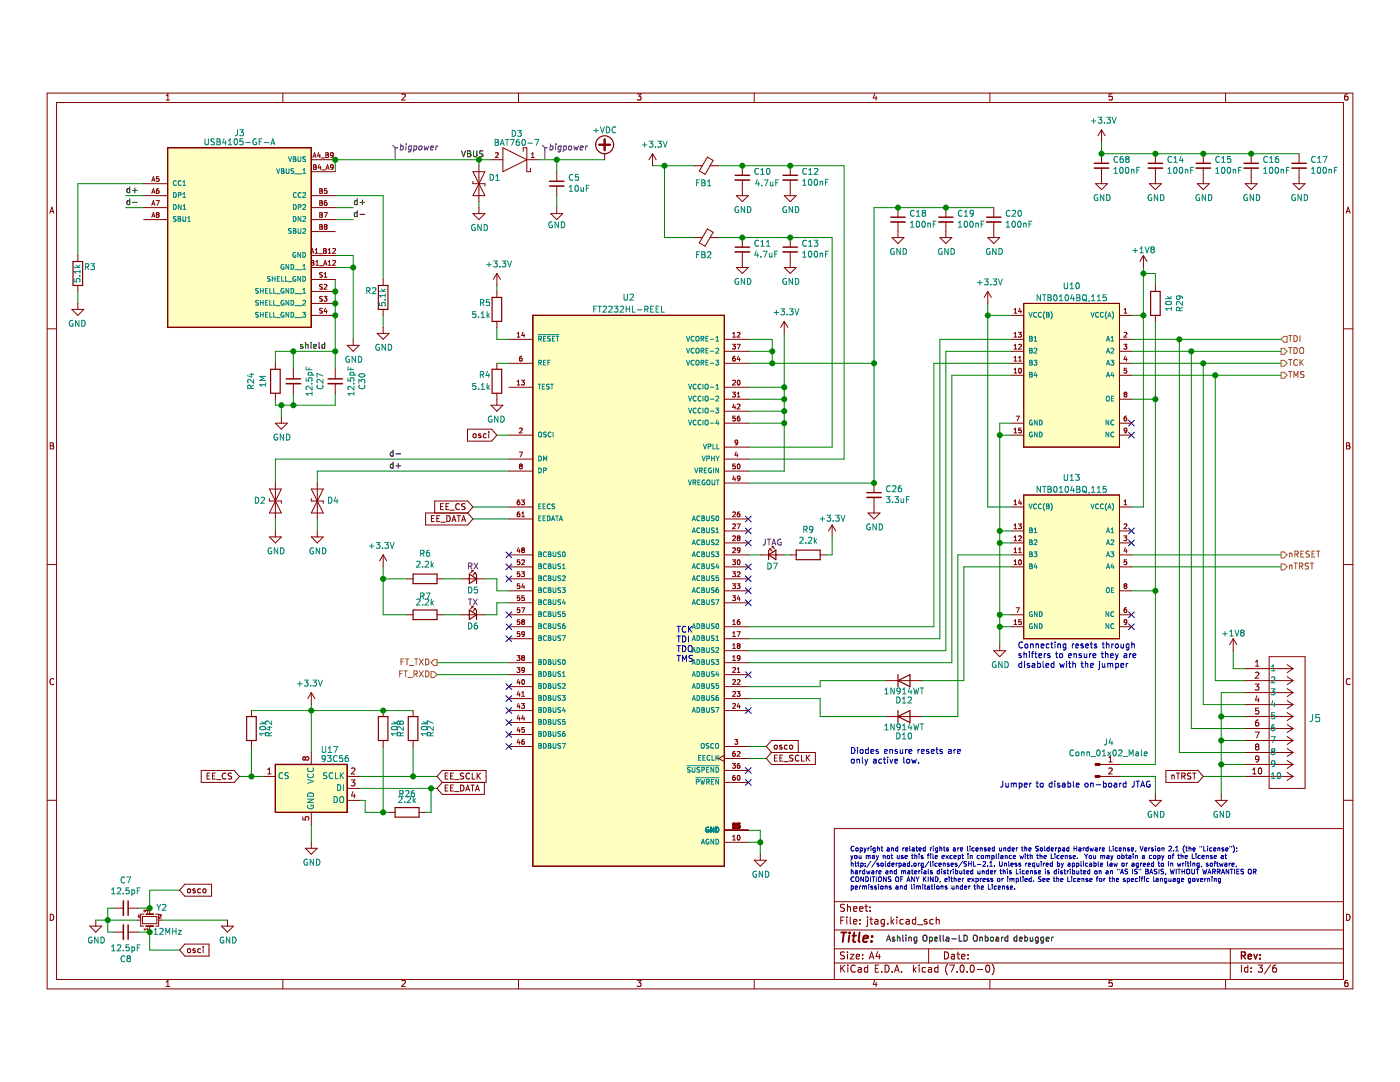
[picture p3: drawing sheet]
<svg xmlns="http://www.w3.org/2000/svg" width="279mm" height="216mm" viewBox="0 0 279 216" stroke-linecap="round" stroke-linejoin="round" font-family="sans-serif">
<path d="M0 9.2h279.4v206.7h-279.4z" fill-rule="evenodd" fill="#fff" stroke="#fff" stroke-width=".35"/>
<g fill="none" stroke="#840000" stroke-width=".2">
<path d="M9.4 18.6h260.6v178.7h-260.6zM33.2 20h.7M33.2 19.1l.3-.4v1.3M56.4 18.6v1.9M80.2 18.9l.5-.2 .2 .4-.8 .9h.8M103.5 18.6v1.9M127.2 18.7h.7l-.4 .5 .4 .1v.6l-.2 .1-.5-.1M150.5 18.6v1.9M174.6 18.7l-.3 .9h.7M174.9 19.2v.8M197.6 18.6v1.9M221.9 18.7h-.5l-.1 .6h.6v.6l-.1 .1-.5-.1"/>
<path d="M244.6 18.6v1.9M268.9 18.7l-.3 .1-.2 .2-.1 .7 .3 .3 .4-.1-.1-.6-.3-.1-.3 .2M11.3 20.5h256.8v174.9h-256.8zM28.7 36.7h4.8M28.7 39h4.8M30.3 36.2l.3-1 .3 1M30.3 38.6l.3-1 .3 1M30.4 35.9h.4M30.4 38.3h.4M31.7 37.6l-.5 .3v.5l.2 .2 .3-.1v-.5h-.3l-.2 .2M31.7 35.2h-.5v.5h.5v.4h-.5M62.1 34.3h4.8"/>
<path d="M62.1 31.9h4.8M62.1 39h4.8M62.4 31.4l.4-.9 .3 .9M62.5 31.2h.5M62.6 32.9h.3l.2 .1-.2 .3 .2 .3-.2 .2h-.3zM62.6 33.3h.3M63.6 30.4l-.2 .7h.5M63.7 32.8l-.2 .7h.6M63.8 30.8v.6M63.8 37.6h.3l.2 .2-.2 .3 .3 .3-.2 .2h-.4zM63.8 38.1h.3M63.9 33.2v.6"/>
<path d="M64.1 31.5h.7M64.2 33.9h.7M65 33.8l.4-.9 .3 .9M65 30.5h.4l.1 .2-.1 .2 .2 .3-.2 .2h-.4zM65 30.9h.4M65.1 33.5h.5M65.2 37.6h-.4l-.1 .5 .5-.1v.5h-.5M66.5 33.3l-.2 .1h-.3v-.5h.3l.2 .1v.6l-.5 .2M66.5 30.9l-.2 .2-.3-.1v-.4l.3-.1 .2 .2v.5l-.5 .2M94.4 36.2v.5h2.4v.4M94.4 34.3h2.4l-2.4 4.7h2.4zM95.6 33.1v7.1"/>
<path d="M98 31.9h2.4M98.9 30.6l.4-.1 .1 .2-.6 .7h.6M100.4 29.5l4.7 2.4-4.7 2.4zM104.4 30.2v-.7h.7v4.8h.8v-.8M105.1 31.9h2.4M106.1 31.4h.5M106.1 30.7l.2-.2v.9M111.1 34.3v1.9M111.1 37.1v1.9M120.7 30.7v1.2M130.2 30.7l-.7 1.2M130.2 30.7v2.4"/>
<path d="M130.2 30.7l.7 1.2M138.6 33.1h1.5M141.2 31.3l1.1 .7-1.6 2.8-1.1-.7zM141.7 33.1h1.7M147 39h2.3l-1.2 1.2zM148.1 33.1v1.9M148.1 35.9v3.1M156.5 39h2.4l-1.2 1.2zM157.7 33.1v1.9M157.7 35.9v3.1M218.6 36.7h2.4l-1.2 1.1zM219.8 25.9l-.7 1.2"/>
<path d="M219.8 25.9v2.4M219.8 30.7v1.9M219.8 33.5v3.2M219.8 25.9l.7 1.2M229.4 36.7h2.4l-1.2 1.1zM230.6 30.7v1.9M230.6 33.5v3.2M238.9 36.7h2.4l-1.2 1.1zM240.1 30.7v1.9M240.1 33.5v3.2M248.5 36.7h2.4l-1.2 1.1zM249.7 30.7v1.9"/>
<path d="M249.7 33.5v3.2M258.1 36.7h2.4l-1.2 1.1zM259.3 30.7v1.9M259.3 33.5v3.2M9.9 42.5l.5-1.2 .4 1.2M10.1 42.2h.5M15.5 51v1.2M15.5 57v1.2M28.7 41.4h4.8M28.7 43.8h4.8M30.3 41l.3-1 .3 1M30.3 43.4l.3-1 .3 1"/>
<path d="M30.4 40.7h.4M30.4 43.1h.4M31.2 40h.6l-.4 1M31.4 42.8l-.2-.2 .2-.2 .3 .2-.1 .2M31.4 42.8l-.2 .2 .2 .4 .3-.2-.1-.4M31.4 42.8h.2M62 50.5l.3-.9 .3 .9M62.1 50.3h.4M62.1 51h4.8M62.1 52h.3l.2 .2-.2 .2 .3 .3-.2 .2h-.4zM62.1 41.4h4.8M62.1 43.8h4.8"/>
<path d="M62.1 53.4h4.8M62.1 52.4h.3M62.1 46.2h4.8M62.1 55.8h4.8M62.1 58.2h4.8M62.9 50.5h.5M62.9 49.9l.3-.3v.9M63 52.9h.6M63 52.2l.3-.2v.9M63.6 50.6h.8M63.8 53h.7M63.8 40h.3l.2 .2-.2 .3 .3 .3-.2 .2h-.4z"/>
<path d="M63.8 42.4h.3l.2 .2-.2 .3 .3 .3-.2 .2h-.4zM63.8 44.8h.3l.2 .2-.2 .3 .3 .3-.2 .2h-.4zM63.8 40.5h.3M63.8 42.9h.3M63.8 45.3h.3M64.3 54.4l-.5 .1a.4 .4 0 0 0 .5 .5l-.1 .3h-.4M64.3 56.8h-.5a.4 .4 0 0 0 .5 .5l-.1 .4h-.4M64.3 59.2h-.5a.4 .4 0 0 0 .5 .5l-.1 .4h-.4M64.6 52.9l.3-.9 .3 .9M64.6 49.6h.3l.2 .2-.2 .2 .2 .4-.2 .1h-.3zM64.6 50h.3M64.7 59.1h.5l-.3 .4 .3 .1v.4h-.5"/>
<path d="M64.7 42.4h.6l-.4 1M64.7 52.7h.4M64.7 56.8h.4l.1 .2-.5 .7h.5M64.7 55.3h.5M64.7 54.6l.3-.2v.9M64.9 45.2l-.2-.2 .2-.2 .4 .2-.2 .2M64.9 45.2l-.2 .2 .2 .4 .4-.2-.2-.4M64.9 45.2h.2M65.2 40l-.4 .3-.1 .5 .2 .2 .3-.1v-.5h-.3l-.2 .2M65.5 50.5h.5M65.5 49.9l.3-.3v.9M65.5 52.2l.3-.2v.9"/>
<path d="M65.5 52.9h.5M66.4 49.7l.4-.1 .2 .3-.6 .6h.6M66.4 52.1l.4-.1 .2 .2-.6 .7h.6M76.5 55.8v1.2M94.4 42.6h2.4l-1.2 1.2zM95.6 41.4v1.2M99.2 54.6v2.4M99.2 58.2v1.2M99.2 54.6l-.8 1.2M99.2 54.6l.7 1.2M109.9 42.6h2.4l-1.2 1.2zM111.1 41.4v1.2"/>
<path d="M138.6 47.4h1.5M141.2 45.7l1.1 .7-1.6 2.7-1.1-.6zM141.7 47.4h1.7M147 53.4h2.3l-1.2 1.2zM148.1 47.4v1.9M148.1 50.3v3.1M156.5 53.4h2.4l-1.2 1.2zM157.7 47.4v1.9M157.7 50.3v3.1M178 47.4h2.4l-1.2 1.2zM179.2 41.4v1.9M179.2 44.3v3.1"/>
<path d="M187.6 47.4h2.4l-1.2 1.2zM188.8 41.4v1.9M188.8 44.3v3.1M197.1 47.4h2.4l-1.2 1.2zM197.1 58.2l-.7 1.2M197.1 58.2v2.3M197.1 58.2l.7 1.2M198.3 41.4v1.9M198.3 44.3v3.1M228.2 51l-.7 1.2M228.2 51v2.4M228.2 51l.7 1.2"/>
<path d="M230.6 57v1.2M268.6 42.5l.5-1.2 .4 1.2M268.8 42.2h.5M9.4 65.6h1.9M14.3 61.7h2.4l-1.2 1.2zM15.5 60.5v1.2M55 72.5v1.2M55 78.5v1.2M58.5 73.7v1.9M58.5 76.6v1.9M62.1 60.5h4.8M62.1 62.9h4.8"/>
<path d="M64.3 61.6h-.5a.4 .4 0 0 0 .5 .5l-.1 .3h-.4M64.9 61.5l-.2 .7h.6M65.2 61.9v.6M66.9 73.7v1.9M66.9 76.6v1.9M69.3 68.9h2.4l-1.2 1.2zM70.5 67.7v1.2M75.3 66.5h2.4l-1.2 1.2zM76.5 61.7v1.2M76.5 65.3v1.2M99.2 64.1v1.2M99.2 72.5v1.2"/>
<path d="M99.2 78.5v2.4M101.6 67.7h4.7M101.6 77.3h4.7M101.6 72.5h4.7M103.2 66.6l.3-.3v1M103.2 76.1l.3-.2v.9M103.2 67.3h.6M103.2 76.8h.6M104.1 75.9h.6l-.3 .3 .2 .1v.4h-.5M104.1 71.1l-.4 .2v.6l.2 .1h.3l-.1-.5h-.2l-.2 .1M104.4 66.3l-.3 .6h.6M104.6 66.6v.7"/>
<path d="M144.6 67.7h4.7M144.6 77.3h4.7M144.6 79.7h4.7M144.6 70.1h4.7M144.6 72.5h4.7M146.2 68.7h.6l-.3 .4 .2 .1v.4h-.5M146.2 78.3h.6l-.3 .3 .2 .1v.4h-.5M146.2 66.6l.3-.3v1M146.2 67.3h.6M146.2 76l.4-.1 .2 .2-.6 .7h.6M146.7 71.1l-.4 .2-.1 .6 .2 .1h.3v-.5h-.3l-.2 .1M147.1 68.7h.6l-.4 1"/>
<path d="M147.1 66.4l.4-.1 .2 .3-.6 .7h.6M147.1 78.5l.3-.2v.9M147.1 79.2h.6M147.2 76l.2-.1a.46 .46 0 0 1 .3 .5 .46 .46 0 0 1-.4 .4l-.2-.3zM147.4 71l-.3 .7h.6M147.6 71.4v.6M156.5 64.1l-.7 1.2M156.5 64.1v2.4M156.5 64.1l.7 1.2M201.9 62.9h2.4M201.9 67.7h2.4M201.9 70.1h2.4"/>
<path d="M201.9 72.5h2.4M201.9 74.9h2.4M202.4 62.5h.5M202.4 67.3h.5M202.4 69.7h.5M202.4 72h.5M202.4 61.8l.3-.3v1M202.4 66.6l.3-.3v1M202.4 69l.3-.3v1M202.4 71.4l.3-.3v.9M202.4 73.8l.3-.3v.9M202.4 74.4h.5"/>
<path d="M203.2 66.3h.6l-.3 .4 .3 .1v.4h-.6M203.3 68.8l.4-.1 .1 .3-.6 .7h.6M203.3 72h.5M203.3 71.4l.3-.3v.9M203.4 73.6l.1-.1a.46 .46 0 0 1 .4 .5 .46 .46 0 0 1-.5 .4l-.1-.3zM203.5 61.5l-.2 .7h.6M203.7 61.9v.6M204.3 60.5h19.1v28.7h-19.1zM223.4 62.9h2.4M223.4 67.7h2.4M223.4 79.7h2.4M223.4 70.1h2.4"/>
<path d="M223.4 72.5h2.4M223.4 74.9h2.4M224.3 68.7h.6l-.3 .4 .2 .1v.4h-.5M224.3 62.5h.6M224.3 66.4l.4-.1 .2 .3-.6 .7h.6M224.3 61.8l.3-.3v1M224.5 78.7l-.2-.2 .2-.2 .4 .1-.2 .3M224.5 78.7l-.2 .1 .2 .4 .4-.2-.2-.3M224.5 78.7h.2M224.6 71l-.3 .7h.6M224.8 71.4v.6M224.8 73.5h-.4l-.1 .4h.5v.4h-.5"/>
<path d="M230.6 62.9v1.2M268.1 65.6h1.9M10 88.4h.4l.3 .2-.3 .3 .3 .2v.3l-.2 .2h-.5zM10 88.9h.4M53.8 99.5v.5h2.4v.4M53.8 97.6h2.4l-2.4 4.8h2.4zM55 96.4v7.2M55 84.4h2.3l-1.1 1.2zM56.2 83.2v1.2M62.1 99.5v.5h2.4v.4M62.1 97.6h2.4l-2.4 4.8h2.4zM63.3 96.4v7.2"/>
<path d="M93.3 85.6h4.8l1.1 1.2-1.1 1.2h-4.8zM94.5 86.7l.1-.1 .4 .1-.1 .6-.4-.1zM95.9 86.6h-.2l-.2 .1v.2l.4 .1v.3h-.4M97 86.6h-.3l-.2 .2 .1 .5h.4M97.5 86.2v.1M97.5 86.6v.8M98 80.9h2.4l-1.2 1.2zM101.6 86.8h4.7M101.6 91.6h4.7M101.6 94h4.7M103.6 90.2h.7l-.4 1M103.7 85.5l.3-.1 .2 .3-.6 .7h.6"/>
<path d="M103.7 99.8l-.4 .2-.1 .5 .2 .2 .3-.1v-.4l-.3-.1-.2 .2M103.7 92.8h.1M103.7 92.8l.2-.2 .3 .2M103.7 92.8l.2 .2M103.9 93l-.2 .2 .2 .4 .3-.2-.2-.4M103.9 93h.1M104.1 99.8h.6l-.3 .3 .2 .1v.4h-.5M104.2 92.8h.1M104.2 92.8l-.2 .2M144.6 89.2h4.7M144.6 84.4h4.7M144.6 91.6h4.7"/>
<path d="M144.6 82.1h4.7M144.6 96.4h4.7M144.6 94h4.7M146.5 80.6l-.3 .7h.6M146.5 94.9l-.3 .7h.6M146.7 81v.6M146.7 95.3v.6M146.7 83h-.4l-.1 .5 .5-.1v.5h-.5M146.7 92.6h-.4l-.1 .4h.5v.5h-.5M146.9 90.2l-.2 .6h.6M147.1 80.7l.4-.1 .2 .3-.6 .7h.6M147.1 90.5v.7"/>
<path d="M147.2 92.7l.2-.1a.46 .46 0 0 1 .3 .5 .46 .46 0 0 1-.4 .4l-.2-.3zM147.2 88.2l-.2 .2h-.2l-.1-.5 .3-.1 .2 .2v.5l-.4 .3M147.6 83l-.4 .3-.1 .5 .2 .2 .3-.1v-.5h-.3l-.2 .2M147.7 95.4l-.2 .2-.3-.1v-.4l.3-.1 .2 .2-.1 .5-.4 .2M174.4 96.4v1.9M174.4 99.3v3.1M201.9 84.4h2.4M201.9 86.8h2.4M202.4 86.4h.5M202.4 85.7l.3-.3v1M202.8 83h.6l-.4 1M203.3 86.3h.1"/>
<path d="M203.5 99.7l-.2 .7h.6M203.8 85.4h-.5v.5l.4-.1 .1 .2-.1 .3h-.4M204.3 98.8h19.1v28.7h-19.1zM223.4 84.4h2.4M223.4 86.8h2.4M224.8 83l-.4 .3v.6h.4v-.4M224.8 83.4h-.3l-.2 .2M224.8 83.4v.1M224.9 85.8l-.2 .2h-.3v-.5l.3-.1 .2 .2-.1 .6-.4 .2M268.7 88.4h.4l.3 .2-.3 .3 .3 .2v.3l-.2 .2h-.5zM268.7 88.9h.4M9.4 112.7h1.9"/>
<path d="M53.8 107.1h2.4l-1.2 1.2zM55 105.9v1.2M62.1 107.1h2.4l-1.2 1.2zM63.3 105.9v1.2M76.5 110.7v2.4M76.5 110.7l.7 1.2M76.5 110.7l-.8 1.2M81.2 115.5h1.2M84.9 102.4h8.4l1.1 1.2-1.1 1.2h-8.4zM86.1 103.5h.4M86.7 102.9h-.6v1.2h.6M86.8 102.4v-2.4h6.5l1.1 1.2-1.1 1.2"/>
<path d="M87.2 103.5h.4M87.2 115.5h1.2M87.8 102.9h-.6v1.2h.6M87.9 101.1h.4M88 104.2h.9M88.5 100.5h-.6v1.2h.6M89 101.1h.4M89.2 102.9a.6 .6 0 0 1 .7 .6 .6 .6 0 0 1-.7 .6zM89.6 100.5h-.6v1.2h.6M89.8 101.8h.9M90.2 104.1l.4-1.2 .4 1.2M90.3 103.7h.6"/>
<path d="M91.2 102.9h.7M91.6 102.9v1.2M91.7 100.6a.53 .53 0 0 0-.8 .5 .53 .53 0 0 0 .8 .5M92 115.5h4.8M92.1 104.1l.4-1.2 .4 1.2M92.2 103.7h.6M92.8 100.6h-.6v.4l.5 .2 .1 .3-.2 .2-.5-.1M94.1 113.8h.3M94.4 113.8v.3M94.4 113.8l-.5 .5M94.6 114.3h.3M94.9 114.3v.2"/>
<path d="M94.9 114.3l-.5 .5M101.6 115.5h4.7M101.6 103.6h4.7M101.6 110.7h4.7M101.6 113.1h4.7M101.6 117.9h4.7M101.6 101.2h4.7M103.4 109.3l-.2 .7h.6M103.7 102.2l-.4 .2-.1 .5 .2 .2 .3-.1v-.4l-.3-.1-.2 .2M103.7 109.6v.7M103.7 111.7h-.4l-.1 .5 .5-.1v.5h-.5M103.7 116.5h-.4l-.1 .4h.5v.5h-.5"/>
<path d="M103.7 118.9h-.4l-.1 .4h.5v.4h-.5M103.7 114.1h-.4l-.1 .5 .5-.1v.5h-.5M104.1 114.1h.6l-.3 .4 .2 .1v.4h-.5M104.1 111.8l.4-.1 .2 .3-.6 .7h.6M104.1 103.1h.6M104.1 102.4l.3-.2v.9M104.3 109.7l-.2-.2 .2-.2 .4 .2-.2 .2M104.3 109.7l-.2 .2 .2 .4 .4-.2-.2-.4M104.3 109.7h.2M104.4 116.4l-.3 .7h.6M104.6 116.8v.6M104.6 118.9h-.4l-.1 .4h.5v.4h-.5"/>
<path d="M144.6 115.5h4.7M144.6 103.6h4.7M144.6 105.9h4.7M144.6 108.3h4.7M144.6 110.7h4.7M144.6 113.1h4.7M144.6 117.9h4.7M146.2 111.7h.6l-.3 .4 .2 .1v.4h-.5M146.2 114.1h.6l-.3 .4 .2 .1v.4h-.5M146.2 116.5h.6l-.3 .4h.2v.5h-.5M146.2 118.9h.6l-.3 .3 .2 .1v.4h-.5M146.2 109.4l.4-.1 .2 .3-.6 .7h.6"/>
<path d="M146.2 102.2h.4l.2 .2-.6 .7h.6M146.2 104.6l.4-.1 .2 .3-.6 .7h.6M146.2 107l.4-.1 .2 .3-.6 .7h.6M147.1 116.5h.6l-.3 .4h.2v.5h-.5M147.1 104.5h.6l-.4 1M147.1 114.2l.4-.1 .2 .3-.6 .7h.6M147.2 111.8l.2-.1a.46 .46 0 0 1 .3 .5 .46 .46 0 0 1-.4 .4l-.2-.3zM147.3 107.3l-.2-.1 .2-.3 .4 .2-.2 .2M147.3 107.3l-.2 .2 .2 .4 .4-.2-.2-.4M147.3 107.3h.2M147.4 118.8l-.3 .7h.6M147.6 102.2l-.4 .2-.1 .5 .2 .2 .3-.1v-.4l-.3-.1-.2 .2"/>
<path d="M147.6 119.2v.6M147.7 109.7l-.2 .2h-.3v-.5l.3-.1 .2 .2-.1 .5-.4 .3M151.7 110.7h4.8M153.6 109.5l.5 .5M153.6 109.5h.3M153.6 109.5v.3M154.1 109.1l.5 .4M154.1 109.1h.3M154.1 109.1v.2M157.7 110.7h1.2M163.7 110.7h1.2M166.1 104.8l-.7 1.1"/>
<path d="M166.1 104.8v2.3M166.1 104.8l.7 1.1M173.2 102.4h2.4l-1.2 1.2zM201.9 105.9h2.4M201.9 108.3h2.4M201.9 110.7h2.4M201.9 113.1h2.4M201.9 101.2h2.4M202.4 112.7h.5M202.4 105.5h.5M202.4 107.9h.5M202.4 110.3h.5"/>
<path d="M202.4 100.7h.5M202.4 100l.3-.2v.9M202.4 104.8l.3-.3v1M202.4 107.2l.3-.3v1M202.4 109.6l.3-.3v1M202.4 112l.3-.3v1M203.2 104.5h.6l-.3 .4 .3 .1v.4h-.6M203.3 107l.4-.1 .1 .3-.6 .7h.6M203.3 110.3h.5M203.3 109.6l.3-.3v1M203.4 111.8l.1-.1a.46 .46 0 0 1 .4 .5 .46 .46 0 0 1-.5 .4l-.1-.3zM203.7 100.1v.6"/>
<path d="M223.4 105.9h2.4M223.4 108.3h2.4M223.4 110.7h2.4M223.4 113.1h2.4M223.4 117.9h2.4M223.4 101.2h2.4M224.3 106.9h.6l-.3 .4 .2 .1v.4M224.3 107.8h.5M224.3 104.6l.4-.1 .2 .3-.6 .7h.6M224.3 100.7h.6M224.3 100l.3-.2v.9M224.5 116.9l-.2-.2 .2-.2 .4 .2-.2 .2"/>
<path d="M224.5 116.9l-.2 .2 .2 .3 .4-.1-.2-.4M224.5 116.9h.2M224.6 109.3l-.3 .7h.6M224.8 109.6v.7M224.8 111.7h-.4l-.1 .5 .5-.1v.5h-.5M224.8 107.8h.1M268.1 112.7h1.9M10.7 135.5a.54 .54 0 0 0-.7 .5 .54 .54 0 0 0 .7 .5M62.1 138.2v2.4M62.1 138.2l.7 1.2M62.1 138.2l-.7 1.2M81.2 122.7h1.2"/>
<path d="M87.2 122.7h1.2M92 122.7h4.8M94.1 121h.3M94.4 121v.2M94.4 121l-.5 .5M94.6 121.5h.3M94.9 121.5l-.5 .5M94.9 121.5v.2M101.6 127.5h4.7M101.6 122.7h4.7M101.6 125.1h4.7M101.6 132.2h4.7"/>
<path d="M101.6 134.6h4.7M101.6 137h4.7M101.6 139.4h4.7M101.6 120.3h4.7M103.2 130.8h.6l-.4 .4 .3 .1v.4h-.5M103.2 133.2h.6l-.4 .4 .3 .1v.4h-.5M103.4 135.6l-.2 .6h.6M103.4 137.9l-.2 .7h.6M103.7 135.9v.7M103.7 138.3v.7M103.7 126h-.4l-.1 .5h.5v.4h-.5M103.7 123.7h-.4l-.1 .4h.5v.4h-.5"/>
<path d="M103.7 121.3h-.4l-.1 .4h.5v.4h-.5M104.1 121.3h.6l-.4 .9M104.1 139h.6M104.1 138.3l.3-.3v1M104.2 135.7l.2-.1a.46 .46 0 0 1 .3 .5 .46 .46 0 0 1-.4 .4l-.2-.3zM104.3 124.1l-.2 .1 .2 .4 .4-.2-.2-.3M104.3 131.2l-.2-.1 .2-.3 .4 .2-.2 .2M104.3 124.1l-.2-.2 .2-.2 .4 .1-.2 .3M104.3 131.2l-.2 .2 .2 .4 .4-.2-.2-.4M104.3 131.2h.2M104.3 124.1h.2M104.7 126.5l-.2 .1h-.3v-.5l.3-.1 .2 .2-.1 .6-.4 .2"/>
<path d="M104.7 133.6l-.2 .2h-.3v-.5l.3-.1 .2 .2-.1 .5-.4 .3M144.6 127.5h4.7M144.6 125.1h4.7M144.6 129.8h4.7M144.6 132.2h4.7M144.6 134.6h4.7M144.6 137h4.7M144.6 139.4h4.7M144.6 120.3h4.7M146.2 138.1l.4-.1 .2 .3-.6 .7h.6M146.2 123.9l.3-.2v.9M146.2 126.3l.3-.3v1"/>
<path d="M146.2 128.7l.3-.3v1M146.2 131.1l.3-.3v1M146.2 124.6h.6M146.2 127h.6M146.2 129.4h.6M146.2 131.8h.6M146.2 133.3l.4-.1 .2 .3-.6 .7h.6M146.2 135.7l.4-.1 .2 .3-.6 .7h.6M147.1 138h.6l-.3 .4h.2v.5h-.5M147.1 126h.6l-.4 1M147.1 135.7l.4-.1 .2 .3-.6 .7h.6M147.1 133.5l.3-.3v1"/>
<path d="M147.1 134.2h.6M147.3 128.8l-.2 .2 .2 .4 .4-.2-.2-.4M147.3 128.8l-.2-.1 .2-.3 .4 .2-.2 .2M147.3 128.8h.2M147.6 123.7l-.4 .2-.1 .5 .2 .2 .3-.1v-.4l-.3-.1-.2 .2M147.7 131.2l-.2 .2h-.3v-.5l.3-.1 .2 .2-.1 .6-.4 .2M176.8 135.8h7.2M198.3 129.8h2.4l-1.2 1.2zM199.5 128.6v1.2M201.9 122.7h2.4M201.9 125.1h2.4M202.4 124.6h.5"/>
<path d="M202.4 123.9l.3-.2v.9M202.8 121.3h.6l-.4 .9M203.8 123.7h-.5v.4h.4l.1 .4h-.5M223.4 122.7h2.4M223.4 125.1h2.4M224.8 124.2h-.4v-.5h.3l.2 .1-.1 .6-.4 .2M224.8 121.3l-.4 .2-.1 .5 .2 .2 .3-.1v-.4l-.3-.1-.2 .2M224.8 124.2h.1M224.9 124.1l-.1 .1M246.1 127.5l-.7 1.1M246.1 127.5v2.3M246.1 127.5l.7 1.1"/>
<path d="M248.5 135.8h9.6M248.5 138.2h9.6M248.5 133.4h9.6M250.5 136.5h.7l-.4 .5 .4 .1v.5l-.2 .1-.5-.1M250.6 134.2l.4-.1 .2 .4-.7 .8h.7M250.6 132.9h.6M250.6 132.1l.3-.4v1.2M250.8 138.8l-.2 .9h.7M251.1 139.3v.8M253.3 131h7.2v26.3h-7.2zM256.9 139.8l1.2 .8M256.9 137.4l1.2 .8"/>
<path d="M256.9 135l1.2 .8M256.9 132.6l1.2 .8M258.1 138.2l-1.2 .8M258.1 135.8l-1.2 .8M258.1 133.4l-1.2 .8M269.4 135.5a.54 .54 0 0 0-.7 .5 .54 .54 0 0 0 .7 .5M9.4 159.7h1.9M40.2 153.7h6.5l1.1 1.2-1.1 1.2h-6.5zM41.3 154.8h.4M41.9 154.3h-.6v1.2h.6M42.4 154.8h.4M43 154.3h-.6v1.2h.6"/>
<path d="M43.2 155.6h.9M45.1 154.4a.53 .53 0 0 0-.8 .5 .53 .53 0 0 0 .8 .4M46.2 154.3l-.6 .1v.3l.5 .2 .1 .3-.2 .3-.5-.1M50.2 141.8v1.2M50.2 147.8v1.2M52.6 154.9h2.4M53.4 153.6l.4-.4v1.2M53.4 154.4h.7M60.9 151.2l-.2-.2-.3 .2v.3l.3 .2 .2-.2M60.9 151.2l.3-.2h.2l.2 .2v.3l-.2 .2-.3-.1-.2-.1M60.9 151.2v.3M62.1 150.1v2.4"/>
<path d="M69.3 159.7h2.4M69.3 154.9h2.4M69.3 157.3h2.4M70.1 155.6h.7l-.4 .5 .4 .1v.5l-.2 .1-.5-.1M70.1 153.3l.5-.1 .2 .4-.7 .8h.7M70.4 158l-.3 .8h.8M70.7 158.4v.8M76.5 141.8v1.2M76.5 147.8v1.2M82.4 141.8v1.2M82.4 147.8v1.2M88.3 153.7h8.7v2.4h-8.7l-1.1-1.2z"/>
<path d="M88.3 156.1l-1.1 1.2 1.1 1.2h8.4v-2.4M88.8 154.8h.4M88.8 157.2h.4M89.4 154.3h-.6v1.2h.6M89.4 156.6h-.6v1.2h.6M89.9 154.8h.4M89.9 157.2h.4M90.5 154.3h-.6v1.2h.6M90.5 156.6h-.6v1.2h.6M90.7 155.6h.9M90.7 158h.9M91.9 156.6a.6 .6 0 0 1 .7 .6 .6 .6 0 0 1-.7 .6z"/>
<path d="M92.5 154.3l-.6 .1v.3l.5 .2 .1 .3-.2 .3-.4-.1M92.9 157.8l.4-1.2 .4 1.2M93.1 157.5h.5M93.7 154.4a.53 .53 0 0 0-.7 .5 .53 .53 0 0 0 .7 .4M94 156.6h.6M94.3 154.3v1.2h.5M94.3 156.6v1.2M94.9 157.8l.4-1.2 .4 1.2M95 157.5h.6M95.2 154.3v1.2M95.4 154.8l.5 .7M95.9 154.3l-.7 .6"/>
<path d="M101.6 141.8h4.7M101.6 149h4.7M101.6 144.2h4.7M101.6 146.6h4.7M103.4 140.3l-.2 .7h.6M103.4 142.7l-.2 .7h.6M103.4 145.1l-.2 .7h.6M103.4 147.5l-.2 .7h.6M103.7 140.7v.6M103.7 143.1v.6M103.7 145.5v.6M103.7 147.9v.6"/>
<path d="M104.1 140.4h.6l-.3 .3 .2 .1v.4h-.5M104.4 142.7l-.3 .7h.6M104.6 147.6l-.4 .2-.1 .5 .2 .2 .3-.1v-.4l-.3-.1-.2 .2M104.6 143.1v.6M104.6 145.2h-.4l-.1 .4h.5v.4h-.5M144.6 156.1h4.7M144.6 153.7h4.7M144.6 141.8h4.7M144.6 149h4.7M144.6 151.3h4.7M144.6 150.7l-1.2 .6 1.2 .6M146.2 152.3h.6l-.3 .4 .2 .1v.4h-.5"/>
<path d="M146.2 140.5l.4-.1 .2 .3-.6 .6h.6M146.6 147.6h.6l-.3 .3 .3 .1v.4h-.6M146.7 154.7l-.4 .2-.1 .6 .2 .2 .3-.1v-.5h-.3l-.2 .2M146.7 149.9l-.4 .3-.1 .5 .2 .2 .3-.1v-.4l-.3-.1-.2 .2M147.1 150l.4-.1 .2 .3-.6 .7h.6M147.2 154.8l.2-.1a.46 .46 0 0 1 .3 .5 .46 .46 0 0 1-.4 .4l-.2-.3zM147.4 140.3l-.3 .7h.6M147.6 152.3l-.4 .3-.1 .5 .2 .2 .3-.1v-.5h-.3l-.2 .2M147.6 140.7v.6M154 150.1h8.7v2.4h-8.7l-1.1-1.2zM154 150.2l-1.1-1.2 1.1-1.2h5.3v2.4M154.6 151.2h.4"/>
<path d="M154.6 148.8l.1-.1 .4 .1-.1 .6h-.4zM155.1 150.7h-.5v1.2h.5M155.6 151.2h.4M156 148.7h-.2l-.2 .2v.1l.4 .1v.3h-.4M156.2 150.7h-.6v1.2h.6M156.4 152h.9M157.1 148.7h-.3l-.3 .2 .2 .5h.4M157.6 148.8l.2-.1 .3 .1v.6h-.5zM158.3 150.7l-.7 .1v.3l.5 .3 .2 .2-.3 .3-.4-.1M159.4 150.8a.53 .53 0 0 0-.7 .5 .53 .53 0 0 0 .7 .5M160 150.7v1.2h.5M160.9 150.7v1.2"/>
<path d="M161.1 151.2l.5 .7M161.6 150.7l-.7 .7M176.8 143h7.2M218.6 154.8h.9v.2h-.9zM218.6 152.4h.9v.3h-.9zM219.5 152.5h3.9M219.5 154.9h3.9M221.3 153.3l.4-.1 .3 .4-.8 .8h.8M221.3 152h.7M221.3 151.2l.3-.4v1.2M229.4 159.7h2.4l-1.2 1.2zM230.6 158.5v1.2"/>
<path d="M232.7 153.7h6.4l1 1.2-1 1.2h-6.4zM233.8 154.7v.8M233.8 154.8l.5-.1 .1 .8M234.8 154.3h.6M235.1 154.3v1.2M235.8 154.9l.6-.1 .1-.4-.7-.1v1.2M236.1 154.9l.4 .6M237.7 154.3l-.7 .1v.3l.5 .2 .2 .3-.3 .3-.4-.1M238 154.3h.7M238.3 154.3v1.2M242.5 159.7h2.4l-1.2 1.2zM243.7 158.5v1.2"/>
<path d="M248.5 152.5h9.6M248.5 150.1h9.6M248.5 147.8h9.6M248.5 154.9h9.6M248.5 143h9.6M248.5 145.4h9.6M248.5 140.6h9.6M250 154.4h.7M250 153.6l.3-.4v1.2M250.5 146.1h.8l-.5 1.2M250.8 149l-.2-.3 .2-.2h.2l.2 .2-.2 .3M250.8 149h.2"/>
<path d="M250.8 149l-.2 .2v.3l.2 .2h.2l.2-.3v-.3l-.2-.1M251.1 143.7h-.3l-.2 .3v.6l.2 .3 .4-.1-.1-.6-.3-.1-.2 .3M251.2 141.3h-.6v.6l.5-.1 .1 .6-.2 .1-.4-.1M251.2 153.3l.2-.1a.64 .64 0 0 1 .4 .6 .64 .64 0 0 1-.4 .6l-.3-.4zM251.2 151.4l-.2 .2-.3-.1-.1-.5 .4-.2 .2 .3v.7l-.2 .2h-.3M256.9 154.1l1.2 .8M256.9 151.7l1.2 .8M256.9 149.4l1.2 .7M256.9 147l1.2 .8M256.9 144.6l1.2 .8M256.9 142.2l1.2 .8M258.1 154.9l-1.2 .8"/>
<path d="M258.1 152.5l-1.2 .8M258.1 150.1l-1.2 .8M258.1 147.8l-1.2 .8M258.1 145.4l-1.2 .8M258.1 143l-1.2 .8M258.1 140.6l-1.2 .8M268.1 159.7h1.9M36.9 176.4h5.3v2.4h-5.3l-1.1-1.2zM37.5 177.5l.1-.1 .4 .1-.1 .6-.4-.1zM39 177.4h-.3l-.2 .1 .1 .2 .4 .1v.3h-.5M40 177.4h-.3l-.2 .2 .1 .5h.4M40.5 177.5l.2-.1 .4 .1-.1 .6-.5-.1z"/>
<path d="M60.4 163v.6h.6l-.1-.5 .6-.1 .1 .2-.1 .4M60.9 169.3h2.4l-1.2 1.2zM62.1 162.1v2.4M62.1 168.1v1.2M77.7 162.1h1.2M83.6 162.1h1.2M144.6 165.7h4.7M144.6 168.1h4.7M146.2 165.1l.2 .1M146.2 164.3h1.5l-.4 .9M146.2 167.6h.6M146.2 164.6l.3-.3v.9"/>
<path d="M146.2 166.9l.3-.2v.9M146.2 165.1l.1 .1M146.3 164.3l-.1 .4 .4-.1 .2 .2-.2 .4M146.4 164.3l-.2 .1M146.5 164.2l-.3 .7h.6M146.6 164.3l.2 .2-.1 .2M146.7 164.6l.3-.3v.9M146.7 164.6v.6M146.7 165.1l.1 .1M146.7 164.7h.5v.4l-.2 .1M146.7 164.7l-.5 .5h1.5M146.7 164.3v.4"/>
<path d="M146.8 164.3l-.3 .3M147.1 165.1l.2 .1M147.1 164.6l.3-.3v.9M147.2 164.3l-.1 .4 .4-.1 .2 .2-.2 .4M147.2 166.8l.2-.1a.46 .46 0 0 1 .3 .5 .46 .46 0 0 1-.4 .4l-.2-.3zM150.5 171.7h2.4l-1.2 1.1zM151.7 170.5v1.2M166.5 179.9h101.6M268.1 165.3h-101.6v30.1M10 182.4a.62 .62 0 0 1 .7 .6 .62 .62 0 0 1-.7 .7zM17.9 184.8h2.4l-1.2 1.2zM19.1 183.6v1.2"/>
<path d="M22.7 186h1.9M22.7 181.2h1.9M25.6 186h1.9M25.6 181.2h1.9M27.5 183.6h.6M27.7 182.5l-.1 .5h.4M27.9 182.7v.5M28.4 182.9h2.9v1.4h-2.9zM28.7 182.4h-.6v2.4h.6M29.1 181.7l-.1 .1-.2-.2v.4M29.1 181.6l.3 .1v.3M29.1 181.6v.1"/>
<path d="M29.5 185.2v.4M29.5 185.4h-.7l.2 .2M29.9 181.2v1.2M29.9 184.8v1.2M31.1 182.4h.6v2.4h-.6M31.7 183.6h.6M31.8 182.6l.2-.1 .2 .2-.5 .5h.5M33.2 196l.3-.4v1.2M33.2 196.8h.7M36.9 188.4h4.8v2.4h-4.8l-1.1-1.2zM37.5 189.4l.1-.1 .4 .1-.1 .6h-.4zM39 189.4l-.3-.1-.2 .2 .1 .1 .4 .2v.2h-.5"/>
<path d="M40 189.4l-.3-.1-.2 .2 .1 .5h.4M40.5 188.9v.1M40.5 189.3v.8M44.2 184.8h2.4l-1.2 1.2zM45.4 183.6v1.2M56.4 195.4v1.9M80.2 195.7l.5-.1 .2 .4-.8 .8h.8M103.5 195.4v1.9M127.2 195.6h.7l-.4 .5 .4 .1v.5l-.2 .1-.5-.1M150.5 195.4v1.9M166.5 192.2h101.6M166.5 189.3h101.6"/>
<path d="M166.5 185.6h101.6M167.8 183.7h.5M167.8 192.6v1.4M168 193.2l.6 .8M168.5 183h-.7v1.4M168.5 190l-.5-.1-.2 .2v.4l.6 .2 .1 .4-.2 .3-.6-.1M168.5 180.5l-.5-.1-.2 .2v.4l.6 .2 .1 .4-.2 .3-.6-.1M168.6 192.6l-.8 .8M169 183v.1M169 183.5v.9M169.1 180.4v1.5M169.1 189.9v.2"/>
<path d="M169.1 190.4v1M169.1 181l.2-.1 .4 .1v.9M169.2 192.6v.1M169.2 193v1M169.7 190.4h.7l-.7 1h.7M169.7 183v1.2l.2 .2M170.3 183.9l.7-.1-.1-.3h-.4l-.2 .2 .1 .6h.5M170.3 181.4l.7-.2-.1-.2-.4-.1-.2 .2 .1 .7h.5M170.7 192.7a.67 .67 0 0 0-1 .5 .67 .67 0 0 0 .7 .8l.3-.1M170.9 190.9l.7-.2-.1-.2-.4-.1-.2 .2v.7h.6M171.3 193.1h.5l.1 .9M171.6 181.4l.6-.2v-.2l-.4-.1-.2 .2v.7h.6"/>
<path d="M171.6 184.3v.1M171.6 183.5v.2M171.9 193.4h-.5l-.2 .3 .2 .3 .5-.1M172.2 190.5v.1M172.2 191.2v.2M172.6 180.9h.6M172.8 180.4v1.2l.4 .3M173.1 183v.1M173.1 183.5v1.2l-.2 .2M173.2 193.1l-.4-.1-.3 .3 .1 .6h.6M173.2 192.6v1.4M173.5 191.4l.4-1.5 .5 1.5"/>
<path d="M173.6 183.5h.5M173.6 190.9h.7M173.6 181.7v.2M173.6 181v.1M173.8 183v1.2l.3 .2M174.6 195.6l-.3 .8h.7M174.6 183.5h.6v.9M174.7 193.2h.5M174.9 196v.8M175.2 189.9l-.4 1h.9M175.2 183.8l-.4 .1-.2 .2 .2 .3 .4-.1M175.4 192.6h-.7v1.4h.7"/>
<path d="M175.5 190.4v1M176 193.9v.1M176.5 183.5h-.4l-.3 .2 .2 .6h.5M176.5 183.5v1.1l-.3 .3-.3-.1M176.6 192.6a.71 .71 0 0 1 .8 .7 .71 .71 0 0 1-.8 .7zM177.2 184.3v.1M177.8 183v1.4M178 183.9l.4 .5M178 193.9v.1M178.4 183.5l-.6 .5M178.5 194l.5-1.4 .5 1.4M178.6 193.6h.7"/>
<path d="M179 183v.1M179 183.5v.9M179.9 193.9v.1M180.3 183.5h-.4l-.3 .2 .1 .6h.6M180.9 183.5h.5l.1 .9M181.5 183.8l-.5 .1-.2 .2 .2 .3 .5-.1M182.3 192.6v1.4M182.4 193.4l.4 .6M182.7 183.5h-.4l-.2 .2 .1 .6h.5M182.7 183v1.4M182.8 193l-.5 .6M183.1 184.5h1.1"/>
<path d="M183.4 192.6v.1M183.4 193v1M184.7 193.1l-.4-.1-.3 .3 .2 .6h.5M185 183.5h-.4l-.2 .2 .1 .2 .5 .1v.3h-.6M185.3 193.1h.6v.9M185.3 189.3v2.9M185.9 193.4h-.5l-.2 .3 .2 .3 .5-.1M186.2 183.5h-.4l-.2 .2 .1 .6h.5M186.8 183.6l.2-.1h.4l.1 .9M186.8 183v1.4M187.2 193.1l-.4-.1-.3 .3 .2 .6h.5M187.2 192.6v1.4"/>
<path d="M188.5 189.9a.71 .71 0 0 1 .8 .7 .71 .71 0 0 1-.8 .8zM189.1 192.4a1.62 1.62 0 0 0 0 2.1M189.5 192.6h1l-.6 1.4M189.9 190.5h.5l.1 .9M190.5 190.7l-.5 .1-.2 .2 .2 .4 .5-.1M191 190.4h.5M191 193.9v.1M191.2 189.9v1.3l.3 .2M191.7 192.7l.2-.1a.75 .75 0 0 1 .5 .7 .75 .75 0 0 1-.5 .7l-.3-.6zM191.9 190.9l.7-.2-.1-.2-.4-.1-.2 .2 .1 .7h.5M193 193.9v.1M193.2 191.2v.2"/>
<path d="M193.2 190.5v.1M193.8 192.7l.2-.1a.75 .75 0 0 1 .4 .7 .75 .75 0 0 1-.4 .7l-.4-.6zM195 193.4h1.1M196.8 192.7l.2-.1a.75 .75 0 0 1 .5 .7 .75 .75 0 0 1-.5 .7l-.3-.6zM197.6 195.4v1.9M198 192.4a1.62 1.62 0 0 1 0 2.1M221.9 195.6h-.5l-.1 .6 .6-.1v.6l-.1 .1-.5-.1M244.6 195.4v1.9M245.5 189.3v6.1M247.8 192.6v1.4M249 193.1l-.4-.1-.2 .3 .1 .6h.5M249 192.6v1.4"/>
<path d="M249.7 193.9v.1M249.7 193.1v.1M251.1 192.6h.9l-.5 .5 .4 .1v.7l-.2 .1-.6-.1M253.6 192.5l-1.2 1.8M254.6 192.6h-.4a.95 .95 0 0 0 0 1.4l.5-.1 .1-.5-.3-.3-.4 .1-.1 .2M268.7 182.4a.62 .62 0 0 1 .7 .6 .62 .62 0 0 1-.7 .7zM268.9 195.6l-.3 .1-.2 .2-.1 .7 .3 .2 .4-.1-.1-.6h-.3l-.3 .2"/>
</g>
<path d="M247.8 190.7l.6-.1 .2-.2-.1-.3-.7-.2v1.5M248.1 190.7l.5 .7M249.1 190.9l.7-.2-.1-.2-.4-.1-.2 .2 .1 .7h.5M250.2 190.4l.4 1 .3-1M251.4 191.2v.2M251.4 190.5v.1" fill="none" stroke="#840000" stroke-width=".28"/>
<path d="M167.9 186.1h1.1M168.4 186.1l-.2 1.9M169.5 186.7l-.2 1.3M169.6 186.1v.1M170.1 186.7h.7M170.5 186.1l-.2 1.6v.2l.4 .1M171.6 186.1l-.2 1.6 .2 .3M172.3 187.3l.9-.2v-.3h-.8l-.2 .9 .3 .3 .5-.1M173.9 187.8v.2M174.1 186.8l-.1 .2" fill="none" stroke="#840000" stroke-width=".38"/>
<g fill="#ffffc2" stroke="#ffffc2" stroke-width=".35">
<path d="M33.5 29.5h28.6v35.8h-28.6z" fill-rule="evenodd"/>
<path d="M55 152.5h14.3v9.6h-14.3z" fill-rule="evenodd"/>
<path d="M106.3 62.9h38.3v109.9h-38.3z" fill-rule="evenodd"/>
<path d="M204.3 98.8h19.1v28.7h-19.1z" fill-rule="evenodd"/>
<path d="M204.3 60.5h19.1v28.7h-19.1z" fill-rule="evenodd"/>
</g>
<g fill="none" stroke="#840000" stroke-width=".24">
<path d="M33.5 29.5h28.6v35.8h-28.6zM14.6 52.2h1.9v4.8h-1.9zM75.5 57h1.9v4.7h-1.9zM98.2 59.4h1.9v4.7h-1.9zM229.6 58.2h1.9v4.7h-1.9zM54 73.7h1.9v4.8h-1.9zM98.2 73.7h1.9v4.8h-1.9zM106.3 62.9h38.3v109.9h-38.3zM82.4 114.5h4.8v2h-4.8zM93.7 114.5l1.4 1-1.4 1zM95.1 114.5v2M153.4 109.8v1.9"/>
<path d="M153.4 110.7l1.4-.9v1.9zM158.9 109.8h4.8v1.9h-4.8zM82.4 121.7h4.8v1.9h-4.8zM93.7 121.7l1.4 1-1.4 .9zM95.1 121.7v1.9M179.2 134.6v2.4M179.2 135.8l2.4-1.2v2.4zM49.2 143h1.9v4.8h-1.9zM55 152.5h14.3v9.6h-14.3zM75.5 143h1.9v4.8h-1.9zM81.5 143h1.9v4.8h-1.9zM179.2 141.8v2.4"/>
<path d="M179.2 143l2.4-1.2v2.4zM78.9 161.1h4.7v2h-4.7z"/>
<circle cx="120.7" cy="28.9" r="1.79"/>
</g>
<g fill="none" stroke="#000084" stroke-width=".2">
<path d="M225.2 86.3l1.2 1.1M225.2 83.9l1.2 1.1M226.4 86.3l-1.2 1.1M226.4 83.9l-1.2 1.1M101 114.9l1.1 1.2M101 110.2l1.1 1.1M101 112.5l1.1 1.2M102.1 114.9l-1.1 1.2M102.1 110.2l-1.1 1.1M102.1 112.5l-1.1 1.2M148.8 112.5l1.1 1.2M148.8 114.9l1.1 1.2"/>
<path d="M148.8 105.4l1.1 1.1M148.8 103l1.1 1.1M148.8 107.8l1.1 1.1M148.8 117.3l1.1 1.2M148.8 119.7l1.1 1.2M149.9 112.5l-1.1 1.2M149.9 114.9l-1.1 1.2M149.9 105.4l-1.1 1.1M149.9 103l-1.1 1.1M149.9 107.8l-1.1 1.1M149.9 117.3l-1.1 1.2M149.9 119.7l-1.1 1.2"/>
<path d="M225.2 105.4l1.2 1.1M225.2 107.8l1.2 1.1M226.4 105.4l-1.2 1.1M226.4 107.8l-1.2 1.1M101 122.1l1.1 1.1M101 124.5l1.1 1.1M101 126.9l1.1 1.1M101 136.4l1.1 1.2M101 138.8l1.1 1.2M102.1 122.1l-1.1 1.1M102.1 124.5l-1.1 1.1M102.1 126.9l-1.1 1.1"/>
<path d="M102.1 136.4l-1.1 1.2M102.1 138.8l-1.1 1.2M148.8 134l1.1 1.2M149.9 134l-1.1 1.2M225.2 122.1l1.2 1.1M225.2 124.5l1.2 1.1M226.4 122.1l-1.2 1.1M226.4 124.5l-1.2 1.1M101 143.6l1.1 1.1M101 146l1.1 1.1M101 148.4l1.1 1.1M101 141.2l1.1 1.2"/>
<path d="M102.1 143.6l-1.1 1.1M102.1 146l-1.1 1.1M102.1 148.4l-1.1 1.1M102.1 141.2l-1.1 1.2M148.8 141.2l1.1 1.2M148.8 153.2l1.1 1.1M148.8 155.6l1.1 1.1M149.9 141.2l-1.1 1.2M149.9 153.2l-1.1 1.1M149.9 155.6l-1.1 1.1"/>
</g>
<g fill="none" stroke="#008400" stroke-width=".2">
<path d="M25.1 39h3.6M28.7 36.7h-13.2v14.3M66.9 39h9.6v16.8M95.6 31.9v1.2M98 31.9h-31.1v2.4M107.5 31.9h13.2M111.1 31.9v2.4M111.1 39v2.4M130.2 33.1h8.4M132.6 33.1v14.3h6M143.4 33.1h25.1v58.5h-19.2M219.8 28.3v2.4h39.5"/>
<path d="M15.5 58.2v2.3M25.1 41.4h3.6M66.9 43.8h3.6M66.9 41.4h3.6M66.9 55.8v17.9M66.9 51h3.6v16.7M66.9 53.4h3.6M95.6 40.2v1.2M99.2 57v1.2M143.4 47.4h22.7v41.8h-16.8M198.3 41.4h-23.9v55h-25.1M228.2 53.4v47.8h-2.4"/>
<path d="M228.2 54.6h2.4v2.4M58.5 70.1v3.6M58.5 78.5v2.4M66.9 78.5v2.4h-11.9v-1.2M66.9 70.1h-11.9v2.4M76.5 62.9v2.4M99.2 65.3v2.4h2.4M99.2 72.5h2.4M149.3 72.5h25.1M149.3 67.7h4.8v4.8M149.3 70.1h4.8M149.3 77.3h7.2"/>
<path d="M149.3 79.7h7.2M156.5 66.5v27.5h-7.2M197.1 60.5v40.7h4.8M197.1 62.9h4.8M201.9 72.5h-15.5v52.6h-37.1M201.9 67.7h-14.3v59.8h-38.3M201.9 74.9h-11.9v57.3h-40.7M201.9 70.1h-13.1v59.7h-39.5M225.8 72.5h29.9M225.8 67.7h29.9M225.8 70.1h29.9M225.8 74.9h29.9"/>
<path d="M225.8 62.9h2.4M225.8 79.7h4.8M230.6 64.1v88.4h-7.2M235.4 67.7v82.4h13.1M237.8 70.1v75.3h10.7M240.1 72.5v68.1h8.4M242.5 74.9v60.9h6M56.2 80.9v2.3M99.2 86.8h2.4M101.6 91.6h-46.6v4.8M101.6 94h-38.3v2.4M149.3 84.4h7.2"/>
<path d="M149.3 82.1h7.2M199.5 86.8h2.4M201.9 84.4h-2.4v44.2M55 103.6v2.3M63.3 103.6v2.3M76.5 113.1v9.6h4.7M76.5 115.5h4.7M88.4 115.5h3.6M94.4 101.2h7.2M94.4 103.6h7.2M96.8 115.5h2.4v2.4h2.4M149.3 110.7h2.4"/>
<path d="M156.5 110.7h1.2M166.1 107.1v3.6h-1.2M199.5 105.9h2.4M199.5 108.3h2.4M201.9 110.7h-10.7v32.3h-7.2M201.9 113.1h-9.5v22.7h-8.4M225.8 117.9h4.8M225.8 110.7h29.9M225.8 113.1h29.9M87.2 134.6h14.4M87.2 132.2h14.4M88.4 122.7h3.6"/>
<path d="M101.6 120.3h-2.4v2.4h-2.4M149.3 139.4h14.4v3.6h13.1M176.8 135.8h-13.1v1.2h-14.4M199.5 122.7h2.4M199.5 125.1h2.4M246.1 129.8v3.6h2.4M248.5 138.2h-4.8v20.3M47.8 154.9h4.8M50.2 141.8h32.2M50.2 149v5.9M62.1 140.6v9.5M71.7 159.7h1.2v2.4h4.8"/>
<path d="M71.7 157.3h15.5M71.7 154.9h15.5M76.5 149v13.1M82.4 149v5.9M86 157.3v4.8h-1.2M149.3 151.3h3.6M149.3 149h3.6M223.4 154.9h7.2v3.6M240.1 154.9h8.4M243.7 143h4.8M243.7 152.5h4.8M243.7 147.8h4.8"/>
<path d="M35.8 177.6h-5.9v3.6h-2.4M62.1 164.5v3.6M149.3 165.7h2.4v4.8M149.3 168.1h2.4M19.1 183.6h8.4M22.7 181.2h-1.2v4.8h1.2M27.5 186h2.4v3.6h5.9M32.3 183.6h13.1"/>
</g>
<g fill="none" stroke="#0000c2" stroke-width=".2">
<path d="M135.1 125h.7M135.1 126.9h.7M135.1 128.8h.7M135.1 130.8h.7M135.5 125v1.2M135.5 126.9v1.2M135.5 128.8v1.2M135.5 130.8v1.2M136.2 126.9a.6 .6 0 0 1 .7 .6 .6 .6 0 0 1-.7 .6zM136.2 128.8a.6 .6 0 0 1 .7 .6 .6 .6 0 0 1-.7 .6zM136.2 132v-1.2l.4 .8 .4-.8v1.2M136.9 125.1a.53 .53 0 0 0-.8 .5 .53 .53 0 0 0 .8 .4"/>
<path d="M137.4 125v1.2M137.4 126.9v1.2M137.4 129l.2-.2a.4 .4 0 0 1 .5 .4v.4a.4 .4 0 0 1-.4 .5 .4 .4 0 0 1-.4-.5zM137.6 125.5l.5 .7M138.1 125l-.7 .7M138.2 130.8l-.6 .1v.3l.5 .3 .1 .2-.2 .3-.5-.1M203.8 130.5l-.3-.1-.2 .2 .1 .2 .4 .1v.3h-.5M203.9 132.4h-.3l-.3 .2 .1 .5h.5M203.9 132v1.2M204.1 128.2a.53 .53 0 0 0-.8 .5 .53 .53 0 0 0 .8 .5M204.4 130.5h.4l.1 .7M204.4 130v1.2"/>
<path d="M204.5 132v.1M204.5 132.4v.8M204.6 128.6l.2-.1 .3 .1-.1 .6h-.4zM205.4 130v.1M205.4 130.4v.8M205.4 132.4h-.2l-.2 .1v.2l.4 .1v.3h-.4M205.7 128.6h.4l.1 .7M205.7 128.5v.8M205.8 130.4h.5M206 132.4h.5v.8M206.3 130l-.3 .2v1M206.5 130.4h.5"/>
<path d="M206.5 132.7l-.5 .2 .1 .3 .4-.1M206.7 130v1.1l.3 .1M206.7 128.6h.5l.1 .7M206.7 128.5v.8M207.1 132.4h.3l.3 .2-.2 .5h-.4M207.1 132v1.2M207.3 130.8l.6-.1-.1-.2-.3-.1-.2 .2 .1 .6h.4M207.8 128.9l.5-.1v-.2l-.4-.1-.1 .2v.5h.5M208.2 132v1l.1 .2M208.4 130.4v.8M208.7 132.8l.6-.1v-.3h-.4l-.2 .1 .1 .6h.5M208.7 130.4l-.3 .3"/>
<path d="M209.4 128.6l-.4-.1-.2 .2 .1 .5h.5M209.5 130.5l-.2-.1-.2 .2v.2l.4 .1v.3h-.4M209.7 128.5h.5M209.9 128.1v1l.3 .2M210.3 132.4h-.3l-.2 .2 .1 .5h.4M210.3 132v1.2M210.6 128.1v.1M210.6 128.5v.8M210.7 130.4h.4M210.8 130v1.1l.3 .1M211.1 128.6h.5v.7M211.1 128.5v.8"/>
<path d="M211.5 132.4l.2 .8 .3-.6 .2 .6 .2-.8M211.6 130.5l.2-.1 .3 .3v.3l-.3 .2-.4-.2zM212.7 128.5v1l-.2 .2-.3-.1M212.7 128.6l-.3-.1-.2 .2 .1 .5h.4M212.9 132v.1M212.9 132.4v.8M213.2 130.8l.6-.1v-.2l-.4-.1-.2 .2 .1 .6h.5M213.3 132.4h.4M213.4 132v1l.3 .2M214 128.5v.8M214.1 132.5l.5-.1v.8M214.1 132v1.2"/>
<path d="M214.3 130.5h.5v.7M214.3 130.4v.8M214.3 128.5l-.3 .2M214.7 128.9l.6-.1-.1-.2-.3-.1-.2 .2v.5h.5M215.7 132.4h.5M215.8 130.5l-.3-.1-.2 .2 .1 .2 .4 .1v.3h-.5M215.9 132v1l.3 .2M216.2 128.6l-.3-.1-.2 .2 .1 .1 .4 .2v.2h-.5M216.4 130.4v.8l.5-.1M216.6 132.5l.5-.1v.8M216.6 132v1.2M216.7 128.9l.5-.1v-.2l-.3-.1-.2 .2v.5h.5"/>
<path d="M216.9 130.4v.8M217.5 130.4v.8M217.6 128.5h.4M217.6 132.8l.6-.1-.1-.3h-.3l-.2 .1 .1 .6h.4M217.8 128.1v1l.2 .2M217.8 130.4l-.3 .3M218.1 130.8l.6-.1-.1-.2-.3-.1-.2 .2 .1 .6h.4M218.8 128.6l-.2-.1-.2 .2v.1l.4 .2v.2h-.4M219.4 132v.1M219.4 132.4v1l-.2 .2M219.8 130.4h.4M219.9 130v1.1l.3 .1"/>
<path d="M220 128.5h.4M220 132.4v.7l.5-.1M220.1 128.1v1l.3 .2M220.5 132.4v.8M220.6 130.5h.5v.7M220.6 130v1.2M220.8 128.6h.5v.7M220.8 128.1v1.2M221.1 132.5l.3-.1 .2 .1M221.1 132.4v.8M221.6 132.5l.2-.1h.2l.1 .8M221.6 132.5v.7"/>
<path d="M221.6 130.8l.6-.1v-.2l-.4-.1-.2 .2 .1 .6h.5M221.9 128.5v.8M222.2 128.5l-.3 .2M222.6 130.4l.3 .8M222.6 128.6l.2-.1 .3 .1v.6h-.5zM222.7 132.4h.3l.2 .2-.1 .5h-.4M222.7 132.4v1.2M222.9 131.2l-.3 .4M223.2 130.4l-.3 .8M223.7 132.8l.6-.1-.1-.3h-.3l-.2 .1v.6h.5M223.7 128.5l.1 .7h.4M224.2 128.5v.8"/>
<path d="M224.3 130.5h.5l.1 .7M224.8 132.4v.8M224.9 130.7l-.6 .2 .2 .3h.4M225.1 132.4l-.3 .2M225.3 128.6l-.3-.1-.3 .2 .2 .5h.4M225.3 128.5v1l-.2 .2-.3-.1M225.4 130.4v.8M225.8 130.4l-.4 .3M225.9 128.6h.4l.1 .7M225.9 128.1v1.2M226.1 130.8l.6-.1-.1-.2-.3-.1-.2 .2 .1 .6h.4M169.9 149.1a.6 .6 0 0 1 .7 .6 .6 .6 0 0 1-.7 .6z"/>
<path d="M169.9 151.6l.2-.1 .4 .1-.1 .6h-.5zM171 151.6l.5-.1v.8M171 151.5v.8M171.1 149.1v.2M171.1 149.5v.8M171.8 149.6l.2-.1 .3 .3v.3l-.3 .2-.4-.2zM172.1 151.1v1l.2 .2M172.6 151.5l.3 .8M172.9 152.3l-.3 .4M173.2 151.5l-.3 .8M173.3 149.6l-.3-.1-.3 .3 .1 .5h.5M173.3 149.1v1.2"/>
<path d="M173.8 149.9l.6-.1-.1-.2-.3-.1-.2 .2 .1 .6h.4M174.4 151.5h.4l.1 .8M174.9 151.8l-.6 .2 .2 .3 .4-.1M175.3 149.6l-.3-.1-.2 .2 .1 .2 .4 .1v.3h-.5M175.9 151.5h-.3l-.2 .2 .1 .5h.4M176.3 151.5h.4M176.5 151.1v1l.2 .2M176.5 149.9l.6-.1-.1-.2-.3-.1-.2 .2 .1 .6h.4M177.1 151.1v.1M177.1 151.5v.8M177.6 151.5l.3 .8 .3-.8M177.6 149.7l.5-.1v.7"/>
<path d="M177.6 149.5v.8M178.6 151.9l.5-.1v-.3h-.4l-.1 .2v.5h.5M179.1 149.6l-.3-.1-.2 .2 .1 .2 .4 .1v.3h-.5M179.6 149.5l.1 .8 .5-.1M180.2 149.5v.8M180.4 151.1v1l.1 .2M180.7 149.5v.8M181 151.6l.2-.1 .3 .1-.1 .6h-.4zM181.1 149.5l-.4 .3M181.4 149.9l.6-.1-.1-.2-.3-.1-.2 .2 .1 .6h.4M182 151.5l.2 .8 .2-.6 .2 .6 .3-.8M183.2 149.5v.8"/>
<path d="M183.3 152.2v.1M183.5 149.5l-.3 .3M183.9 149.9l.6-.1-.1-.2-.3-.1-.2 .2v.6h.5M185.4 149.6l-.3-.1-.2 .2 .1 .2 .4 .1v.3h-.5M185.9 149.9l.5-.1v-.2l-.3-.1-.2 .2v.6h.5M186.8 149.5h.4M187 149.1v1.1l.2 .1M188 149.6l-.2-.1-.2 .2v.2l.4 .1v.3h-.4M189.3 149.6h.5v.7M189.8 149.8l-.5 .3 .1 .2h.4M190.4 149.5v.8M190.7 149.5l-.3 .3"/>
<path d="M191.1 149.9l.6-.1-.1-.2-.3-.1-.2 .2v.6h.5M200.1 155.9v1l-.4 .2M200.7 156.3l.1 .7 .4-.1M201.2 156.3v.8M201.8 156.4l.3-.1 .2 .1M201.8 156.3v.8M202.3 156.4l.2-.1h.3v.8M202.3 156.4v.7M203.4 156.3h.3l.3 .2-.2 .5h-.4M203.4 156.3v1.2M204.4 156.7l.6-.2-.1-.2h-.3l-.2 .1 .1 .6h.4M205.5 156.3v.8"/>
<path d="M205.8 156.3l-.3 .2M206.8 156.3h.4M207 155.9v1l.2 .2M207.6 156.4l.2-.1 .3 .1v.6l-.5-.1zM209.9 156.3h-.3l-.2 .2 .1 .5h.4M209.9 155.9v1.2M210.5 155.9v.1M210.5 156.3v.8M211.5 156.3h-.3l-.2 .1 .1 .2 .4 .1v.3h-.5M212 156.3h.5l.1 .8M212.6 156.5l-.6 .3 .2 .3 .4-.1M213.1 156.3h.4l.2 .2-.1 .5h-.5"/>
<path d="M213.1 155.9v1.2M214.2 155.9v1l.2 .2M214.8 156.7l.5-.2v-.2h-.3l-.2 .1v.6h.5M216.6 156.4l.1-.1 .4 .1-.1 .6-.4-.1zM217.7 156.4l.4-.1 .1 .8M217.7 156.3v.8M218.7 156.6h1M220.2 156.3h.4l.2 .2-.1 .5h-.5M220.2 155.9v1.2M221.3 156.4l.2-.1 .3 .1v.6l-.5-.1zM222.4 156.3h.4l.1 .8M222.9 156.5l-.6 .3 .2 .3 .4-.1"/>
<path d="M223.5 156.3v.8M223.8 156.3l-.3 .2M224.7 155.9v1.2M224.7 156.3h-.3l-.3 .2 .2 .5h.4M226.3 155.9v1l-.4 .2M226.7 155.9h.7M227.1 155.9v1.2M227.6 157.1l.4-1.2 .4 1.2M227.8 156.7h.5M229.5 155.9a.54 .54 0 0 0-.7 .6 .54 .54 0 0 0 .7 .4v-.4h-.2M169.8 170.7l.2 .6M169.9 171.9v1"/>
<path d="M169.9 173.4v1M169.9 177.4l.4-.1-.1-.5h-.3v.9M169.9 172.3h.3l.1 .6M169.9 173.8h.3l.1 .6M170 171.3l-.2 .3M170.2 170.7l-.2 .6M170.4 169a.42 .42 0 0 0-.6 .3 .42 .42 0 0 0 .6 .4M170.4 175a.42 .42 0 0 0-.6 .4 .42 .42 0 0 0 .6 .4M170.6 170.8h.4v.5l-.4-.1zM170.6 172.2h.4M170.7 177.1l.4-.1v-.2h-.3l-.1 .1v.5h.4M170.7 173.8h.4v.6"/>
<path d="M170.7 171.9v.8l.3 .2M170.8 169.3h.4v.5l-.4-.1zM170.8 175.1l.2-.1 .4 .1v.5l-.1 .3-.5-.1zM171.1 174l-.4 .2 .1 .2 .3-.1M171.1 172.2h.4M171.3 171.9v.8l.2 .2M171.4 170.7l.1 .6 .3-.1M171.5 176.8v.6M171.6 173.7v.7M171.7 169.2h.2l.2 .2-.1 .4h-.3M171.7 169.2v.9M171.8 172.3l.3-.1 .2 .2-.1 .4h-.4"/>
<path d="M171.8 172.2v1M171.8 176.8l-.3 .2M171.8 170.7v.6M171.8 173.7l-.2 .2M172.1 176.9l.3-.1 .1 .1M172.1 176.8v.6M172.3 175v.9l-.5-.9v.9M172.4 169.2l.3 .6M172.5 176.9l.4-.1v.6M172.5 176.9v.5M172.6 173.8l-.3-.1-.2 .2 .1 .4h.4M172.6 173.4v1"/>
<path d="M172.7 172.9h.1M172.7 172.3v.1M172.7 169.8l-.3 .3M172.7 172.8v.1M172.8 175a.48 .48 0 0 1 .5 .4 .48 .48 0 0 1-.5 .5zM172.9 170.8l.2-.1 .2 .1M172.9 170.7v.6M172.9 169.2l-.2 .6M172.9 173.7l.2 .7 .2-.5 .2 .5 .1-.7M173.2 169.2v.6M173.3 170.8v.5M173.3 170.8l.3-.1 .1 .6"/>
<path d="M173.4 176.5v.1M173.4 176.8v.6M173.5 169.2l-.3 .2M173.7 175v.9M173.8 171.9l-.8 1.2M173.8 168.9v.1M173.8 169.2v.6M174 173.8h.4v.6M174 175h.6M174.1 170.7h.4v.6M174.1 176.8h-.2l-.1 .2 .4 .2M174.2 177.3l-.2 .1h-.2"/>
<path d="M174.2 177.2v.1M174.3 175v.9M174.4 174l-.4 .2 .1 .2 .3-.1M174.5 170.9l-.4 .2 .1 .2h.3M174.7 169.2h-.3l-.2 .2 .1 .4h.4M174.7 169.2v.7l-.2 .2h-.2M174.8 171.9l-.8 1.2M174.9 173.7v.7M174.9 170.7l.2 .6M174.9 175v.9M174.9 176.8h-.2l-.2 .2 .4 .2M174.9 177.3l-.1 .1h-.3"/>
<path d="M174.9 177.2v.1M175 172.4l.4 .3-.1 .2-.3-.1M175 172.4h.1M175.1 171.3l-.2 .3M175.1 169.3l.4-.1v.6M175.1 168.9v.9M175.1 173.7l-.2 .2M175.3 170.7l-.2 .6M175.3 176.5v.1M175.3 176.8v.6M175.3 175.1l.2-.1 .4 .1v.5l-.1 .3-.5-.1zM175.4 174.1l.4-.1v-.2l-.3-.1-.1 .2v.4h.4"/>
<path d="M175.4 172.3l-.4 .1M175.8 176.9h.4l-.1 .5-.3-.1zM175.8 172.3h.4v.5h-.4zM175.8 169.2h.4M176 168.9v.8l.2 .1M176.2 170.8l.4-.1 .1 .6M176.2 170.7v.6M176.6 176.9l.4-.1v.6M176.6 176.8v.6M176.7 171.9v.8l.1 .2M176.8 173.8h.4v.6M176.9 175v.9l-.6-.9v.9"/>
<path d="M177.1 169.2h.3l.1 .6M177.1 170.8h.4v.5l-.4-.1zM177.2 174l-.4 .2 .1 .2 .3-.1M177.5 169.4l-.5 .2 .2 .2h.3M177.6 171.9v.9h-.4v-.5h.4M177.7 173.8h.3l.1 .6M177.7 173.7v.7M177.8 176.8h-.2l-.2 .2 .5 .2M177.8 175h-.5a.39 .39 0 0 0 .5 .5l-.1 .4h-.4M177.8 170.7h.4M177.9 177.3l-.2 .1h-.3M177.9 177.2v.1"/>
<path d="M177.9 169.3l.4-.1v.6M177.9 169.2v.6M178 170.4v.8l.2 .1M178 172.5l.4-.1v-.1l-.3-.1-.1 .2v.4h.4M178.8 175.1l.2-.1 .3 .1 .1 .5-.2 .3-.4-.1zM178.8 176.8h.4v.6M178.8 172.2v.7M178.9 173.8l-.3-.1-.1 .2 .1 .4h.3M178.9 173.4v1M179.1 170.7v.6l.4-.1M179.1 172.2l-.3 .2M179.2 169.2h-.3l-.2 .2 .1 .4h.4"/>
<path d="M179.2 168.9v.9M179.2 177l-.4 .2 .1 .2h.3M179.4 172.3l.3-.1 .2 .2-.1 .4h-.4M179.4 172.2v1M179.5 170.7v.6M179.7 176.8v.6M179.7 176.9l.3-.1 .1 .6M179.8 175.4h.3M179.9 173.8l.3-.1 .1 .2M179.9 173.7v.7M180.2 169.2v.6M180.2 175h-.4v.9"/>
<path d="M180.2 170.7l-.3 .1 .3 .3v.2h-.3M180.3 172.3l.2-.1 .2 .2v.4l-.3 .1-.1-.4 .4-.1M180.3 173.9l.4-.1v.6M180.3 173.9v.5M180.5 169.2l-.3 .2M180.6 171l.5-.1-.1-.2h-.2l-.2 .1 .1 .5h.3M180.7 169.5l.5-.1-.1-.2h-.2l-.2 .1 .1 .5h.3M180.9 176.5v.9M180.9 176.8h-.2l-.2 .2 .1 .4h.3M181 175.9l.3-.9 .3 .9M181.1 175.6h.4M181.2 173.8h.3l.1 .6"/>
<path d="M181.5 171.9v.9h-.3l-.1-.5h.4M181.6 168.9v.8l.1 .1M181.6 174l-.5 .2 .2 .2 .3-.1M181.9 173.7h.4M181.9 170.7h.4M181.9 176.5v.8l.2 .1M182 172.8v.1M182 173.4v.8l.3 .2M182 170.4v.8l.3 .1M182.1 169.2h.3l.1 .6M182.4 172.3h.4v.5h-.4zM182.4 176.5v.1"/>
<path d="M182.4 176.8v.6M182.5 175v.9l-.6-.9v.9M182.5 169.4l-.5 .2 .2 .2h.3M182.5 174.1l.5-.1-.1-.2-.2-.1-.2 .2 .1 .4h.3M182.6 170.8l.3-.1 .1 .6M182.6 170.4v.9M182.8 175l.3 .5M182.8 169.2h.3M182.9 176.9l.2-.1 .2 .1M182.9 176.8v.6M182.9 168.9v.8l.2 .1M183.1 175.5v.4"/>
<path d="M183.3 172.2v.7M183.3 176.9v.5M183.3 176.9l.3-.1 .1 .6M183.4 173.7v.7M183.4 175l-.3 .5M183.4 169.5l.5-.1-.1-.2h-.3l-.1 .1 .1 .5h.3M183.4 170.4v.1M183.4 170.7v.6M183.5 172.2l-.2 .2M183.6 173.7l-.2 .2M184 173.4v.1M184 173.7v.7"/>
<path d="M184.1 176.5v.1M184.1 176.8v.6M184.2 170.7l-.4 .1 .4 .3v.2h-.4M184.3 172.2v.8l-.2 .2-.2-.1M184.3 172.3l-.3-.1-.2 .2 .1 .4h.4M184.3 175v.9M184.4 173.8h.4v.6M184.4 175.4l.4 .5M184.4 176.8h.4M184.6 176.5v.8l.2 .1M184.7 169.2h-.3l-.2 .2 .1 .4h.4M184.7 168.9v.9"/>
<path d="M184.8 174l-.4 .2 .1 .2 .3-.1M184.8 175l-.5 .5M185.1 170.7h.3M185.1 176.8h.4v.6M185.2 175v.9M185.3 173.4v.8l.1 .2M185.4 171.9l-.8 1.2M185.4 170.4l-.2 .1v.8M185.5 177l-.4 .2 .1 .2h.3M185.7 169.2v.6M185.7 171.9v.8l.1 .2M185.7 170.4v.1"/>
<path d="M185.7 170.7v.6M185.8 176.8h.4M186 169.2l-.3 .2M186 176.5v.8l.2 .1M186.1 173.8l-.4 .1 .4 .2v.2h-.4M186.2 171.9v.1M186.2 170.4v.8l.1 .1M186.2 172.2v.7M186.2 175v.9l-.5-.9v.9M186.3 168.9v.1M186.3 169.2v.6M186.5 176.5v.1"/>
<path d="M186.5 176.8v.6M186.6 171l.5-.1-.1-.2h-.2l-.2 .1 .1 .5h.3M186.7 175a.48 .48 0 0 1 .5 .4 .48 .48 0 0 1-.5 .5zM187 176.9h.4l-.1 .5-.3-.1zM187 172.3l-.2-.1-.2 .2 .1 .4h.3M187.1 169.2h-.3l-.1 .2 .1 .4h.3M187.1 169.2v.7l-.2 .2h-.2M187.4 172.5l.4-.1v-.1l-.3-.1-.1 .2v.4h.4M187.5 173.8l-.3-.1-.2 .2 .1 .4h.4M187.5 173.4v1M187.6 169.3l.3-.1 .1 .6M187.6 168.9v.9"/>
<path d="M187.7 175.9l-.1 .1M187.8 176.9l.4-.1v.6M187.8 176.8v.6M187.9 173.4v.1M187.9 173.7v.7M188 171l.5-.1-.1-.2h-.3l-.1 .1v.5h.4M188.2 172.3h.4v.6M188.2 172.2v.7M188.3 169.2h.3M188.4 168.9v.8l.2 .1M188.6 175.6l.4-.1v-.2h-.3l-.1 .1v.5h.4M188.7 173.8l-.4 .1 .4 .2v.2h-.4"/>
<path d="M188.8 170.7l.5 .6M189 176.8h-.3l-.1 .2 .4 .2M189 173.7h.4M189 177.3l-.1 .1h-.3M189 177.2v.1M189.1 172.4l.4 .3-.2 .2-.2-.1M189.1 172.4h.1M189.1 173.4v.8l.3 .2M189.3 170.7l-.5 .6M189.3 169.2l-.4 .1 .4 .2v.3h-.4M189.4 172.3l-.3 .1M189.4 175h.1"/>
<path d="M189.4 175.3v.6M189.7 173.7v.7M189.7 175.3h.4M189.8 172.5l.5-.1-.1-.1-.3-.1-.1 .2 .1 .4h.3M189.9 175v.8l.2 .1M189.9 173.7l-.2 .2M190 176.8v.6l.4-.1M190 170.7h-.3l-.1 .2 .1 .4h.3M190.3 173.4v.1M190.3 173.7v.7M190.3 169.2h.3l.1 .6M190.4 171l.4-.1v-.2h-.3l-.1 .1v.5h.4"/>
<path d="M190.4 176.8v.6M190.4 175v.9M190.4 175.4l.4-.1v.6M190.6 172.4l.4 .3-.1 .2-.3-.1M190.6 172.4h.1M190.7 169.4l-.5 .2 .2 .2h.3M190.7 173.8l.3-.1 .1 .2v.4h-.4M190.7 173.4v1M190.8 176.8v.6M190.8 176.9l.4-.1v.6M191 172.3l-.4 .1M191.1 169.2v.6"/>
<path d="M191.2 175.6l.5-.1-.1-.2h-.2l-.2 .1 .1 .5h.3M191.2 170.7h.3l.2 .2-.1 .4h-.4M191.2 170.7v.9M191.4 169.2l-.3 .2M191.6 173.7v.6h.4M191.7 169.5l.4-.1v-.2h-.3l-.1 .1v.5h.4M191.9 170.7h.4M192 173.7v.7M192.1 175.3v.6M192.1 170.4v.8l.2 .1M192.1 176.8h-.3l-.2 .2 .1 .4h.4M192.1 176.5v.9"/>
<path d="M192.1 171.9l-.8 1.2M192.3 173.7h.3M192.3 175.3l-.2 .2M192.4 173.4v.8l.2 .2M192.5 177.1l.4-.1v-.2h-.3l-.1 .1v.5h.4M192.9 174.1l.4-.1v-.2l-.3-.1-.1 .2v.4h.4M192.9 172h-.5a.39 .39 0 0 0 .5 .5l-.1 .3h-.4M193.1 168.9v.8l.1 .1M193.2 175.6l.4-.1v-.2h-.3l-.1 .1v.5h.4M193.2 170.4v.1M193.2 170.7v.6M193.3 171.9v1"/>
<path d="M193.3 172.4h.5M193.3 176.8v.6M193.6 168.9v.1M193.6 169.2v.6M193.6 176.8l-.3 .2M193.6 170.8l.4-.1v.6M193.6 170.7v.6M193.8 171.9v1M193.9 175.3l.5 .6M194.1 173.8l-.2-.1-.2 .2 .1 .4h.3M194.1 173.4v1M194.3 171.9v1h.4"/>
<path d="M194.4 176.8h.3M194.4 175.3l-.5 .6M194.4 169.2h-.2l-.2 .2 .1 .4h.3M194.5 176.5v.8l.2 .1M194.8 175.3v.9M194.8 175.3h.3l.1 .2-.1 .4h-.3M194.8 169.5l.4-.1v-.2h-.3l-.1 .1v.5h.4M195 176.9l.4-.1v.6M195 176.5v.9M195.1 172.5h.7M195.2 173.7v.6h.4M195.4 170.7h-.2l-.2 .2 .1 .4h.3"/>
<path d="M195.6 173.7v.7M195.6 175.3v.6M195.6 169.3l.4-.1v.6M195.6 169.2v.6M195.8 177.1l.5-.1-.1-.2h-.2l-.2 .1 .1 .5h.3M195.9 170.8h.4l-.1 .5-.3-.1zM195.9 175.3l-.3 .2M196 173.7v.7M196 173.8h.4v.6M196.2 175.6l.4-.1v-.2h-.3l-.1 .1v.5h.4M196.2 172l.3-.1 .2 .3-.6 .7h.6M196.7 170.8l.3-.1 .1 .1"/>
<path d="M196.7 170.7v.6M196.8 169.2l-.4 .1 .4 .2v.3h-.4M197.1 170.8l.4-.1v.6M197.1 170.8v.5M197.1 172.8v.1M197.2 169.5l.5-.1-.1-.2h-.3l-.1 .1v.5h.4M197.2 176.5v.9h.5M197.3 173.8l-.3-.1-.2 .2 .1 .4h.4M197.3 173.4v1M197.3 175.3l-.3 .1 .3 .2v.3h-.3M197.5 172.9h.6M197.5 172.2l.3-.3v1"/>
<path d="M197.7 174.1l.4-.1v-.2l-.3-.1-.1 .2v.4h.4M198 170.7h.2l.2 .2-.1 .4h-.3M198 170.7v.9M198 176.5v.1M198 176.8v.6M198.1 175.3l-.4 .1 .4 .2v.3h-.4M198.5 169.2h-.3l-.2 .2 .1 .4h.4M198.5 168.9v.9M198.5 172.8v.1M198.5 173.7v.7M198.8 173.7l-.3 .2M198.8 170.4v.8l.1 .1"/>
<path d="M198.9 176.8h-.3l-.2 .2 .1 .4h.4M199.1 175.4h.4v.5l-.4-.1zM199.2 177.1l.5-.1-.1-.2h-.2l-.2 .1 .1 .5h.3M199.3 170.4v.1M199.3 170.7v.6M199.5 169.2v.6l.4-.1M199.5 171.9v.8l.1 .2 .4-.2v-.8M199.5 173.7h.4M199.7 173.4v.8l.2 .2M199.7 170.7h.4l.1 .6M199.9 169.2v.6M200 175.3v.6"/>
<path d="M200.1 176.9l.3-.1 .1 .6M200.1 176.8v.6M200.2 170.9l-.5 .2 .1 .2h.4M200.2 173.8h.4v.6M200.2 173.4v1M200.2 175.3l-.2 .2M200.3 169.3l.4-.1v.6M200.3 169.2v.6M200.5 172.3h.3l.1 .6M200.5 172.2v.7M200.6 170.8l.4-.1v.6M200.6 170.7v.6"/>
<path d="M201.1 173.4v.1M201.1 173.7v.7M201.1 175h.1M201.1 175.3v.6M201.2 176.8h-.2l-.1 .2 .4 .2M201.3 177.3l-.2 .1h-.2M201.3 177.2v.1M201.3 171.9v.8l.1 .2M201.6 175.3v.6M201.6 175.4l.2-.1 .2 .1M201.6 169.2h-.3l-.2 .2 .1 .4h.4M201.6 168.9v.9"/>
<path d="M201.6 177.1l.5-.1-.1-.2h-.2l-.2 .1 .1 .5h.3M201.8 172.5l.4-.1v-.1l-.3-.1-.1 .2v.4h.4M201.8 173.8l-.3 .1 .3 .2v.2h-.3M201.9 170.7h-.3l-.2 .2 .1 .4h.4M202 175.4v.5M202 175.4l.3-.1 .1 .6M202 169.5l.4-.1v-.2h-.3l-.1 .1v.5h.4M202.2 171l.5-.1-.1-.2h-.3l-.1 .1 .1 .5h.3M202.5 177.3v.1M202.6 172.4l.4 .3-.2 .2-.2-.1M202.6 172.4h.1M202.8 175.3v.9"/>
<path d="M202.8 175.3h.3l.2 .2-.1 .4h-.4M202.8 169.2v.6M202.8 173.4v1h.5M202.9 172.3l-.3 .1M203.1 169.2l-.3 .2M203.3 172.4h.1M203.3 172.4l.4 .3-.1 .2-.3-.1M203.5 170.7l.2 .6 .2-.4 .2 .4 .2-.6M203.6 173.4v.1M203.6 173.7v.7M203.7 175v.8l.1 .1M203.7 172.3l-.4 .1"/>
<path d="M203.8 169.2h.4M204 168.9v.8l.2 .1M204.2 175h.1M204.2 175.3v.6M204.4 173.8l-.2-.1-.2 .2 .1 .4h.3M204.5 168.9v.9M204.5 169.3l.4-.1v.6M204.6 175.6l.4-.1v-.2h-.3l-.1 .1v.5h.4M204.6 170.4v.1M204.6 170.7v.6M204.7 172.2v.7M204.8 174.1l.4-.1v-.2l-.3-.1-.1 .2v.4h.4"/>
<path d="M204.9 170.7h.4M205 172.2l-.3 .2M205.1 170.4v.8l.2 .1M205.2 172.5l.5-.1-.1-.1-.2-.1-.2 .2 .1 .4h.3M205.3 169.5l.5-.1-.1-.2h-.2l-.2 .1 .1 .5h.3M205.6 170.8l.4-.1v.6M205.6 170.4v.9M205.7 173.7v.7M205.7 173.8h.3l.1 .6M205.8 175.3h-.3l-.1 .2 .1 .4h.3M205.8 175v.9M206.3 175.8v.1"/>
<path d="M206.5 172.2v1M206.5 172.3l-.3-.1-.2 .2 .1 .4h.4M206.8 173.8l-.3 .1 .3 .2v.2h-.3M206.9 170.7h.3M206.9 172.2l.1 .6h.3M207 170.4v.8l.2 .1M207.2 174.1l.5-.1-.1-.2-.2-.1-.2 .2 .1 .4h.3M207.2 168.9l-.5 .1a.39 .39 0 0 0 .5 .4l-.1 .4h-.4M207.3 172.2v.7M207.6 170.4v.9M207.6 170.8l.3-.1 .1 .6M207.6 169.3h.4v.5h-.3z"/>
<path d="M207.6 169.7l.1 .1M207.8 175h-.5a.39 .39 0 0 0 .4 .5v.4h-.5M207.8 171.9v.1M207.8 172.2v.7M208.1 175.6l.5-.1-.1-.2h-.2l-.2 .1 .1 .5h.3M208.2 172.2v.7M208.4 171l.4-.1v-.2h-.3l-.1 .1v.5h.4M208.5 168.9v.8l.1 .1M208.5 172.2l-.3 .2M208.6 173.4v.1M208.6 173.7v.7M208.8 172.5l.4-.1v-.1l-.3-.1-.1 .2v.4h.4"/>
<path d="M208.9 175.6l.5-.1-.1-.2h-.2l-.2 .1 .1 .5h.3M209 169.7v.1M209 169.8h.4M209.4 169.2l-.4 .1v.4M209.4 168.9v.9M209.4 173.8l-.4 .1 .4 .2v.2h-.4M209.8 170.4v.9h.4M209.8 169.5l.4-.1v-.2h-.3l-.1 .1v.5h.4M210 171.9v.9h-.3l-.1-.5h.4M210.2 175.3h.4M210.3 175v.8l.3 .1M210.5 170.4v.1"/>
<path d="M210.5 170.7v.6M210.6 169.2v.6M210.8 173.4v1M210.8 173.8l-.3-.1-.1 .2 .1 .4h.3M210.9 175.4l.3-.1 .1 .6M210.9 175v.9M210.9 169.2l-.3 .2M211 171.9v.9h.4v-.5h-.4M211.2 169.8h.4M211.2 169.2l.4 .1v.4M211.2 169.2v.9M211.3 173.4v.1"/>
<path d="M211.3 173.7v.7M211.4 170.7h-.3l-.2 .2 .1 .4h.4M211.6 169.7v.1M211.7 175.6l.4-.1v-.2h-.3l-.1 .1v.5h.4M211.7 171l.5-.1-.1-.2h-.2l-.2 .1 .1 .5h.3M211.8 172.2l.2 .7M212 172.9l-.2 .3M212 173.8l-.3 .1 .3 .2v.2h-.3M212.1 169.2h.3l.1 .6M212.2 172.2l-.2 .7M212.3 173.7h.4M212.5 173.4v.8l.2 .2"/>
<path d="M212.5 169.4l-.5 .2 .2 .2h.3M212.6 170.8l.4-.1v.6M212.6 170.7v.6M212.9 169.7l.1 .1M213 169.8h.3M213 173.7v.7M213.1 175v.9h.5M213.2 172.3l.2-.1 .2 .2v.4l-.3 .1-.1-.4 .4-.1M213.3 173.7l-.3 .2M213.3 169.2l-.4 .1v.4M213.3 168.9v.9M213.6 173.4v.1"/>
<path d="M213.6 173.7v.7M213.8 170.7l-.4 .1 .4 .3v.2h-.4M213.9 175h.1M213.9 175.3v.6M214 172.3l.3-.1 .2 .2-.1 .4h-.4M214 172.2v1M214 173.8l.3-.1 .2 .2-.1 .4h-.4M214 173.4v1M214.2 171l.4-.1v-.2h-.3l-.1 .1v.5h.4M214.3 168.9v.9M214.3 169.3h.6M214.7 175.3h-.2l-.2 .2 .1 .4h.3"/>
<path d="M214.9 172.3l.2-.1 .2 .2-.1 .4h-.3M214.9 172.2v1M214.9 168.9v.9M214.9 173.7v.6h.4M215 171.2v.1M215.1 175.6l.4-.1v-.2h-.3l-.1 .1v.5h.4M215.3 173.7v.7M215.3 169.2h.4v.6M215.6 173.7h.4M215.7 171.9v.8l.2 .2M215.7 169.4l-.4 .2 .1 .2h.3M215.7 173.4v.8l.3 .2"/>
<path d="M215.9 175.3v.6M215.9 175.4l.4-.1v.6M216.2 169.2v.6M216.2 172h.1M216.2 172.2v.7M216.2 174.1l.5-.1-.1-.2-.2-.1-.2 .2 .1 .4h.3M216.3 172h-.1M216.4 169.2l-.2 .2M216.5 170.4l.3 .5M216.8 170.9v.4M217.1 172.3l-.3-.1-.2 .2 .1 .4h.4M217.1 170.4l-.3 .5"/>
<path d="M217.1 175.3l-.4 .1 .4 .2v.3h-.4M217.2 169.2h-.3l-.2 .2 .1 .4h.4M217.2 168.9v.9M217.4 170.8h.4v.5l-.4-.1zM217.5 172.3l.2-.1 .2 .2v.5h-.3l-.1-.4 .4-.1M217.5 173.8l-.3-.1-.2 .2 .1 .4h.4M217.5 173.4v1M217.5 175.6l.4-.1v-.2h-.3l-.1 .1v.5h.4M217.5 169.2l.2 .6 .2-.4 .2 .4 .1-.6M218.2 170.7l.1 .6 .4-.1M218.3 171.9v.9h.4v-.5h-.4M218.5 173.8h.4v.5h-.4z"/>
<path d="M218.6 169.2h.3l.1 .6M218.7 170.7v.6M218.8 175.3h.3M219 169.4l-.5 .2 .2 .2h.3M219.1 175l-.2 .1v.8M219.2 171.9v.8l.1 .2M219.4 173.8h.3l.1 .6M219.4 173.7v.7M219.4 169.2v.6M219.4 175.4h.5l-.1 .5-.4-.1zM219.6 172.5l.5-.1-.1-.1-.2-.1-.2 .2 .1 .4h.3M219.7 170.8l.2-.1 .2 .1"/>
<path d="M219.7 170.7v.6M219.7 169.2l-.3 .2M220 169.5l.4-.1v-.2h-.3l-.1 .1v.5h.4M220.1 170.8l.3-.1 .1 .6M220.1 170.8v.5M220.3 175.3v.6M220.6 175.3l-.3 .2M220.8 173.8h.3l.1 .6M220.9 170.7h.4v.6M221 171.9v.8l.2 .2M221.2 174l-.5 .2 .2 .2 .3-.1M221.3 175.3h.4"/>
<path d="M221.3 170.9l-.4 .2 .1 .2h.3M221.4 168.9v.9h.4M221.4 175v.8l.3 .1M221.5 172.3l.3-.1 .1 .2v.4l-.3 .1-.1-.4 .4-.1M221.6 173.7v.7M221.6 173.8h.4v.6M221.7 170.7l.2 .6M221.9 171.3l-.2 .3M222 175.4l.3-.1 .1 .6M222 175v.9M222.1 170.7l-.2 .6M222.2 168.9v.1"/>
<path d="M222.2 169.2v.6M222.3 172.2l.2 .7 .1-.5 .2 .5 .2-.7M222.8 175.6l.4-.1v-.2h-.3l-.1 .1v.5h.4M223 173.4v.2M223 169.2h-.3l-.1 .2v.4h.4M223.1 170.8h.4l-.1 .5-.3-.1zM223.3 173.4v.2M223.4 169.5l.4-.1v-.2h-.3l-.1 .1v.5h.4M223.6 174.4l.3-1 .3 1M223.7 174.1h.5M223.9 170.7h.3l.2 .2-.1 .4h-.4M223.9 170.4v.9"/>
<path d="M223.9 172.3h.4v.5h-.4zM224.2 169.3l.4-.1v.6M224.2 169.2v.6M224.5 175.3l-.3 .1 .3 .2v.3h-.3M224.6 170.7h.4M224.8 170.4v.8l.2 .1M224.8 172.2v.7M225 175.3h.2l.2 .2-.1 .4h-.3M225 175.3v.9M225 173.5h-.4a.39 .39 0 0 0 .4 .5v.3h-.5M225 172.2l-.2 .2M225.3 170.7h.3l.1 .6"/>
<path d="M225.4 169.2l-.4 .1 .4 .2v.3h-.4M225.7 170.9l-.5 .2 .2 .2h.3M225.8 175.6l.4-.1v-.2h-.3l-.1 .1v.5h.4M225.8 169.5l.4-.1v-.2h-.3l-.1 .1v.5h.4M225.9 172.3l.3-.1 .1 .2v.4l-.3 .1-.1-.4 .4-.1M226 173.4v1M226.1 170.4v.1M226.1 170.7v.6M226.6 170.8l.3-.1 .1 .6M226.6 170.7v.6M226.7 169.8l-.1 .1M227 173.5h-.5a.39 .39 0 0 0 .4 .5v.3h-.5"/>
<path d="M227 175.3h-.2l-.2 .2 .1 .4h.3M227.2 172.3l-.3-.1-.2 .2 .1 .4h.4M227.2 172.2v.8l-.2 .2-.2-.1M227.3 173.4v.2M227.4 175h.1M227.4 175.3v.6M227.5 168.9l.3 .9 .3-.9M227.6 172.2v.7M227.7 173.4v.2M227.7 175.3h.4M227.9 172.2l-.3 .2M228 170.7h.4v.6"/>
<path d="M228.1 175l-.2 .1v.8M228.2 172.5l.4-.1v-.1l-.3-.1-.1 .2v.4h.4M228.4 169.5l.5-.1-.1-.2h-.3l-.1 .1 .1 .5h.3M228.4 170.9l-.4 .2 .1 .2h.3M228.4 175h.1M228.4 175.3v.6M228.6 173.4h.4l.1 .2-.1 .3 .2 .3-.2 .2h-.4zM228.6 173.9h.4M229 172.5l.4-.1v-.1l-.3-.1-.1 .2v.4h.4M229.3 169.2v.6M229.3 175.3h-.3l-.2 .2 .1 .4h.4M229.4 174.4l.4-1 .3 1"/>
<path d="M229.5 169.2l-.2 .2M229.5 174.1h.5M229.8 170.7h-.2l-.2 .2 .1 .4h.3M230.2 169.2l-.4 .1 .4 .2v.3h-.4M230.2 171.9v.9h-.3l-.1-.5h.4M230.2 170.8h.4v.5l-.4-.1zM230.2 175v.8l.2 .1M230.6 168.9v.1M230.6 169.2v.6M230.7 175.3h.4v.6M230.9 173.5h-.5a.39 .39 0 0 0 .4 .5v.3h-.5M231.1 169.3h.4l-.1 .5-.3-.1z"/>
<path d="M231.1 170.7h.2l.2 .2-.1 .4h-.3M231.1 170.7v.9M231.1 172.2h.4M231.1 175.5l-.4 .2 .1 .2h.3M231.2 171.9v.8l.3 .2M231.3 173.4v1M231.6 175.4l.3-.1 .1 .6M231.6 175.3v.6M231.8 172.3h.4l-.1 .5h-.3zM231.8 170.7l.3 .6M231.9 169.3l.4-.1v.6M231.9 169.2v.6"/>
<path d="M232.1 171.3l-.3 .3M232.2 173.5h-.5a.39 .39 0 0 0 .5 .5l-.1 .3h-.4M232.3 170.7l-.2 .6M232.7 174.3l-.1 .2M232.8 175.3v.7l-.1 .2h-.3M232.8 175.3h-.2l-.2 .2 .1 .4h.3M233.2 171.9v.1M233.2 172.2v.7M233.2 170.8h.4v.5l-.4-.1zM233.3 169l.3-.1 .2 .2-.6 .7h.6M233.3 175.3v.6l.4-.1M233.6 173.4l.2 1 .2-.7 .1 .7 .3-1"/>
<path d="M233.6 172.2v.7M233.6 172.3h.4v.6M233.7 175.3v.6M233.9 170.7h.4M234.1 175.3h.4v.6M234.2 169.7v.1M234.3 170.4l-.2 .1v.8M234.5 175.5l-.4 .2 .1 .2h.3M234.6 169.8h.6M234.6 169.1l.3-.2v.9M234.7 173.4v1M235 172.2l.1 .7 .2-.5 .2 .5 .2-.7"/>
<path d="M235 170.7h.4M235 173.4h.6M235.2 170.4v.8l.2 .1M235.3 173.4v1M235.4 175.3v.7l-.2 .2h-.2M235.4 175.3h-.3l-.2 .2 .1 .4h.4M235.7 170.8l.4-.1v.6M235.7 170.4v.9M235.8 175.6l.4-.1v-.2h-.3l-.1 .1v.5h.4M235.9 173.9h.5M235.9 173.4v1M236 172.2v.7"/>
<path d="M236.3 172.2l-.3 .2M236.4 168.7a1.08 1.08 0 0 0 0 1.5M236.4 173.4v1M236.5 171l.5-.1-.1-.2h-.3l-.1 .1 .1 .5h.3M236.6 169.2h.4M236.6 171.9v.1M236.6 172.2v.7M236.8 168.9v.8l.2 .1M236.9 173.6l.1-.2 .4 .2v.5l-.1 .2-.4-.1zM236.9 172.2h.4M237.1 171.9v.8l.2 .2M237.3 169.3l.3-.1 .1 .6"/>
<path d="M237.3 168.9v.9M237.6 172h.1M237.6 175.3h-.3l-.1 .2 .1 .4h.3M237.6 175.3v.7l-.2 .2h-.2M237.6 172.2v.7M237.9 173.4v.8l.1 .2 .4-.2v-.8M237.9 170.4v.9h.5M238.1 175.4h.4l-.1 .5-.3-.1zM238.1 172.3h.3l.1 .6M238.1 172.2v.7M238.1 169.5l.4-.1v-.2h-.3l-.1 .1v.5h.4M238.7 170.4v.1"/>
<path d="M238.7 170.7v.6M238.7 173.4h.5M238.8 175.3l.2 .6 .3-.6M239 173.4v1M239.3 172.3l-.3-.1-.1 .2 .1 .4h.3M239.3 172.2v.8l-.2 .2-.2-.1M239.5 168.9v.1M239.5 170.7h-.2l-.2 .2 .1 .4h.3M239.6 175.6l.4-.1v-.2h-.3l-.1 .1v.5h.4M239.8 172.8v.1M239.8 172.9l-.1 .1M239.8 168.9v.1"/>
<path d="M239.9 171l.4-.1v-.2h-.3l-.1 .1v.5h.4M240 173.4l.3 1 .1-.7 .2 .7 .2-1M240.2 168.9v.9h.5M240.4 175.3v.6M240.7 175.3l-.3 .2M240.7 172.4l.4 .3-.1 .2-.3-.1M240.7 172.4h.1M240.7 170.8l.4-.1v.6M240.7 170.7v.6M241 168.9v.1M241 169.2v.6M241 175.4l.4-.1v.6"/>
<path d="M241 175.3v.6M241.1 174.4l.3-1 .3 1M241.1 172.3l-.4 .1M241.1 174.1h.5M241.5 172.3h.4v.5h-.4zM241.8 169.2h-.2l-.2 .2 .1 .4h.3M241.9 175h.1M241.9 175.3v.6M241.9 170.7l-.3 .1 .3 .3v.2h-.3M242 173.9h.4l.1-.4-.5-.1v1M242.2 169.5l.4-.1v-.2h-.3l-.1 .1v.5h.4M242.2 173.9l.3 .5"/>
<path d="M242.3 172.2h.3M242.3 175.3v.6M242.3 175.4l.4-.1v.6M242.3 171l.5-.1-.1-.2h-.3l-.1 .1 .1 .5h.3M242.6 171.9l-.2 .1v.9M242.8 172.2h.3M242.9 171.9v.8l.2 .2M242.9 173.9h.5v-.4l-.5-.1v1M243 169.3l.4-.1 .1 .6M243 169.2v.6M243.2 173.9l.3 .5M243.4 172.2l.2 .7 .1-.5 .2 .5 .2-.7"/>
<path d="M243.6 175.3h-.3l-.2 .2 .1 .4h.4M243.6 175.3v.7l-.2 .2h-.2M243.7 170.7h.4v.6M243.7 174.4l.4-1 .3 1M243.8 174.1h.5M244.1 170.9l-.4 .2 .1 .2h.3M244.2 169.2l-.3 .1 .3 .2v.3h-.3M244.4 172.3l.3-.1 .1 .2v.4l-.3 .1-.1-.4 .4-.1M244.4 170.7h.4M244.6 170.4v.8l.2 .1M244.6 169.5l.5-.1-.1-.2h-.2l-.2 .1 .1 .5h.3M245.2 173.4v1l-.5-1v1"/>
<path d="M245.3 172.2v.7M245.4 168.9v.1M245.5 173.4h.6M245.6 172.2l-.3 .2M245.8 168.9v.1M245.8 173.4v1M245.8 172.5l.5-.1-.1-.1-.2-.1-.2 .2 .1 .4h.3M246.1 168.7a1.08 1.08 0 0 1 0 1.5M246.4 173.4v1M246.7 172.8v.1M246.7 172.9l-.1 .1M246.8 169.2v.1"/>
<path d="M246.8 173.9h.4M246.9 169.8l-.1 .1M247.3 173.4h-.5v1h.5M248.2 173.5h-.5a.39 .39 0 0 0 .4 .5v.3h-.5M249.2 173.6l.1-.2 .4 .2v.5l-.1 .2-.4-.1zM250.1 173.9h.5v-.4l-.5-.1v1M250.4 173.9l.3 .5"/>
</g>
<g fill="none" stroke="#000" stroke-width=".2">
<path d="M25.9 37.3v1.2M25.9 39.6v1.2M25.9 37.7h-.4l-.2 .2 .1 .5h.5M26.5 38h.9M26.9 37.5v1M71.3 39.6v1.2M72.3 39.9v.9M92.1 30.1l.4 1.2 .4-1.2M93.3 30.1h.4l.2 .2-.2 .4 .2 .1 .1 .3-.2 .2h-.5zM93.3 30.7h.4M94.5 30.1v1l.2 .2 .4-.1 .1-.1v-1M96.4 30.1l-.6 .1v.3l.5 .3 .1 .3-.3 .2-.4-.1"/>
<path d="M25.9 40.1l-.4-.1-.2 .3 .1 .5h.5M26.5 40.4h.9M71.3 42v1.2M71.3 40.1l-.4-.1-.2 .3 .1 .5h.5M71.3 42.5l-.4-.1-.2 .3 .1 .5h.5M71.9 40.4h.9M71.9 42.8h.9M60.4 68.8l-.3-.1-.1 .2v.2l.4 .1v.3h-.4M61 68.8h.4l.1 .7M61 68.3v1.2M62.1 68.3v.1M62.1 68.7v.8"/>
<path d="M62.6 69.1l.6-.1-.1-.2-.3-.1-.2 .2v.6h.5M63.7 68.3v1l.1 .2M64.8 68.8l-.3-.1-.3 .2 .1 .6h.5M64.8 68.3v1.2M78.5 89.8v1.2M78.5 92.2v1.2M78.5 90.3l-.4-.1-.2 .3 .1 .5h.5M78.5 92.7l-.4-.1-.2 .2 .1 .6h.5M79 90.6h.9M79 93h.9M79.5 92.5v.9M176.9 187.8l.4-1.2 .4 1.2"/>
<path d="M177 187.5h.6M178.5 187.1l-.3-.1-.1 .2v.1l.4 .2v.2h-.4M179.1 187.1h.5v.7M179.1 186.6v1.2M180.2 186.6v1l.1 .2M180.8 186.6v.1M180.8 187v.8M181.4 187.1h.4l.1 .7M181.4 187v.8M183 187.1l-.4-.1-.2 .2 .1 .5h.5M183 187v1l-.3 .2-.2-.1M184.3 186.8l.2-.2a.4 .4 0 0 1 .5 .4v.4a.4 .4 0 0 1-.4 .4 .4 .4 0 0 1-.4-.4z"/>
<path d="M185.5 187.1l.3-.1 .3 .2-.1 .5h-.5M185.5 187v1.2M186.5 187.4l.6-.1-.1-.2-.3-.1-.2 .2 .1 .5h.4M187.6 186.6v1l.2 .2M188.2 186.6v1l.2 .2M188.9 187.1h.4l.1 .7M189.4 187.3l-.6 .2 .2 .3 .4-.1M189.9 187.3h1M191.4 186.6v1.2h.6M192.4 186.6a.6 .6 0 0 1 .7 .6 .6 .6 0 0 1-.7 .6zM194.3 186.8l.2-.2a.4 .4 0 0 1 .5 .4v.4a.4 .4 0 0 1-.4 .4 .4 .4 0 0 1-.4-.4zM195.6 187.1h.4l.1 .7"/>
<path d="M195.6 187v.8M196.6 187.1l.4-.1 .2 .2-.1 .5h-.5M196.6 186.6v1.2M197.7 187.1l.2-.1 .3 .1v.6h-.5zM198.8 187.1h.4l.1 .7M199.3 187.3l-.6 .2 .2 .3 .4-.1M199.9 187v.8M200.2 187l-.3 .2M201.1 187.1l-.3-.1-.2 .2 .1 .5h.4M201.1 186.6v1.2M202.9 187.1l-.3-.1-.2 .2 .1 .5h.4M202.9 186.6v1.2"/>
<path d="M203.4 187.4l.6-.1-.1-.2-.3-.1-.2 .2 .1 .5h.4M204.5 187.1l.4-.1 .2 .2-.1 .5h-.5M204.5 186.6v1.2M205.6 187l.1 .7h.4M206.1 187v.8M207.2 187.1l-.4-.1-.2 .2 .1 .5h.5M207.2 187v1l-.2 .2-.3-.1M208.3 187.1l-.4-.1-.2 .2 .1 .5h.5M208.3 187v1l-.3 .2-.2-.1M208.8 187.4l.6-.1-.1-.2-.3-.1-.2 .2v.5h.5M209.9 187v.8M210.2 187l-.3 .2"/>
</g>
<g fill="none" stroke="#848400" stroke-width=".2">
<path d="M255.7 69.5h.6l.6 .6-.6 .6h-.6zM255.7 71.9h.6l.6 .6-.6 .6h-.6zM255.7 74.3h.6l.6 .6-.6 .6h-.6zM256.3 67.1h.6v1.2h-.6l-.6-.6zM257.2 74.1h.6M257.2 69.3h.6M257.2 67h.6M257.2 71.7h.6M257.5 67v1.2M257.5 69.3v1.2M257.5 71.7v1.2M257.5 74.1v1.2"/>
<path d="M258.2 67a.6 .6 0 0 1 .7 .6 .6 .6 0 0 1-.7 .6zM258.2 69.3a.6 .6 0 0 1 .7 .6 .6 .6 0 0 1-.7 .6zM258.2 75.3v-1.2l.4 .9 .4-.9v1.2M258.9 71.9a.53 .53 0 0 0-.7 .4 .53 .53 0 0 0 .7 .5M259.4 69.5l.3-.2a.4 .4 0 0 1 .5 .4v.4a.4 .4 0 0 1-.4 .5 .4 .4 0 0 1-.4-.5zM259.4 67v1.2M259.4 71.7v1.2M259.6 72.2l.5 .7M260.1 71.7l-.7 .7M260.2 74.2h-.6v.4l.5 .2 .1 .3-.2 .2h-.4M255.7 110.1h.6l.6 .6-.6 .6h-.6zM255.7 112.5h.6l.6 .6-.6 .6h-.6z"/>
<path d="M257.3 110.4v.8M257.3 112.8v.8M257.3 110.5l.5-.1v.8M257.3 112.9l.5-.1v.8M258.2 112.4h.7M258.4 110.6l.6-.1v-.4l-.6-.1v1.2M258.6 112.4v1.2M258.7 110.6l.4 .6M259.3 113l.6-.1v-.4l-.6-.1v1.2M259.6 110.5h.4M259.6 113l.4 .6M260.2 110h-.6v1.2h.6"/>
<path d="M261.1 112.4l-.6 .1v.3l.5 .2 .1 .3-.2 .3-.4-.1M261.3 110l-.6 .1v.3l.5 .3 .1 .2-.2 .3-.5-.1M261.5 112.4h.7M261.8 110.5h.4M261.8 112.4v1.2M262.4 110h-.6v1.2h.6M262.7 110h.7M263.1 110v1.2M79.8 134.4h.4M80 132h.4M80.3 133.9h-.5v1.2M80.6 131.5h-.6v1.2"/>
<path d="M80.6 133.9h.7M80.9 131.5h.7M81 133.9v1.2M81.2 131.5v1.2M81.4 135.2h.9M81.7 132.8h.9M82.6 134.5l.6-.1v-.4l-.6-.1v1.2M82.7 131.5h.7M82.9 134.5l.4 .6M83.1 131.5v1.2M83.7 131.5l.8 1.2M83.7 133.9l.8 1.2"/>
<path d="M84.5 131.5l-.8 1.2M84.5 133.9l-.8 1.2M84.9 131.5a.6 .6 0 0 1 .7 .6 .6 .6 0 0 1-.7 .6zM84.9 133.9a.6 .6 0 0 1 .7 .6 .6 .6 0 0 1-.7 .6zM86 134h.6l.6 .6-.6 .6h-.6zM86.6 131.6h.6v1.2h-.6l-.6-.6z"/>
</g>
<g fill="none" stroke="#484848" stroke-width=".2">
<path d="M78.4 29l.5 .5M78.9 29.5v2.4M78.9 29.5h.4M80 29.2h.4l.1 .5-.3 .2h-.3M80 28.7l-.1 1.2M81.1 29.1l-.1 .8M81.1 28.7v.1M82.1 29.2l-.3-.1-.3 .3 .1 .5h.4M82.1 29.1l-.1 1-.2 .2h-.3M82.7 29.2h.4l.1 .5-.3 .2h-.3M82.7 29.1l-.2 1.2M83.7 29.2l.2-.1 .3 .1-.1 .7-.5-.1z"/>
<path d="M84.7 29.1l.1 .8 .3-.5 .1 .5 .4-.8M85.9 29.5l.6-.1v-.2h-.5l-.1 .6 .1 .1h.4M87.1 29.1l-.1 .8M87.4 29.1l-.4 .3M108.2 29l.5 .5M108.7 29.5h.5M108.7 29.5v2.4M109.8 29.2h.5v.5l-.2 .2h-.4M109.9 28.7l-.2 1.2M110.9 29.1l-.1 .8M111 28.7v.1M112 29.2l-.3-.1-.3 .3 .1 .5h.4"/>
<path d="M112 29.1l-.1 1-.3 .2h-.3M112.5 29.2h.5v.5l-.2 .2h-.4M112.5 29.1l-.1 1.2M113.6 29.2l.1-.1 .4 .1-.2 .7-.4-.1zM114.5 29.1l.2 .8 .3-.5 .1 .5 .3-.8M115.8 29.5l.6-.1-.1-.2h-.4l-.1 .6 .1 .1h.4M116.9 29.1l-.1 .8M117.3 29.1l-.4 .3"/>
</g>
<g fill="none" stroke="#008484" stroke-width=".2">
<path d="M34.6 38.4a.48 .48 0 0 1 .6 .5 .48 .48 0 0 1-.6 .5zM35.2 36.1a.42 .42 0 0 0-.6 .4 .42 .42 0 0 0 .6 .4M36 38.9h-.4M36.1 38.8l-.1-.3-.4-.1v1M36.1 38.8l-.1 .1M36.1 36.1a.42 .42 0 0 0-.6 .4 .42 .42 0 0 0 .6 .4M36.5 37h.5M36.5 36.3l.3-.3v1M36.5 38.7l.3-.3v1M36.5 39.4h.5M40.9 27.7v1l.2 .2h.3l.2-.2v-1M42.8 27.8h-.6v.4l.5 .2 .1 .3-.2 .2-.5-.1"/>
<path d="M43.3 28.3h.4M43.3 27.7h.4l.2 .2-.2 .4 .2 .1 .1 .3-.2 .2h-.5zM44.7 27.6l-.3 .9h.8M45 28.1v.8M45.6 28.9h.7M45.6 28l.3-.3v1.2M46.8 27.8l.2-.1a.64 .64 0 0 1 .4 .6 .64 .64 0 0 1-.4 .6l-.3-.5zM47.4 25.9l-.1 1-.4 .2M47.8 25.9h.8l-.4 .4 .3 .2v.5l-.1 .1-.6-.1M48.5 27.7h-.6l-.1 .6 .6-.1 .1 .6-.2 .1-.5-.1M49 28.4h1M51.1 27.8a.54 .54 0 0 0-.6 .5 .54 .54 0 0 0 .7 .5v-.4h-.2"/>
<path d="M51.7 28.3h.4M52.3 27.7h-.6v1.2M52.7 28.4h1M54 28.9l.4-1.2 .4 1.2M54.2 28.6h.5M55.2 33.7l.3 .9 .3-.9M56.2 33.7h.3l.2 .1-.2 .3 .2 .3-.2 .2h-.3zM56.2 34.1h.3M57.1 33.7v.7l.2 .2 .4-.2v-.7M57.6 31.3l.3 .9 .3-.9M58.5 31.3h.4l.1 .1-.1 .3 .2 .3-.2 .2h-.4zM58.5 31.7h.4"/>
<path d="M58.6 33.7h-.5a.4 .4 0 0 0 .5 .5l-.1 .4h-.4M58.8 34.7h1.5M59.1 38.5a.42 .42 0 0 0-.6 .4 .42 .42 0 0 0 .6 .4M59.5 31.3v.7l.2 .2 .3-.2v-.7M60.1 38.5a.42 .42 0 0 0-.6 .4 .42 .42 0 0 0 .6 .4M60.4 38.5l.4-.1 .2 .3-.6 .7h.6M60.4 33.9l.3-.2v.9M60.4 34.6h.6M61 31.3l-.5 .1a.4 .4 0 0 0 .4 .5v.3h-.5M97.8 34.8a.6 .6 0 0 1 .7 .6 .6 .6 0 0 1-.7 .6zM98.8 27.8h.4l.2 .2-.2 .4 .2 .1 .1 .3-.2 .2h-.5zM98.8 28.4h.4"/>
<path d="M99 36h.6M99 35.1l.3-.3v1.2M99.8 29l.4-1.2 .4 1.2M99.9 28.7h.6M100.9 27.8h.6M101.2 27.8v1.2M101.8 27.8h.8l-.5 1.2M102.2 26a.6 .6 0 0 1 .7 .6 .6 .6 0 0 1-.7 .6zM103.3 26h.7l-.4 .5 .4 .1v.5l-.2 .1-.5-.1M103.6 27.8l-.4 .1-.1 .2-.1 .7 .2 .2 .4-.1v-.6h-.4l-.2 .2M104.3 27.9l.1-.1a.64 .64 0 0 1 .5 .6 .64 .64 0 0 1-.5 .6l-.2-.4zM105.4 28.6h.9"/>
<path d="M106.7 27.8h.8l-.5 1.2M113.6 38.2h.7M113.6 37.3l.3-.3v1.2M114.3 34.9a.53 .53 0 0 0-.7 .5 .53 .53 0 0 0 .7 .5M114.9 37.1l.1-.1a.64 .64 0 0 1 .4 .6 .64 .64 0 0 1-.4 .6l-.3-.5zM115.4 34.8h-.5l-.1 .6 .6-.1v.6l-.1 .1-.5-.1M115.9 37.4l.1 .7h.4M116.4 37.4v.8M117 37.5h.4M117.6 37h-.6v1.2M118.5 26.1h.9M119 25.6v.9"/>
<path d="M119.8 25.3l.4 1.2 .4-1.2M121 25.3a.6 .6 0 0 1 .7 .6 .6 .6 0 0 1-.7 .6zM122.9 25.4a.53 .53 0 0 0-.8 .5 .53 .53 0 0 0 .8 .5M128.2 28.9h.9M128.7 28.5v.9M129.6 28.2h.7l-.4 .4 .3 .1v.6l-.1 .1-.5-.1M130.8 29.3v.1M131.3 28.2h.7l-.4 .4 .4 .1v.6l-.2 .1-.5-.1M132.3 28.2l.4 1.2 .4-1.2M139 36.5h.4M139.6 35.9h-.6v1.2M140.1 35.9h.4l.2 .2-.2 .4 .2 .1v.3l-.2 .2h-.4z"/>
<path d="M140.1 36.5h.4M141.2 36.2l.3-.3v1.2M141.2 37.1h.7M151.1 35.8l-.3 .9h.8M151.4 33.7a.53 .53 0 0 0-.8 .5 .53 .53 0 0 0 .8 .5M151.4 36.3v.8M151.8 34.8h.7M151.8 33.9l.4-.3v1.2M152 37v.1M152.5 35.9h.8l-.5 1.2M153.1 33.7l.2-.1a.64 .64 0 0 1 .4 .6 .64 .64 0 0 1-.4 .6l-.3-.5zM153.7 36.3l.1 .7h.4"/>
<path d="M154.2 36.3v.8M154.8 36.5h.4M155.4 35.9h-.6v1.2M160.2 37h.7M160.2 36.1l.3-.3v1.2M160.9 33.7a.53 .53 0 0 0-.7 .5 .53 .53 0 0 0 .7 .5M161.4 34.8h.7M161.4 33.9l.3-.3v1.2M161.5 35.9l.1-.1a.64 .64 0 0 1 .4 .6 .64 .64 0 0 1-.4 .6l-.3-.5zM162.5 33.7l.5-.1 .2 .3-.7 .9h.7M162.6 35.9l.2-.1a.64 .64 0 0 1 .4 .6 .64 .64 0 0 1-.4 .6l-.3-.5zM163.7 36.2v.8"/>
<path d="M163.7 36.3l.4-.1 .1 .8M164.8 36.3h.3M165.3 35.8h-.5v1.2M217.8 24.1h.9M218.3 23.7v.9M219 38.9a.54 .54 0 0 0-.6 .5 .54 .54 0 0 0 .7 .5v-.4h-.2M219.2 23.4h.7l-.4 .5 .3 .1v.5l-.1 .1-.5-.1M220.3 38.8v1.2l-.7-1.2v1.2M220.4 24.5v.1M220.9 38.8a.6 .6 0 0 1 .7 .6 .6 .6 0 0 1-.7 .6zM220.9 23.4h.7l-.4 .5 .4 .1v.5l-.2 .1-.5-.1M222 23.4l.4 1.2 .4-1.2"/>
<path d="M222.3 34.6h.7M222.3 33.7l.4-.3v1.2M223.1 31.3a.53 .53 0 0 0-.8 .5 .53 .53 0 0 0 .8 .5M223.6 33.5l.1-.1a.64 .64 0 0 1 .5 .6 .64 .64 0 0 1-.5 .6l-.2-.5zM224.1 31.2l-.4 .1-.1 .2-.1 .7 .2 .2 .4-.1v-.6h-.4l-.2 .2M224.7 33.5l.2-.1a.64 .64 0 0 1 .4 .6 .64 .64 0 0 1-.4 .6l-.3-.5zM224.9 31.7h.2M224.9 31.7l-.2-.2 .2-.3h.2l.2 .2-.2 .3M224.9 31.7l-.2 .3v.3l.2 .1h.2l.2-.2v-.4l-.2-.1M225.8 33.9l.5-.1v.8M225.8 33.8v.8M226.9 34h.4"/>
<path d="M227.4 33.4h-.5v1.2M229.8 38.9a.54 .54 0 0 0-.7 .5 .54 .54 0 0 0 .8 .5v-.4h-.3M231 38.8v1.2l-.6-1.2v1.2M231.6 38.8a.6 .6 0 0 1 .7 .6 .6 .6 0 0 1-.7 .6zM233.1 33.7l.3-.3v1.2M233.1 34.6h.7M233.8 31.3a.53 .53 0 0 0-.7 .5 .53 .53 0 0 0 .7 .5M234.3 32.4h.7M234.3 31.6l.3-.4v1.2M234.3 33.5l.2-.1a.64 .64 0 0 1 .4 .6 .64 .64 0 0 1-.4 .6l-.3-.5zM235.5 33.5l.1-.1a.64 .64 0 0 1 .5 .6 .64 .64 0 0 1-.5 .6l-.2-.5zM235.7 31.2l-.3 .8h.8"/>
<path d="M236 31.6v.8M236.5 33.9l.5-.1 .1 .8M236.5 33.8v.8M237.6 34h.4M238.2 33.4h-.6v1.2M239.4 38.9a.54 .54 0 0 0-.7 .5 .54 .54 0 0 0 .7 .5v-.4h-.2M240.6 38.8v1.2l-.7-1.2v1.2M241.2 38.8a.6 .6 0 0 1 .7 .6 .6 .6 0 0 1-.7 .6zM242.6 33.7l.4-.3v1.2M242.6 34.6h.7M243.4 31.3a.53 .53 0 0 0-.8 .5 .53 .53 0 0 0 .8 .5M243.8 31.6l.4-.4v1.2"/>
<path d="M243.8 32.4h.7M243.9 33.5l.2-.1a.64 .64 0 0 1 .4 .6 .64 .64 0 0 1-.4 .6l-.3-.5zM245 33.5l.2-.1a.64 .64 0 0 1 .4 .6 .64 .64 0 0 1-.4 .6l-.3-.5zM245.6 31.2h-.6v.6l.5-.1 .1 .6-.2 .1-.4-.1M246.1 33.9l.5-.1v.8M246.1 33.8v.8M247.2 34h.4M247.8 33.4h-.6v1.2M248.9 38.9a.54 .54 0 0 0-.7 .5 .54 .54 0 0 0 .8 .5v-.4h-.3M250.2 38.8v1.2l-.7-1.2v1.2M250.7 38.8a.6 .6 0 0 1 .7 .6 .6 .6 0 0 1-.7 .6zM252.2 34.6h.7"/>
<path d="M252.2 33.7l.3-.3v1.2M252.9 31.3a.53 .53 0 0 0-.7 .5 .53 .53 0 0 0 .7 .5M253.4 32.4h.7M253.4 31.6l.3-.4v1.2M253.4 33.5l.2-.1a.64 .64 0 0 1 .4 .6 .64 .64 0 0 1-.4 .6l-.3-.5zM254.6 33.5l.2-.1a.64 .64 0 0 1 .4 .6 .64 .64 0 0 1-.4 .6l-.3-.5zM255.1 31.2l-.3 .1-.2 .2-.1 .7 .3 .2 .4-.1-.1-.6h-.3l-.3 .2M255.7 33.9l.4-.1 .1 .8M255.7 33.8v.8M256.7 34h.4M257.3 33.4h-.6v1.2M258.5 38.9a.54 .54 0 0 0-.7 .5 .54 .54 0 0 0 .7 .5v-.4h-.2"/>
<path d="M259.7 38.8v1.2l-.7-1.2v1.2M260.3 38.8a.6 .6 0 0 1 .7 .6 .6 .6 0 0 1-.7 .6zM261.8 34.6h.6M261.8 33.7l.3-.3v1.2M262.5 31.3a.53 .53 0 0 0-.8 .5 .53 .53 0 0 0 .8 .5M262.9 32.4h.7M262.9 31.6l.4-.4v1.2M263 33.5l.2-.1a.64 .64 0 0 1 .4 .6 .64 .64 0 0 1-.4 .6l-.3-.5zM264 31.2h.8l-.5 1.2M264.1 33.5l.2-.1a.64 .64 0 0 1 .4 .6 .64 .64 0 0 1-.4 .6l-.3-.5zM265.2 33.9l.5-.1v.8M265.2 33.8v.8"/>
<path d="M266.3 34h.4M266.9 33.4h-.6v1.2M14.8 55.6v.6h.5v-.5l.6-.1 .1 .2-.1 .4M14.8 53.3h1.2M15.2 52.9l.4 .4M15.9 55.1h.1M16 53.9v.6M16 54.2h-1.2l.3 .3M16 52.9l-.5 .3M17 53.2h.6l.1-.5-.7-.1v1.2M17.3 53.2l.4 .6M18.1 52.6h.8l-.4 .5 .3 .1v.5l-.2 .1-.5-.1"/>
<path d="M34.6 40.8a.48 .48 0 0 1 .6 .5 .48 .48 0 0 1-.6 .5zM35.1 43.3h-.5a.4 .4 0 0 0 .5 .5l-.1 .3h-.4M35.5 43.2h.4l.1 .2-.1 .3 .2 .3-.2 .2h-.4zM35.5 43.7h.4M36.1 40.8v1l-.5-1v1M36.5 43.2v.8l.2 .2 .3-.2v-.8M36.5 41.8h.6M36.5 41.1l.3-.3v1M37.5 43.5l.2-.3v1M37.5 44.2h.5M51.6 57.6h-.5a.4 .4 0 0 0 .4 .5v.4h-.5M51.6 60h-.5a.4 .4 0 0 0 .4 .5v.4h-.5"/>
<path d="M52 58h.5M52 57.6v.9M52 59.9v1M52.5 57.6v.9M52.5 59.9v1M53 58h.3M53.4 57.6h-.4v.9h.4M53.4 59.9h-.4v1h.4M53.8 57.6v.9h.5M53.8 59.9v1h.5M53.9 55.2l-.5 .1a.4 .4 0 0 0 .5 .5l-.1 .3h-.4M54.3 55.2v.9"/>
<path d="M54.3 55.6h.6M54.6 57.6v.9h.5M54.6 59.9v1h.5M54.9 55.2v.9M55.2 58.6h.7M55.3 55.6h.4M55.8 55.2h-.5v.9h.5M56.2 55.2v.9h.5M56.6 52.8a.43 .43 0 0 0-.5 .5 .43 .43 0 0 0 .6 .3v-.3h-.2M56.6 57.6a.43 .43 0 0 0-.5 .4 .43 .43 0 0 0 .6 .4v-.3h-.2M56.6 60a.43 .43 0 0 0-.5 .4 .43 .43 0 0 0 .6 .4v-.3h-.2M57 55.2v.9h.4"/>
<path d="M57.5 56.2h.8M57.6 52.8v.9l-.5-.9v.9M57.6 57.6v.9l-.5-.9v.9M57.6 59.9v1l-.5-1v1M58.1 52.8a.48 .48 0 0 1 .5 .4 .48 .48 0 0 1-.5 .5zM58.1 59.9a.48 .48 0 0 1 .5 .5 .48 .48 0 0 1-.5 .5zM58.1 57.6a.48 .48 0 0 1 .5 .4 .48 .48 0 0 1-.5 .5zM58.1 45.6l-.5 .1a.4 .4 0 0 0 .5 .5l-.1 .3h-.4M58.5 45.6h.4l.1 .2-.1 .3 .2 .3-.2 .2h-.4zM58.5 43.2a.48 .48 0 0 1 .6 .5 .48 .48 0 0 1-.6 .5zM58.5 46.1h.4M58.6 40.8a.48 .48 0 0 1 .5 .5 .48 .48 0 0 1-.5 .5z"/>
<path d="M58.8 58.6h1.5M58.8 53.8h1.5M59 50.4a.43 .43 0 0 0-.6 .5 .43 .43 0 0 0 .6 .3v-.3h-.1M59 55.2a.43 .43 0 0 0-.6 .4 .43 .43 0 0 0 .6 .4v-.3h-.1M59.5 45.6v.8l.2 .2 .3-.2v-.8M59.5 41.3h.5v-.4l-.5-.1v1M60 50.4v.9l-.6-.9v.9M60 55.2v.9l-.6-.9v.9M60 43.2v1l-.5-1v1M60.4 55.2a.48 .48 0 0 1 .6 .4 .48 .48 0 0 1-.6 .5zM60.4 50.4a.48 .48 0 0 1 .6 .5 .48 .48 0 0 1-.6 .4zM60.4 40.9l.4-.1 .2 .3-.6 .7h.6"/>
<path d="M60.4 43.3l.4-.1 .2 .3-.6 .7h.6M60.4 45.7l.4-.1 .2 .3-.6 .7h.6M60.4 53.7h.6M60.4 53l.3-.2v.9M60.4 57.8l.3-.2v.9M60.4 58.5h.6M73.2 58h.6v-.5l-.6-.1v1.2M73.5 58l.4 .6M74.3 57.5l.5-.1 .2 .3-.7 .9h.7M75.7 58.1h1.2M76.1 57.7l.5 .4M76.8 59.8h.1"/>
<path d="M76.9 58.6v.7M76.9 59h-1.2l.4 .3M76.9 57.7l-.5 .3M94.8 44.9a.54 .54 0 0 0-.7 .5 .54 .54 0 0 0 .7 .5v-.4h-.2M96 44.8v1.2l-.6-1.2v1.2M96.6 44.8a.6 .6 0 0 1 .7 .6 .6 .6 0 0 1-.7 .6zM97.1 52.8h.9M97.6 52.4v.9M97.7 59.8h-.6l-.1 .6 .6-.1 .1 .6-.2 .1-.5-.1M98.5 52.1h.7l-.4 .4 .4 .1v.6l-.2 .1-.5-.1M99.8 53.2v.1M100.2 52.1h.7l-.4 .4 .4 .1v.6l-.2 .1-.5-.1"/>
<path d="M101.3 52.1l.4 1.2 .4-1.2M110.2 44.3a.54 .54 0 0 0-.7 .6 .54 .54 0 0 0 .8 .4v-.4h-.3M111.5 44.3v1.2l-.7-1.2v1.2M112 44.3a.6 .6 0 0 1 .7 .6 .6 .6 0 0 1-.7 .6zM124.5 58.7v1l.3 .2 .3-.1 .1-.1v-1M125.7 58.8l.5-.1 .2 .3-.7 .9h.7M139 50.8h.4M139.6 50.2h-.6v1.2M140.1 50.2h.4l.2 .3-.2 .3 .2 .1v.3l-.2 .2h-.4zM140.1 50.8h.4M141.2 50.3l.5-.1 .2 .4-.8 .8h.8M147.4 55.6a.54 .54 0 0 0-.7 .6 .54 .54 0 0 0 .7 .4v-.4h-.2"/>
<path d="M147.4 41.3a.54 .54 0 0 0-.7 .5 .54 .54 0 0 0 .7 .5v-.4h-.2M148.6 41.2v1.2l-.7-1.2v1.2M148.6 55.6v1.2l-.7-1.2v1.2M149.2 55.6a.6 .6 0 0 1 .7 .6 .6 .6 0 0 1-.7 .6zM149.2 41.2a.6 .6 0 0 1 .7 .6 .6 .6 0 0 1-.7 .6zM150.9 50.1l-.3 .8h.8M151.2 50.5v.8M151.4 48.1a.53 .53 0 0 0-.8 .4 .53 .53 0 0 0 .8 .5M151.8 51.2v.1M151.8 49.1h.7M151.8 48.3l.4-.4v1.2M152.3 50.1h.8l-.5 1.2"/>
<path d="M153 49.1h.7M153 48.3l.3-.4v1.2M153.5 50.5l.1 .7h.5M154.1 50.5v.8M154.6 50.7h.4M155.2 50.1h-.6v1.2M156.9 55.6a.54 .54 0 0 0-.7 .6 .54 .54 0 0 0 .8 .4v-.4h-.3M156.9 41.3a.54 .54 0 0 0-.7 .5 .54 .54 0 0 0 .8 .5v-.4h-.3M158.2 41.2v1.2l-.7-1.2v1.2M158.2 55.6v1.2l-.7-1.2v1.2M158.7 55.6a.6 .6 0 0 1 .7 .6 .6 .6 0 0 1-.7 .6zM158.7 41.2a.6 .6 0 0 1 .7 .6 .6 .6 0 0 1-.7 .6z"/>
<path d="M160.2 51.3h.7M160.2 50.5l.3-.4v1.2M160.9 48.1a.53 .53 0 0 0-.7 .4 .53 .53 0 0 0 .7 .5M161.4 48.3l.3-.4v1.2M161.4 49.1h.7M161.5 50.2l.1-.1a.64 .64 0 0 1 .4 .6 .64 .64 0 0 1-.4 .6l-.3-.4zM162.5 47.9h.7l-.4 .5 .4 .1v.5l-.2 .1-.5-.1M162.6 50.2l.2-.1a.64 .64 0 0 1 .4 .6 .64 .64 0 0 1-.4 .6l-.3-.4zM163.7 50.6h.4l.1 .7M163.7 50.5v.8M164.8 50.7h.3M165.3 50.1h-.5v1.2"/>
<path d="M178.4 49.6a.54 .54 0 0 0-.7 .6 .54 .54 0 0 0 .8 .5v-.4h-.2M179.7 49.6v1.2l-.7-1.2v1.2M180.2 49.6a.6 .6 0 0 1 .7 .6 .6 .6 0 0 1-.7 .6zM181.7 45.3h.7M181.7 44.5l.3-.4v1.2M182.4 42.1a.53 .53 0 0 0-.7 .5 .53 .53 0 0 0 .7 .4M182.9 43.2h.7M182.9 42.3l.3-.3v1.2M183 44.3l.1-.2a.64 .64 0 0 1 .4 .6 .64 .64 0 0 1-.4 .6l-.3-.4zM184.1 44.3l.2-.2a.64 .64 0 0 1 .4 .6 .64 .64 0 0 1-.4 .6l-.3-.4zM184.3 42.5l-.3 .2 .1 .3 .2 .2h.2l.2-.3v-.3l-.2-.1M184.3 42.5l-.3-.3 .3-.2h.2l.2 .2-.2 .3"/>
<path d="M184.3 42.5h.2M185.2 44.7l.4-.1 .1 .7M185.2 44.5v.8M186.3 44.7h.4M186.8 44.1h-.5v1.2M188 49.6a.54 .54 0 0 0-.7 .6 .54 .54 0 0 0 .7 .5v-.4h-.2M189.2 49.6v1.2l-.7-1.2v1.2M189.8 49.6a.6 .6 0 0 1 .7 .6 .6 .6 0 0 1-.7 .6zM191.3 45.3h.6M191.3 44.5l.3-.4v1.2M192 42.1a.53 .53 0 0 0-.7 .5 .53 .53 0 0 0 .7 .4M192.5 43.2h.6"/>
<path d="M192.5 42.3l.3-.3v1.2M192.5 44.3l.2-.2a.64 .64 0 0 1 .4 .6 .64 .64 0 0 1-.4 .6l-.3-.4zM193.7 44.3l.1-.2a.64 .64 0 0 1 .4 .6 .64 .64 0 0 1-.4 .6l-.3-.4zM194.3 42.5l-.2 .2-.4-.1v-.5l.4-.1 .2 .2-.1 .7-.1 .2-.4 .1M194.7 44.7l.5-.1v.7M194.7 44.5v.8M195.1 56.4h.9M195.6 55.9v1M195.8 44.7h.4M196.4 44.1h-.6v1.2M196.5 55.7h.7l-.4 .4 .3 .1v.5l-.1 .2-.5-.2M197.5 49.6a.54 .54 0 0 0-.7 .6 .54 .54 0 0 0 .8 .5v-.4h-.2"/>
<path d="M197.7 56.7v.2M198.2 55.7h.7l-.4 .4 .4 .1v.5l-.2 .2-.5-.2M198.8 49.6v1.2l-.7-1.2v1.2M199.3 55.7l.4 1.2 .4-1.2M199.4 49.6a.6 .6 0 0 1 .6 .6 .6 .6 0 0 1-.6 .6zM200.8 44.5l.4-.4v1.2M200.8 45.3h.7M201.6 42.1a.53 .53 0 0 0-.8 .5 .53 .53 0 0 0 .8 .4M202 42.1l.5-.1 .2 .3-.7 .9h.7M202.1 44.3l.1-.2a.64 .64 0 0 1 .5 .6 .64 .64 0 0 1-.5 .6l-.2-.4zM203.2 44.3l.2-.2a.64 .64 0 0 1 .4 .6 .64 .64 0 0 1-.4 .6l-.3-.4zM203.3 42.1l.1-.1a.64 .64 0 0 1 .5 .6 .64 .64 0 0 1-.5 .6l-.2-.5z"/>
<path d="M204.3 44.7l.4-.1 .1 .7M204.3 44.5v.8M205.4 44.7h.4M205.9 44.1h-.5v1.2M207.7 58.8v1.2l-.7-1.2v1.2M208.1 58.8h.6M208.4 58.8v1.2M209.1 58.8h.4l.3 .2-.3 .4 .3 .1v.3l-.2 .2h-.5zM209.1 59.4h.4M210.4 58.9l.2-.1a.64 .64 0 0 1 .4 .6 .64 .64 0 0 1-.4 .6l-.3-.4zM211.4 59.2l.4-.4v1.2M212.4 56.4v1l.2 .2h.2l.3-.2v-1"/>
<path d="M212.7 58.9l.1-.1a.64 .64 0 0 1 .4 .6 .64 .64 0 0 1-.4 .6l-.2-.4zM213.6 56.8l.3-.4v1.2M213.6 57.6h.7M214 58.8l-.3 .8h.7M214.3 59.2v.8M214.8 56.5l.2-.1a.64 .64 0 0 1 .4 .6 .64 .64 0 0 1-.4 .6l-.3-.4zM214.9 58.8h.4l.2 .2-.2 .4 .2 .1 .1 .3-.3 .2h-.4zM214.9 59.4h.4M216.1 59l.2-.2a.4 .4 0 0 1 .5 .4v.4a.4 .4 0 0 1-.4 .4 .4 .4 0 0 1-.4-.4zM216.2 59.7l.7 .4M217.4 60l-.1 .2M217.8 59.2l.4-.4v1.2"/>
<path d="M219 59.2l.3-.4v1.2M220.7 58.8h-.5l-.1 .6 .6-.1v.6l-.1 .1-.5-.1M226.1 50h.9M226.5 49.5v1M227.5 50.5h.7M227.5 49.6l.4-.3v1.2M228.5 49.3l.4 1.2 .4-1.2M229.9 49.8l-.2 .2v.3l.2 .2h.2l.3-.3v-.2l-.3-.2M229.9 49.8l-.2-.3 .2-.2h.2l.3 .2-.3 .3M229.9 49.8h.2M232.6 59.6h1.2M233 59.2l.5 .4"/>
<path d="M233.8 59.2l-.5 .3M235.3 59l.2 .3v.3l-.6 .1-.1-.4 .2-.3 .7 .1 .2 .2 .1 .3M14.5 64a.54 .54 0 0 0-.7 .5 .54 .54 0 0 0 .8 .5v-.4h-.3M15.8 63.9v1.2l-.7-1.2v1.2M16.3 63.9a.6 .6 0 0 1 .7 .6 .6 .6 0 0 1-.7 .6zM49.8 74.7h.8M50.1 77.5l-.1-.5-.5-.1-.1 .6h1.2M50.2 74.5v.8l-.8-.3M50.6 75.7v.7l-.8-.7-.4 .2 .1 .5M50.6 76.8l-.5 .4M51.1 62.7h.1M51.1 62.7l.4 .2 .1 .2-.2 .2-.4-.1"/>
<path d="M51.6 62.4h-.5v.3M52 60.4h.5M52 62.3v1M52 62.8h.5M52.5 62.3v1M53 60.4h.3M53 62.8h.3M53 76.4v.7M53 76.8h-1.2l.4 .3M53 75.1h-1.2l.9 .4-.9 .4h1.2M53.4 62.3h-.4v1h.4M53.8 62.3v1h.5"/>
<path d="M54.6 62.3v1h.5M55.2 61h.7M55.2 63.4h.7M56.6 62.4a.43 .43 0 0 0-.5 .4 .43 .43 0 0 0 .6 .4v-.3h-.2M57.6 62.3v1l-.5-1v1M58.1 62.3a.48 .48 0 0 1 .5 .5 .48 .48 0 0 1-.5 .5zM58.8 61h1.5M58.8 63.4h1.5M60.4 62.3h.6l-.3 .4 .2 .1v.4h-.5M60.4 60l.4-.1 .2 .3-.6 .7h.6M61.1 75.4v.6h.6l-.1-.5 .6-.1 .1 .2-.1 .4M61.1 73.2v.6h1.2"/>
<path d="M61.5 74.9h1.2M61.5 74.9v-.4l.2-.2 .5 .1v.5M61.7 73.4v.4M62.2 76.6h.1M62.3 77.1v.7l-.9-.7-.3 .2 .1 .5M62.3 78.2v.7M62.3 78.6h-1.2l.3 .3M63.4 76.8a.53 .53 0 0 0 .5 .8 .53 .53 0 0 0 .4-.8M64.5 75.7v.7l-.9-.7-.3 .2 .1 .5M64.5 75l-1.2-.5v.8M69.4 75.4v.6h.6v-.5l.5-.1 .1 .2-.1 .4M69.4 73.2v.6h1.2"/>
<path d="M69.7 71.1a.54 .54 0 0 0-.7 .6 .54 .54 0 0 0 .8 .5v-.4h-.3M69.8 74.9h1.2M69.9 74.9l-.1-.4 .3-.2 .5 .1v.5M70 73.4v.4M70.5 76.6h.1M70.6 77.1v.7l-.8-.7-.4 .2 .2 .5M70.6 78.6h-1.2l.4 .3M70.6 78.2v.7M71 71.1v1.2l-.7-1.2v1.2M71.5 71.1a.6 .6 0 0 1 .7 .6 .6 .6 0 0 1-.7 .6zM71.6 76.4v-.7l.5 .4 .1-.3h.5l.1 .1-.1 .5M71.7 74.7a.57 .57 0 0 1 .7-.2 .57 .57 0 0 1 .4 .6 .71 .71 0 0 1-1.2-.2z"/>
<path d="M71.7 76.8a.53 .53 0 0 0 .5 .8 .53 .53 0 0 0 .5-.8M75.7 68.8a.54 .54 0 0 0-.7 .5 .54 .54 0 0 0 .7 .5v-.4h-.2M75.7 60.4v.6h.6l-.1-.5 .6-.1 .1 .2-.1 .4M76.9 68.7v1.2l-.7-1.2v1.2M77.5 68.7a.6 .6 0 0 1 .7 .6 .6 .6 0 0 1-.7 .6zM94.9 62.2h-.5l-.1 .5h.6v.6l-.1 .1-.5-.1M94.9 76.5h-.5l-.1 .6 .6-.1v.6l-.1 .1-.5-.1M95.5 63.3v.1M95.5 77.6v.1M95.9 74.8l.5-.1 .1-.5-.6-.1v1.2M95.9 60.4h.6v-.5l-.6-.1v1.2M96 63.4h.7"/>
<path d="M96 62.5l.4-.3v1.2M96 76.9l.4-.4v1.2M96 77.7h.7M96.1 74.8l.4 .5M96.2 60.4l.4 .6M97.2 62.2v1.2M97.2 76.5v1.2M97.3 74.1l-.3 .8h.7M97.3 62.9l.4 .5M97.3 77.3l.4 .4M97.6 74.5v.8M97.7 62.6l-.5 .4"/>
<path d="M97.7 76.9l-.5 .5M107.4 76.7h.5M107.4 66.8h4.1M107.5 67.6h.5v-.4l-.5-.1v1M107.5 72.4l.5-.1v-.3l-.5-.1v.9M107.7 76.7v.9M107.7 67.6l.4 .5M107.7 72.4l.4 .4M108.2 77.1h.4M108.5 67.6h.3M108.5 72.3h.3M108.7 76.7h-.5v.9h.5"/>
<path d="M108.9 67.1h-.4v1h.4M108.9 71.9h-.4v.9h.4M109.3 72.3h.4M109.6 76.7l-.5 .1a.4 .4 0 0 0 .5 .5l-.1 .3h-.4M109.8 71.9h-.5v.9M109.8 67.2h-.5a.4 .4 0 0 0 .5 .5l-.1 .3h-.4M109.9 76.7h.5M110.2 76.7v.9M110.2 67.6h.4M110.7 67.1h-.5v1h.5M111 67.1h.5M111.2 67.1v1"/>
<path d="M118.5 61.7h.4M119 61.1h-.5v1.2M119.3 61.1h.7M119.7 61.1v1.2M120.4 61.2l.4-.1 .2 .3-.7 .9h.7M121.5 61.2l.5-.1 .2 .3-.8 .9h.8M122.6 61.1h.7l-.4 .4 .4 .2v.5l-.2 .1-.5-.1M123.8 61.2l.4-.1 .3 .3-.8 .9h.8M125 61.7h.6M125 61.1v1.2M125.6 61.1v1.2M126.2 61.1v1.2h.6"/>
<path d="M127.2 61.8h.9M128.7 61.7h.5l.1-.5-.6-.1v1.2M128.9 61.7l.4 .6M129.9 61.7h.4M130.4 61.1h-.5v1.2h.5M130.9 61.7h.4M131.5 61.1h-.6v1.2h.6M132 61.1v1.2h.6M137 67.1l.3 1 .3-1M137 69.5l.3 1 .3-1M137 71.9l.3 .9 .3-.9M137.4 76.7l.3 .9 .4-.9"/>
<path d="M137.4 79.1l.3 .9 .4-.9M138.5 67.2a.42 .42 0 0 0-.6 .4 .42 .42 0 0 0 .6 .4M138.5 69.6a.42 .42 0 0 0-.6 .4 .42 .42 0 0 0 .6 .4M138.5 72a.42 .42 0 0 0-.6 .4 .42 .42 0 0 0 .6 .4M138.9 79.1a.42 .42 0 0 0-.6 .4 .42 .42 0 0 0 .6 .4M138.9 76.8a.42 .42 0 0 0-.6 .3 .42 .42 0 0 0 .6 .4M138.9 72l.2-.1 .4 .1v.5l-.1 .3-.5-.1zM138.9 67.2l.2-.1 .4 .1v.5l-.1 .3-.5-.1zM138.9 69.6l.2-.1 .4 .1v.5l-.1 .3-.5-.1zM139.9 76.8a.42 .42 0 0 0-.6 .3 .42 .42 0 0 0 .6 .4M139.9 79.1a.42 .42 0 0 0-.6 .4 .42 .42 0 0 0 .6 .4M139.9 72.4l.5-.1v-.3l-.5-.1v.9"/>
<path d="M139.9 67.6h.5v-.4l-.5-.1v1M139.9 70h.5v-.4l-.5-.1v1M140.1 67.6l.4 .5M140.1 70l.4 .5M140.1 72.4l.4 .4M140.3 76.7v.9M140.3 79.1v.9M140.7 76.8l.2-.1 .4 .1v.5l-.1 .3-.5-.1zM140.7 79.2l.2-.1 .4 .1v.5l-.1 .3-.5-.1zM140.9 67.6h.3M140.9 70h.3M140.9 72.3h.3"/>
<path d="M141.3 67.1h-.4v1h.4M141.3 69.5h-.4v1h.4M141.3 71.9h-.4v.9h.4M141.7 67.7h.8M141.7 77.3h.8M141.7 79.6h.8M141.7 70.1h.8M141.7 72.5h.8M142.8 71.9h.6l-.3 .4h.3v.5h-.6M142.9 76.9l.3-.2v.9M142.9 69.6l.3-.1 .2 .3-.6 .7h.6M142.9 79.1h.3l.2 .2-.6 .7h.6"/>
<path d="M142.9 68.1h.5M142.9 67.4l.3-.3v1M142.9 77.6h.5M154.5 62.4h.9M154.9 61.9v.9M155.8 61.6h.8l-.4 .5 .3 .1v.5l-.1 .1-.6-.1M157.1 62.7v.1M157.6 61.6h.7l-.4 .5 .3 .1v.5l-.1 .1-.5-.1M158.6 61.6l.4 1.2 .4-1.2M205.3 62.3l.4 1 .3-1M205.5 74.3h.3l.2 .2-.2 .2 .2 .4-.2 .1h-.3zM205.5 74.7h.3"/>
<path d="M205.5 67.1h.3l.2 .2-.2 .3 .2 .3-.2 .2h-.3zM205.5 67.6h.3M205.5 69.5h.3l.2 .2-.2 .3 .2 .3-.2 .2h-.3zM205.5 71.9h.3l.2 .2-.2 .2 .2 .4-.2 .1h-.3zM205.5 70h.3M205.5 72.3h.3M206.3 71.9h.6l-.3 .4h.3v.5h-.6M206.4 69.6l.4-.1 .1 .3-.6 .7h.6M206.4 68.1h.5M206.4 67.4l.3-.3v1M206.6 74.2l-.2 .7h.6M206.8 62.4a.42 .42 0 0 0-.5 .4 .42 .42 0 0 0 .5 .4"/>
<path d="M206.8 74.6v.6M207.8 62.4a.42 .42 0 0 0-.6 .4 .42 .42 0 0 0 .6 .4M208.5 62.2a1.1 1.1 0 0 0 0 1.4M208.9 62.3h.3l.2 .2-.2 .3 .2 .3-.2 .2h-.3zM208.9 62.8h.3M209.7 62.2a1.1 1.1 0 0 1 0 1.4M211.4 60h.7M217.7 62.3l.3 1 .4-1M217.8 60h.7M219 60h.7M219.2 62.4a.42 .42 0 0 0-.6 .4 .42 .42 0 0 0 .6 .4M220.2 62.4a.42 .42 0 0 0-.6 .4 .42 .42 0 0 0 .6 .4"/>
<path d="M220.8 68.1l.3-1 .4 1M220.8 70.5l.3-1 .4 1M220.8 72.8l.3-.9 .4 .9M220.8 75.2l.3-.9 .4 .9M220.8 79.2l.2-.1 .4 .1v.5l-.1 .3-.5-.1zM220.9 62.2a1.1 1.1 0 0 0 0 1.4M220.9 75h.5M220.9 67.8h.5M220.9 70.2h.5M220.9 72.6h.5M221.1 63.3l.3-1 .3 1M221.2 63h.4"/>
<path d="M221.7 71.9h.6l-.3 .4h.2v.5h-.5M221.7 68.1h.6M221.7 69.6l.4-.1 .2 .3-.6 .7h.6M221.7 67.4l.3-.3v1M221.8 79.5h.3M222 74.2l-.3 .7h.6M222 62.2a1.1 1.1 0 0 1 0 1.4M222.2 74.6v.6M222.3 79.1h-.5v.9h.5M232.7 60.2a.57 .57 0 0 1 .7-.1 .57 .57 0 0 1 .3 .5 .71 .71 0 0 1-1.1-.2zM233.8 61.6h-1.2l.3 .3M233.8 61.3v.6"/>
<path d="M235.4 62l-.1-.6h-.4l-.1 .6h1.2M236 61.3l-.6 .4M236 60.2v.7l-.9-.7-.3 .2 .1 .5M51 99.2a.6 .6 0 0 1 .6 .6 .6 .6 0 0 1-.6 .6zM52.1 99.3l.4-.1 .3 .4-.8 .8h.8M55.4 86.7a.54 .54 0 0 0-.7 .5 .54 .54 0 0 0 .7 .5v-.4h-.2M56.6 86.6v1.2l-.7-1.2v1.2M57.2 86.6a.6 .6 0 0 1 .7 .6 .6 .6 0 0 1-.7 .6zM65.6 99.2a.6 .6 0 0 1 .7 .6 .6 .6 0 0 1-.7 .6zM67 99.2l-.3 .8h.7M67.3 99.6v.8M98.1 83.1a.54 .54 0 0 0-.7 .5 .54 .54 0 0 0 .8 .5v-.4h-.2"/>
<path d="M99.4 83v1.2l-.7-1.2v1.2M100 83a.6 .6 0 0 1 .6 .6 .6 .6 0 0 1-.6 .6zM107.5 91a.48 .48 0 0 1 .6 .5 .48 .48 0 0 1-.6 .5zM107.5 86.4l.2-.2 .4 .2v.5l-.1 .2-.5-.1zM107.5 93.4a.48 .48 0 0 1 .6 .5 .48 .48 0 0 1-.6 .4zM108.5 93.9l.4-.1 .1-.3-.5-.1v.9M108.5 92v-1l.3 .7 .3-.7v1M109 86.3h-.5a.4 .4 0 0 0 .5 .5l-.1 .3h-.4M110 86.3a.42 .42 0 0 0-.6 .4 .42 .42 0 0 0 .6 .4M110.4 86.2v1M137.4 95.8l.3 .9 .3-.9M137.4 81.4l.3 1 .4-1"/>
<path d="M137.4 83.8l.3 1 .4-1M138.3 96.3l.5-.1v-.3l-.5-.1v.9M138.6 96.3l.3 .4M138.6 93.4l.4 .9 .3-.9M138.9 83.9a.42 .42 0 0 0-.6 .4 .42 .42 0 0 0 .6 .4M138.9 81.5a.42 .42 0 0 0-.6 .4 .42 .42 0 0 0 .6 .4M139.3 96.2h.3M139.6 93.9l.5-.1v-.3l-.5-.1v.9M139.7 95.8h-.4v.9h.4M139.8 93.9l.3 .4M139.9 83.9a.42 .42 0 0 0-.6 .4 .42 .42 0 0 0 .6 .4M139.9 81.5a.42 .42 0 0 0-.6 .4 .42 .42 0 0 0 .6 .4"/>
<path d="M140.1 91l.3 1 .3-1M140.3 81.4v1M140.3 83.8v1M140.4 88.6l.3 1 .3-1M140.6 93.8h.3M140.7 95.8a.43 .43 0 0 0-.6 .5 .43 .43 0 0 0 .6 .3v-.3h-.2M140.7 81.6l.2-.2 .4 .2v.5l-.1 .3-.5-.1zM140.7 84l.2-.2 .4 .2v.5l-.1 .2h-.5zM141 93.4h-.4v.9h.4M141.1 91.5h.4l.1-.4-.5-.1v1M141.1 95.9l.2-.1 .4 .1v.5l-.1 .3-.5-.1zM141.3 89.1h.5v-.4l-.5-.1v1"/>
<path d="M141.7 82h.8M141.7 84.4h.8M141.9 93.4a.43 .43 0 0 0-.5 .5 .43 .43 0 0 0 .6 .4v-.4h-.2M142 91v1M142 91.5h.6M142.1 95.8v.8l.2 .1 .4-.1v-.8M142.3 88.6v1h.4M142.4 93.4v.9M142.6 91v1M142.8 81.4h.6l-.3 .4 .3 .1v.4h-.6M142.9 91l.3 .5M143 95.8h.5"/>
<path d="M143.1 88.6v1h.4M143.1 83.8l-.2 .7h.6M143.2 91.5v.5M143.2 95.8v.9M143.3 84.2v.6M143.4 93.4v.9l-.6-.9v.9M143.5 91l-.3 .5M176.9 99.1h.7l-.4 .5 .4 .1v.5l-.2 .1-.5-.1M177.7 97a.53 .53 0 0 0-.8 .5 .53 .53 0 0 0 .8 .5M178.1 97l.5-.1 .2 .4-.7 .8h.7M178.6 99.1h.7l-.4 .5 .4 .1v.5l-.2 .1-.5-.1M179.8 96.9l-.3 .1-.2 .2v.7l.2 .2 .4-.1-.1-.6h-.3l-.2 .2"/>
<path d="M179.8 99.5l.1 .7h.4M180.3 99.5v.8M180.9 99.7h.4M181.5 99.1h-.6v1.2M205.8 86.8h.2v.3M206 86.3a.45 .45 0 0 0-.6 .4 .45 .45 0 0 0 .6 .4M206 83.9a.43 .43 0 0 0-.6 .4 .43 .43 0 0 0 .6 .4v-.3h-.2M206 87.1h.1M207 83.8v1l-.6-1v1M207 86.2v1l-.6-1v1M207.4 86.2a.48 .48 0 0 1 .6 .5 .48 .48 0 0 1-.6 .5zM207.4 83.8a.48 .48 0 0 1 .6 .5 .48 .48 0 0 1-.6 .5z"/>
<path d="M207.7 97v1.2l-.7-1.2v1.2M208.1 97h.6M208.4 97v1.2M209.1 97h.4l.3 .3-.3 .3 .3 .1v.3l-.2 .2h-.5zM209.1 97.6h.4M210.4 97.2l.2-.2a.64 .64 0 0 1 .4 .6 .64 .64 0 0 1-.4 .6l-.3-.4zM211.4 97.4l.4-.4v1.2M211.4 98.2h.7M212.4 94.7v.9l.2 .3h.2l.3-.3v-.9M212.7 97.2l.1-.2a.64 .64 0 0 1 .4 .6 .64 .64 0 0 1-.4 .6l-.2-.4zM213.6 95.9h.7M213.6 95l.3-.3v1.2"/>
<path d="M214 97l-.3 .8h.7M214.3 97.4v.8M214.7 94.7h.7l-.4 .4 .3 .1v.5l-.1 .2-.5-.2M214.9 97h.4l.2 .3-.2 .3 .2 .1 .1 .3-.3 .2h-.4zM214.9 97.6h.4M216.1 97.2l.2-.2a.4 .4 0 0 1 .5 .4v.4a.4 .4 0 0 1-.4 .5 .4 .4 0 0 1-.4-.5zM216.2 98l.7 .4M217.4 98.2l-.1 .2M217.8 98.2h.7M217.8 97.4l.4-.4v1.2M219 97.4l.3-.4v1.2M219 98.2h.7"/>
<path d="M220.7 97h-.5l-.1 .6h.6v.5l-.1 .1-.5-.1M221.3 83.8v1l-.6-1v1M221.3 86.2v1l-.6-1v1M222.3 86.3a.42 .42 0 0 0-.6 .4 .42 .42 0 0 0 .6 .4M222.3 83.9a.42 .42 0 0 0-.6 .4 .42 .42 0 0 0 .6 .4M54.2 109.4a.54 .54 0 0 0-.7 .5 .54 .54 0 0 0 .7 .5v-.4h-.2M55.4 109.3v1.2l-.7-1.2v1.2M56 109.3a.6 .6 0 0 1 .7 .6 .6 .6 0 0 1-.7 .6zM62.5 109.4a.54 .54 0 0 0-.7 .5 .54 .54 0 0 0 .8 .5v-.4h-.2M63.8 109.3v1.2l-.7-1.2v1.2M64.4 109.3a.6 .6 0 0 1 .6 .6 .6 .6 0 0 1-.6 .6zM73.7 109h.9"/>
<path d="M74.2 108.5v.9M75.1 108.2h.7l-.4 .5 .4 .1v.5l-.2 .1-.5-.1M76.3 109.3v.1M76.8 108.2h.7l-.4 .5 .4 .1v.5l-.2 .1-.5-.1M77.9 108.2l.4 1.2 .4-1.2M83.1 112.1l.5-.1 .2 .3-.7 .9h.7M83.1 119.6l.5-.1 .2 .4-.7 .8h.7M83.9 110.4h.6l.1-.5-.7-.1v1.2M83.9 119l.6-.1 .1-.5-.7-.1v1.2M84.2 110.4l.4 .6M84.2 119l.4 .5M84.3 113.1v.1"/>
<path d="M84.9 112.1l.4-.1 .2 .3-.7 .9h.7M85 118.3h.8l-.5 1.2M85.3 119.5l.2 .3v.2l-.7 .7h.7M85.3 119.5l-.4 .1M85.7 109.8l-.4 .1-.2 .2v.7l.2 .2 .4-.1v-.6h-.4l-.2 .2M86.1 112v1.2M86.1 119.5v1.2M86.2 112.7l.3 .5M86.5 112.4l-.4 .4M86.5 119.9l-.4 .5M93.5 117.1a.6 .6 0 0 1 .7 .6 .6 .6 0 0 1-.7 .6zM95.3 117.1h-.6l-.1 .6 .6-.1 .1 .6-.2 .1-.5-.1"/>
<path d="M107.5 110.1h.3l.2 .2-.2 .3 .3 .3-.2 .2h-.4zM107.5 112.5h.3l.2 .2-.2 .3 .3 .3-.2 .2h-.4zM107.5 117.3h.3l.2 .2-.2 .2 .3 .4-.2 .1h-.4zM107.5 114.9h.3l.2 .2-.2 .3 .3 .3-.2 .2h-.4zM107.5 119.7h.3l.2 .2-.2 .2 .3 .4-.2 .1h-.4zM107.5 103.4h.3M107.5 110.6h.3M107.5 113h.3M107.5 115.4h.3M107.5 117.7h.3M107.5 101h.3M108 100.6h-.5v.9h.5"/>
<path d="M108 103h-.5v.9h.5M108.4 103.4h.3M108.4 101h.3M108.8 103h-.4v.9h.4M108.8 100.6h-.4v.9h.4M109 117.4a.42 .42 0 0 0-.6 .4 .42 .42 0 0 0 .6 .4M109 110.2a.42 .42 0 0 0-.6 .4 .42 .42 0 0 0 .6 .4M109 112.6a.42 .42 0 0 0-.6 .4 .42 .42 0 0 0 .6 .4M109 115a.42 .42 0 0 0-.6 .4 .42 .42 0 0 0 .6 .4M109 119.8a.42 .42 0 0 0-.6 .4 .42 .42 0 0 0 .6 .3M109.2 103a.48 .48 0 0 1 .6 .4 .48 .48 0 0 1-.6 .5zM109.4 110.1h.3l.2 .2-.2 .3 .3 .3-.2 .2h-.4z"/>
<path d="M109.4 117.3h.3l.2 .2-.2 .2 .3 .4-.2 .1h-.4zM109.4 114.9h.3l.2 .2-.2 .3 .3 .3-.2 .2h-.4zM109.4 119.7h.3l.2 .2-.2 .2 .3 .4-.2 .1h-.4zM109.4 112.5h.3l.2 .2-.2 .3 .3 .3-.2 .2h-.4zM109.4 110.6h.3M109.4 113h.3M109.4 115.4h.3M109.4 117.7h.3M109.8 100.7a.42 .42 0 0 0-.6 .3 .42 .42 0 0 0 .6 .4M110.1 103.9l.3-.9 .3 .9M110.2 103.6h.4M110.4 112.5v.8l.2 .2 .3-.2v-.8"/>
<path d="M110.4 110.1v.8l.2 .2 .3-.2v-.8M110.4 114.9v.8l.2 .2 .3-.2v-.8M110.4 117.3v.8l.2 .1 .3-.1v-.8M110.4 119.7v.8l.2 .1 .3-.1v-.8M110.7 100.6l-.5 .1a.4 .4 0 0 0 .5 .5l-.1 .3h-.4M110.9 103h.5M111.2 103v.9M111.6 103.9l.3-.9 .3 .9M111.7 103.6h.5M111.9 112.6h-.5a.4 .4 0 0 0 .4 .5v.3h-.5M111.9 119.7l-.5 .1a.4 .4 0 0 0 .4 .5v.3h-.5M111.9 110.2h-.5a.4 .4 0 0 0 .4 .5v.3h-.5"/>
<path d="M111.9 114.9l-.5 .1a.4 .4 0 0 0 .4 .5v.3h-.5M111.9 117.3l-.5 .1a.4 .4 0 0 0 .4 .5v.3h-.5M112.2 117.3h.6l-.3 .4h.3v.5h-.6M112.2 115l.4-.1 .2 .3-.6 .7h.6M112.2 113.5h.6M112.2 112.8l.3-.3v1M112.3 110.2l.2-.1a.46 .46 0 0 1 .3 .5 .46 .46 0 0 1-.4 .4l-.2-.3zM112.5 119.6l-.3 .7h.6M112.7 120v.6M138.1 103.9l.4-.9 .3 .9M138.1 106.3l.4-1 .3 1M138.1 108.7l.4-1 .3 1"/>
<path d="M138.1 111.1l.4-1 .3 1M138.1 113.5l.4-1 .3 1M138.1 115.9l.4-1 .3 1M138.1 118.2l.4-.9 .3 .9M138.2 103.6h.5M138.2 106h.5M138.2 108.4h.5M138.2 110.8h.5M138.2 113.2h.5M138.2 115.6h.5M138.2 118h.5M139.6 119.8a.42 .42 0 0 0-.5 .4 .42 .42 0 0 0 .5 .3"/>
<path d="M139.6 117.4a.42 .42 0 0 0-.5 .4 .42 .42 0 0 0 .5 .4M139.6 103a.42 .42 0 0 0-.5 .4 .42 .42 0 0 0 .5 .4M139.6 107.8a.42 .42 0 0 0-.5 .4 .42 .42 0 0 0 .5 .4M139.6 105.4a.42 .42 0 0 0-.5 .4 .42 .42 0 0 0 .5 .4M139.6 110.2a.42 .42 0 0 0-.5 .4 .42 .42 0 0 0 .5 .4M139.6 112.6a.42 .42 0 0 0-.5 .4 .42 .42 0 0 0 .5 .4M139.6 115a.42 .42 0 0 0-.5 .4 .42 .42 0 0 0 .5 .4M140.1 107.7h.3l.2 .2-.2 .3 .2 .3-.2 .2h-.3zM140.1 117.3h.3l.2 .2-.2 .2 .2 .4-.2 .1h-.3zM140.1 114.9h.3l.2 .2-.2 .3 .2 .3-.2 .2h-.3zM140.1 112.5h.3l.2 .2-.2 .3 .2 .3-.2 .2h-.3zM140.1 119.7h.3l.2 .2-.2 .2 .2 .4-.2 .1h-.3z"/>
<path d="M140.1 103h.3l.2 .1-.2 .3 .2 .3-.2 .2h-.3zM140.1 105.3h.3l.2 .2-.2 .3 .2 .3-.2 .2h-.3zM140.1 110.1h.3l.2 .2-.2 .3 .2 .3-.2 .2h-.3zM140.1 103.4h.3M140.1 105.8h.3M140.1 108.2h.3M140.1 110.6h.3M140.1 113h.3M140.1 115.4h.3M140.1 117.7h.3M141 112.5v.8l.2 .2 .4-.2v-.8M141 119.7v.8l.2 .1 .4-.1v-.8"/>
<path d="M141 107.7v.8l.2 .2 .4-.2v-.8M141 103v.7l.2 .2 .4-.2v-.7M141 105.3v.8l.2 .2 .4-.2v-.8M141 110.1v.8l.2 .2 .4-.2v-.8M141 114.9v.8l.2 .2 .4-.2v-.8M141 117.3v.8l.2 .1 .4-.1v-.8M142.5 117.3l-.5 .1a.4 .4 0 0 0 .5 .5l-.1 .3h-.4M142.5 103h-.5a.4 .4 0 0 0 .5 .5l-.1 .4h-.4M142.5 110.2h-.5a.4 .4 0 0 0 .5 .5l-.1 .3h-.4M142.5 107.8h-.5a.4 .4 0 0 0 .5 .5l-.1 .3h-.4M142.5 105.4h-.5a.4 .4 0 0 0 .5 .5l-.1 .4h-.4M142.5 112.6h-.5a.4 .4 0 0 0 .5 .5l-.1 .3h-.4"/>
<path d="M142.5 114.9l-.5 .1a.4 .4 0 0 0 .5 .5l-.1 .3h-.4M142.5 119.7l-.5 .1a.4 .4 0 0 0 .5 .5l-.1 .3h-.4M142.8 110.1h.6l-.3 .4 .3 .1v.4h-.6M142.8 119.7h.7l-.4 .9M142.9 107.8l.3-.1 .2 .3-.6 .7h.6M142.9 105.6l.3-.3v1M142.9 106.3h.5M143 103h.1a.46 .46 0 0 1 .3 .4 .46 .46 0 0 1-.4 .5l-.1-.4zM143.1 112.5l-.2 .6h.6M143.3 117.3l-.4 .2v.6l.2 .1h.3l-.1-.5h-.2l-.2 .1M143.3 112.8v.7M143.4 114.9h-.5v.5l.4-.1 .1 .5h-.5"/>
<path d="M153.2 112.4a.6 .6 0 0 1 .7 .6 .6 .6 0 0 1-.7 .6zM154.3 112.4h.8l-.5 1.2M159.6 107.3l.5-.1 .2 .3-.7 .9h.7M160.4 105.6h.6v-.5l-.6-.1v1.2M160.7 105.6l.4 .6M160.8 108.3v.1M161.3 107.3l.5-.1 .2 .3-.7 .9h.7M162.2 105.5l-.2 .3-.3-.1-.1-.6 .4-.1 .2 .2v.7l-.2 .3h-.3M162.5 107.2v1.2M162.6 107.9l.4 .5M163 107.6l-.5 .4M163.7 103.5h.9"/>
<path d="M164.1 103.1v.9M165 102.8h.8l-.4 .5 .3 .1v.5l-.1 .1-.6-.1M166.3 103.9v.1M166.8 102.8h.7l-.4 .5 .3 .1v.5l-.1 .1-.5-.1M167.8 102.8l.4 1.2 .4-1.2M173.6 104.6a.54 .54 0 0 0-.6 .6 .54 .54 0 0 0 .7 .4v-.4h-.2M174.9 104.5v1.2l-.7-1.2v1.2M175.5 104.5a.6 .6 0 0 1 .7 .6 .6 .6 0 0 1-.7 .6zM178.1 100.2v.1M205.3 100.6l.4 .9 .3-.9M205.5 105.3h.3l.2 .2-.2 .3 .2 .3-.2 .2h-.3zM205.5 107.7h.3l.2 .2-.2 .3 .2 .3-.2 .2h-.3z"/>
<path d="M205.5 105.8h.3M205.5 108.2h.3M205.5 110.1h.3l.2 .2-.2 .3 .2 .3-.2 .2h-.3zM205.5 110.6h.3M205.5 112.5h.3l.2 .2-.2 .3 .2 .3-.2 .2h-.3zM205.5 113h.3M206.3 110.1h.6l-.3 .4 .3 .1v.4h-.6M206.4 107.8l.4-.1 .1 .3-.6 .7h.6M206.4 105.6l.3-.3v1M206.4 106.3h.5M206.6 112.5l-.2 .6h.6M206.8 100.7a.42 .42 0 0 0-.5 .3 .42 .42 0 0 0 .5 .4"/>
<path d="M206.8 112.8v.7M207.8 100.7a.42 .42 0 0 0-.6 .3 .42 .42 0 0 0 .6 .4M208.5 100.4a1.1 1.1 0 0 0 0 1.5M208.9 100.6h.3l.2 .1-.2 .3 .2 .3-.2 .2h-.3zM208.9 101h.3M209.7 100.4a1.1 1.1 0 0 1 0 1.5M217.7 100.6l.3 .9 .4-.9M219.2 100.7a.42 .42 0 0 0-.6 .3 .42 .42 0 0 0 .6 .4M220.2 100.7a.42 .42 0 0 0-.6 .3 .42 .42 0 0 0 .6 .4M220.8 106.3l.3-1 .4 1M220.8 108.7l.3-1 .4 1M220.8 111.1l.3-1 .4 1"/>
<path d="M220.8 113.5l.3-1 .4 1M220.8 117.4l.2-.1 .4 .1v.5l-.1 .3-.5-.1zM220.9 100.4a1.1 1.1 0 0 0 0 1.5M220.9 106h.5M220.9 108.4h.5M220.9 110.8h.5M220.9 113.2h.5M221.1 101.5l.3-.9 .3 .9M221.2 101.2h.4M221.7 110.1h.6l-.3 .4 .2 .1v.4h-.5M221.7 107.8l.4-.1 .2 .3-.6 .7h.6M221.7 106.3h.6"/>
<path d="M221.7 105.6l.3-.3v1M221.8 117.7h.3M222 112.5l-.3 .6h.6M222 100.4a1.1 1.1 0 0 1 0 1.5M222.2 112.8v.7M222.3 117.3h-.5v.9h.5M59.4 136.4h.9M59.8 136v.9M60.7 135.7h.8l-.4 .5 .3 .1v.5l-.1 .1-.6-.1M62 136.8v.1M62.5 135.7h.7l-.4 .5 .3 .1v.5l-.1 .1-.5-.1M63.5 135.7l.4 1.2 .4-1.2"/>
<path d="M84.3 120.6v.1M86.2 120.3l.3 .4M93.5 124.3a.6 .6 0 0 1 .7 .6 .6 .6 0 0 1-.7 .6zM95.2 124.3l-.3 .1-.2 .2-.1 .7 .3 .2 .4-.1-.1-.6h-.3l-.3 .2M107.5 134h.3l.2 .2-.2 .3 .3 .3-.2 .2h-.4zM107.5 131.6h.3l.2 .2-.2 .3 .3 .3-.2 .2h-.4zM107.5 122.1h.3l.2 .1-.2 .3 .3 .3-.2 .2h-.4zM107.5 124.5h.3l.2 .1-.2 .3 .3 .3-.2 .2h-.4zM107.5 126.8h.3l.2 .2-.2 .3 .3 .3-.2 .2h-.4zM107.5 136.4h.3l.2 .2-.2 .3 .3 .3-.2 .2h-.4zM107.5 138.8h.3l.2 .2-.2 .2 .3 .4-.2 .1h-.4zM107.5 124.9h.3"/>
<path d="M107.5 127.3h.3M107.5 132.1h.3M107.5 134.5h.3M107.5 136.9h.3M107.5 139.2h.3M107.5 120.1h.3M107.5 122.5h.3M108.5 138.8a.48 .48 0 0 1 .5 .5 .48 .48 0 0 1-.5 .4zM108.5 131.6a.48 .48 0 0 1 .5 .5 .48 .48 0 0 1-.5 .5zM108.5 134a.48 .48 0 0 1 .5 .5 .48 .48 0 0 1-.5 .5zM108.5 136.4a.48 .48 0 0 1 .5 .5 .48 .48 0 0 1-.5 .5zM109 122.2a.42 .42 0 0 0-.6 .3 .42 .42 0 0 0 .6 .4"/>
<path d="M109 124.5a.42 .42 0 0 0-.6 .4 .42 .42 0 0 0 .6 .4M109 126.9a.42 .42 0 0 0-.6 .4 .42 .42 0 0 0 .6 .4M109.4 124.5h.3l.2 .1-.2 .3 .3 .3-.2 .2h-.4zM109.4 124.9h.3M109.4 126.8h.3l.2 .2-.2 .3 .3 .3-.2 .2h-.4zM109.4 127.3h.3M109.4 131.6h.3l.2 .2-.2 .3 .3 .3-.2 .2h-.4zM109.4 132.1h.3M109.4 134h.3l.2 .2-.2 .3 .3 .3-.2 .2h-.4zM109.4 134.5h.3M109.4 136.4h.3l.2 .2-.2 .3 .3 .3-.2 .2h-.4zM109.4 136.9h.3"/>
<path d="M109.4 138.8h.3l.2 .2-.2 .2 .3 .4-.2 .1h-.4zM109.4 139.2h.3M109.4 120.1h.3M109.4 122.1h.3l.2 .1-.2 .3 .3 .3-.2 .2h-.4zM109.4 122.5h.3M110.4 134v.8l.2 .2 .3-.2v-.8M110.4 124.5v.7l.2 .2 .3-.2v-.7M110.4 126.8v.8l.2 .2 .3-.2v-.8M110.4 131.6v.8l.2 .2 .3-.2v-.8M110.4 122.1v.7l.2 .2 .3-.2v-.7M110.4 136.4v.8l.2 .2 .3-.2v-.8M110.4 138.8v.8l.2 .1 .3-.1v-.8"/>
<path d="M111.9 136.4l-.5 .1a.4 .4 0 0 0 .4 .5v.3h-.5M111.9 126.9h-.5a.4 .4 0 0 0 .4 .5v.4h-.5M111.9 124.5h-.5a.4 .4 0 0 0 .4 .5v.4h-.5M111.9 138.8l-.5 .1a.4 .4 0 0 0 .4 .5v.3h-.5M111.9 131.7h-.5a.4 .4 0 0 0 .4 .5v.3h-.5M111.9 134.1h-.5a.4 .4 0 0 0 .4 .5v.3h-.5M111.9 122.1l-.5 .1a.4 .4 0 0 0 .4 .5v.3h-.5M112.2 138.8h.6l-.3 .4h.3v.5h-.6M112.2 126.8h.6l-.4 1M112.2 135h.6M112.2 136.5l.4-.1 .2 .3-.6 .7h.6M112.2 134.3l.3-.3v1"/>
<path d="M112.3 131.7l.2-.1a.46 .46 0 0 1 .3 .5 .46 .46 0 0 1-.4 .4l-.2-.3zM112.7 124.5l-.4 .2-.1 .5 .2 .2 .4-.1-.1-.4-.3-.1-.2 .2M112.8 122.1h-.5l-.1 .4h.5l.1 .4h-.6M138.1 125.4l.4-.9 .3 .9M138.1 127.8l.4-1 .3 1M138.1 130.2l.4-1 .3 1M138.1 132.6l.4-1 .3 1M138.1 135l.4-1 .3 1M138.1 137.4l.4-1 .3 1M138.1 139.7l.4-.9 .3 .9M138.1 120.6l.4-.9 .3 .9M138.2 125.1h.5"/>
<path d="M138.2 127.5h.5M138.2 129.9h.5M138.2 132.3h.5M138.2 134.7h.5M138.2 137.1h.5M138.2 139.5h.5M138.2 120.4h.5M139.1 124.5a.48 .48 0 0 1 .6 .4 .48 .48 0 0 1-.6 .5zM139.1 126.8a.48 .48 0 0 1 .6 .5 .48 .48 0 0 1-.6 .5zM139.1 129.2a.48 .48 0 0 1 .6 .5 .48 .48 0 0 1-.6 .5zM139.1 131.6a.48 .48 0 0 1 .6 .5 .48 .48 0 0 1-.6 .5zM139.1 134a.48 .48 0 0 1 .6 .5 .48 .48 0 0 1-.6 .5z"/>
<path d="M139.1 136.4a.48 .48 0 0 1 .6 .5 .48 .48 0 0 1-.6 .5zM139.1 138.8a.48 .48 0 0 1 .6 .5 .48 .48 0 0 1-.6 .4zM140.1 131.6h.3l.2 .2-.2 .3 .2 .3-.2 .2h-.3zM140.1 126.8h.3l.2 .2-.2 .3 .2 .3-.2 .2h-.3zM140.1 129.2h.3l.2 .2-.2 .3 .2 .3-.2 .2h-.3zM140.1 138.8h.3l.2 .2-.2 .2 .2 .4-.2 .1h-.3zM140.1 124.5h.3l.2 .1-.2 .3 .2 .3-.2 .2h-.3zM140.1 134h.3l.2 .2-.2 .3 .2 .3-.2 .2h-.3zM140.1 136.4h.3l.2 .2-.2 .3 .2 .3-.2 .2h-.3zM140.1 124.9h.3M140.1 127.3h.3M140.1 129.7h.3"/>
<path d="M140.1 132.1h.3M140.1 134.5h.3M140.1 136.9h.3M140.1 139.2h.3M140.1 120.1h.3M141 138.8v.8l.2 .1 .4-.1v-.8M141 124.5v.7l.2 .2 .4-.2v-.7M141 126.8v.8l.2 .2 .4-.2v-.8M141 129.2v.8l.2 .2 .4-.2v-.8M141 131.6v.8l.2 .2 .4-.2v-.8M141 134v.8l.2 .2 .4-.2v-.8M141 136.4v.8l.2 .2 .4-.2v-.8"/>
<path d="M142.5 138.8l-.5 .1a.4 .4 0 0 0 .5 .5l-.1 .3h-.4M142.5 124.5h-.5a.4 .4 0 0 0 .5 .5l-.1 .4h-.4M142.5 134.1h-.5a.4 .4 0 0 0 .5 .5l-.1 .3h-.4M142.5 129.3h-.5a.4 .4 0 0 0 .5 .5l-.1 .3h-.4M142.5 126.9h-.5a.4 .4 0 0 0 .5 .5l-.1 .4h-.4M142.5 131.7h-.5a.4 .4 0 0 0 .5 .5l-.1 .3h-.4M142.5 136.4l-.5 .1a.4 .4 0 0 0 .5 .5l-.1 .3h-.4M142.8 131.6h.6l-.3 .4 .3 .1v.4h-.6M142.9 129.3l.3-.1 .2 .3-.6 .7h.6M142.9 127.1l.3-.3v1M142.9 127.8h.5M143 124.5h.1a.46 .46 0 0 1 .3 .4 .46 .46 0 0 1-.4 .5l-.1-.4z"/>
<path d="M143.1 134l-.2 .7h.6M143.3 138.8l-.4 .2v.6l.2 .1h.3l-.1-.5h-.2l-.2 .1M143.3 134.3v.7M143.4 136.4h-.5v.5l.4-.1 .1 .5h-.5M176.6 137.6l.3-.3v1.2M176.6 138.5h.7M178.5 137.3v1.2l-.7-1.2v1.2M179 139.1a.6 .6 0 0 1 .6 .6 .6 .6 0 0 1-.6 .6zM179.7 137.8l-.3 .2h-.3l-.1-.6 .4-.1 .3 .2-.1 .7-.2 .2-.3 .1M180.1 139.4l.3-.3v1.2M180.1 138.5h.7M180.1 137.6l.4-.3v1.2"/>
<path d="M181.2 139.2l.5-.1 .2 .3-.7 .9h.7M181.5 137.2l-.2 .9h.7M181.8 137.7v.8M182.3 137.3l.3 1.2 .3-.9 .2 .9 .3-1.2M183.6 137.3h.7M184 137.3v1.2M198.7 132.1a.54 .54 0 0 0-.7 .5 .54 .54 0 0 0 .8 .5v-.4h-.2M200 132v1.2l-.7-1.2v1.2M200.6 132a.6 .6 0 0 1 .6 .6 .6 .6 0 0 1-.6 .6zM206 124.5a.43 .43 0 0 0-.6 .4 .43 .43 0 0 0 .6 .4v-.3h-.2M206 122.1a.43 .43 0 0 0-.6 .5 .43 .43 0 0 0 .6 .3v-.3h-.2M207 122.1v.9l-.6-.9v.9"/>
<path d="M207 124.5v.9l-.6-.9v.9M207.4 124.5a.48 .48 0 0 1 .6 .4 .48 .48 0 0 1-.6 .5zM207.4 122.1a.48 .48 0 0 1 .6 .4 .48 .48 0 0 1-.6 .5zM221.3 122.1v.9l-.6-.9v.9M221.3 124.5v.9l-.6-.9v.9M222.3 124.5a.42 .42 0 0 0-.6 .4 .42 .42 0 0 0 .6 .4M222.3 122.2a.42 .42 0 0 0-.6 .3 .42 .42 0 0 0 .6 .4M244 126.5h.9M244.5 126v.9M245.4 126.9h.7M245.4 126.1l.4-.4v1.2M246.5 125.7l.4 1.2 .4-1.2"/>
<path d="M247.8 126.2l-.2 .3 .1 .3 .1 .1h.3l.2-.2-.1-.4-.1-.1M247.8 126.2l-.2-.2 .2-.3h.3l.2 .2-.2 .3M247.8 126.2h.3M253.7 137.4h.7l-.4 .5 .4 .1v.5l-.2 .1-.5-.1M253.8 133.9h.6M253.8 133l.3-.3v1.2M253.8 135.2l.4-.1 .2 .3-.7 .9h.7M254 139.8l-.2 .8h.7M51.8 144.4h1.2M51.9 145.1a.57 .57 0 0 1 .7-.2 .57 .57 0 0 1 .4 .6 .71 .71 0 0 1-1.2-.3zM52.2 144l.5 .4M53 146.1v.7h1.2"/>
<path d="M53 146.4l.2-.3 .3 .1 .1 .6M53 146.4h-1.2l.4 .4M53 144l-.4 .3M53.4 145.1h.8M53.8 144.9v.8l-.8-.3M54.2 143.9v.7l-.8-.7-.4 .2 .1 .4M54.2 146.1l-.6 .4M56.4 154.3a.53 .53 0 0 0-.7 .5 .53 .53 0 0 0 .7 .5M57.5 154.2l-.6 .1v.3l.5 .3 .1 .2-.2 .3-.4-.1M61.4 159.5h1.2l-1.2 .6h1.2M61.4 155.5l1.2 .4-1.2 .4M61.5 153.2a.53 .53 0 0 0 .5 .8 .53 .53 0 0 0 .5-.8"/>
<path d="M61.5 154.4a.53 .53 0 0 0 .5 .8 .53 .53 0 0 0 .5-.8M61.5 158.3a.62 .62 0 0 1 .8-.1 .62 .62 0 0 1 .3 .7h-1.2zM64.3 149v.9l.2 .2h.3l.2-.2v-.9M64.9 151.3l-.2 .2-.3-.1-.1-.5 .4-.1 .2 .2v.7l-.2 .2-.3 .1M65.2 154.2l-.6 .1v.3l.5 .3 .1 .2-.2 .3-.4-.1M65.3 150.8h.8l-.4 .4 .3 .1v.5l-.1 .2-.6-.2M65.5 150.1h.7M65.5 149.3l.4-.3v1.1M66.4 154.3a.53 .53 0 0 0-.7 .5 .53 .53 0 0 0 .7 .5M66.6 149h.8l-.5 1.1M66.7 159a.6 .6 0 0 1 .6 .5 .6 .6 0 0 1-.6 .6zM66.9 154.2v1.2h.6"/>
<path d="M67.3 150.9a.53 .53 0 0 0-.8 .5 .53 .53 0 0 0 .8 .4M67.3 156.6a.6 .6 0 0 1 .7 .6 .6 .6 0 0 1-.7 .6zM67.9 159.1l.2-.1a.4 .4 0 0 1 .5 .4v.3a.4 .4 0 0 1-.4 .5 .4 .4 0 0 1-.4-.5zM67.9 154.2v1.2M68.1 154.7l.5 .7M68.4 150.8h-.6l-.1 .5h.6l.1 .5-.2 .2-.5-.2M68.5 156.6v1.2M68.6 154.2l-.7 .7M69.4 150.8h-.3l-.2 .2v.7l.2 .3 .4-.2-.1-.5-.3-.1-.2 .2M78.1 144.4h1.2M78.5 144l.5 .4M79.3 146.4l.2-.3 .3 .1 .1 .6"/>
<path d="M79.3 145.2a.68 .68 0 0 0-1.2 .1 .75 .75 0 0 0 1.2 0M79.3 146.1v.7h1.2M79.3 146.4h-1.2l.3 .4M79.3 145.2l.1 .5M79.3 144l-.5 .3M79.6 159.1l.4-.1 .2 .3-.7 .8h.7M79.8 158.4l.6-.1v-.4l-.6-.1v1.2M79.8 144.1l-.2-.2-.3 .2 .1 .3 .1 .1 .3-.2M79.8 144.1l.2-.2h.3l.2 .2-.1 .3-.1 .1h-.4l-.1-.2M79.8 144.1v.2M80.1 158.4l.4 .6M80.5 145v.7l-.7-.6-.3-.1-.2 .2"/>
<path d="M80.5 146.1l-.6 .4M80.9 157.9l.5-.1 .2 .3-.7 .9h.8l.3 .2-.1 .3-.7 .6h.8M81.4 159l-.1 .1M82.5 159v1.1M82.6 159.7l.3 .4M82.6 157.8h-.3l-.2 .2v.7l.2 .3 .4-.2-.1-.5-.3-.1-.2 .2M82.9 159.4l-.4 .4M84.1 144.4h1.2M84.5 144l.4 .4M85.3 146.4l.2-.3 .3 .1 .1 .6M85.3 145.2a.68 .68 0 0 0-1.2 .1 .75 .75 0 0 0 1.2 0M85.3 146.1v.7h1.2"/>
<path d="M85.3 145.2l.1 .5M85.3 146.4h-1.2l.3 .4M85.3 144l-.5 .3M86.5 146.1l-.6 .4M86.5 144.3l-1.2-.5v.8M86.5 145v.7l-.7-.6-.3-.1-.2 .2M107.5 146h.3l.2 .1-.2 .3 .3 .3-.2 .2h-.4zM107.5 146.4h.3M107.5 143.6h.3l.2 .2-.2 .2 .3 .3-.2 .2h-.4zM107.5 141.2h.3l.2 .2-.2 .2 .3 .4-.2 .1h-.4zM107.5 148.4h.3l.2 .1-.2 .3 .3 .3-.2 .2h-.4zM107.5 141.6h.3"/>
<path d="M107.5 144h.3M107.5 148.8h.3M108.5 146a.48 .48 0 0 1 .5 .4 .48 .48 0 0 1-.5 .5zM108.5 143.6a.48 .48 0 0 1 .5 .4 .48 .48 0 0 1-.5 .5zM108.5 141.2a.48 .48 0 0 1 .5 .5 .48 .48 0 0 1-.5 .4zM108.5 148.4a.48 .48 0 0 1 .5 .4 .48 .48 0 0 1-.5 .5zM109.4 148.4h.3l.2 .1-.2 .3 .3 .3-.2 .2h-.4zM109.4 143.6h.3l.2 .2-.2 .2 .3 .3-.2 .2h-.4zM109.4 146h.3l.2 .1-.2 .3 .3 .3-.2 .2h-.4zM109.4 146.4h.3M109.4 141.2h.3l.2 .2-.2 .2 .3 .4-.2 .1h-.4zM109.4 141.6h.3"/>
<path d="M109.4 144h.3M109.4 148.8h.3M110.4 148.4v.7l.2 .2 .3-.2v-.7M110.4 143.6v.7l.2 .2 .3-.2v-.7M110.4 146v.7l.2 .2 .3-.2v-.7M110.4 141.2v.8l.2 .1 .3-.1v-.8M111.9 143.6l-.5 .1a.4 .4 0 0 0 .4 .5v.3h-.5M111.9 141.2l-.5 .1a.4 .4 0 0 0 .4 .5v.3h-.5M111.9 146l-.5 .1a.4 .4 0 0 0 .4 .5v.3h-.5M111.9 148.4h-.5a.4 .4 0 0 0 .4 .5v.4h-.5M112.2 148.4h.6l-.4 .9M112.5 141.1l-.3 .7h.6"/>
<path d="M112.7 146l-.4 .2-.1 .5 .2 .2 .4-.1-.1-.4-.3-.1-.2 .2M112.7 141.5v.6M112.8 143.6h-.5l-.1 .4h.5l.1 .4h-.6M137.1 152.8h6.4M137.7 153.2h-.5a.4 .4 0 0 0 .5 .5l-.1 .3h-.4M138.1 142.1l.4-.9 .3 .9M138.1 153.1v.8l.2 .2 .4-.2v-.8M138.2 141.9h.5M138.8 155.2h4.7M139 156h.4l.1-.4-.5-.1v1M139.1 141.2a.48 .48 0 0 1 .6 .5 .48 .48 0 0 1-.6 .4zM139.4 151.2h.3"/>
<path d="M139.6 153.2h-.5a.4 .4 0 0 0 .5 .5v.3h-.5M139.8 155.5l.3 1 .1-.7 .2 .7 .3-1M139.9 150.7h-.5v1h.5M140 148.5l.1-.1 .4 .1 .1 .5-.2 .3-.4-.1zM140.1 141.2h.3l.2 .2-.2 .2 .2 .4-.2 .1h-.3zM140.1 153.6h.4l.1-.4-.5-.1v1M140.1 141.6h.3M140.3 151.2h.3M140.7 150.7h-.4v1h.4M141 141.2v.8l.2 .1 .4-.1v-.8M141 156h.5v-.4l-.5-.1v1M141 153.6h.3"/>
<path d="M141.2 156l.4 .5M141.5 148.4h-.5a.4 .4 0 0 0 .4 .5v.4h-.5M141.5 153.1h-.5v1h.5M141.7 150.8a.42 .42 0 0 0-.6 .4 .42 .42 0 0 0 .6 .4M142 156h.3M142.1 150.7v1h.5M142.4 148.4a.42 .42 0 0 0-.6 .4 .42 .42 0 0 0 .6 .4M142.4 153.1v1l-.5-1v1M142.4 155.5h-.4v1h.4M142.5 141.2l-.5 .1a.4 .4 0 0 0 .5 .5l-.1 .3h-.4M142.8 148.5l.2-.1 .4 .1v.5l-.1 .3-.5-.1zM142.8 141.2h.7l-.4 .9"/>
<path d="M142.9 150.7v1M142.9 153.1a.48 .48 0 0 1 .5 .5 .48 .48 0 0 1-.5 .5zM143 151.1l.4 .6M143.4 155.5v1l-.6-1v1M143.4 150.7l-.5 .6M176.6 145.6h.7M176.6 144.8l.3-.4v1.2M178.5 144.4v1.2l-.7-1.2v1.2M179 146.3a.6 .6 0 0 1 .6 .5 .6 .6 0 0 1-.6 .6zM179.7 145l-.3 .2-.3-.1-.1-.5 .4-.2 .3 .3-.1 .7-.2 .2h-.3M180.1 140.3h.7M180.1 146.6l.3-.3v1.1"/>
<path d="M180.1 147.4h.7M180.1 145.6h.7M180.1 144.8l.4-.4v1.2M181.3 146.4l.2-.1a.64 .64 0 0 1 .4 .5 .64 .64 0 0 1-.4 .6l-.3-.4zM181.5 144.4l-.2 .8h.7M181.8 144.8v.8M182.3 144.4l.3 1.2 .3-.8 .2 .8 .3-1.2M183.6 144.4h.7M184 144.4v1.2M214.2 149.7a.53 .53 0 0 0-.7 .5 .53 .53 0 0 0 .7 .5M214.8 150.1l.1-.1 .4 .1-.1 .7-.4-.1zM215.8 150.1h.5l.1 .7"/>
<path d="M215.8 150v.8M216.9 150.1h.5v.7M216.9 150v.8M217.7 150.9h.9M219 149.7l.1-.1a.64 .64 0 0 1 .5 .6 .64 .64 0 0 1-.5 .6l-.2-.4zM220 150.8h.7M220 150l.3-.4v1.2M220.8 147.5v1l-.4 .2M221.1 150l.6 .8M221.6 147.4l-.3 .9h.8M221.7 150l-.6 .8M221.9 147.9v.8"/>
<path d="M222.2 149.7l.2-.1a.64 .64 0 0 1 .4 .6 .64 .64 0 0 1-.4 .6l-.3-.4zM223.2 149.7l.5-.1 .2 .4-.7 .8h.7M224.1 150.9h1M225.3 150.8v-1.2l.4 .9 .4-.9v1.2M226.7 150.1h.5v.7M227.2 150.3l-.5 .2 .1 .3h.4M227.8 149.6v1.1l.2 .1M228.4 150.4l.5-.1v-.2l-.4-.1-.1 .2v.6h.5M253.7 147h.8l-.5 1.2M253.8 155.4h.6M253.8 154.5l.3-.3v1.2M254 149.9l-.2-.2 .2-.3h.2l.2 .2-.2 .3"/>
<path d="M254 149.9l-.2 .2v.4l.2 .1h.2l.2-.2v-.3l-.2-.2M254 149.9h.2M254.3 144.6l-.3 .1-.2 .2v.7l.2 .2 .4-.1-.1-.6h-.3l-.2 .2M254.3 140.2v.8M254.4 142.2h-.6v.6l.5-.1 .1 .6-.2 .1-.4-.1M254.4 152.3l-.2 .2h-.3l-.1-.6 .4-.1 .2 .2v.7l-.2 .2-.3 .1M255 154.3l.2-.1a.64 .64 0 0 1 .4 .6 .64 .64 0 0 1-.4 .6l-.3-.5zM261.9 142.6v1a.46 .46 0 0 1-.5 .4M263.3 142.6h-.7v.6l.2-.1 .4 .1 .2 .2-.1 .5-.2 .1-.5-.1M22.3 177.5l.3-.3v1.2M22.3 178.4h.7M23.4 177.3l.5-.1 .2 .3-.7 .9h.7"/>
<path d="M24.6 178.2v.2M24.9 175.1a.53 .53 0 0 0-.8 .5 .53 .53 0 0 0 .8 .5M25.3 175h.8l-.5 1.2M25.7 177.2h-.5l-.1 .5h.6v.5l-.1 .2-.5-.2M26.3 177.6h.4l.2 .2-.1 .5h-.5M26.3 177.6v1.2M27.4 177.7h.4M28 177.2h-.6v1.2M61.3 171.5a.54 .54 0 0 0-.7 .6 .54 .54 0 0 0 .8 .4v-.4h-.2M61.4 160.7a.54 .54 0 0 0 .6 .7 .54 .54 0 0 0 .5-.7h-.4v.2M62.6 171.4v1.2l-.7-1.2v1.2M63.2 171.4a.6 .6 0 0 1 .6 .6 .6 .6 0 0 1-.6 .6z"/>
<path d="M80.8 160v.1M140 168.4l.3-.9 .3 .9M140.1 168.1h.4M141.4 165.1a.43 .43 0 0 0-.5 .5 .43 .43 0 0 0 .6 .3v-.3h-.2M141.4 167.5a.43 .43 0 0 0-.5 .5 .43 .43 0 0 0 .6 .3v-.3h-.2M142.4 165.1v.9l-.5-.9v.9M142.4 167.5v.9l-.5-.9v.9M142.9 165.1a.48 .48 0 0 1 .5 .5 .48 .48 0 0 1-.5 .4zM142.9 167.5a.48 .48 0 0 1 .5 .4 .48 .48 0 0 1-.5 .5zM150.9 173.9a.54 .54 0 0 0-.6 .5 .54 .54 0 0 0 .7 .5v-.4h-.2M152.2 173.8v1.2l-.7-1.2v1.2M152.8 173.8a.6 .6 0 0 1 .7 .6 .6 .6 0 0 1-.7 .6z"/>
<path d="M229.8 161.9a.54 .54 0 0 0-.7 .6 .54 .54 0 0 0 .8 .5v-.4h-.3M231 161.9v1.2l-.6-1.2v1.2M231.6 161.9a.6 .6 0 0 1 .7 .6 .6 .6 0 0 1-.7 .6zM242.9 161.9a.54 .54 0 0 0-.7 .6 .54 .54 0 0 0 .8 .5v-.4h-.2M244.2 161.9v1.2l-.7-1.2v1.2M244.8 161.9a.6 .6 0 0 1 .6 .6 .6 .6 0 0 1-.6 .6zM18.3 187a.54 .54 0 0 0-.7 .6 .54 .54 0 0 0 .8 .5v-.4h-.2M19.6 187v1.2l-.7-1.2v1.2M20.1 187a.6 .6 0 0 1 .7 .6 .6 .6 0 0 1-.7 .6zM22.3 188.9l.3-.4v1.2M22.3 189.7h.7M23.4 188.6l.5-.1 .2 .4-.7 .8h.7"/>
<path d="M24.6 189.6v.1M24.9 190.8a.53 .53 0 0 0-.8 .5 .53 .53 0 0 0 .8 .5M25.6 191.2l-.3 .2 .1 .4 .2 .1h.2l.2-.2v-.4l-.2-.1M25.6 191.2l-.3-.2 .3-.3h.2l.2 .2-.2 .3M25.6 191.2h.2M25.7 188.5h-.5l-.1 .6 .6-.1v.6l-.1 .1-.5-.1M26.3 189l.4-.1 .2 .3-.1 .5h-.5M26.3 188.9v1.2M27.4 189.1h.4M28 188.5h-.6v1.2M30.8 186.4h.6M30.8 185.6l.3-.4v1.2"/>
<path d="M31.3 180.5l.4 .6M31.7 181.1v.6M31.9 185.3l.4-.1 .3 .4-.8 .8h.8M32.1 180.5l-.4 .6M32.4 180.6l.5-.1 .2 .3-.7 .9h.7M33.1 186.4v-1.2l.4 .9 .4-.9v1.2M34.4 185.2v1.2M34.4 185.8h.7M35.1 185.2v1.2M35.6 185.6h.6l-.6 .8h.6M44.6 187a.54 .54 0 0 0-.7 .6 .54 .54 0 0 0 .8 .5v-.4h-.3M45.9 187v1.2l-.7-1.2v1.2"/>
<path d="M46.4 187a.6 .6 0 0 1 .7 .6 .6 .6 0 0 1-.7 .6z"/>
</g>
<g fill="none" stroke="#840000" stroke-width=".31">
<path d="M109.7 37.1h2.8M146.7 35.9h2.9M156.3 35.9h2.8M218.4 33.5h2.9M229.2 33.5h2.8M238.7 33.5h2.9M248.3 33.5h2.8M257.8 33.5h2.9M146.7 50.3h2.9M156.3 50.3h2.8M177.8 44.3h2.8M187.3 44.3h2.9"/>
<path d="M196.9 44.3h2.9M57.1 76.6h2.9M65.5 76.6h2.8M173 99.3h2.9M24.6 179.8v2.8M24.6 184.6v2.8"/>
</g>
<g fill="none" stroke="#840000" stroke-width=".29">
<path d="M109.7 36.2h2.8M146.7 35h2.9M156.3 35h2.8M218.4 32.6h2.9M229.2 32.6h2.8M238.7 32.6h2.9M248.3 32.6h2.8M257.8 32.6h2.9M146.7 49.3h2.9M156.3 49.3h2.8M177.8 43.3h2.8M187.3 43.3h2.9"/>
<path d="M196.9 43.3h2.9M57.1 75.6h2.9M65.5 75.6h2.8M173 98.3h2.9M25.6 179.8v2.8M25.6 184.6v2.8"/>
</g>
<g fill="none" stroke="#840084" stroke-width=".2">
<path d="M93.5 119.5h.7M93.5 113l.6-.1v-.4l-.6-.1v1.2M93.8 113l.4 .6M93.8 119.5v1.2M94.4 119.5l.8 1.2M94.6 112.4l.8 1.2M95.2 119.5l-.8 1.2M95.4 112.4l-.8 1.2M152.7 107.6v1l-.4 .2M153.1 107.6h.7M153.5 107.6v1.2M154 108.8l.4-1.2 .4 1.2"/>
<path d="M154.2 108.4h.5M155.9 107.6a.54 .54 0 0 0-.7 .6 .54 .54 0 0 0 .7 .5v-.4h-.2"/>
</g>
<path d="M29.2 184.8h1.4M29.2 182.4h1.4" fill="none" stroke="#840000" stroke-width=".36"/>
<path d="M119.6 28.9h2.1M120.7 27.8v2.2" fill="none" stroke="#840000" stroke-width=".48"/>
<g fill="#840000" stroke="#840000" stroke-width=".35">
<path d="M218.6 154.8h.9v.2h-.9z" fill-rule="evenodd"/>
<path d="M218.6 152.4h.9v.3h-.9z" fill-rule="evenodd"/>
</g>
<g fill="#008400" stroke="#008400" stroke-width=".35">
<circle cx="95.6" cy="31.9" r=".43"/>
<circle cx="66.9" cy="70.1" r=".43"/>
<circle cx="66.9" cy="58.2" r=".43"/>
<circle cx="66.9" cy="60.5" r=".43"/>
<circle cx="70.5" cy="53.4" r=".43"/>
<circle cx="66.9" cy="31.9" r=".43"/>
<circle cx="66.9" cy="62.9" r=".43"/>
<circle cx="58.5" cy="70.1" r=".43"/>
<circle cx="58.5" cy="80.9" r=".43"/>
<circle cx="56.2" cy="80.9" r=".43"/>
<circle cx="76.5" cy="141.8" r=".43"/>
<circle cx="62.1" cy="141.8" r=".43"/>
<circle cx="76.5" cy="162.1" r=".43"/>
<circle cx="50.2" cy="154.9" r=".43"/>
<circle cx="21.5" cy="183.6" r=".43"/>
<circle cx="29.9" cy="181.2" r=".43"/>
<circle cx="29.9" cy="186" r=".43"/>
<circle cx="76.5" cy="115.5" r=".43"/>
<circle cx="86" cy="157.3" r=".43"/>
<circle cx="82.4" cy="154.9" r=".43"/>
<circle cx="151.7" cy="168.1" r=".43"/>
<circle cx="132.6" cy="33.1" r=".43"/>
<circle cx="148.1" cy="47.4" r=".43"/>
<circle cx="111.1" cy="31.9" r=".43"/>
<circle cx="156.5" cy="77.3" r=".43"/>
<circle cx="156.5" cy="82.1" r=".43"/>
<circle cx="156.5" cy="79.7" r=".43"/>
<circle cx="174.4" cy="72.5" r=".43"/>
<circle cx="156.5" cy="84.4" r=".43"/>
<circle cx="174.4" cy="96.4" r=".43"/>
<circle cx="199.5" cy="105.9" r=".43"/>
<circle cx="199.5" cy="108.3" r=".43"/>
<circle cx="230.6" cy="117.9" r=".43"/>
<circle cx="199.5" cy="125.1" r=".43"/>
<circle cx="199.5" cy="122.7" r=".43"/>
<circle cx="199.5" cy="86.8" r=".43"/>
<circle cx="219.8" cy="30.7" r=".43"/>
<circle cx="179.2" cy="41.4" r=".43"/>
<circle cx="188.8" cy="41.4" r=".43"/>
<circle cx="197.1" cy="62.9" r=".43"/>
<circle cx="228.2" cy="54.6" r=".43"/>
<circle cx="243.7" cy="152.5" r=".43"/>
<circle cx="243.7" cy="147.8" r=".43"/>
<circle cx="243.7" cy="143" r=".43"/>
<circle cx="154.1" cy="70.1" r=".43"/>
<circle cx="154.1" cy="72.5" r=".43"/>
<circle cx="157.7" cy="47.4" r=".43"/>
<circle cx="148.1" cy="33.1" r=".43"/>
<circle cx="157.7" cy="33.1" r=".43"/>
<circle cx="230.6" cy="79.7" r=".43"/>
<circle cx="235.4" cy="67.7" r=".43"/>
<circle cx="228.2" cy="62.9" r=".43"/>
<circle cx="240.1" cy="72.5" r=".43"/>
<circle cx="237.8" cy="70.1" r=".43"/>
<circle cx="242.5" cy="74.9" r=".43"/>
<circle cx="240.1" cy="30.7" r=".43"/>
<circle cx="230.6" cy="30.7" r=".43"/>
<circle cx="249.7" cy="30.7" r=".43"/>
</g>
</svg>
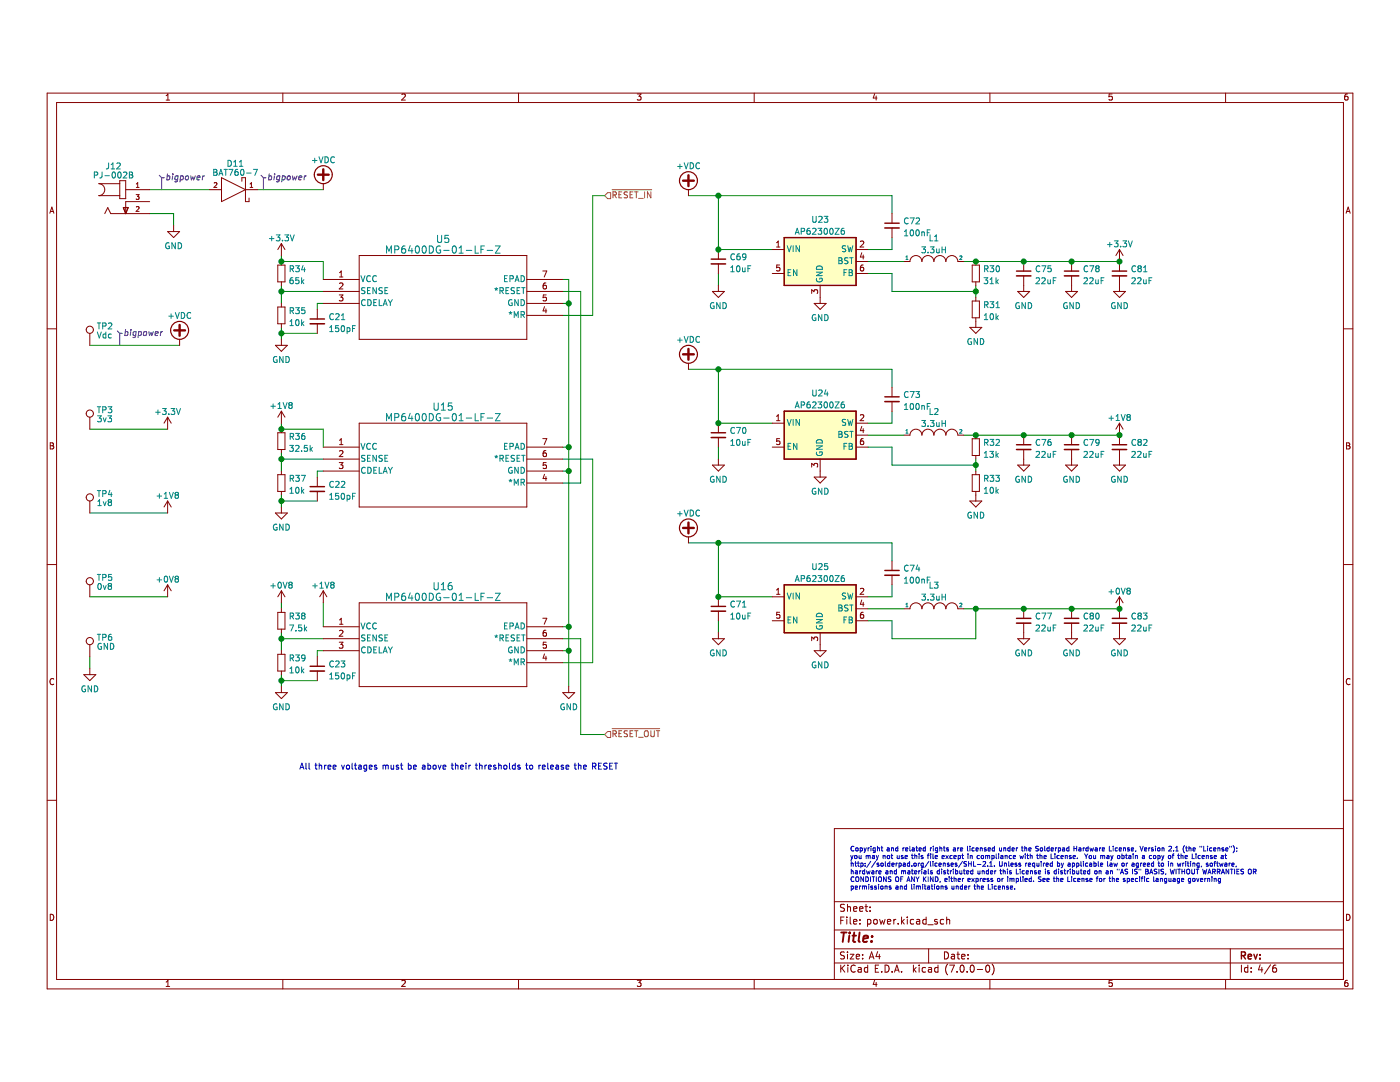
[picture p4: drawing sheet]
<svg xmlns="http://www.w3.org/2000/svg" width="279mm" height="216mm" viewBox="0 0 279 216" stroke-linecap="round" stroke-linejoin="round" font-family="sans-serif">
<path d="M0 9.2h279.4v206.7h-279.4z" fill-rule="evenodd" fill="#fff" stroke="#fff" stroke-width=".35"/>
<g fill="none" stroke="#840000" stroke-width=".2">
<path d="M9.4 18.6h260.6v178.7h-260.6zM33.2 20h.7M33.2 19.1l.3-.4v1.3M56.4 18.6v1.9M80.2 18.9l.5-.2 .2 .4-.8 .9h.8M103.5 18.6v1.9M127.2 18.7h.7l-.4 .5 .4 .1v.6l-.2 .1-.5-.1M150.5 18.6v1.9M174.6 18.7l-.3 .9h.7M174.9 19.2v.8M197.6 18.6v1.9M221.9 18.7h-.5l-.1 .6h.6v.6l-.1 .1-.5-.1"/>
<path d="M244.6 18.6v1.9M268.9 18.7l-.3 .1-.2 .2-.1 .7 .3 .3 .4-.1-.1-.6-.3-.1-.3 .2M11.3 20.5h256.8v174.9h-256.8zM23.9 36.7h-4.2a1.19 1.19 0 0 1 1.2 1.1 1.19 1.19 0 0 1-1.2 1.2h4.2M23.9 36.1h1.2v3.5h-1.2zM25.1 37.8h4.8M27.2 38.8h.6l-.4 .4 .3 .1v.4h-.5M27.2 37.4h.6M27.2 36.7l.3-.3v1M41.8 37.8h2.4M42.7 36.5l.4-.1 .2 .3-.6 .7h.6M44.2 35.5l4.8 2.3-4.8 2.4z"/>
<path d="M48.3 36.2v-.7h.7v4.7h.7v-.7M49 37.8h2.4M49.9 37.4h.6M49.9 36.7l.3-.3v1M64.5 36.7v1.1M137.4 37.8v1.2M9.9 42.5l.5-1.2 .4 1.2M10.1 42.2h.5M20.9 42.6l.6-1.2 .6 1.2h7.8M24.6 41.4h1l-.5 1.2zM27.2 41.3l.4-.1 .2 .3-.6 .7h.6M29.9 40.2h-4.8v2.4"/>
<path d="M33.5 46.2h2.3l-1.2 1.2zM34.6 45v1.2M55.4 52.9h1.5v3.3h-1.5zM56.2 48.6v2.4M56.2 52.2v.7M56.2 56.2v.8M56.2 48.6l-.8 1.2M56.2 48.6l.7 1.2M64.5 58.2h7.2M64.5 55.8h7.2M67.7 58.9h.7l-.4 .4 .4 .1v.5l-.2 .1-.5-.1M67.8 55.3h.6"/>
<path d="M67.8 54.4l.3-.3v1.2M67.8 56.6l.4-.1 .2 .3-.7 .9h.7M71.7 51h33.4v16.7h-33.4zM105.1 58.2h7.2M105.1 55.8h7.2M108.3 54.1h.8l-.5 1.2M109 56.5h-.4l-.2 .2v.7l.2 .3 .4-.2v-.5l-.4-.1-.2 .2M109 58.9h-.6v.5h.6v.5l-.2 .1-.4-.1M142.2 58.2h2.4l-1.2 1.2zM143.4 49.8v1.9M143.4 52.7v1.9M143.4 57v1.2"/>
<path d="M154.1 49.8h2.4M154.1 54.6h2.4M155 48.4l.3-.3v1.2M155 49.3h.7M155.6 52.9h-.6v.5h.5l.1 .6-.2 .1-.4-.1M162 58.6v-.8l.4 .4 .2-.3h.5l.1 .1-.1 .6M163.7 57v3.5M170.8 49.8h2.4M170.8 52.2h2.4M170.8 54.6h2.4M171.7 48.2l.5-.1 .2 .3-.8 .9h.8M172 50.4l-.3 .9h.7"/>
<path d="M172.3 52.9h-.4l-.1 .3-.1 .6 .2 .3 .4-.1v-.6l-.4-.1-.2 .3M172.3 50.9v.8M178 42.6v1.9M178 45.5v1.9M180.4 52.2h1.2a1.19 1.19 0 0 1 1.2-1.2 1.19 1.19 0 0 1 1.2 1.2 1.19 1.19 0 0 1 1.2-1.2 1.19 1.19 0 0 1 1.2 1.2 1.19 1.19 0 0 1 1.2-1.2 1.19 1.19 0 0 1 1.2 1.2 1.19 1.19 0 0 1 1.2-1.2 1.19 1.19 0 0 1 1.2 1.2h1.2M194 52.9h1.5v3.3h-1.5zM194.7 52.2v.7M194.7 56.2v.8M194.7 59.4v.7M203.1 58.2h2.4l-1.2 1.2zM204.3 52.2v1.9M204.3 55v3.2"/>
<path d="M212.7 58.2h2.4l-1.2 1.2zM213.9 52.2v1.9M213.9 55v3.2M222.2 58.2h2.4l-1.2 1.2zM223.4 49.8v4.3M223.4 55v3.2M223.4 49.8l-.7 1.2M223.4 49.8l.7 1.2M268.6 42.5l.5-1.2 .4 1.2M268.8 42.2h.5M9.4 65.6h1.9M17.9 66.5v2.4"/>
<path d="M35.8 67.7v1.2M55 68.9h2.3l-1.1 1.2zM55.4 61.3h1.5v3.3h-1.5zM56.2 60.5v.8M56.2 64.6v.7M56.2 67.7v1.2M63.3 61.7v2M63.3 64.6v1.9M64.5 60.5h7.2M105.1 60.5h7.2M105.1 62.9h7.2M108.7 61.2l-.3 .8h.7"/>
<path d="M109 61.6v.8M137.4 72.5v1.2M162.5 60.5h2.4l-1.2 1.2zM178 77.3v1.9M193.5 65.3h2.4l-1.2 1.2zM194 60.1h1.5v3.3h-1.5zM194.7 63.4v1.9M268.1 65.6h1.9M10 88.4h.4l.3 .2-.3 .3 .3 .2v.3l-.2 .2h-.5zM10 88.9h.4M17.9 83.2v2.4M17.9 100v2.4"/>
<path d="M33.5 100l-.8 1.2M33.5 83.2v2.4M33.5 100v2.4M33.5 100l.7 1.2M33.5 83.2l-.8 1.2M33.5 83.2l.7 1.2M55.4 86.4h1.5v3.3h-1.5zM55.4 94.7h1.5v3.4h-1.5zM56.2 82.1v2.3M56.2 85.6v.8M56.2 89.7v.7M56.2 94v.7"/>
<path d="M56.2 98.1v.7M56.2 82.1l-.8 1.1M56.2 82.1l.7 1.1M63.3 95.2v1.9M63.3 98.1v1.9M64.5 89.2h7.2M64.5 91.6h7.2M64.5 94h7.2M67.7 92.3h.7l-.4 .5 .4 .1v.5l-.2 .1-.5-.1M67.8 87.9l.3-.4v1.2M67.8 90l.4-.1 .2 .4-.7 .8h.7M67.8 88.7h.6"/>
<path d="M71.7 84.4h33.4v16.8h-33.4zM105.1 89.2h7.2M105.1 91.6h7.2M105.1 94h7.2M105.1 96.4h7.2M108.3 87.5h.8l-.5 1.2M108.7 94.6l-.3 .9h.7M109 95.1v.8M109 89.9l-.4 .1-.2 .2v.7l.2 .2 .4-.1v-.6h-.4l-.2 .2M109 92.3h-.6v.6l.6-.1v.6l-.2 .1-.4-.1M142.2 92.8h2.4l-1.2 1.2zM143.4 84.4v2"/>
<path d="M143.4 87.3v1.9M143.4 91.6v1.2M154.1 84.4h2.4M154.1 89.2h2.4M155 83.9h.7M155 83.1l.3-.4v1.2M155.6 87.5h-.6v.6l.5-.1 .1 .6-.2 .1-.4-.1M162 93.2v-.7l.4 .4 .2-.4h.5l.1 .2-.1 .5M162.5 95.2h2.4l-1.2 1.2zM163.7 91.6v3.6M170.8 84.4h2.4M170.8 89.2h2.4"/>
<path d="M170.8 86.8h2.4M171.7 82.9l.5-.2 .2 .4-.8 .8h.8M172 85.1l-.3 .8h.7M172.3 87.5l-.4 .1-.1 .2-.1 .7 .2 .2 .4-.1v-.6h-.4l-.2 .2M172.3 85.5v.8M178 80.1v2M180.4 86.8h1.2a1.19 1.19 0 0 1 1.2-1.2 1.19 1.19 0 0 1 1.2 1.2 1.19 1.19 0 0 1 1.2-1.2 1.19 1.19 0 0 1 1.2 1.2 1.19 1.19 0 0 1 1.2-1.2 1.19 1.19 0 0 1 1.2 1.2 1.19 1.19 0 0 1 1.2-1.2 1.19 1.19 0 0 1 1.2 1.2h1.2M193.5 100h2.4l-1.2 1.2zM194 94.7h1.5v3.4h-1.5zM194 87.5h1.5v3.4h-1.5zM194.7 86.8v.7M194.7 90.9v.7"/>
<path d="M194.7 94v.7M194.7 98.1v1.9M203.1 92.8h2.4l-1.2 1.2zM204.3 86.8v1.9M204.3 89.7v3.1M212.7 92.8h2.4l-1.2 1.2zM213.9 86.8v1.9M213.9 89.7v3.1M222.2 92.8h2.4l-1.2 1.2zM223.4 84.4v4.3M223.4 89.7v3.1M223.4 84.4l-.7 1.2"/>
<path d="M223.4 84.4l.7 1.2M268.7 88.4h.4l.3 .2-.3 .3 .3 .2v.3l-.2 .2h-.5zM268.7 88.9h.4M9.4 112.7h1.9M17.9 116.7v2.4M33.5 116.7v2.4M33.5 116.7l-.8 1.2M33.5 116.7l.7 1.2M55 102.4h2.3l-1.1 1.2zM56.2 101.2v1.2M56.2 117.9v2.4M56.2 117.9l-.8 1.2"/>
<path d="M56.2 117.9l.7 1.2M64.5 117.9v2.4M64.5 117.9l-.7 1.2M64.5 117.9l.7 1.2M137.4 107.1v1.2M143.4 119.1v1.9M154.1 119.1h2.4M155 117.7l.3-.3v1.2M155 118.6h.7M170.8 119.1h2.4M171.7 117.5l.5-.1 .2 .3-.8 .9h.8M172 119.7l-.3 .9h.7"/>
<path d="M178 111.9v1.9M178 114.8v1.9M223.4 119.1v4.3M223.4 119.1l-.7 1.2M223.4 119.1l.7 1.2M268.1 112.7h1.9M10.7 135.5a.54 .54 0 0 0-.7 .5 .54 .54 0 0 0 .7 .5M16.7 134.6h2.4l-1.2 1.2zM17.9 128.6v2.4M17.9 133.4v1.2M55 138.2h2.3l-1.1 1.2zM55.4 122.2h1.5v3.3h-1.5z"/>
<path d="M55.4 130.6h1.5v3.3h-1.5zM56.2 121.5v.7M56.2 125.5v.8M56.2 129.8v.8M56.2 133.9v.7M56.2 137v1.2M63.3 131v1.9M63.3 133.9v1.9M64.5 127.5h7.2M64.5 125.1h7.2M64.5 129.8h7.2M67.7 128.1h.7l-.4 .5 .4 .1v.5l-.2 .1-.5-.1"/>
<path d="M67.8 123.7l.3-.3v1.2M67.8 125.9l.4-.1 .2 .3-.7 .9h.7M67.8 124.6h.6M71.7 120.3h33.4v16.7h-33.4zM105.1 127.5h7.2M105.1 125.1h7.2M105.1 129.8h7.2M105.1 132.2h7.2M108.3 123.4h.8l-.5 1.2M108.7 130.5l-.3 .8h.7M109 130.9v.8M109 125.8h-.4l-.2 .2v.7l.2 .3 .4-.2v-.5l-.4-.1-.2 .2"/>
<path d="M109 128.1h-.6v.6h.6v.5l-.2 .1-.4-.1M112.3 138.2h2.4l-1.2 1.2zM113.5 137v1.2M142.2 127.5h2.4l-1.2 1.1zM143.4 122v1.9M143.4 126.3v1.2M154.1 123.9h2.4M155.6 122.2h-.6v.5h.5l.1 .6-.2 .1-.4-.1M162 127.8v-.7l.4 .4 .2-.3h.5l.1 .1-.1 .5M162.5 129.8h2.4l-1.2 1.2zM163.7 126.3v3.5M170.8 121.5h2.4"/>
<path d="M170.8 123.9h2.4M172.3 122.2h-.4l-.1 .3-.1 .6 .2 .3 .4-.1v-.6l-.4-.1-.2 .3M172.3 120.2v.8M180.4 121.5h1.2a1.19 1.19 0 0 1 1.2-1.2 1.19 1.19 0 0 1 1.2 1.2 1.19 1.19 0 0 1 1.2-1.2 1.19 1.19 0 0 1 1.2 1.2 1.19 1.19 0 0 1 1.2-1.2 1.19 1.19 0 0 1 1.2 1.2 1.19 1.19 0 0 1 1.2-1.2 1.19 1.19 0 0 1 1.2 1.2h1.2M203.1 127.5h2.4l-1.2 1.1zM204.3 121.5v1.9M204.3 124.3v3.2M212.7 127.5h2.4l-1.2 1.1zM213.9 121.5v1.9M213.9 124.3v3.2M222.2 127.5h2.4l-1.2 1.1zM223.4 124.3v3.2"/>
<path d="M269.4 135.5a.54 .54 0 0 0-.7 .5 .54 .54 0 0 0 .7 .5M9.4 159.7h1.9M268.1 159.7h1.9M166.5 179.9h101.6M268.1 165.3h-101.6v30.1M10 182.4a.62 .62 0 0 1 .7 .6 .62 .62 0 0 1-.7 .7zM33.2 196l.3-.4v1.2M33.2 196.8h.7M56.4 195.4v1.9M80.2 195.7l.5-.1 .2 .4-.8 .8h.8M103.5 195.4v1.9M127.2 195.6h.7l-.4 .5 .4 .1v.5l-.2 .1-.5-.1"/>
<path d="M150.5 195.4v1.9M166.5 192.2h101.6M166.5 189.3h101.6M166.5 185.6h101.6M167.8 183.7h.5M167.8 192.6v1.4M168 193.2l.6 .8M168.5 183h-.7v1.4M168.5 190l-.5-.1-.2 .2v.4l.6 .2 .1 .4-.2 .3-.6-.1M168.5 180.5l-.5-.1-.2 .2v.4l.6 .2 .1 .4-.2 .3-.6-.1M168.6 192.6l-.8 .8M169 183v.1"/>
<path d="M169 183.5v.9M169.1 180.4v1.5M169.1 189.9v.2M169.1 190.4v1M169.1 181l.2-.1 .4 .1v.9M169.2 192.6v.1M169.2 193v1M169.7 190.4h.7l-.7 1h.7M169.7 183v1.2l.2 .2M170.3 183.9l.7-.1-.1-.3h-.4l-.2 .2 .1 .6h.5M170.3 181.4l.7-.2-.1-.2-.4-.1-.2 .2 .1 .7h.5M170.7 192.7a.67 .67 0 0 0-1 .5 .67 .67 0 0 0 .7 .8l.3-.1"/>
<path d="M170.9 190.9l.7-.2-.1-.2-.4-.1-.2 .2v.7h.6M171.3 193.1h.5l.1 .9M171.6 181.4l.6-.2v-.2l-.4-.1-.2 .2v.7h.6M171.6 184.3v.1M171.6 183.5v.2M171.9 193.4h-.5l-.2 .3 .2 .3 .5-.1M172.2 190.5v.1M172.2 191.2v.2M172.6 180.9h.6M172.8 180.4v1.2l.4 .3M173.1 183.5h.4l.3 .2-.1 .6h-.6M173.1 183.5v1.4"/>
<path d="M173.2 193.1l-.4-.1-.3 .3 .1 .6h.6M173.2 192.6v1.4M173.5 191.4l.4-1.5 .5 1.5M173.6 190.9h.7M173.6 181.7v.2M173.6 181v.1M174.5 183.5h.3l.3 .2v.4l-.3 .3-.3-.1-.2-.2zM174.6 195.6l-.3 .8h.7M174.7 193.2h.5M174.9 196v.8M175.2 189.9l-.4 1h.9M175.4 192.6h-.7v1.4h.7"/>
<path d="M175.5 190.4v1M175.6 183.5l.2 .9 .3-.7 .3 .7 .2-.9M176 193.9v.1M176.6 192.6a.71 .71 0 0 1 .8 .7 .71 .71 0 0 1-.8 .7zM177.1 183.9l.7-.1-.1-.3h-.4l-.2 .2 .1 .6h.5M178 193.9v.1M178.4 183.5v.9M178.5 194l.5-1.4 .5 1.4M178.6 193.6h.7M178.8 183.5l-.4 .2M179.3 184.3v.1M179.9 193.9v.1"/>
<path d="M179.9 183v1.4M180.1 183.9l.4 .5M180.5 183.5l-.6 .5M181.1 183v.1M181.1 183.5v.9M182.3 192.6v1.4M182.3 183.5h-.4l-.2 .2 .1 .6h.5M182.4 193.4l.4 .6M182.8 193l-.5 .6M182.9 183.5h.6l.1 .9M183.4 192.6v.1M183.4 193v1"/>
<path d="M183.6 183.8l-.5 .1-.2 .2 .2 .3 .5-.1M184.7 193.1l-.4-.1-.3 .3 .2 .6h.5M184.8 183.5h-.4l-.2 .2 .1 .6h.5M184.8 183v1.4M185.2 184.5h1M185.3 193.1h.6v.9M185.3 189.3v2.9M185.9 193.4h-.5l-.2 .3 .2 .3 .5-.1M187 183.5h-.3l-.2 .2 .1 .2 .4 .1v.3h-.5M187.2 193.1l-.4-.1-.3 .3 .2 .6h.5M187.2 192.6v1.4M188.3 183.5h-.4l-.2 .2 .1 .6h.5"/>
<path d="M188.5 189.9a.71 .71 0 0 1 .8 .7 .71 .71 0 0 1-.8 .8zM188.9 183.6l.2-.1h.4v.9M188.9 183v1.4M189.1 192.4a1.62 1.62 0 0 0 0 2.1M189.5 192.6h1l-.6 1.4M189.9 190.5h.5l.1 .9M190.5 190.7l-.5 .1-.2 .2 .2 .4 .5-.1M191 190.4h.5M191 193.9v.1M191.2 189.9v1.3l.3 .2M191.7 192.7l.2-.1a.75 .75 0 0 1 .5 .7 .75 .75 0 0 1-.5 .7l-.3-.6zM191.9 190.9l.7-.2-.1-.2-.4-.1-.2 .2 .1 .7h.5"/>
<path d="M193 193.9v.1M193.2 191.2v.2M193.2 190.5v.1M193.8 192.7l.2-.1a.75 .75 0 0 1 .4 .7 .75 .75 0 0 1-.4 .7l-.4-.6zM195 193.4h1.1M196.8 192.7l.2-.1a.75 .75 0 0 1 .5 .7 .75 .75 0 0 1-.5 .7l-.3-.6zM197.6 195.4v1.9M198 192.4a1.62 1.62 0 0 1 0 2.1M221.9 195.6h-.5l-.1 .6 .6-.1v.6l-.1 .1-.5-.1M244.6 195.4v1.9M245.5 189.3v6.1M247.8 192.6v1.4"/>
<path d="M249 193.1l-.4-.1-.2 .3 .1 .6h.5M249 192.6v1.4M249.7 193.9v.1M249.7 193.1v.1M251.5 192.5l-.3 1h.8M251.8 193v1M253.6 192.5l-1.2 1.8M254.6 192.6h-.4a.95 .95 0 0 0 0 1.4l.5-.1 .1-.5-.3-.3-.4 .1-.1 .2M268.7 182.4a.62 .62 0 0 1 .7 .6 .62 .62 0 0 1-.7 .7zM268.9 195.6l-.3 .1-.2 .2-.1 .7 .3 .2 .4-.1-.1-.6h-.3l-.3 .2"/>
<circle cx="17.9" cy="65.8" r=".72"/>
<circle cx="17.9" cy="99.3" r=".72"/>
<circle cx="17.9" cy="82.5" r=".72"/>
<circle cx="17.9" cy="116" r=".72"/>
<circle cx="17.9" cy="127.9" r=".72"/>
</g>
<path d="M247.8 190.7l.6-.1 .2-.2-.1-.3-.7-.2v1.5M248.1 190.7l.5 .7M249.1 190.9l.7-.2-.1-.2-.4-.1-.2 .2 .1 .7h.5M250.2 190.4l.4 1 .3-1M251.4 191.2v.2M251.4 190.5v.1" fill="none" stroke="#840000" stroke-width=".28"/>
<path d="M167.9 186.1h1.1M168.4 186.1l-.2 1.9M169.5 186.7l-.2 1.3M169.6 186.1v.1M170.1 186.7h.7M170.5 186.1l-.2 1.6v.2l.4 .1M171.6 186.1l-.2 1.6 .2 .3M172.3 187.3l.9-.2v-.3h-.8l-.2 .9 .3 .3 .5-.1M173.9 187.8v.2M174.1 186.8l-.1 .2" fill="none" stroke="#840000" stroke-width=".38"/>
<g fill="#ffffc2" stroke="#ffffc2" stroke-width=".35">
<path d="M24.6 41.4h1l-.5 1.2z"/>
<path d="M156.5 82.1h14.3v9.5h-14.3z" fill-rule="evenodd"/>
<path d="M156.5 116.7h14.3v9.6h-14.3z" fill-rule="evenodd"/>
<path d="M156.5 47.4h14.3v9.6h-14.3z" fill-rule="evenodd"/>
</g>
<g fill="none" stroke="#840000" stroke-width=".24">
<path d="M156.5 47.4h14.3v9.6h-14.3zM156.5 82.1h14.3v9.5h-14.3zM156.5 116.7h14.3v9.6h-14.3z"/>
<circle cx="64.5" cy="34.9" r="1.79"/>
<circle cx="137.4" cy="36.1" r="1.79"/>
<circle cx="35.8" cy="65.9" r="1.79"/>
<circle cx="137.4" cy="70.7" r="1.79"/>
<circle cx="137.4" cy="105.3" r="1.79"/>
</g>
<g fill="none" stroke="#008400" stroke-width=".2">
<path d="M29.9 37.8h11.9M51.4 37.8h13.1M120.7 39h-2.4v23.9h-6M137.4 39h40.6v3.6M143.4 39v10.8h10.7M29.9 42.6h4.7v2.4M56.2 51v1.2h8.3v3.6M56.2 57v3.5M56.2 58.2h8.3M112.3 58.2h3.6v38.2h-3.6M112.3 55.8h1.2v81.2M143.4 54.6v2.4"/>
<path d="M173.2 52.2h7.2M173.2 54.6h4.8v3.6h16.7M178 47.4v2.4h-4.8M192.4 52.2h31M194.7 57v2.4M17.9 68.9h17.9M56.2 65.3v2.4M56.2 66.5h7.1M64.5 60.5h-1.2v1.2M112.3 60.5h1.2M137.4 73.7h40.6v3.6M143.4 73.7v10.7h10.7"/>
<path d="M17.9 85.6h15.6M56.2 84.4v1.2h8.3v3.6M56.2 90.4v3.6M56.2 98.8v2.4M56.2 91.6h8.3M56.2 100h7.1M64.5 94h-1.2v1.2M112.3 91.6h6v40.6h-6M112.3 94h1.2M112.3 89.2h1.2M143.4 89.2v2.4M173.2 89.2h4.8v3.6h16.7"/>
<path d="M173.2 86.8h7.2M178 82.1v2.3h-4.8M192.4 86.8h31M194.7 91.6v2.4M17.9 119.1h15.6M17.9 102.4h15.6M137.4 108.3h40.6v3.6M143.4 108.3v10.8h10.7M178 116.7v2.4h-4.8M17.9 131v2.4M56.2 120.3v1.2M56.2 126.3v3.5"/>
<path d="M56.2 134.6v2.4M56.2 135.8h7.1M56.2 127.5h8.3M64.5 120.3v4.8M64.5 129.8h-1.2v1.2M112.3 127.5h3.6v19.1h4.8M112.3 129.8h1.2M112.3 125.1h1.2M143.4 123.9v2.4M173.2 121.5h7.2M192.4 121.5h31M194.7 121.5v6h-16.7v-3.6h-4.8"/>
</g>
<g fill="none" stroke="#0000c2" stroke-width=".2">
<path d="M59.9 153.5l.4-1.2 .3 1.2M60 153.1h.5M61 152.3v1l.2 .2M61.7 152.3v1l.1 .2M62.8 152.7h.5M63 152.3v1l.3 .2M63.7 152.8l.5-.1v.8M63.7 152.3v1.2M64.8 152.7v.8M65.1 152.7l-.3 .2M65.5 153.1l.5-.1v-.3h-.4l-.1 .1v.6h.5M66.5 153.1l.6-.1-.1-.3h-.3l-.2 .1v.6h.5"/>
<path d="M68.2 152.7l.3 .8 .2-.8M69.3 152.7h.2l.3 .2v.3l-.3 .3-.4-.3zM70.3 152.3v1l.1 .2M70.7 152.7h.5M70.9 152.3v1l.3 .2M71.6 152.7h.4l.1 .8M72.1 153l-.6 .2 .2 .3 .4-.1M73.2 152.7h-.4l-.2 .2 .1 .5h.5M73.2 152.7v.9l-.3 .3-.2-.1M73.7 153.1l.6-.1-.1-.3h-.3l-.2 .1v.6h.5M75.2 152.7h-.3l-.2 .1 .1 .2 .4 .1v.3h-.5M76.5 152.8l.3-.1 .2 .1"/>
<path d="M76.5 152.7v.8M77 152.8l.1-.1h.3l.1 .8M77 152.8v.7M78 152.7l.1 .7h.5M78.6 152.7v.8M79.5 152.7h-.3l-.1 .1v.2l.4 .1v.3h-.4M79.9 152.7h.5M80.1 152.3v1l.3 .2M81.5 152.7h.3l.3 .2-.2 .5h-.4M81.5 152.3v1.2M82.5 153.1l.6-.1-.1-.3h-.3l-.2 .1 .1 .6h.4M84.3 152.7h.5v.8"/>
<path d="M84.8 153l-.5 .2 .1 .3 .4-.1M85.4 152.7h.3l.3 .2-.1 .5h-.5M85.4 152.3v1.2M86.5 152.7h.3l.2 .2v.3l-.2 .3-.4-.3zM87.4 152.7l.3 .8 .3-.8M88.4 153.1l.6-.1-.1-.3h-.3l-.2 .1 .1 .6h.4M90 152.7h.5M90.2 152.3v1l.3 .2M90.9 152.8l.4-.1 .1 .8M90.9 152.3v1.2M91.9 153.1l.6-.1-.1-.3h-.3l-.2 .1 .1 .6h.4M93 152.3v.1"/>
<path d="M93 152.7v.8M93.6 152.7v.8M93.9 152.7l-.3 .2M94.9 152.7h.4M95 152.3v1l.3 .2M95.7 152.8l.5-.1v.8M95.7 152.3v1.2M96.8 152.7v.8M97.1 152.7l-.3 .2M97.5 153.1l.5-.1v-.3h-.4l-.1 .1v.6h.5M98.9 152.7h-.2l-.2 .1v.2l.4 .1v.3h-.4M99.5 152.8l.5-.1v.8"/>
<path d="M99.5 152.3v1.2M100.7 152.7h.2l.3 .2v.3l-.3 .3-.4-.3zM101.7 152.3v1l.1 .2M102.8 152.7h-.3l-.3 .2 .2 .5h.4M102.8 152.3v1.2M103.8 152.7h-.3l-.2 .1 .1 .2 .4 .1v.3h-.5M104.9 152.7h.5M105.1 152.3v1l.3 .2M105.8 152.7h.3l.2 .2v.3l-.2 .3-.4-.3zM107.5 152.7v.8M107.9 152.7l-.4 .2M108.2 153.1l.6-.1-.1-.3h-.3l-.2 .1 .1 .6h.4"/>
<path d="M109.3 152.3v1l.2 .2M109.9 153.1l.6-.1-.1-.3h-.3l-.2 .1v.6h.5M111 152.7h.4l.1 .8M111.5 153l-.6 .2 .2 .3 .4-.1M112.4 152.7h-.2l-.2 .1v.2l.4 .1v.3h-.4M113 153.1l.5-.1v-.3h-.4l-.1 .1v.6h.5M114.6 152.7h.4M114.8 152.3v1l.2 .2M115.4 152.8l.5-.1v.8M115.4 152.3v1.2M116.5 153.1l.5-.1v-.3h-.4l-.1 .1v.6h.5M118.3 152.9l.5-.1 .1-.4-.6-.1v1.2"/>
<path d="M118.5 152.9l.4 .6M119.5 152.8h.3M120 152.3h-.5v1.2h.5M121.2 152.3l-.7 .1v.3l.5 .3 .2 .2-.3 .3-.4-.1M121.7 152.8h.4M122.2 152.3h-.5v1.2h.5M122.6 152.3h.7M122.9 152.3v1.2M169.8 170.7l.2 .6M169.9 177.4l.4-.1-.1-.5h-.3v.9M169.9 172.3h.3l.1 .6M169.9 171.9v1"/>
<path d="M169.9 173.4v1M169.9 173.8h.3l.1 .6M170 171.3l-.2 .3M170.2 170.7l-.2 .6M170.4 169a.42 .42 0 0 0-.6 .3 .42 .42 0 0 0 .6 .4M170.4 175a.42 .42 0 0 0-.6 .4 .42 .42 0 0 0 .6 .4M170.6 170.8h.4v.5l-.4-.1zM170.6 172.2h.4M170.7 177.1l.4-.1v-.2h-.3l-.1 .1v.5h.4M170.7 171.9v.8l.3 .2M170.7 173.8h.4v.6M170.8 169.3h.4v.5l-.4-.1z"/>
<path d="M170.8 175.1l.2-.1 .4 .1v.5l-.1 .3-.5-.1zM171.1 172.2h.4M171.1 174l-.4 .2 .1 .2 .3-.1M171.3 171.9v.8l.2 .2M171.4 170.7l.1 .6 .3-.1M171.5 176.8v.6M171.6 173.7v.7M171.7 169.2h.2l.2 .2-.1 .4h-.3M171.7 169.2v.9M171.8 172.3l.3-.1 .2 .2-.1 .4h-.4M171.8 172.2v1M171.8 176.8l-.3 .2"/>
<path d="M171.8 170.7v.6M171.8 173.7l-.2 .2M172.1 176.8v.6M172.1 176.9l.3-.1 .1 .1M172.3 175v.9l-.5-.9v.9M172.4 169.2l.3 .6M172.5 176.9l.4-.1v.6M172.5 176.9v.5M172.6 173.8l-.3-.1-.2 .2 .1 .4h.4M172.6 173.4v1M172.7 172.9h.1M172.7 172.3v.1"/>
<path d="M172.7 169.8l-.3 .3M172.7 172.8v.1M172.8 175a.48 .48 0 0 1 .5 .4 .48 .48 0 0 1-.5 .5zM172.9 170.8l.2-.1 .2 .1M172.9 170.7v.6M172.9 169.2l-.2 .6M172.9 173.7l.2 .7 .2-.5 .2 .5 .1-.7M173.2 169.2v.6M173.3 170.8l.3-.1 .1 .6M173.3 170.8v.5M173.4 176.5v.1M173.4 176.8v.6"/>
<path d="M173.5 169.2l-.3 .2M173.7 175v.9M173.8 171.9l-.8 1.2M173.8 168.9v.1M173.8 169.2v.6M174 173.8h.4v.6M174 175h.6M174.1 170.7h.4v.6M174.1 176.8h-.2l-.1 .2 .4 .2M174.2 177.3l-.2 .1h-.2M174.2 177.2v.1M174.3 175v.9"/>
<path d="M174.4 174l-.4 .2 .1 .2 .3-.1M174.5 170.9l-.4 .2 .1 .2h.3M174.7 169.2h-.3l-.2 .2 .1 .4h.4M174.7 169.2v.7l-.2 .2h-.2M174.8 171.9l-.8 1.2M174.9 173.7v.7M174.9 170.7l.2 .6M174.9 176.8h-.2l-.2 .2 .4 .2M174.9 175v.9M174.9 177.3l-.1 .1h-.3M174.9 177.2v.1M175 172.4l.4 .3-.1 .2-.3-.1"/>
<path d="M175 172.4h.1M175.1 171.3l-.2 .3M175.1 169.3l.4-.1v.6M175.1 168.9v.9M175.1 173.7l-.2 .2M175.3 170.7l-.2 .6M175.3 176.5v.1M175.3 176.8v.6M175.3 175.1l.2-.1 .4 .1v.5l-.1 .3-.5-.1zM175.4 174.1l.4-.1v-.2l-.3-.1-.1 .2v.4h.4M175.4 172.3l-.4 .1M175.8 176.9h.4l-.1 .5-.3-.1z"/>
<path d="M175.8 172.3h.4v.5h-.4zM175.8 169.2h.4M176 168.9v.8l.2 .1M176.2 170.8l.4-.1 .1 .6M176.2 170.7v.6M176.6 176.9l.4-.1v.6M176.6 176.8v.6M176.7 171.9v.8l.1 .2M176.8 173.8h.4v.6M176.9 175v.9l-.6-.9v.9M177.1 169.2h.3l.1 .6M177.1 170.8h.4v.5l-.4-.1z"/>
<path d="M177.2 174l-.4 .2 .1 .2 .3-.1M177.5 169.4l-.5 .2 .2 .2h.3M177.6 171.9v.9h-.4v-.5h.4M177.7 173.8h.3l.1 .6M177.7 173.7v.7M177.8 175h-.5a.39 .39 0 0 0 .5 .5l-.1 .4h-.4M177.8 176.8h-.2l-.2 .2 .5 .2M177.8 170.7h.4M177.9 177.3l-.2 .1h-.3M177.9 177.2v.1M177.9 169.3l.4-.1v.6M177.9 169.2v.6"/>
<path d="M178 170.4v.8l.2 .1M178 172.5l.4-.1v-.1l-.3-.1-.1 .2v.4h.4M178.8 175.1l.2-.1 .3 .1 .1 .5-.2 .3-.4-.1zM178.8 176.8h.4v.6M178.8 172.2v.7M178.9 173.8l-.3-.1-.1 .2 .1 .4h.3M178.9 173.4v1M179.1 170.7v.6l.4-.1M179.1 172.2l-.3 .2M179.2 169.2h-.3l-.2 .2 .1 .4h.4M179.2 168.9v.9M179.2 177l-.4 .2 .1 .2h.3"/>
<path d="M179.4 172.3l.3-.1 .2 .2-.1 .4h-.4M179.4 172.2v1M179.5 170.7v.6M179.7 176.9l.3-.1 .1 .6M179.7 176.8v.6M179.8 175.4h.3M179.9 173.8l.3-.1 .1 .2M179.9 173.7v.7M180.2 169.2v.6M180.2 175h-.4v.9M180.2 170.7l-.3 .1 .3 .3v.2h-.3M180.3 172.3l.2-.1 .2 .2v.4l-.3 .1-.1-.4 .4-.1"/>
<path d="M180.3 173.9l.4-.1v.6M180.3 173.9v.5M180.5 169.2l-.3 .2M180.6 171l.5-.1-.1-.2h-.2l-.2 .1 .1 .5h.3M180.7 169.5l.5-.1-.1-.2h-.2l-.2 .1 .1 .5h.3M180.9 176.8h-.2l-.2 .2 .1 .4h.3M180.9 176.5v.9M181 175.9l.3-.9 .3 .9M181.1 175.6h.4M181.2 173.8h.3l.1 .6M181.5 171.9v.9h-.3l-.1-.5h.4M181.6 168.9v.8l.1 .1"/>
<path d="M181.6 174l-.5 .2 .2 .2 .3-.1M181.9 173.7h.4M181.9 170.7h.4M181.9 176.5v.8l.2 .1M182 172.8v.1M182 173.4v.8l.3 .2M182 170.4v.8l.3 .1M182.1 169.2h.3l.1 .6M182.4 172.3h.4v.5h-.4zM182.4 176.5v.1M182.4 176.8v.6M182.5 175v.9l-.6-.9v.9"/>
<path d="M182.5 169.4l-.5 .2 .2 .2h.3M182.5 174.1l.5-.1-.1-.2-.2-.1-.2 .2 .1 .4h.3M182.6 170.8l.3-.1 .1 .6M182.6 170.4v.9M182.8 175l.3 .5M182.8 169.2h.3M182.9 176.9l.2-.1 .2 .1M182.9 176.8v.6M182.9 168.9v.8l.2 .1M183.1 175.5v.4M183.3 172.2v.7M183.3 176.9v.5"/>
<path d="M183.3 176.9l.3-.1 .1 .6M183.4 173.7v.7M183.4 175l-.3 .5M183.4 169.5l.5-.1-.1-.2h-.3l-.1 .1 .1 .5h.3M183.4 170.4v.1M183.4 170.7v.6M183.5 172.2l-.2 .2M183.6 173.7l-.2 .2M184 173.4v.1M184 173.7v.7M184.1 176.5v.1M184.1 176.8v.6"/>
<path d="M184.2 170.7l-.4 .1 .4 .3v.2h-.4M184.3 172.2v.8l-.2 .2-.2-.1M184.3 172.3l-.3-.1-.2 .2 .1 .4h.4M184.3 175v.9M184.4 173.8h.4v.6M184.4 175.4l.4 .5M184.4 176.8h.4M184.6 176.5v.8l.2 .1M184.7 169.2h-.3l-.2 .2 .1 .4h.4M184.7 168.9v.9M184.8 174l-.4 .2 .1 .2 .3-.1M184.8 175l-.5 .5"/>
<path d="M185.1 170.7h.3M185.1 176.8h.4v.6M185.2 175v.9M185.3 173.4v.8l.1 .2M185.4 171.9l-.8 1.2M185.4 170.4l-.2 .1v.8M185.5 177l-.4 .2 .1 .2h.3M185.7 169.2v.6M185.7 171.9v.8l.1 .2M185.7 170.4v.1M185.7 170.7v.6M185.8 176.8h.4"/>
<path d="M186 169.2l-.3 .2M186 176.5v.8l.2 .1M186.1 173.8l-.4 .1 .4 .2v.2h-.4M186.2 170.4v.8l.1 .1M186.2 171.9v.1M186.2 172.2v.7M186.2 175v.9l-.5-.9v.9M186.3 168.9v.1M186.3 169.2v.6M186.5 176.5v.1M186.5 176.8v.6M186.6 171l.5-.1-.1-.2h-.2l-.2 .1 .1 .5h.3"/>
<path d="M186.7 175a.48 .48 0 0 1 .5 .4 .48 .48 0 0 1-.5 .5zM187 176.9h.4l-.1 .5-.3-.1zM187 172.3l-.2-.1-.2 .2 .1 .4h.3M187.1 169.2h-.3l-.1 .2 .1 .4h.3M187.1 169.2v.7l-.2 .2h-.2M187.4 172.5l.4-.1v-.1l-.3-.1-.1 .2v.4h.4M187.5 173.8l-.3-.1-.2 .2 .1 .4h.4M187.5 173.4v1M187.6 169.3l.3-.1 .1 .6M187.6 168.9v.9M187.7 175.9l-.1 .1M187.8 176.9l.4-.1v.6"/>
<path d="M187.8 176.8v.6M187.9 173.4v.1M187.9 173.7v.7M188 171l.5-.1-.1-.2h-.3l-.1 .1v.5h.4M188.2 172.3h.4v.6M188.2 172.2v.7M188.3 169.2h.3M188.4 168.9v.8l.2 .1M188.6 175.6l.4-.1v-.2h-.3l-.1 .1v.5h.4M188.7 173.8l-.4 .1 .4 .2v.2h-.4M188.8 170.7l.5 .6M189 176.8h-.3l-.1 .2 .4 .2"/>
<path d="M189 173.7h.4M189 177.3l-.1 .1h-.3M189 177.2v.1M189.1 172.4l.4 .3-.2 .2-.2-.1M189.1 172.4h.1M189.1 173.4v.8l.3 .2M189.3 170.7l-.5 .6M189.3 169.2l-.4 .1 .4 .2v.3h-.4M189.4 172.3l-.3 .1M189.4 175h.1M189.4 175.3v.6M189.7 173.7v.7"/>
<path d="M189.7 175.3h.4M189.8 172.5l.5-.1-.1-.1-.3-.1-.1 .2 .1 .4h.3M189.9 175v.8l.2 .1M189.9 173.7l-.2 .2M190 176.8v.6l.4-.1M190 170.7h-.3l-.1 .2 .1 .4h.3M190.3 173.4v.1M190.3 173.7v.7M190.3 169.2h.3l.1 .6M190.4 171l.4-.1v-.2h-.3l-.1 .1v.5h.4M190.4 176.8v.6M190.4 175.4l.4-.1v.6"/>
<path d="M190.4 175v.9M190.6 172.4l.4 .3-.1 .2-.3-.1M190.6 172.4h.1M190.7 169.4l-.5 .2 .2 .2h.3M190.7 173.8l.3-.1 .1 .2v.4h-.4M190.7 173.4v1M190.8 176.8v.6M190.8 176.9l.4-.1v.6M191 172.3l-.4 .1M191.1 169.2v.6M191.2 175.6l.5-.1-.1-.2h-.2l-.2 .1 .1 .5h.3M191.2 170.7h.3l.2 .2-.1 .4h-.4"/>
<path d="M191.2 170.7v.9M191.4 169.2l-.3 .2M191.6 173.7v.6h.4M191.7 169.5l.4-.1v-.2h-.3l-.1 .1v.5h.4M191.9 170.7h.4M192 173.7v.7M192.1 175.3v.6M192.1 170.4v.8l.2 .1M192.1 176.8h-.3l-.2 .2 .1 .4h.4M192.1 176.5v.9M192.1 171.9l-.8 1.2M192.3 173.7h.3"/>
<path d="M192.3 175.3l-.2 .2M192.4 173.4v.8l.2 .2M192.5 177.1l.4-.1v-.2h-.3l-.1 .1v.5h.4M192.9 174.1l.4-.1v-.2l-.3-.1-.1 .2v.4h.4M192.9 172h-.5a.39 .39 0 0 0 .5 .5l-.1 .3h-.4M193.1 168.9v.8l.1 .1M193.2 175.6l.4-.1v-.2h-.3l-.1 .1v.5h.4M193.2 170.4v.1M193.2 170.7v.6M193.3 171.9v1M193.3 172.4h.5M193.3 176.8v.6"/>
<path d="M193.6 168.9v.1M193.6 169.2v.6M193.6 176.8l-.3 .2M193.6 170.8l.4-.1v.6M193.6 170.7v.6M193.8 171.9v1M193.9 175.3l.5 .6M194.1 173.8l-.2-.1-.2 .2 .1 .4h.3M194.1 173.4v1M194.3 171.9v1h.4M194.4 176.8h.3M194.4 175.3l-.5 .6"/>
<path d="M194.4 169.2h-.2l-.2 .2 .1 .4h.3M194.5 176.5v.8l.2 .1M194.8 175.3v.9M194.8 175.3h.3l.1 .2-.1 .4h-.3M194.8 169.5l.4-.1v-.2h-.3l-.1 .1v.5h.4M195 176.9l.4-.1v.6M195 176.5v.9M195.1 172.5h.7M195.2 173.7v.6h.4M195.4 170.7h-.2l-.2 .2 .1 .4h.3M195.6 173.7v.7M195.6 175.3v.6"/>
<path d="M195.6 169.3l.4-.1v.6M195.6 169.2v.6M195.8 177.1l.5-.1-.1-.2h-.2l-.2 .1 .1 .5h.3M195.9 170.8h.4l-.1 .5-.3-.1zM195.9 175.3l-.3 .2M196 173.7v.7M196 173.8h.4v.6M196.2 175.6l.4-.1v-.2h-.3l-.1 .1v.5h.4M196.2 172l.3-.1 .2 .3-.6 .7h.6M196.7 170.8l.3-.1 .1 .1M196.7 170.7v.6M196.8 169.2l-.4 .1 .4 .2v.3h-.4"/>
<path d="M197.1 170.8l.4-.1v.6M197.1 170.8v.5M197.1 172.8v.1M197.2 169.5l.5-.1-.1-.2h-.3l-.1 .1v.5h.4M197.2 176.5v.9h.5M197.3 173.8l-.3-.1-.2 .2 .1 .4h.4M197.3 173.4v1M197.3 175.3l-.3 .1 .3 .2v.3h-.3M197.5 172.9h.6M197.5 172.2l.3-.3v1M197.7 174.1l.4-.1v-.2l-.3-.1-.1 .2v.4h.4M198 170.7h.2l.2 .2-.1 .4h-.3"/>
<path d="M198 170.7v.9M198 176.5v.1M198 176.8v.6M198.1 175.3l-.4 .1 .4 .2v.3h-.4M198.5 169.2h-.3l-.2 .2 .1 .4h.4M198.5 168.9v.9M198.5 172.8v.1M198.5 173.7v.7M198.8 173.7l-.3 .2M198.8 170.4v.8l.1 .1M198.9 176.8h-.3l-.2 .2 .1 .4h.4M199.1 175.4h.4v.5l-.4-.1z"/>
<path d="M199.2 177.1l.5-.1-.1-.2h-.2l-.2 .1 .1 .5h.3M199.3 170.4v.1M199.3 170.7v.6M199.5 169.2v.6l.4-.1M199.5 171.9v.8l.1 .2 .4-.2v-.8M199.5 173.7h.4M199.7 173.4v.8l.2 .2M199.7 170.7h.4l.1 .6M199.9 169.2v.6M200 175.3v.6M200.1 176.9l.3-.1 .1 .6M200.1 176.8v.6"/>
<path d="M200.2 170.9l-.5 .2 .1 .2h.4M200.2 173.8h.4v.6M200.2 173.4v1M200.2 175.3l-.2 .2M200.3 169.3l.4-.1v.6M200.3 169.2v.6M200.5 172.3h.3l.1 .6M200.5 172.2v.7M200.6 170.8l.4-.1v.6M200.6 170.7v.6M201.1 173.4v.1M201.1 173.7v.7"/>
<path d="M201.1 175h.1M201.1 175.3v.6M201.2 176.8h-.2l-.1 .2 .4 .2M201.3 177.3l-.2 .1h-.2M201.3 177.2v.1M201.3 171.9v.8l.1 .2M201.6 175.3v.6M201.6 175.4l.2-.1 .2 .1M201.6 169.2h-.3l-.2 .2 .1 .4h.4M201.6 168.9v.9M201.6 177.1l.5-.1-.1-.2h-.2l-.2 .1 .1 .5h.3M201.8 172.5l.4-.1v-.1l-.3-.1-.1 .2v.4h.4"/>
<path d="M201.8 173.8l-.3 .1 .3 .2v.2h-.3M201.9 170.7h-.3l-.2 .2 .1 .4h.4M202 175.4v.5M202 175.4l.3-.1 .1 .6M202 169.5l.4-.1v-.2h-.3l-.1 .1v.5h.4M202.2 171l.5-.1-.1-.2h-.3l-.1 .1 .1 .5h.3M202.5 177.3v.1M202.6 172.4l.4 .3-.2 .2-.2-.1M202.6 172.4h.1M202.8 175.3v.9M202.8 175.3h.3l.2 .2-.1 .4h-.4M202.8 169.2v.6"/>
<path d="M202.8 173.4v1h.5M202.9 172.3l-.3 .1M203.1 169.2l-.3 .2M203.3 172.4l.4 .3-.1 .2-.3-.1M203.3 172.4h.1M203.5 170.7l.2 .6 .2-.4 .2 .4 .2-.6M203.6 173.4v.1M203.6 173.7v.7M203.7 175v.8l.1 .1M203.7 172.3l-.4 .1M203.8 169.2h.4M204 168.9v.8l.2 .1"/>
<path d="M204.2 175h.1M204.2 175.3v.6M204.4 173.8l-.2-.1-.2 .2 .1 .4h.3M204.5 169.3l.4-.1v.6M204.5 168.9v.9M204.6 175.6l.4-.1v-.2h-.3l-.1 .1v.5h.4M204.6 170.4v.1M204.6 170.7v.6M204.7 172.2v.7M204.8 174.1l.4-.1v-.2l-.3-.1-.1 .2v.4h.4M204.9 170.7h.4M205 172.2l-.3 .2"/>
<path d="M205.1 170.4v.8l.2 .1M205.2 172.5l.5-.1-.1-.1-.2-.1-.2 .2 .1 .4h.3M205.3 169.5l.5-.1-.1-.2h-.2l-.2 .1 .1 .5h.3M205.6 170.8l.4-.1v.6M205.6 170.4v.9M205.7 173.8h.3l.1 .6M205.7 173.7v.7M205.8 175.3h-.3l-.1 .2 .1 .4h.3M205.8 175v.9M206.3 175.8v.1M206.5 172.3l-.3-.1-.2 .2 .1 .4h.4M206.5 172.2v1"/>
<path d="M206.8 173.8l-.3 .1 .3 .2v.2h-.3M206.9 170.7h.3M206.9 172.2l.1 .6h.3M207 170.4v.8l.2 .1M207.2 174.1l.5-.1-.1-.2-.2-.1-.2 .2 .1 .4h.3M207.2 168.9l-.5 .1a.39 .39 0 0 0 .5 .4l-.1 .4h-.4M207.3 172.2v.7M207.6 170.8l.3-.1 .1 .6M207.6 170.4v.9M207.6 169.3h.4v.5h-.3zM207.6 169.7l.1 .1M207.8 175h-.5a.39 .39 0 0 0 .4 .5v.4h-.5"/>
<path d="M207.8 171.9v.1M207.8 172.2v.7M208.1 175.6l.5-.1-.1-.2h-.2l-.2 .1 .1 .5h.3M208.2 172.2v.7M208.4 171l.4-.1v-.2h-.3l-.1 .1v.5h.4M208.5 168.9v.8l.1 .1M208.5 172.2l-.3 .2M208.6 173.4v.1M208.6 173.7v.7M208.8 172.5l.4-.1v-.1l-.3-.1-.1 .2v.4h.4M208.9 175.6l.5-.1-.1-.2h-.2l-.2 .1 .1 .5h.3M209 169.7v.1"/>
<path d="M209 169.8h.4M209.4 169.2l-.4 .1v.4M209.4 168.9v.9M209.4 173.8l-.4 .1 .4 .2v.2h-.4M209.8 170.4v.9h.4M209.8 169.5l.4-.1v-.2h-.3l-.1 .1v.5h.4M210 171.9v.9h-.3l-.1-.5h.4M210.2 175.3h.4M210.3 175v.8l.3 .1M210.5 170.4v.1M210.5 170.7v.6M210.6 169.2v.6"/>
<path d="M210.8 173.8l-.3-.1-.1 .2 .1 .4h.3M210.8 173.4v1M210.9 175.4l.3-.1 .1 .6M210.9 175v.9M210.9 169.2l-.3 .2M211 171.9v.9h.4v-.5h-.4M211.2 169.8h.4M211.2 169.2l.4 .1v.4M211.2 169.2v.9M211.3 173.4v.1M211.3 173.7v.7M211.4 170.7h-.3l-.2 .2 .1 .4h.4"/>
<path d="M211.6 169.7v.1M211.7 175.6l.4-.1v-.2h-.3l-.1 .1v.5h.4M211.7 171l.5-.1-.1-.2h-.2l-.2 .1 .1 .5h.3M211.8 172.2l.2 .7M212 172.9l-.2 .3M212 173.8l-.3 .1 .3 .2v.2h-.3M212.1 169.2h.3l.1 .6M212.2 172.2l-.2 .7M212.3 173.7h.4M212.5 173.4v.8l.2 .2M212.5 169.4l-.5 .2 .2 .2h.3M212.6 170.8l.4-.1v.6"/>
<path d="M212.6 170.7v.6M212.9 169.7l.1 .1M213 169.8h.3M213 173.7v.7M213.1 175v.9h.5M213.2 172.3l.2-.1 .2 .2v.5h-.3l-.1-.4 .4-.1M213.3 173.7l-.3 .2M213.3 169.2l-.4 .1v.4M213.3 168.9v.9M213.6 173.4v.1M213.6 173.7v.7M213.8 170.7l-.4 .1 .4 .3v.2h-.4"/>
<path d="M213.9 175h.1M213.9 175.3v.6M214 172.3l.3-.1 .2 .2-.1 .4h-.4M214 172.2v1M214 173.8l.3-.1 .2 .2-.1 .4h-.4M214 173.4v1M214.2 171l.4-.1v-.2h-.3l-.1 .1v.5h.4M214.3 168.9v.9M214.3 169.3h.6M214.7 175.3h-.2l-.2 .2 .1 .4h.3M214.9 172.2v1M214.9 172.3l.2-.1 .2 .2-.1 .4h-.3"/>
<path d="M214.9 168.9v.9M214.9 173.7v.6h.4M215 171.2v.1M215.1 175.6l.4-.1v-.2h-.3l-.1 .1v.5h.4M215.3 173.7v.7M215.3 169.2h.4v.6M215.6 173.7h.4M215.7 171.9v.8l.2 .2M215.7 169.4l-.4 .2 .1 .2h.3M215.7 173.4v.8l.3 .2M215.9 175.4l.4-.1v.6M215.9 175.3v.6"/>
<path d="M216.2 169.2v.6M216.2 172h.1M216.2 172.2v.7M216.2 174.1l.5-.1-.1-.2-.2-.1-.2 .2 .1 .4h.3M216.3 172h-.1M216.4 169.2l-.2 .2M216.5 170.4l.3 .5M216.8 170.9v.4M217.1 172.3l-.3-.1-.2 .2 .1 .4h.4M217.1 170.4l-.3 .5M217.1 175.3l-.4 .1 .4 .2v.3h-.4M217.2 169.2h-.3l-.2 .2 .1 .4h.4"/>
<path d="M217.2 168.9v.9M217.4 170.8h.4v.5l-.4-.1zM217.5 172.3l.2-.1 .2 .2v.4l-.3 .1-.1-.4 .4-.1M217.5 173.8l-.3-.1-.2 .2 .1 .4h.4M217.5 173.4v1M217.5 175.6l.4-.1v-.2h-.3l-.1 .1v.5h.4M217.5 169.2l.2 .6 .2-.4 .2 .4 .1-.6M218.2 170.7l.1 .6 .4-.1M218.3 171.9v.9h.4v-.5h-.4M218.5 173.8h.4v.5h-.4zM218.6 169.2h.3l.1 .6M218.7 170.7v.6"/>
<path d="M218.8 175.3h.3M219 169.4l-.5 .2 .2 .2h.3M219.1 175l-.2 .1v.8M219.2 171.9v.8l.1 .2M219.4 173.8h.3l.1 .6M219.4 173.7v.7M219.4 169.2v.6M219.4 175.4h.5l-.1 .5-.4-.1zM219.6 172.5l.5-.1-.1-.1-.2-.1-.2 .2 .1 .4h.3M219.7 170.8l.2-.1 .2 .1M219.7 170.7v.6M219.7 169.2l-.3 .2"/>
<path d="M220 169.5l.4-.1v-.2h-.3l-.1 .1v.5h.4M220.1 170.8l.3-.1 .1 .6M220.1 170.8v.5M220.3 175.3v.6M220.6 175.3l-.3 .2M220.8 173.8h.3l.1 .6M220.9 170.7h.4v.6M221 171.9v.8l.2 .2M221.2 174l-.5 .2 .2 .2 .3-.1M221.3 175.3h.4M221.3 170.9l-.4 .2 .1 .2h.3M221.4 168.9v.9h.4"/>
<path d="M221.4 175v.8l.3 .1M221.5 172.3l.3-.1 .1 .2v.4l-.3 .1-.1-.4 .4-.1M221.6 173.8h.4v.6M221.6 173.7v.7M221.7 170.7l.2 .6M221.9 171.3l-.2 .3M222 175.4l.3-.1 .1 .6M222 175v.9M222.1 170.7l-.2 .6M222.2 168.9v.1M222.2 169.2v.6M222.3 172.2l.2 .7 .1-.5 .2 .5 .2-.7"/>
<path d="M222.8 175.6l.4-.1v-.2h-.3l-.1 .1v.5h.4M223 173.4v.2M223 169.2h-.3l-.1 .2v.4h.4M223.1 170.8h.4l-.1 .5-.3-.1zM223.3 173.4v.2M223.4 169.5l.4-.1v-.2h-.3l-.1 .1v.5h.4M223.6 174.4l.3-1 .3 1M223.7 174.1h.5M223.9 170.7h.3l.2 .2-.1 .4h-.4M223.9 170.4v.9M223.9 172.3h.4v.5h-.4zM224.2 169.3l.4-.1v.6"/>
<path d="M224.2 169.2v.6M224.5 175.3l-.3 .1 .3 .2v.3h-.3M224.6 170.7h.4M224.8 170.4v.8l.2 .1M224.8 172.2v.7M225 175.3h.2l.2 .2-.1 .4h-.3M225 175.3v.9M225 172.2l-.2 .2M225 173.5h-.4a.39 .39 0 0 0 .4 .5v.3h-.5M225.3 170.7h.3l.1 .6M225.4 169.2l-.4 .1 .4 .2v.3h-.4M225.7 170.9l-.5 .2 .2 .2h.3"/>
<path d="M225.8 175.6l.4-.1v-.2h-.3l-.1 .1v.5h.4M225.8 169.5l.4-.1v-.2h-.3l-.1 .1v.5h.4M225.9 172.3l.3-.1 .1 .2v.4l-.3 .1-.1-.4 .4-.1M226 173.4v1M226.1 170.4v.1M226.1 170.7v.6M226.6 170.8l.3-.1 .1 .6M226.6 170.7v.6M226.7 169.8l-.1 .1M227 173.5h-.5a.39 .39 0 0 0 .4 .5v.3h-.5M227 175.3h-.2l-.2 .2 .1 .4h.3M227.2 172.2v.8l-.2 .2-.2-.1"/>
<path d="M227.2 172.3l-.3-.1-.2 .2 .1 .4h.4M227.3 173.4v.2M227.4 175h.1M227.4 175.3v.6M227.5 168.9l.3 .9 .3-.9M227.6 172.2v.7M227.7 173.4v.2M227.7 175.3h.4M227.9 172.2l-.3 .2M228 170.7h.4v.6M228.1 175l-.2 .1v.8M228.2 172.5l.4-.1v-.1l-.3-.1-.1 .2v.4h.4"/>
<path d="M228.4 169.5l.5-.1-.1-.2h-.3l-.1 .1 .1 .5h.3M228.4 170.9l-.4 .2 .1 .2h.3M228.4 175h.1M228.4 175.3v.6M228.6 173.4h.4l.1 .2-.1 .3 .2 .3-.2 .2h-.4zM228.6 173.9h.4M229 172.5l.4-.1v-.1l-.3-.1-.1 .2v.4h.4M229.3 169.2v.6M229.3 175.3h-.3l-.2 .2 .1 .4h.4M229.4 174.4l.4-1 .3 1M229.5 169.2l-.2 .2M229.5 174.1h.5"/>
<path d="M229.8 170.7h-.2l-.2 .2 .1 .4h.3M230.2 169.2l-.4 .1 .4 .2v.3h-.4M230.2 170.8h.4v.5l-.4-.1zM230.2 171.9v1l-.3-.1-.1-.5h.4M230.2 175v.8l.2 .1M230.6 168.9v.1M230.6 169.2v.6M230.7 175.3h.4v.6M230.9 173.5h-.5a.39 .39 0 0 0 .4 .5v.3h-.5M231.1 169.3h.4l-.1 .5-.3-.1zM231.1 170.7h.2l.2 .2-.1 .4h-.3M231.1 170.7v.9"/>
<path d="M231.1 172.2h.4M231.1 175.5l-.4 .2 .1 .2h.3M231.2 171.9v.8l.3 .2M231.3 173.4v1M231.6 175.4l.3-.1 .1 .6M231.6 175.3v.6M231.8 172.3h.4l-.1 .5h-.3zM231.8 170.7l.3 .6M231.9 169.3l.4-.1v.6M231.9 169.2v.6M232.1 171.3l-.3 .3M232.2 173.5h-.5a.39 .39 0 0 0 .5 .5l-.1 .3h-.4"/>
<path d="M232.3 170.7l-.2 .6M232.7 174.3l-.1 .2M232.8 175.3h-.2l-.2 .2 .1 .4h.3M232.8 175.3v.7l-.1 .2h-.3M233.2 171.9v.1M233.2 172.2v.7M233.2 170.8h.4v.5l-.4-.1zM233.3 169l.3-.1 .2 .2-.6 .7h.6M233.3 175.3v.6l.4-.1M233.6 173.4l.2 1 .2-.7 .1 .7 .3-1M233.6 172.2v.7M233.6 172.3h.4v.6"/>
<path d="M233.7 175.3v.6M233.9 170.7h.4M234.1 175.3h.4v.6M234.2 169.7v.1M234.3 170.4l-.2 .1v.8M234.5 175.5l-.4 .2 .1 .2h.3M234.6 169.8h.6M234.6 169.1l.3-.2v.9M234.7 173.4v1M235 172.2l.1 .7 .2-.5 .2 .5 .2-.7M235 170.7h.4M235 173.4h.6"/>
<path d="M235.2 170.4v.8l.2 .1M235.3 173.4v1M235.4 175.3v.7l-.2 .2h-.2M235.4 175.3h-.3l-.2 .2 .1 .4h.4M235.7 170.8l.4-.1v.6M235.7 170.4v.9M235.8 175.6l.4-.1v-.2h-.3l-.1 .1v.5h.4M235.9 173.9h.5M235.9 173.4v1M236 172.2v.7M236.3 172.2l-.3 .2M236.4 168.7a1.08 1.08 0 0 0 0 1.5"/>
<path d="M236.4 173.4v1M236.5 171l.5-.1-.1-.2h-.3l-.1 .1 .1 .5h.3M236.6 169.2h.4M236.6 171.9v.1M236.6 172.2v.7M236.8 168.9v.8l.2 .1M236.9 173.6l.1-.2 .4 .2v.5l-.1 .2-.4-.1zM236.9 172.2h.4M237.1 171.9v.8l.2 .2M237.3 169.3l.3-.1 .1 .6M237.3 168.9v.9M237.6 172h.1"/>
<path d="M237.6 175.3h-.3l-.1 .2 .1 .4h.3M237.6 175.3v.7l-.2 .2h-.2M237.6 172.2v.7M237.9 173.4v.8l.1 .2 .4-.2v-.8M237.9 170.4v.9h.5M238.1 175.4h.4l-.1 .5-.3-.1zM238.1 172.3h.3l.1 .6M238.1 172.2v.7M238.1 169.5l.4-.1v-.2h-.3l-.1 .1v.5h.4M238.7 170.4v.1M238.7 170.7v.6M238.7 173.4h.5"/>
<path d="M238.8 175.3l.2 .6 .3-.6M239 173.4v1M239.3 172.2v.8l-.2 .2-.2-.1M239.3 172.3l-.3-.1-.1 .2 .1 .4h.3M239.5 168.9v.1M239.5 170.7h-.2l-.2 .2 .1 .4h.3M239.6 175.6l.4-.1v-.2h-.3l-.1 .1v.5h.4M239.8 172.8v.1M239.8 172.9l-.1 .1M239.8 168.9v.1M239.9 171l.4-.1v-.2h-.3l-.1 .1v.5h.4M240 173.4l.3 1 .1-.7 .2 .7 .2-1"/>
<path d="M240.2 168.9v.9h.5M240.4 175.3v.6M240.7 175.3l-.3 .2M240.7 172.4l.4 .3-.1 .2-.3-.1M240.7 172.4h.1M240.7 170.8l.4-.1v.6M240.7 170.7v.6M241 168.9v.1M241 169.2v.6M241 175.4l.4-.1v.6M241 175.3v.6M241.1 174.4l.3-1 .3 1"/>
<path d="M241.1 172.3l-.4 .1M241.1 174.1h.5M241.5 172.3h.4v.5h-.4zM241.8 169.2h-.2l-.2 .2 .1 .4h.3M241.9 175h.1M241.9 175.3v.6M241.9 170.7l-.3 .1 .3 .3v.2h-.3M242 173.9h.4l.1-.4-.5-.1v1M242.2 169.5l.4-.1v-.2h-.3l-.1 .1v.5h.4M242.2 173.9l.3 .5M242.3 172.2h.3M242.3 175.3v.6"/>
<path d="M242.3 175.4l.4-.1v.6M242.3 171l.5-.1-.1-.2h-.3l-.1 .1 .1 .5h.3M242.6 171.9l-.2 .1v.9M242.8 172.2h.3M242.9 171.9v.8l.2 .2M242.9 173.9h.5v-.4l-.5-.1v1M243 169.3l.4-.1 .1 .6M243 169.2v.6M243.2 173.9l.3 .5M243.4 172.2l.2 .7 .1-.5 .2 .5 .2-.7M243.6 175.3h-.3l-.2 .2 .1 .4h.4M243.6 175.3v.7l-.2 .2h-.2"/>
<path d="M243.7 170.7h.4v.6M243.7 174.4l.4-1 .3 1M243.8 174.1h.5M244.1 170.9l-.4 .2 .1 .2h.3M244.2 169.2l-.3 .1 .3 .2v.3h-.3M244.4 170.7h.4M244.4 172.3l.3-.1 .1 .2v.4l-.3 .1-.1-.4 .4-.1M244.6 170.4v.8l.2 .1M244.6 169.5l.5-.1-.1-.2h-.2l-.2 .1 .1 .5h.3M245.2 173.4v1l-.5-1v1M245.3 172.2v.7M245.4 168.9v.1"/>
<path d="M245.5 173.4h.6M245.6 172.2l-.3 .2M245.8 168.9v.1M245.8 173.4v1M245.8 172.5l.5-.1-.1-.1-.2-.1-.2 .2 .1 .4h.3M246.1 168.7a1.08 1.08 0 0 1 0 1.5M246.4 173.4v1M246.7 172.8v.1M246.7 172.9l-.1 .1M246.8 169.2v.1M246.8 173.9h.4M246.9 169.8l-.1 .1"/>
<path d="M247.3 173.4h-.5v1h.5M248.2 173.5h-.5a.39 .39 0 0 0 .4 .5v.3h-.5M249.2 173.6l.1-.2 .4 .2v.5l-.1 .2-.4-.1zM250.1 173.9h.5v-.4l-.5-.1v1M250.4 173.9l.3 .5"/>
</g>
<g fill="none" stroke="#848400" stroke-width=".2">
<path d="M121.3 38.4h.6v1.2h-.6l-.6-.6zM122.2 37.9h7.9M122.3 38.9h.6l.1-.5-.7-.1v1.2M122.6 38.9l.4 .6M123.5 38.9h.4M124.1 38.3h-.6v1.2h.6M125.2 38.3l-.6 .1v.3l.5 .3 .1 .3-.2 .2-.5-.1M125.7 38.9h.4M126.3 38.3h-.6v1.2h.6M126.7 38.3h.6M127 38.3v1.2M127.4 39.6h1"/>
<path d="M128.6 38.3v1.2M129.9 38.3v1.2l-.7-1.2v1.2M120.7 146.6l.6-.6h.6v1.2h-.6zM122.2 145.4h9.5M122.3 146.4h.6l.1-.5-.7-.1v1.2M122.6 146.4l.4 .6M123.5 146.4h.4M124.1 145.8h-.6v1.2h.6M125.2 145.9h-.6v.4l.5 .2 .1 .3-.2 .2-.5-.1M125.7 146.4h.4M126.3 145.8h-.6v1.2h.6M126.7 145.8h.6"/>
<path d="M127 145.8v1.2M127.4 147.1h1M128.6 146l.3-.2a.4 .4 0 0 1 .5 .4v.4a.4 .4 0 0 1-.4 .4 .4 .4 0 0 1-.4-.4zM129.9 145.8v1l.2 .2h.2l.3-.2v-1M131 145.8h.7M131.3 145.8v1.2"/>
</g>
<g fill="none" stroke="#484848" stroke-width=".2">
<path d="M31.8 35l.5 .5M32.3 35.5v2.3M32.3 35.5h.4M33.4 35.2h.4l.1 .5-.3 .2-.3-.1M33.4 34.7l-.1 1.2M34.5 35.1l-.1 .8M34.5 34.7v.1M35.5 35.2l-.3-.1-.3 .2 .1 .5h.4M35.5 35.1l-.1 1-.2 .2-.3-.1M36.1 35.2h.4l.1 .5-.3 .2-.3-.1M36.1 35.1l-.2 1.2M37.1 35.2l.2-.1 .3 .1-.1 .6h-.5z"/>
<path d="M38.1 35.1l.1 .8 .3-.6 .2 .6 .3-.8M39.3 35.5l.6-.1v-.2h-.5l-.1 .5 .1 .2 .4-.1M40.5 35.1l-.1 .8M40.8 35.1l-.4 .2M52.1 35l.5 .5M52.6 35.5h.4M52.6 35.5v2.3M53.7 35.2h.4l.1 .5-.3 .2-.3-.1M53.7 34.7l-.1 1.2M54.8 35.1l-.1 .8M54.8 34.7v.1M55.8 35.2l-.3-.1-.2 .2v.5h.5"/>
<path d="M55.8 35.1l-.1 1-.2 .2-.3-.1M56.4 35.2h.4l.1 .5-.3 .2-.3-.1M56.4 35.1l-.2 1.2M57.4 35.2l.2-.1 .3 .1-.1 .6h-.5zM58.4 35.1l.1 .8 .3-.6 .2 .6 .3-.8M59.6 35.5l.6-.1v-.2h-.5l-.1 .5 .2 .2 .3-.1M60.8 35.1l-.1 .8M61.1 35.1l-.4 .2M23.4 66l.5 .5M23.9 66.5v2.4M23.9 66.5h.5M25 66.2h.5v.5l-.2 .3-.4-.1"/>
<path d="M25.1 65.8l-.2 1.2M26.1 66.2l-.1 .8M26.1 65.8v.1M27.2 66.2h-.4l-.2 .2v.5h.5M27.2 66.2l-.1 .9-.3 .3-.3-.1M27.7 66.2h.4l.1 .5-.3 .3-.3-.1M27.7 66.2l-.1 1.2M28.7 66.3l.2-.1 .3 .1-.1 .6-.4-.1zM29.7 66.2l.1 .8 .3-.6 .2 .6 .3-.8M31 66.6l.5-.2v-.2h-.4l-.2 .6 .2 .2 .3-.1M32.1 66.2l-.1 .8M32.4 66.2l-.3 .2"/>
</g>
<g fill="none" stroke="#840000" stroke-width=".31">
<path d="M141.9 52.7h2.9M176.6 45.5h2.9M202.9 55h2.8M212.4 55h2.9M222 55h2.9M61.9 64.6h2.9M61.9 98.1h2.9M141.9 87.3h2.9M176.6 80.1h2.9M202.9 89.7h2.8M212.4 89.7h2.9M222 89.7h2.9"/>
<path d="M176.6 114.8h2.9M61.9 133.9h2.9M141.9 122h2.9M202.9 124.3h2.8M212.4 124.3h2.9M222 124.3h2.9"/>
</g>
<g fill="none" stroke="#840000" stroke-width=".29">
<path d="M141.9 51.7h2.9M176.6 44.5h2.9M202.9 54.1h2.8M212.4 54.1h2.9M222 54.1h2.9M61.9 63.7h2.9M176.6 79.2h2.9M61.9 97.1h2.9M141.9 86.4h2.9M202.9 88.7h2.8M212.4 88.7h2.9M222 88.7h2.9"/>
<path d="M176.6 113.8h2.9M61.9 132.9h2.9M141.9 121h2.9M202.9 123.4h2.8M212.4 123.4h2.9M222 123.4h2.9"/>
</g>
<g fill="none" stroke="#008484" stroke-width=".2">
<path d="M18.8 34.9h.6l.1-.5-.7-.1v1.2M20.4 34.3l-.1 1-.4 .2M20.9 35.1h.9M21.7 32.5l-.1 1-.4 .2M22.2 33.7h.7M22.2 32.9l.3-.4v1.2M22.5 34.4l.1-.1a.64 .64 0 0 1 .5 .6 .64 .64 0 0 1-.5 .6l-.2-.4zM23.3 32.6l.5-.1 .2 .4-.7 .8h.7M23.6 34.4l.2-.1a.64 .64 0 0 1 .4 .6 .64 .64 0 0 1-.4 .6l-.3-.4zM24.6 34.4l.5-.1 .2 .4-.7 .8h.7M25.8 34.3h.4l.3 .2-.3 .4 .3 .1v.3l-.2 .2h-.5zM25.8 34.9h.4"/>
<path d="M42.7 33.8h.4l.2 .2-.2 .4 .2 .1v.3l-.2 .2h-.4zM42.7 34.4h.4M43.7 35l.4-1.2 .4 1.2M43.8 34.6h.6M44.7 33.8h.7M45 33.8v1.2M45.5 32a.6 .6 0 0 1 .7 .6 .6 .6 0 0 1-.7 .6zM45.7 33.8h.8l-.5 1.2M46.6 33.2h.7M46.6 32.3l.4-.3v1.2M47.4 33.8l-.3 .1-.2 .2v.7l.2 .2 .4-.1-.1-.6h-.3l-.2 .2M47.8 33.2h.7"/>
<path d="M47.8 32.3l.3-.3v1.2M48.1 33.9l.2-.1a.64 .64 0 0 1 .4 .6 .64 .64 0 0 1-.4 .6l-.3-.5zM49.2 34.5h.9M50.6 33.8h.8l-.5 1.2M62.4 32h.9M62.8 31.6v.9M63.7 31.3l.4 1.2 .4-1.2M64.9 31.3a.6 .6 0 0 1 .6 .6 .6 .6 0 0 1-.6 .6zM66.7 31.4a.53 .53 0 0 0-.7 .5 .53 .53 0 0 0 .7 .5M135.2 33.2h.9M135.7 32.8v.9M136.5 32.5l.4 1.2 .4-1.2"/>
<path d="M137.7 32.5a.6 .6 0 0 1 .7 .6 .6 .6 0 0 1-.7 .6zM139.6 32.6a.53 .53 0 0 0-.7 .5 .53 .53 0 0 0 .7 .5M33.7 48.5a.54 .54 0 0 0-.7 .5 .54 .54 0 0 0 .8 .5v-.4h-.2M35 48.4v1.2l-.7-1.2v1.2M35.6 48.4a.6 .6 0 0 1 .6 .6 .6 .6 0 0 1-.6 .6zM53.8 47.6h.9M54.2 47.2v.9M55.1 46.9h.8l-.4 .4 .3 .1v.5l-.2 .2-.5-.2M56.4 47.9v.2M56.8 46.9h.8l-.4 .4 .3 .1v.5l-.2 .2-.5-.2M57.9 53.7l.6-.1v-.5l-.6-.1v1.2M57.9 46.9l.4 1.2 .4-1.2"/>
<path d="M58.2 53.7l.4 .5M58.4 55.4l-.3 .1-.2 .2v.7l.2 .2 .4-.1-.1-.6h-.3l-.2 .2M59 53h.7l-.4 .5 .4 .1v.5l-.2 .1-.5-.1M59.6 55.4h-.5l-.1 .6 .6-.1v.6l-.1 .1-.5-.1M60.2 55.4v1.2M60.3 56.2l.3 .4M60.5 53l-.3 .8h.7M60.6 55.8l-.4 .5M60.8 53.4v.8M72 55l.4 1.2 .4-1.2M72.8 57.5h-.6v.4l.5 .2 .1 .3-.2 .2-.4-.1M72.9 59.9a.53 .53 0 0 0-.8 .5 .53 .53 0 0 0 .8 .5"/>
<path d="M73.3 58h.4M73.4 59.8a.6 .6 0 0 1 .7 .6 .6 .6 0 0 1-.7 .6zM73.9 55.1a.53 .53 0 0 0-.7 .5 .53 .53 0 0 0 .7 .5M73.9 57.4h-.6v1.2h.6M75.1 57.4v1.2l-.7-1.2v1.2M75.1 55.1a.53 .53 0 0 0-.7 .5 .53 .53 0 0 0 .7 .5M75.2 59.8h-.6v1.2h.6M75.7 59.8v1.2h.5M76.3 57.5h-.6v.4l.5 .2 .1 .3-.2 .2-.5-.1M76.8 58h.4M77.1 50.5v-1.4l.5 1 .5-1v1.4M77.4 57.4h-.6v1.2h.6"/>
<path d="M77.5 59.8l.4 .6M78.3 59.8l-.4 .6M78.8 49.8h.7l.1-.2-.1-.4-.7-.1v1.4M80.8 49.1h-.4a.97 .97 0 0 0 0 1.4l.5-.1 .1-.5-.3-.3-.4 .1-.1 .2M81.9 49l-.4 1h.9M82.2 49.6v.9M83 49.2l.2-.1a.77 .77 0 0 1 .5 .7 .77 .77 0 0 1-.5 .7l-.2-.1-.1-.4zM84.4 49.2l.2-.1a.77 .77 0 0 1 .5 .7 .77 .77 0 0 1-.5 .7l-.2-.1-.2-.4zM85.7 49.1a.72 .72 0 0 1 .8 .7 .72 .72 0 0 1-.8 .7zM87.3 47v1.1l.3 .3h.3l.2-.3v-1.1M87.9 49.1a.67 .67 0 0 0-.9 .7 .67 .67 0 0 0 .9 .6v-.5h-.2M88.5 50h1.1"/>
<path d="M89.5 47h-.7v.6l.2-.1 .4 .1 .2 .2-.1 .5-.2 .1-.5-.1M90.4 49.2l.2-.1a.77 .77 0 0 1 .5 .7 .77 .77 0 0 1-.5 .7l-.2-.1-.1-.4zM91.6 49.5l.4-.4v1.4M91.6 50.5h.8M93.1 50h1M94.8 49.1v1.4h.7M96 49.8h.5M96.7 49.1h-.7v1.4M97.2 50h1.1M98.8 57.6l.2 .1M98.9 49.1h.9l-.9 1.4h.9M99 57.4v.3"/>
<path d="M99 57.7l-.1 .2M99 57.7l.2 .2M99.3 57.6l-.3 .1M99.8 58h.5l.1-.5-.6-.1v1.2M100.1 58l.4 .6M100.7 55.6h.4M101 58h.4M101.3 55h-.6v1.2h.6M101.5 57.4h-.5v1.2h.5M101.8 55.6h.5l.1-.5-.6-.1v1.2M102.2 59.8a.54 .54 0 0 0-.7 .6 .54 .54 0 0 0 .7 .5v-.4h-.2M102.7 57.5h-.6v.4l.5 .2 .1 .3-.2 .2-.5-.1"/>
<path d="M102.8 56.2l.4-1.2 .4 1.2M102.9 55.9h.6M103.2 58h.4M103.4 59.8v1.2l-.7-1.2v1.2M103.8 57.4h-.6v1.2h.6M104 55a.6 .6 0 0 1 .7 .6 .6 .6 0 0 1-.7 .6zM104 59.8a.6 .6 0 0 1 .7 .6 .6 .6 0 0 1-.7 .6zM104.1 57.4h.7M104.4 57.4v1.2M145.9 54.2h.6M145.9 53.4l.3-.4v1.2M146.6 50.8a.53 .53 0 0 0-.8 .4 .53 .53 0 0 0 .8 .5"/>
<path d="M147.1 53.1l.2-.1a.64 .64 0 0 1 .4 .6 .64 .64 0 0 1-.4 .6l-.3-.4zM147.6 50.6l-.3 .1-.2 .2-.1 .7 .3 .2 .4-.1-.1-.5-.3-.1-.3 .2M148.2 53.4v.8l.5-.1M148.7 53.4v.8M148.9 51.2l-.3 .2-.3-.1-.1-.5 .4-.2 .3 .3-.1 .7-.2 .2h-.3M149.3 53.6h.4M149.8 53h-.5v1.2M157.1 49l.4 1.2 .4-1.2M157.3 54.4h.4M157.8 53.8h-.5v1.2h.5M158.3 49v1.2M158.7 46.7l.4-1.1 .4 1.1"/>
<path d="M158.8 46.4h.6M159 53.8v1.2l-.6-1.2v1.2M159.5 49v1.2l-.6-1.2v1.2M159.9 46.2l.6-.1v-.4l-.6-.1v1.1M161.6 45.6h-.3l-.2 .2-.1 .7 .3 .2 .4-.1-.1-.5-.3-.1-.3 .2M162.2 45.7l.4-.1 .3 .3-.8 .8h.8M162.2 43.2v.9l.2 .3 .4-.1 .1-.2v-.9M162.9 54.3h1.2l-1.2 .7h1.2M163 55.6a.54 .54 0 0 0 .5 .7 .54 .54 0 0 0 .5-.8h-.4v.2M163.1 53.2a.62 .62 0 0 1 .7-.1 .62 .62 0 0 1 .3 .7h-1.2zM163.3 45.6h.7l-.4 .4 .3 .1v.5l-.1 .1-.5-.1M163.4 43.3l.5-.1 .2 .3-.8 .9h.8"/>
<path d="M164.5 43.2h.7l-.4 .4 .4 .1v.5l-.2 .2-.5-.2M164.6 45.7l.1-.1a.64 .64 0 0 1 .4 .6 .64 .64 0 0 1-.4 .5l-.3-.4zM165.7 45.7l.2-.1a.64 .64 0 0 1 .4 .6 .64 .64 0 0 1-.4 .5l-.3-.4zM166.7 45.6h.8l-.8 1.1h.8M167.4 51.4h.4l.2 .3-.2 .3 .2 .1 .1 .3-.2 .2h-.5zM167.4 52h.4M168.4 45.6h-.3l-.2 .2v.7l.2 .2 .4-.1-.1-.5-.3-.1-.2 .2M168.4 54.4h.4M168.8 49.1l-.6 .1v.3l.5 .2 .1 .3-.2 .2h-.5M169 53.8h-.6v1.2M169.2 49l.3 1.2 .2-.8 .2 .8 .3-1.2M169.2 51.5h-.6v.4l.5 .2 .1 .3-.2 .2h-.4"/>
<path d="M169.5 53.8h.4l.2 .2-.2 .4 .2 .1v.3l-.2 .2h-.4zM169.5 54.4h.4M169.6 51.4h.7M169.9 51.4v1.2M180.5 46.2l.3-.3v1.2M180.5 47.1h.7M180.8 51.3l.2-.2v.7M180.8 51.8h.4M181.2 43.6a.53 .53 0 0 0-.7 .5 .53 .53 0 0 0 .7 .5M181.6 43.5h.8l-.5 1.2M181.7 46l.2-.1a.64 .64 0 0 1 .4 .6 .64 .64 0 0 1-.4 .6l-.3-.5zM182.8 43.6l.5-.1 .2 .3-.7 .9h.7"/>
<path d="M182.9 46l.2-.1a.64 .64 0 0 1 .4 .6 .64 .64 0 0 1-.4 .6l-.3-.5zM184 49.3h.7l-.4 .4 .3 .1v.5l-.1 .2-.5-.2M184 46.4l.4-.1 .1 .8M184 46.3v.8M185 46.4h.4M185.2 50.3v.2M185.6 46.9v1.2h.6M185.6 45.9h-.6v1.2M185.7 49.3h.7l-.4 .4 .4 .1v.5l-.2 .2-.5-.2M186.5 48.1h.7M186.5 47.2l.4-.3v1.2M186.9 49.7l.1 .7 .4-.1"/>
<path d="M187.4 49.7v.8M188 49.8h.7M188 49.3v1.2M188.7 49.3v1.2M191.6 51.1h.2l.2 .2-.5 .5h.5M196.4 55.4h.7l-.4 .5 .4 .1v.5l-.2 .1-.5-.1M196.5 53.7l.6-.1v-.5l-.6-.1v1.2M196.8 53.7l.4 .5M197.6 53h.7l-.4 .5 .4 .1v.5l-.2 .1-.5-.1M197.6 56.6h.7M197.6 55.8l.3-.4v1.2M198.8 55.4v1.2"/>
<path d="M198.9 53.1l.2-.1a.64 .64 0 0 1 .4 .6 .64 .64 0 0 1-.4 .6l-.3-.4zM198.9 56.2l.3 .4M199.2 55.8l-.4 .5M206.8 55.5l.4-.1 .3 .4-.8 .8h.8M207.5 53.2a.53 .53 0 0 0-.7 .4 .53 .53 0 0 0 .7 .5M207.9 53h.8l-.5 1.2M207.9 55.5l.5-.1 .2 .4-.7 .8h.7M209.1 55.8l.1 .8 .4-.1M209.6 55.8v.8M209.7 53h-.5l-.1 .6 .6-.1v.6l-.1 .1-.5-.1M210.2 56h.4M210.8 55.4h-.6v1.2"/>
<path d="M216.3 55.5l.5-.1 .2 .4-.7 .8h.7M217.1 53.2a.53 .53 0 0 0-.8 .4 .53 .53 0 0 0 .8 .5M217.5 53h.8l-.5 1.2M217.5 55.5l.4-.1 .3 .4-.8 .8h.8M218.7 55.8v.8l.5-.1M218.9 53.5l-.2 .3v.3l.2 .1h.2l.3-.2-.1-.3-.2-.2M218.9 53.5l-.2-.2 .2-.3h.2l.3 .3-.3 .2M218.9 53.5h.2M219.2 55.8v.8M219.8 56h.4M220.3 55.4h-.5v1.2M221 48.8h.9"/>
<path d="M221.5 48.3v1M222.4 48.1h.7l-.4 .4 .4 .1v.5l-.2 .2-.5-.2M223.6 49.1v.2M224.1 48.1h.7l-.4 .4 .4 .1v.5l-.2 .2-.5-.2M225.2 48.1l.4 1.2 .4-1.2M225.9 55.5l.5-.1 .2 .4-.8 .8h.8M226.6 53.2a.53 .53 0 0 0-.7 .4 .53 .53 0 0 0 .7 .5M227 55.5l.5-.1 .2 .4-.7 .8h.7M227.3 53.5l-.2 .3v.3l.2 .1h.2l.3-.2-.1-.3-.2-.2M227.3 53.5l-.2-.2 .2-.3h.2l.3 .3-.3 .2M227.3 53.5h.2M228.2 55.8l.1 .8 .4-.1"/>
<path d="M228.2 54.2h.7M228.2 53.4l.4-.4v1.2M228.7 55.8v.8M229.3 56h.4M229.9 55.4h-.6v1.2M19.4 64.4h.7M19.4 66.2l.4 1.2 .4-1.2M19.8 64.4v1.2M20.5 65.1l.6-.1v-.4l-.6-.2v1.2M21.1 66.2v1.2M21.1 66.7l-.3-.1-.2 .3 .1 .5h.4M21.6 64.6l.5-.2 .2 .4-.7 .8h.7"/>
<path d="M22.2 66.7l-.3-.1-.3 .3 .2 .5h.4M33.7 63.1h.9M34.1 62.6v.9M35 62.3l.4 1.2 .4-1.2M36.2 62.3a.6 .6 0 0 1 .7 .6 .6 .6 0 0 1-.7 .6zM38.1 62.5a.53 .53 0 0 0-.8 .4 .53 .53 0 0 0 .8 .5M55.2 71.2a.54 .54 0 0 0-.6 .5 .54 .54 0 0 0 .7 .5v-.4h-.2M56.5 71.1v1.2l-.7-1.2v1.2M57.1 71.1a.6 .6 0 0 1 .7 .6 .6 .6 0 0 1-.7 .6zM57.9 65h.6M57.9 64.1l.3-.3v1.2M57.9 62h.6v-.5l-.6-.1v1.2"/>
<path d="M58.2 62l.4 .6M59 61.4h.7l-.4 .4 .4 .2v.5l-.2 .1-.5-.1M59.1 63.9l.2-.1a.64 .64 0 0 1 .4 .6 .64 .64 0 0 1-.4 .6l-.3-.5zM60.2 63.8v1.2M60.3 64.5l.3 .5M60.6 64.2l-.4 .4M60.8 61.4h-.6v.6l.6-.1v.6l-.2 .1-.4-.1M65.8 66.2h.7M65.8 65.3l.3-.3v1.2M66.5 62.7a.53 .53 0 0 0-.7 .5 .53 .53 0 0 0 .7 .5M67 62.7l.5-.1 .2 .3-.8 .9h.8M67.6 65h-.6l-.1 .5h.6l.1 .6-.2 .1-.5-.1"/>
<path d="M68.1 63.8h.7M68.1 62.9l.4-.3v1.2M68.2 65.1l.2-.1a.64 .64 0 0 1 .4 .6 .64 .64 0 0 1-.4 .6l-.3-.5zM69.3 65.4h.3l.2 .2-.1 .5h-.4M69.3 65.4v1.2M70.4 65.5h.4M70.9 65h-.5v1.2M74.6 60.4h.4M76.5 61l.4-1.2 .4 1.2M76.6 60.6h.6M77.9 60.4v.6M101.6 62.3l.3 .2"/>
<path d="M101.9 62.2v.3M101.9 62.5l-.2 .2M101.9 62.5l.2 .2M102.2 62.3l-.3 .2M102.6 63.4v-1.2l.4 .8 .4-.8v1.2M104 62.8l.6-.1v-.4l-.6-.1v1.2M104.3 62.8l.4 .6M135.2 67.9h.9M135.7 67.4v.9M136.5 67.1l.4 1.2 .4-1.2M137.7 67.1a.6 .6 0 0 1 .7 .6 .6 .6 0 0 1-.7 .6zM139.6 67.2a.53 .53 0 0 0-.7 .5 .53 .53 0 0 0 .7 .5"/>
<path d="M142.5 60.4a.54 .54 0 0 0-.7 .6 .54 .54 0 0 0 .7 .5v-.4h-.2M143.7 60.4v1.2l-.7-1.2v1.2M144.3 60.4a.6 .6 0 0 1 .7 .6 .6 .6 0 0 1-.7 .6zM162.2 77.8v1l.2 .2h.4l.1-.2v-1M162.8 62.8a.54 .54 0 0 0-.7 .6 .54 .54 0 0 0 .7 .5v-.4h-.2M163.4 77.9l.5-.1 .2 .4-.8 .8h.8M164 62.8v1.2l-.7-1.2v1.2M164.6 62.8a.6 .6 0 0 1 .7 .6 .6 .6 0 0 1-.7 .6zM164.8 77.8l-.3 .8h.8M165.1 78.2v.8M181.2 78.2a.53 .53 0 0 0-.7 .5 .53 .53 0 0 0 .7 .5M181.6 78.1h.8l-.5 1.2"/>
<path d="M182.8 78.1h.7l-.4 .5 .4 .1v.5l-.2 .1-.5-.1M193.8 67.6a.54 .54 0 0 0-.7 .6 .54 .54 0 0 0 .8 .4v-.4h-.2M195.1 67.6v1.1l-.7-1.1v1.1M195.7 67.6a.6 .6 0 0 1 .6 .6 .6 .6 0 0 1-.6 .5zM196.4 63.8h.7M196.4 62.9l.4-.3v1.2M196.5 60.8h.6v-.5l-.6-.1v1.2M196.8 60.8l.4 .6M197.6 60.2h.7l-.4 .5 .4 .1v.5l-.2 .1-.5-.1M197.7 62.7l.2-.1a.64 .64 0 0 1 .4 .6 .64 .64 0 0 1-.4 .6l-.3-.5zM198.8 62.6v1.2M198.8 61.4h.7"/>
<path d="M198.8 60.5l.3-.3v1.2M198.9 63.3l.3 .5M199.2 63l-.4 .4M203.4 60.4a.54 .54 0 0 0-.7 .6 .54 .54 0 0 0 .7 .5v-.4h-.2M204.6 60.4v1.2l-.6-1.2v1.2M205.2 60.4a.6 .6 0 0 1 .7 .6 .6 .6 0 0 1-.7 .6zM212.9 60.4a.54 .54 0 0 0-.6 .6 .54 .54 0 0 0 .7 .5v-.4h-.2M214.2 60.4v1.2l-.7-1.2v1.2M214.8 60.4a.6 .6 0 0 1 .7 .6 .6 .6 0 0 1-.7 .6zM222.5 60.4a.54 .54 0 0 0-.7 .6 .54 .54 0 0 0 .8 .5v-.4h-.3M223.8 60.4v1.2l-.7-1.2v1.2M224.3 60.4a.6 .6 0 0 1 .7 .6 .6 .6 0 0 1-.7 .6z"/>
<path d="M19.4 97.9h.7M19.4 81.2h.7M19.5 83h.7l-.4 .4 .4 .1v.6l-.2 .1-.5-.1M19.8 81.2v1.2M19.8 97.9v1.2M20.5 98.5h.6v-.5l-.6-.1v1.2M20.5 81.8l.6-.1v-.4l-.6-.1v1.2M20.6 83.4l.3 .8 .3-.8M21.5 83h.8l-.4 .4 .3 .1v.6l-.2 .1-.5-.1M21.6 81.2h.7l-.4 .4 .4 .1v.5l-.2 .2-.5-.2M21.9 97.8l-.3 .9h.8M22.2 98.3v.8"/>
<path d="M31.1 82.3h.9M31.3 99h1M31.5 81.8v.9M31.8 98.5v.9M32.4 81.5h.8l-.4 .5 .3 .1v.5l-.2 .1-.5-.1M32.8 99.4h.7M32.8 98.6l.3-.4v1.2M33.7 82.6v.1M33.8 98.2l.4 1.2 .4-1.2M34.1 81.5h.8l-.4 .5 .3 .1v.5l-.2 .1-.5-.1M35.2 98.8l-.3 .2 .1 .3 .2 .1h.2l.2-.2v-.2l-.2-.2M35.2 98.8l-.3-.3 .3-.3h.2l.2 .3-.2 .3"/>
<path d="M35.2 98.8h.2M35.2 81.5l.4 1.2 .4-1.2M54 81.1h1M54.5 80.6v.9M55.5 80.7l.3-.4v1.2M55.5 81.5h.7M56.5 80.3l.4 1.2 .4-1.2M57.8 88.9h.7l-.4 .4 .4 .1v.6l-.2 .1-.5-.1M57.9 97.6l.3-.4v1.2M57.9 98.4h.6M57.9 80.8l-.3 .3 .1 .3 .2 .1h.2l.2-.2v-.4l-.2-.1M57.9 80.8l-.3-.2 .3-.3h.2l.2 .2-.2 .3"/>
<path d="M57.9 80.8h.2M57.9 87.1h.6v-.5l-.6-.1v1.2M57.9 95.5l.6-.1v-.4l-.6-.2v1.2M58.2 95.5l.4 .5M58.2 87.1l.4 .6M59 94.8h.7l-.4 .5 .4 .1v.5l-.2 .1-.5-.1M59 86.5h.7l-.4 .4 .4 .2v.5l-.2 .1-.5-.1M59 89l.5-.1 .2 .3-.8 .9h.8M59.1 97.3l.2-.1a.64 .64 0 0 1 .4 .6 .64 .64 0 0 1-.4 .6l-.3-.4zM60.1 94.8h.8l-.5 1.2M60.2 90v.1M60.2 97.2v1.2"/>
<path d="M60.3 98l.3 .4M60.6 97.6l-.4 .5M60.8 86.5h-.4l-.2 .3v.7l.2 .2 .4-.1v-.6l-.4-.1-.2 .3M61.3 88.9h-.5l-.1 .5h.6v.6l-.1 .1-.5-.1M61.9 88.9v1.2M62 89.6l.4 .5M62.4 89.3l-.5 .4M65.8 98.8l.3-.4v1.2M65.8 99.6h.7M66.5 96.2a.53 .53 0 0 0-.7 .4 .53 .53 0 0 0 .7 .5M67 96.2l.5-.2 .2 .4-.8 .8h.8M67.6 98.4h-.6l-.1 .6 .6-.1 .1 .6-.2 .1-.5-.1"/>
<path d="M68.1 96.2l.5-.2 .2 .4-.7 .8h.7M68.2 98.5l.2-.1a.64 .64 0 0 1 .4 .6 .64 .64 0 0 1-.4 .6l-.3-.4zM69.3 98.8v1.2M69.3 98.9l.3-.1 .2 .3-.1 .5h-.4M70.4 99h.4M70.9 98.4h-.5v1.2M72 88.5l.4 1.2 .4-1.2M72.8 90.9l-.6 .1v.3l.5 .2 .1 .3-.2 .2h-.4M72.9 93.4a.53 .53 0 0 0-.8 .4 .53 .53 0 0 0 .8 .5M73.3 91.4h.4M73.4 93.2a.6 .6 0 0 1 .7 .6 .6 .6 0 0 1-.7 .6zM73.9 88.6a.53 .53 0 0 0-.7 .5 .53 .53 0 0 0 .7 .4"/>
<path d="M73.9 90.9h-.6v1.1h.6M74.6 93.8h.4M75.1 90.9v1.1l-.7-1.1v1.1M75.1 88.6a.53 .53 0 0 0-.7 .5 .53 .53 0 0 0 .7 .4M75.2 93.2h-.6v1.2h.6M75.7 93.2v1.2h.5M76.3 90.9l-.6 .1v.3l.5 .2 .1 .3-.2 .2h-.5M76.5 94.4l.4-1.2 .4 1.2M76.6 94.1h.6M76.8 91.4h.4M77.1 84v-1.5l.5 1.1 .5-1.1v1.5M77.4 90.9h-.6v1.1h.6"/>
<path d="M77.5 93.2l.4 .7M77.9 93.9v.5M78.3 93.2l-.4 .7M78.8 83.3l.7-.1 .1-.2-.1-.3-.7-.2v1.5M80.8 82.5l-.4 .1a.97 .97 0 0 0 0 1.4l.5-.2 .1-.5-.3-.2h-.4l-.1 .2M81.9 82.5l-.4 1h.9M82.2 83v1M83 82.7l.2-.2a.77 .77 0 0 1 .5 .7 .77 .77 0 0 1-.5 .8l-.2-.2-.1-.4zM84.4 82.7l.2-.2a.77 .77 0 0 1 .5 .7 .77 .77 0 0 1-.5 .8l-.2-.2-.2-.4zM85.7 82.5a.72 .72 0 0 1 .8 .7 .72 .72 0 0 1-.8 .8zM86.6 80.4v1.2l.3 .2h.3l.3-.2v-1.2M87.9 82.6a.67 .67 0 0 0-.9 .6 .67 .67 0 0 0 .9 .7v-.6h-.2"/>
<path d="M88.1 80.8l.4-.4v1.4M88.1 81.8h.8M88.5 83.4h1.1M90.2 80.4h-.7l-.1 .7 .2-.1h.5l.2 .2-.1 .5-.2 .1-.6-.1M90.4 82.7l.2-.2a.77 .77 0 0 1 .5 .7 .77 .77 0 0 1-.5 .8l-.2-.2-.1-.4zM91.6 82.9l.4-.4v1.5M91.6 84h.8M93.1 83.4h1M94.8 82.5v1.5h.7M96 83.2h.5M96.7 82.5h-.7v1.5M97.2 83.4h1.1"/>
<path d="M98.8 91l.2 .1M98.9 82.5h.9l-.9 1.5h.9M99 90.9v.2M99 91.1l-.1 .3M99 91.1l.2 .3M99.3 91l-.3 .1M99.8 91.5l.5-.1 .1-.4-.6-.1v1.1M100.1 91.5l.4 .5M100.7 89h.4M101 91.4h.4M101.3 88.5h-.6v1.2h.6M101.5 90.9h-.5v1.1h.5"/>
<path d="M101.6 95.8l.3 .1M101.8 89.1l.5-.1 .1-.4-.6-.1v1.2M101.9 95.6v.3M101.9 95.9l-.2 .2M101.9 95.9l.2 .2M102.2 93.3a.54 .54 0 0 0-.7 .6 .54 .54 0 0 0 .7 .4v-.4h-.2M102.2 95.8l-.3 .1M102.6 96.8v-1.2l.4 .9 .4-.9v1.2M102.7 90.9l-.6 .1v.3l.5 .2 .1 .3-.2 .2h-.5M102.8 89.7l.4-1.2 .4 1.2M102.9 89.3h.6M103.2 91.4h.4"/>
<path d="M103.4 93.2v1.2l-.7-1.2v1.2M103.8 90.9h-.6v1.1h.6M104 88.5a.6 .6 0 0 1 .7 .6 .6 .6 0 0 1-.7 .6zM104 93.2a.6 .6 0 0 1 .7 .6 .6 .6 0 0 1-.7 .6zM104 96.3l.6-.1v-.5l-.6-.1v1.2M104.1 90.9h.7M104.3 96.3l.4 .5M104.4 90.9v1.1M142.5 95.1a.54 .54 0 0 0-.7 .5 .54 .54 0 0 0 .7 .5v-.4h-.2M143.7 95v1.2l-.7-1.2v1.2M144.3 95a.6 .6 0 0 1 .7 .6 .6 .6 0 0 1-.7 .6zM145.9 88l.3-.3v1.2"/>
<path d="M145.9 88.9h.6M146.6 85.4a.53 .53 0 0 0-.8 .5 .53 .53 0 0 0 .8 .5M147 85.3h.8l-.5 1.2M147.1 87.8l.2-.1a.64 .64 0 0 1 .4 .6 .64 .64 0 0 1-.4 .6l-.3-.5zM148.2 88.1v.7h.5M148.3 85.4l.2-.1a.64 .64 0 0 1 .4 .6 .64 .64 0 0 1-.4 .6l-.3-.5zM148.7 88.1v.8M149.3 88.2h.4M149.8 87.7h-.5v1.2M157.1 83.7l.4 1.2 .4-1.2M157.3 89h.4M157.8 88.5h-.5v1.2h.5"/>
<path d="M158.3 83.7v1.2M158.7 81.4l.4-1.2 .4 1.2M158.8 81.1h.6M159 88.5v1.2l-.6-1.2v1.2M159.5 83.7v1.2l-.6-1.2v1.2M159.9 80.8h.6v-.5l-.6-.1v1.2M161.6 80.2l-.3 .1-.2 .2-.1 .7 .3 .2 .4-.1-.1-.6h-.3l-.3 .2M162.2 80.3l.4-.1 .3 .3-.8 .9h.8M162.8 97.5a.54 .54 0 0 0-.7 .5 .54 .54 0 0 0 .7 .5v-.4h-.2M162.9 89h1.2l-1.2 .7h1.2M163 90.2a.54 .54 0 0 0 .5 .7 .54 .54 0 0 0 .5-.7h-.4v.2M163.1 87.8a.62 .62 0 0 1 .7 0 .62 .62 0 0 1 .3 .6h-1.2z"/>
<path d="M163.3 80.2h.7l-.4 .5 .3 .1v.5l-.1 .1-.5-.1M164 97.4v1.2l-.7-1.2v1.2M164.6 80.3l.1-.1a.64 .64 0 0 1 .4 .6 .64 .64 0 0 1-.4 .6l-.3-.5zM164.6 97.4a.6 .6 0 0 1 .7 .6 .6 .6 0 0 1-.7 .6zM165.7 80.3l.2-.1a.64 .64 0 0 1 .4 .6 .64 .64 0 0 1-.4 .6l-.3-.5zM166.7 80.2h.8l-.8 1.2h.8M167.4 86.1h.4l.2 .2-.2 .3 .2 .2 .1 .2-.2 .3h-.5zM167.4 86.6h.4M168.4 80.2l-.3 .1-.2 .2v.7l.2 .2 .4-.1-.1-.6h-.3l-.2 .2M168.4 89h.4M168.8 83.7l-.6 .1v.3l.5 .3 .1 .3-.2 .2-.5-.1M169 88.5h-.6v1.2"/>
<path d="M169.2 83.7l.3 1.2 .2-.9 .2 .9 .3-1.2M169.2 86.1l-.6 .1v.3l.5 .3 .1 .2-.2 .3-.4-.1M169.5 88.5h.4l.2 .2-.2 .3 .2 .1v.3l-.2 .3h-.4zM169.5 89h.4M169.6 86.1h.7M169.9 86.1v1.2M180.5 80.9l.3-.4v1.2M180.5 81.7h.7M180.8 85.9l.2-.2v.7M180.8 86.4h.4M181.7 80.6l.2-.1a.64 .64 0 0 1 .4 .6 .64 .64 0 0 1-.4 .6l-.3-.4zM182.9 80.6l.2-.1a.64 .64 0 0 1 .4 .6 .64 .64 0 0 1-.4 .6l-.3-.4z"/>
<path d="M184 83.9h.7l-.4 .5 .3 .1v.5l-.1 .1-.5-.1M184 80.9v.8M184 81h.4l.1 .7M185 81.1h.4M185.2 85v.1M185.6 81.5v1.2h.6M185.6 80.5h-.6v1.2M185.7 83.9h.7l-.4 .5 .4 .1v.5l-.2 .1-.5-.1M186.5 81.6l.5-.1 .2 .4-.7 .8h.7M186.9 84.3l.1 .7h.4M187.4 84.3v.8M188 83.9v1.2"/>
<path d="M188 84.5h.7M188.7 83.9v1.2M191.6 85.8l.2-.1 .2 .2-.5 .5h.5M196.4 98.4h.7M196.4 90.4l.4-.3v1.2M196.4 97.6l.4-.4v1.2M196.4 91.3h.7M196.5 95.5l.6-.1v-.4l-.6-.2v1.2M196.5 88.3l.6-.1v-.4l-.6-.1v1.2M196.8 95.5l.4 .5M196.8 88.3l.4 .6M197.5 90.1h.8l-.4 .4 .3 .1v.5l-.2 .2-.5-.2"/>
<path d="M197.6 94.8h.7l-.4 .5 .4 .1v.5l-.2 .1-.5-.1M197.6 87.7h.7l-.4 .4 .4 .1v.6l-.2 .1-.5-.1M197.7 97.3l.2-.1a.64 .64 0 0 1 .4 .6 .64 .64 0 0 1-.4 .6l-.3-.4zM198.7 94.8h.8l-.4 .5 .3 .1v.5l-.2 .1-.5-.1M198.8 90.1v1.2M198.8 97.2v1.2M198.8 87.8l.4-.1 .3 .3-.8 .9h.8M198.9 98l.3 .4M198.9 90.8l.3 .5M199.2 97.6l-.4 .5M199.2 90.5l-.4 .4M203.4 95.1a.54 .54 0 0 0-.7 .5 .54 .54 0 0 0 .7 .5v-.4h-.2"/>
<path d="M204.6 95v1.2l-.6-1.2v1.2M205.2 95a.6 .6 0 0 1 .7 .6 .6 .6 0 0 1-.7 .6zM206.8 90.2l.4-.1 .3 .3-.8 .9h.8M207.5 87.8a.53 .53 0 0 0-.7 .5 .53 .53 0 0 0 .7 .5M207.9 87.7h.8l-.5 1.2M207.9 90.2l.5-.1 .2 .3-.7 .9h.7M209.1 90.5l.1 .7h.4M209.6 90.5v.8M209.7 87.7h-.4l-.1 .3-.1 .7 .2 .2 .4-.1v-.6l-.4-.1-.2 .3M210.2 90.6h.4M210.8 90.1h-.6v1.2M212.9 95.1a.54 .54 0 0 0-.6 .5 .54 .54 0 0 0 .7 .5v-.4h-.2"/>
<path d="M214.2 95v1.2l-.7-1.2v1.2M214.8 95a.6 .6 0 0 1 .7 .6 .6 .6 0 0 1-.7 .6zM216.3 90.2l.5-.1 .2 .3-.7 .9h.7M217.1 87.8a.53 .53 0 0 0-.8 .5 .53 .53 0 0 0 .8 .5M217.5 87.7h.8l-.5 1.2M217.5 90.2l.4-.1 .3 .3-.8 .9h.8M218.7 90.5v.7h.5M219.2 90.5v.8M219.4 88.2l-.3 .2h-.3l-.1-.6 .4-.1 .3 .2-.1 .7-.2 .2-.3 .1M219.8 90.6h.4M220.3 90.1h-.5v1.2M221.3 83.4h.9"/>
<path d="M221.8 83v.9M222.5 95.1a.54 .54 0 0 0-.7 .5 .54 .54 0 0 0 .8 .5v-.4h-.3M222.7 83.9h.7M222.7 83.1l.4-.4v1.2M223.8 95v1.2l-.7-1.2v1.2M223.8 82.7l.4 1.2 .4-1.2M224.3 95a.6 .6 0 0 1 .7 .6 .6 .6 0 0 1-.7 .6zM225.1 83.2l-.2-.2 .2-.3h.3l.2 .2-.2 .3M225.1 83.2h.3M225.1 83.2l-.2 .2 .1 .4 .1 .1h.3l.2-.2-.1-.4-.1-.1M225.9 90.2l.5-.1 .2 .3-.8 .9h.8M226.6 87.8a.53 .53 0 0 0-.7 .5 .53 .53 0 0 0 .7 .5"/>
<path d="M227 90.2l.5-.1 .2 .3-.7 .9h.7M227.3 88.2l-.2-.2 .2-.3h.2l.3 .2-.3 .3M227.3 88.2l-.2 .2v.4l.2 .1h.2l.3-.2-.1-.4-.2-.1M227.3 88.2h.2M228.2 90.5l.1 .7h.4M228.2 87.8l.5-.1 .2 .3-.7 .9h.7M228.7 90.5v.8M229.3 90.6h.4M229.9 90.1h-.6v1.2M19.4 114.6h.7M19.5 100.9h.7M19.5 100l.4-.3v1.2"/>
<path d="M19.6 116.5l.2-.1a.64 .64 0 0 1 .4 .6 .64 .64 0 0 1-.4 .6l-.3-.4zM19.8 114.6v1.2M20.5 115.2h.6v-.5l-.6-.1v1.2M20.6 100.1l.3 .8 .3-.8M20.6 116.8l.3 .8 .3-.8M21.8 100.2l-.2 .2v.4l.2 .1h.2l.3-.2-.1-.4-.2-.1M21.8 100.2l-.2-.2 .2-.3h.2l.3 .2-.3 .3M21.8 116.9l-.2-.2 .2-.3h.2l.3 .3-.3 .2M21.8 116.9l-.2 .3v.3l.2 .1h.2l.3-.2-.1-.3-.2-.2M21.8 100.2h.2M21.8 116.9h.2M22.3 114.6h-.6l-.1 .6 .6-.1 .1 .6-.2 .1-.5-.1"/>
<path d="M31.3 115.7h1M31.8 115.3v.9M32.9 115.1l.2-.1a.64 .64 0 0 1 .4 .6 .64 .64 0 0 1-.4 .6l-.3-.5zM33.8 115l.4 1.2 .4-1.2M35.2 115.5l-.3 .2 .1 .3 .2 .2h.2l.2-.3v-.3l-.2-.1M35.2 115.5l-.3-.2 .3-.3h.2l.2 .2-.2 .3M35.2 115.5h.2M54 116.9h1M54.5 116.4v1M55.2 104.6a.54 .54 0 0 0-.6 .6 .54 .54 0 0 0 .7 .5v-.4h-.2M55.6 116.3l.2-.1a.64 .64 0 0 1 .4 .6 .64 .64 0 0 1-.4 .6l-.3-.5zM56.5 104.6v1.2l-.7-1.2v1.2"/>
<path d="M56.5 116.2l.4 1.2 .4-1.2M57.1 104.6a.6 .6 0 0 1 .7 .6 .6 .6 0 0 1-.7 .6zM57.9 116.7l-.3-.3 .3-.2h.2l.2 .2-.2 .3M57.9 116.7l-.3 .2 .1 .3 .2 .2h.2l.2-.3v-.3l-.2-.1M57.9 116.7h.2M62.4 116.9h.9M62.9 116.4v1M63.8 117.4h.7M63.8 116.5l.4-.3v1.2M64.9 116.2l.4 1.2 .4-1.2M66.2 116.7l-.2-.3 .2-.2h.3l.2 .2-.2 .3M66.2 116.7l-.2 .2 .1 .3 .1 .2h.3l.2-.3-.1-.3-.1-.1"/>
<path d="M66.2 116.7h.3M77.1 119.8v-1.4l.5 1 .5-1v1.4M78.8 119.1h.7l.1-.2-.1-.4-.7-.1v1.4M80.8 118.4h-.4a.97 .97 0 0 0 0 1.4l.5-.1 .1-.5-.3-.3-.4 .1-.1 .2M81.9 118.3l-.4 1h.9M82.2 118.9v.9M83 118.5l.2-.1a.77 .77 0 0 1 .5 .7 .77 .77 0 0 1-.5 .7l-.2-.1-.1-.4zM84.4 118.5l.2-.1a.77 .77 0 0 1 .5 .7 .77 .77 0 0 1-.5 .7l-.2-.1-.2-.4zM85.7 118.4a.72 .72 0 0 1 .8 .7 .72 .72 0 0 1-.8 .7zM86.6 116.3v1.1l.3 .3h.3l.3-.3v-1.1M87.9 118.4a.67 .67 0 0 0-.9 .7 .67 .67 0 0 0 .9 .6v-.5h-.2M88.1 116.7l.4-.4v1.4"/>
<path d="M88.1 117.7h.8M88.5 119.3h1.1M90.1 116.3h-.4a.97 .97 0 0 0 0 1.4l.5-.2 .1-.4-.3-.3-.4 .1-.2 .2M90.4 118.5l.2-.1a.77 .77 0 0 1 .5 .7 .77 .77 0 0 1-.5 .7l-.2-.1-.1-.4zM91.6 118.8l.4-.4v1.4M91.6 119.8h.8M93.1 119.3h1M94.8 118.4v1.4h.7M96 119.1h.5M96.7 118.4h-.7v1.4M97.2 119.3h1.1M98.9 118.4h.9l-.9 1.4h.9"/>
<path d="M135.2 102.5h.9M135.7 102.1v.9M136.5 101.8l.4 1.2 .4-1.2M137.7 101.8a.6 .6 0 0 1 .7 .6 .6 .6 0 0 1-.7 .6zM139.6 101.9a.53 .53 0 0 0-.7 .5 .53 .53 0 0 0 .7 .5M147 119.9h.8l-.5 1.2M157.1 118.3l.4 1.2 .4-1.2M158.3 118.3v1.2M158.7 116l.4-1.2 .4 1.2M158.8 115.7h.6M159.5 118.3v1.2l-.6-1.2v1.2M159.9 115.5l.6-.1v-.4l-.6-.2v1.2"/>
<path d="M161.6 114.8l-.3 .1-.2 .2-.1 .7 .3 .2 .4-.1-.1-.5-.3-.1-.3 .2M162.2 115l.4-.2 .3 .4-.8 .8h.8M162.2 112.5v.9l.2 .3 .4-.1 .1-.2v-.9M163.3 114.8h.7l-.4 .5 .3 .1v.5l-.1 .1-.5-.1M163.4 112.6l.5-.1 .2 .3-.8 .9h.8M164.6 115l.1-.2a.64 .64 0 0 1 .4 .6 .64 .64 0 0 1-.4 .6l-.3-.4zM165.2 112.5h-.6l-.1 .5h.6l.1 .5-.2 .2-.5-.2M165.7 115l.2-.2a.64 .64 0 0 1 .4 .6 .64 .64 0 0 1-.4 .6l-.3-.4zM166.7 114.8h.8l-.8 1.2h.8M168.4 114.8l-.3 .1-.2 .2v.7l.2 .2 .4-.1-.1-.5-.3-.1-.2 .2M168.8 118.4h-.6v.4l.5 .2 .1 .3-.2 .2h-.5M169.2 118.3l.3 1.2 .2-.8 .2 .8 .3-1.2"/>
<path d="M180.5 116.4h.7M180.5 115.5l.3-.3v1.2M181.2 112.9a.53 .53 0 0 0-.7 .5 .53 .53 0 0 0 .7 .5M181.6 112.8h.8l-.5 1.2M181.7 115.3l.2-.1a.64 .64 0 0 1 .4 .6 .64 .64 0 0 1-.4 .6l-.3-.5zM182.9 115.3l.2-.1a.64 .64 0 0 1 .4 .6 .64 .64 0 0 1-.4 .6l-.3-.5zM183.1 112.7l-.3 .9h.8M183.4 113.2v.8M184 118.6h.7l-.4 .4 .3 .1v.5l-.1 .1-.5-.1M184 115.6v.8M184 115.7l.4-.1 .1 .8M185 115.7h.4"/>
<path d="M185.2 119.6v.1M185.6 116.2v1.2h.6M185.6 115.2h-.6v1.2M185.7 118.6h.7l-.4 .4 .4 .1v.5l-.2 .1-.5-.1M186.5 116.2h.7l-.4 .4 .3 .1v.5l-.1 .2-.5-.2M186.9 118.9l.1 .8 .4-.1M187.4 118.9v.8M188 119.1h.7M188 118.6v1.1M188.7 118.6v1.1M193.8 102.3a.54 .54 0 0 0-.7 .5 .54 .54 0 0 0 .8 .5v-.4h-.2M195.1 102.2v1.2l-.7-1.2v1.2"/>
<path d="M195.7 102.2a.6 .6 0 0 1 .6 .6 .6 .6 0 0 1-.6 .6zM221.3 118.1h.9M221.8 117.6v1M222.8 117.5l.2-.1a.64 .64 0 0 1 .4 .6 .64 .64 0 0 1-.4 .6l-.3-.5zM223.8 117.4l.4 1.2 .4-1.2M225.1 117.9l-.2-.3 .2-.2h.3l.2 .2-.2 .3M225.1 117.9l-.2 .2 .1 .3 .1 .2h.3l.2-.3-.1-.3-.1-.1M225.1 117.9h.3M17 136.9a.54 .54 0 0 0-.7 .6 .54 .54 0 0 0 .8 .4v-.4h-.3M18.3 136.8v1.2l-.7-1.2v1.2M18.8 136.8a.6 .6 0 0 1 .7 .6 .6 .6 0 0 1-.7 .6zM19.4 126.6h.7"/>
<path d="M19.8 126.6v1.2M20.2 128.4a.54 .54 0 0 0-.7 .6 .54 .54 0 0 0 .8 .5v-.4h-.3M20.5 127.2l.6-.1v-.4l-.6-.1v1.2M21.5 128.4v1.2l-.7-1.2v1.2M22 128.4a.6 .6 0 0 1 .7 .6 .6 .6 0 0 1-.7 .6zM22.2 126.6h-.3l-.2 .3-.1 .6 .3 .3 .4-.2-.1-.5-.3-.1-.3 .2M57.8 124.7h.8l-.5 1.2M57.9 134.3h.6M57.9 133.4l.3-.3v1.2M57.9 123l.6-.1v-.5l-.6-.1v1.2M57.9 131.3h.6v-.5l-.6-.1v1.2M58.2 131.3l.4 .6"/>
<path d="M58.2 123l.4 .5M59 130.7h.7l-.4 .4 .4 .2v.5l-.2 .1-.5-.1M59 122.3h.7l-.4 .5 .4 .1v.5l-.2 .1-.5-.1M59.1 125.8v.1M59.1 133.2l.2-.1a.64 .64 0 0 1 .4 .6 .64 .64 0 0 1-.4 .6l-.3-.5zM60.2 133.1v1.2M60.2 124.7h-.6v.6l.5-.1 .1 .6-.2 .1-.4-.1M60.3 133.8l.3 .5M60.4 122.8l-.2-.2 .2-.3h.2l.3 .3-.3 .2M60.4 122.8l-.2 .3v.3l.2 .1h.2l.3-.2-.1-.3-.2-.2M60.4 122.8h.2M60.6 133.5l-.4 .4"/>
<path d="M60.8 124.7v1.2M60.9 131.2l-.3 .2h-.3l-.1-.6 .4-.1 .3 .2-.1 .7-.2 .2-.3 .1M60.9 125.5l.3 .4M61.2 125.1l-.4 .5M65.8 134.6l.3-.3v1.2M65.8 135.5h.7M66.5 132a.53 .53 0 0 0-.7 .5 .53 .53 0 0 0 .7 .5M67 132l.5-.1 .2 .3-.8 .9h.8M67.6 134.3h-.6l-.1 .5h.6l.1 .6-.2 .1-.5-.1M68.1 131.9h.7l-.4 .4 .4 .2v.5l-.2 .1-.5-.1M68.2 134.4l.2-.1a.64 .64 0 0 1 .4 .6 .64 .64 0 0 1-.4 .6l-.3-.5zM69.3 134.7v1.2"/>
<path d="M69.3 134.7h.3l.2 .2-.1 .5h-.4M70.4 134.8h.4M70.9 134.3h-.5v1.2M72 124.3l.4 1.2 .4-1.2M72.8 126.8h-.6v.3l.5 .3 .1 .3-.2 .2-.4-.1M72.9 129.2a.53 .53 0 0 0-.8 .5 .53 .53 0 0 0 .8 .5M73.3 127.3h.4M73.4 129.1a.6 .6 0 0 1 .7 .6 .6 .6 0 0 1-.7 .6zM73.9 124.4a.53 .53 0 0 0-.7 .5 .53 .53 0 0 0 .7 .5M73.9 126.7h-.6v1.2h.6M74.6 129.7h.4M75.1 126.7v1.2l-.7-1.2v1.2"/>
<path d="M75.1 124.4a.53 .53 0 0 0-.7 .5 .53 .53 0 0 0 .7 .5M75.2 129.1h-.6v1.2h.6M75.7 129.1v1.2h.5M76.3 126.8h-.6v.3l.5 .3 .1 .3-.2 .2-.5-.1M76.5 130.3l.4-1.2 .4 1.2M76.6 129.9h.6M76.8 127.3h.4M77.4 126.7h-.6v1.2h.6M77.5 129.1l.4 .6M77.9 129.7v.6M78.3 129.1l-.4 .6M98.8 126.9l.2 .1"/>
<path d="M99 126.7v.3M99 127l-.1 .2M99 127l.2 .2M99.3 126.9l-.3 .1M99.8 127.3h.5l.1-.5-.6-.1v1.2M100.1 127.3l.4 .6M100.7 124.9h.4M101 127.3h.4M101.3 124.3h-.6v1.2h.6M101.5 126.7h-.5v1.2h.5M101.6 131.6l.3 .2M101.8 124.9h.5l.1-.5-.6-.1v1.2"/>
<path d="M101.9 131.5v.3M101.9 131.8l-.2 .2M101.9 131.8l.2 .2M102.2 129.1a.54 .54 0 0 0-.7 .6 .54 .54 0 0 0 .7 .5v-.4h-.2M102.2 131.6l-.3 .2M102.6 132.7v-1.2l.4 .8 .4-.8v1.2M102.7 126.8h-.6v.3l.5 .3 .1 .3-.2 .2-.5-.1M102.8 125.5l.4-1.2 .4 1.2M102.9 125.2h.6M103.2 127.3h.4M103.4 129.1v1.2l-.7-1.2v1.2M103.8 126.7h-.6v1.2h.6"/>
<path d="M104 124.3a.6 .6 0 0 1 .7 .6 .6 .6 0 0 1-.7 .6zM104 129.1a.6 .6 0 0 1 .7 .6 .6 .6 0 0 1-.7 .6zM104 132.1l.6-.1v-.4l-.6-.1v1.2M104.1 126.7h.7M104.3 132.1l.4 .6M104.4 126.7v1.2M142.5 129.7a.54 .54 0 0 0-.7 .6 .54 .54 0 0 0 .7 .5v-.4h-.2M143.7 129.7v1.2l-.7-1.2v1.2M144.3 129.7a.6 .6 0 0 1 .7 .6 .6 .6 0 0 1-.7 .6zM145.9 122.7l.3-.4v1.2M145.9 123.5h.6M146.6 120.1a.53 .53 0 0 0-.8 .4 .53 .53 0 0 0 .8 .5"/>
<path d="M147.1 122.4l.2-.1a.64 .64 0 0 1 .4 .6 .64 .64 0 0 1-.4 .6l-.3-.4zM148.2 122.7v.8l.5-.1M148.2 121.1h.7M148.2 120.3l.3-.4v1.2M148.7 122.7v.8M149.3 122.9h.4M149.8 122.3h-.5v1.2M157.3 123.7h.4M157.8 123.1h-.5v1.2h.5M159 123.1v1.2l-.6-1.2v1.2M162.8 132.1a.54 .54 0 0 0-.7 .6 .54 .54 0 0 0 .7 .4v-.3h-.2M162.9 123.6h1.2l-1.2 .7h1.2"/>
<path d="M163 124.9a.54 .54 0 0 0 .5 .7 .54 .54 0 0 0 .5-.8h-.4v.2M163.1 122.5a.62 .62 0 0 1 .7-.1 .62 .62 0 0 1 .3 .6h-1.2zM164 132.1v1.2l-.7-1.2v1.2M164.6 132.1a.6 .6 0 0 1 .7 .6 .6 .6 0 0 1-.7 .6zM167.4 120.7h.4l.2 .2-.2 .4 .2 .1 .1 .3-.2 .2h-.5zM167.4 121.3h.4M168.4 123.7h.4M169 123.1h-.6v1.2M169.2 120.8h-.6v.4l.5 .2 .1 .3-.2 .2h-.4M169.5 123.1h.4l.2 .2-.2 .4 .2 .1v.3l-.2 .2h-.4zM169.5 123.7h.4M169.6 120.7h.7"/>
<path d="M169.9 120.7v1.2M180.8 121.1h.4M180.8 120.6l.2-.2v.7M191.6 120.4h.2l.2 .2-.5 .5h.5M203.4 129.7a.54 .54 0 0 0-.7 .6 .54 .54 0 0 0 .7 .5v-.4h-.2M204.6 129.7v1.2l-.6-1.2v1.2M205.2 129.7a.6 .6 0 0 1 .7 .6 .6 .6 0 0 1-.7 .6zM206.8 124.8l.4-.1 .3 .4-.8 .8h.8M207.5 122.4a.53 .53 0 0 0-.7 .5 .53 .53 0 0 0 .7 .5M207.9 122.3h.8l-.5 1.2M207.9 124.8l.5-.1 .2 .4-.7 .8h.7M209.1 122.3h.8l-.6 1.2"/>
<path d="M209.1 125.1l.1 .8 .4-.1M209.6 125.1v.8M210.2 125.3h.4M210.8 124.7h-.6v1.2M212.9 129.7a.54 .54 0 0 0-.6 .6 .54 .54 0 0 0 .7 .5v-.4h-.2M214.2 129.7v1.2l-.7-1.2v1.2M214.8 129.7a.6 .6 0 0 1 .7 .6 .6 .6 0 0 1-.7 .6zM216.3 124.8l.5-.1 .2 .4-.7 .8h.7M217.1 122.4a.53 .53 0 0 0-.8 .5 .53 .53 0 0 0 .8 .5M217.5 124.8l.4-.1 .3 .4-.8 .8h.8M217.8 122.8l-.3-.2 .3-.3h.2l.2 .3-.2 .2M217.8 122.8l-.3 .3 .1 .3 .2 .1h.2l.2-.2v-.3l-.2-.2"/>
<path d="M217.8 122.8h.2M218.7 125.1v.8l.5-.1M218.8 122.4l.2-.1a.64 .64 0 0 1 .4 .6 .64 .64 0 0 1-.4 .6l-.3-.4zM219.2 125.1v.8M219.8 125.3h.4M220.3 124.7h-.5v1.2M222.5 129.7a.54 .54 0 0 0-.7 .6 .54 .54 0 0 0 .8 .5v-.4h-.3M223.8 129.7v1.2l-.7-1.2v1.2M224.3 129.7a.6 .6 0 0 1 .7 .6 .6 .6 0 0 1-.7 .6zM225.9 124.8l.5-.1 .2 .4-.8 .8h.8M226.6 122.4a.53 .53 0 0 0-.7 .5 .53 .53 0 0 0 .7 .5M227 124.8l.5-.1 .2 .4-.7 .8h.7"/>
<path d="M227.3 122.8l-.2-.2 .2-.3h.2l.3 .3-.3 .2M227.3 122.8l-.2 .3v.3l.2 .1h.2l.3-.2-.1-.3-.2-.2M227.3 122.8h.2M228.2 122.3h.7l-.4 .5 .4 .1v.5l-.2 .1-.5-.1M228.2 125.1l.1 .8 .4-.1M228.7 125.1v.8M229.3 125.3h.4M229.9 124.7h-.6v1.2M55.2 140.5a.54 .54 0 0 0-.6 .5 .54 .54 0 0 0 .7 .5v-.4h-.2M56.5 140.4v1.2l-.7-1.2v1.2M57.1 140.4a.6 .6 0 0 1 .7 .6 .6 .6 0 0 1-.7 .6zM112.6 140.5a.54 .54 0 0 0-.7 .5 .54 .54 0 0 0 .7 .5v-.4h-.2"/>
<path d="M113.8 140.4v1.2l-.6-1.2v1.2M114.4 140.4a.6 .6 0 0 1 .7 .6 .6 .6 0 0 1-.7 .6z"/>
</g>
<path d="M63.4 34.9h2.2M64.5 33.8v2.1M136.3 36.1h2.2M137.4 35v2.1M34.8 65.9h2.1M35.8 64.8v2.2M136.3 70.7h2.2M137.4 69.6v2.2M136.3 105.3h2.2M137.4 104.3v2.1" fill="none" stroke="#840000" stroke-width=".48"/>
<g fill="#008400" stroke="#008400" stroke-width=".35">
<circle cx="143.4" cy="73.7" r=".43"/>
<circle cx="113.5" cy="60.5" r=".43"/>
<circle cx="143.4" cy="39" r=".43"/>
<circle cx="143.4" cy="49.8" r=".43"/>
<circle cx="56.2" cy="135.8" r=".43"/>
<circle cx="56.2" cy="100" r=".43"/>
<circle cx="56.2" cy="127.5" r=".43"/>
<circle cx="56.2" cy="58.2" r=".43"/>
<circle cx="56.2" cy="52.2" r=".43"/>
<circle cx="56.2" cy="91.6" r=".43"/>
<circle cx="56.2" cy="66.5" r=".43"/>
<circle cx="56.2" cy="85.6" r=".43"/>
<circle cx="143.4" cy="119.1" r=".43"/>
<circle cx="143.4" cy="108.3" r=".43"/>
<circle cx="143.4" cy="84.4" r=".43"/>
<circle cx="113.5" cy="89.2" r=".43"/>
<circle cx="113.5" cy="94" r=".43"/>
<circle cx="113.5" cy="129.8" r=".43"/>
<circle cx="113.5" cy="125.1" r=".43"/>
<circle cx="194.7" cy="92.8" r=".43"/>
<circle cx="194.7" cy="86.8" r=".43"/>
<circle cx="223.4" cy="86.8" r=".43"/>
<circle cx="204.3" cy="86.8" r=".43"/>
<circle cx="213.9" cy="86.8" r=".43"/>
<circle cx="223.4" cy="121.5" r=".43"/>
<circle cx="213.9" cy="121.5" r=".43"/>
<circle cx="204.3" cy="121.5" r=".43"/>
<circle cx="194.7" cy="121.5" r=".43"/>
<circle cx="223.4" cy="52.2" r=".43"/>
<circle cx="204.3" cy="52.2" r=".43"/>
<circle cx="213.9" cy="52.2" r=".43"/>
<circle cx="194.7" cy="58.2" r=".43"/>
<circle cx="194.7" cy="52.2" r=".43"/>
</g>
</svg>
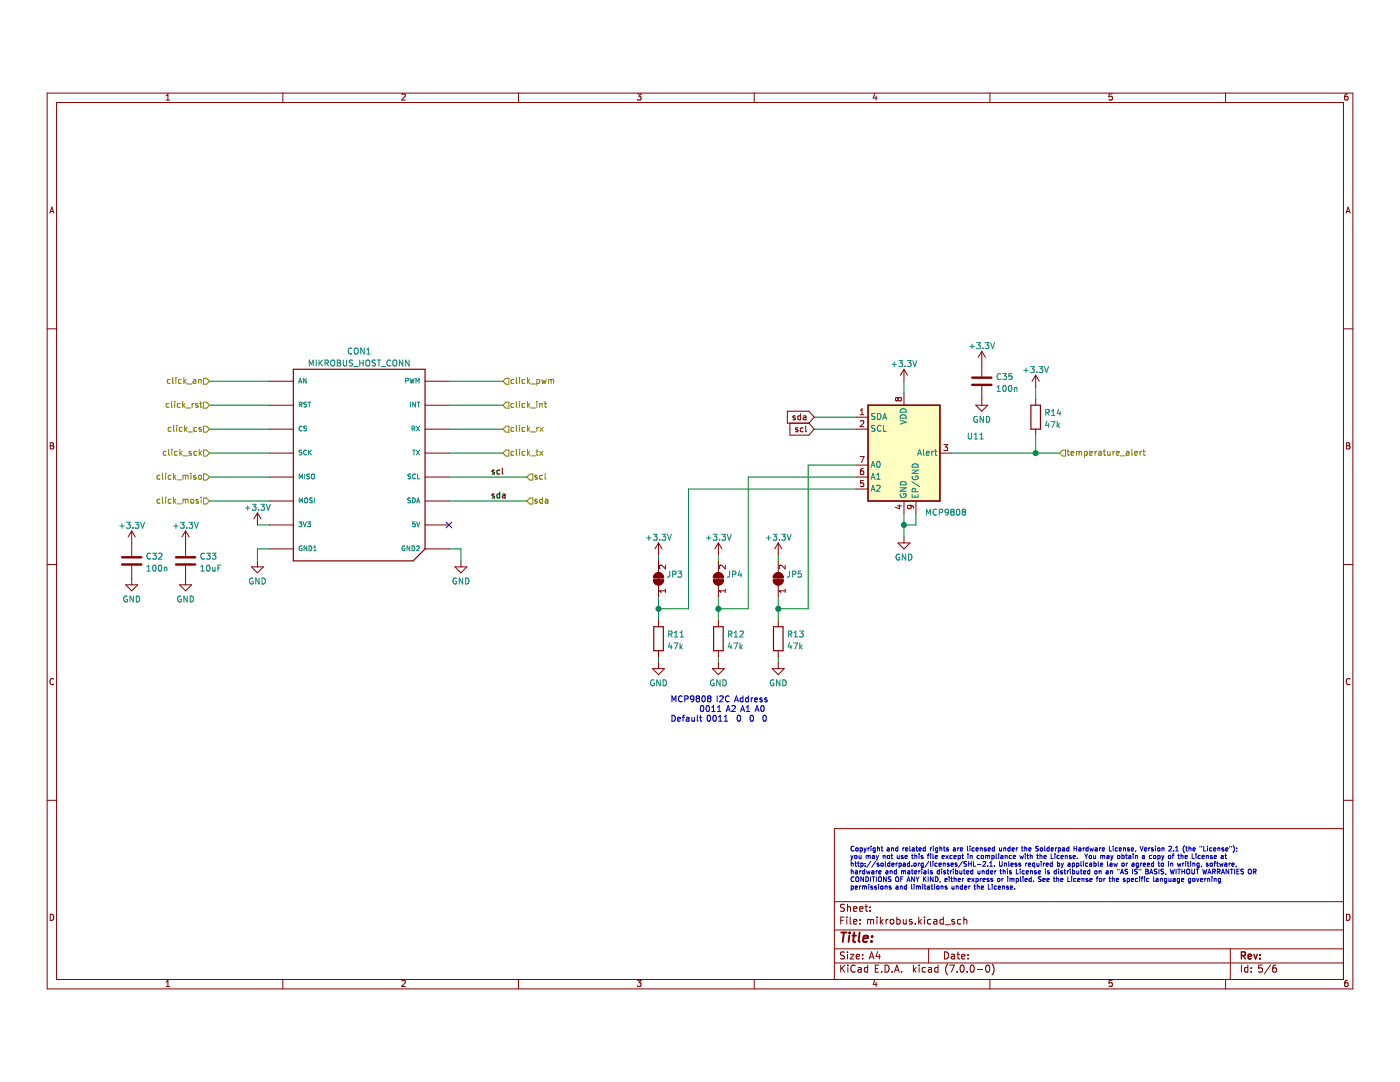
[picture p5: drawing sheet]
<svg xmlns="http://www.w3.org/2000/svg" width="279mm" height="216mm" viewBox="0 0 279 216" stroke-linecap="round" stroke-linejoin="round" font-family="sans-serif">
<path d="M0 9.2h279.4v206.7h-279.4z" fill-rule="evenodd" fill="#fff" stroke="#fff" stroke-width=".35"/>
<g fill="none" stroke="#840000" stroke-width=".2">
<path d="M9.4 18.6h260.6v178.7h-260.6zM33.2 20h.7M33.2 19.1l.3-.4v1.3M56.4 18.6v1.9M80.2 18.9l.5-.2 .2 .4-.8 .9h.8M103.5 18.6v1.9M127.2 18.7h.7l-.4 .5 .4 .1v.6l-.2 .1-.5-.1M150.5 18.6v1.9M174.6 18.7l-.3 .9h.7M174.9 19.2v.8M197.6 18.6v1.9M221.9 18.7h-.5l-.1 .6h.6v.6l-.1 .1-.5-.1"/>
<path d="M244.6 18.6v1.9M268.9 18.7l-.3 .1-.2 .2-.1 .7 .3 .3 .4-.1-.1-.6-.3-.1-.3 .2M11.3 20.5h256.8v174.9h-256.8zM9.9 42.5l.5-1.2 .4 1.2M10.1 42.2h.5M268.6 42.5l.5-1.2 .4 1.2M268.8 42.2h.5M9.4 65.6h1.9M53.8 76.1h4.7M84.8 76.1h4.8M179.2 79.5l.3-.2h.2l.2 .2v.3l-.2 .2-.4-.1-.1-.1M179.2 79.5l-.2-.2-.3 .2 .1 .4 .1 .1 .3-.2"/>
<path d="M179.2 79.5v.3M180.4 73.7v2.4M180.4 78.5v2.4M180.4 73.7l-.7 1.2M180.4 73.7l.7 1.2M195.9 70.1v5M195.9 77v3.9M195.9 70.1l-.7 1.2M195.9 70.1l.8 1.2M206.7 74.9v2.4M206.7 79.7v1.2M206.7 74.9l-.7 1.2"/>
<path d="M206.7 74.9l.7 1.2M268.1 65.6h1.9M10 88.4h.4l.3 .2-.3 .3 .3 .2v.3l-.2 .2h-.5zM10 88.9h.4M53.8 100h4.7M53.8 95.2h4.7M53.8 90.4h4.7M53.8 85.6h4.7M53.8 80.9h4.7M84.8 100h4.8M84.8 95.2h4.8M84.8 90.4h4.8"/>
<path d="M84.8 85.6h4.8M84.8 80.9h4.8M157.1 82h4.3l1.1 1.2-1.1 1.2h-4.3zM157.6 84.4v2.4h3.8l1.1-1.2-1.1-1.2M158.7 83h-.3l-.2 .1 .1 .2 .4 .1v.3h-.5M159.2 85.4h-.3l-.1 .1v.2l.4 .1v.3h-.4M159.8 83h-.4l-.2 .2 .1 .5h.5M159.8 82.6v1.2M160.3 85.4h-.4l-.2 .2 .1 .5h.5M160.3 83h.5l.1 .8M160.8 85v1l.2 .2M160.9 83.3l-.6 .2 .2 .3 .4-.1"/>
<path d="M170.8 95.2h2.4M170.8 85.6h2.4M170.8 83.2h2.4M170.8 97.6h2.4M170.8 92.8h2.4M171.6 91.1h.8l-.5 1.2M171.7 82.7h.7M171.7 81.9l.3-.3v1.1M171.7 84.1l.5-.2 .2 .4-.8 .8h.8M172.3 93.5l-.4 .1-.1 .2-.1 .7 .2 .2 .4-.1v-.6h-.4l-.2 .2M172.3 95.9h-.5l-.1 .6 .6-.1v.6l-.1 .1-.5-.1M180.4 100v2.4"/>
<path d="M182.8 100v2.4M187.6 90.4h2.4M188.4 88.7h.7l-.4 .5 .4 .1v.5l-.2 .1-.5-.1M194.7 80.9h2.4l-1.2 1.2zM206.7 85.6v1.2M268.7 88.4h.4l.3 .2-.3 .3 .3 .2v.3l-.2 .2h-.5zM268.7 88.9h.4M9.4 112.7h1.9M25.1 116.7h2.4l-1.2 1.2zM26.3 105.9v5.1M26.3 112.9v3.8M26.3 105.9l-.7 1.2"/>
<path d="M26.3 105.9l.7 1.2M35.8 116.7h2.4l-1.2 1.2zM37 105.9l-.7 1.2M37 105.9v5.1M37 112.9v3.8M37 105.9l.8 1.2M50.2 113.1h2.4l-1.2 1.2zM51.4 102.4l-.7 1.2M51.4 102.4v2.4M51.4 111.9v1.2M51.4 102.4l.7 1.2M53.8 104.8h4.7"/>
<path d="M53.8 109.5h4.7M84.8 104.8h4.8M84.8 109.5h4.8M90.8 113.1h2.4l-1.2 1.2zM92 111.9v1.2M130.5 115.7h1.9a.96 .96 0 0 1-1 1 .96 .96 0 0 1-.9-1zM130.7 114.6a.96 .96 0 0 1 1.1-.2 .96 .96 0 0 1 .6 .9h-1.9zM131.4 108.3l-.7 1.2M131.4 108.3v2.4M131.4 111.9v2.4M131.4 116.7v2.4M131.4 108.3l.7 1.2"/>
<path d="M132.8 112.8v.7l-.9-.7-.3 .2 .1 .5M132.8 117.6v.6M132.8 117.9h-1.2l.3 .3M142.4 115.7h1.9a.96 .96 0 0 1-.9 1 .96 .96 0 0 1-1-1zM142.7 114.6a.96 .96 0 0 1 1-.2 .96 .96 0 0 1 .6 .9h-1.9zM143.4 108.3v2.4M143.4 111.9v2.4M143.4 116.7v2.4M143.4 108.3l-.7 1.2M143.4 108.3l.7 1.2M144.7 117.9h-1.1l.3 .3M144.7 112.8v.7l-.8-.7-.3 .2 .1 .5"/>
<path d="M144.7 117.6v.6M154.4 115.7h1.9a.96 .96 0 0 1-1 1 .96 .96 0 0 1-.9-1zM154.6 114.6a.96 .96 0 0 1 1.1-.2 .96 .96 0 0 1 .6 .9h-1.9zM155.3 108.3l-.7 1.2M155.3 108.3v2.4M155.3 111.9v2.4M155.3 116.7v2.4M155.3 108.3l.7 1.2M156.7 117.9h-1.2l.3 .3M156.7 112.8v.7l-.9-.7-.3 .2 .1 .5M156.7 117.6v.6M179.1 100.9h.8"/>
<path d="M179.2 108.3h2.4l-1.2 1.2zM179.5 100.8v.7l-.8-.3M180.4 107.1v1.2M181.6 100.8l.2 .3v.3l-.6 .1-.1-.4 .2-.3 .7 .1 .2 .2 .1 .3M268.1 112.7h1.9M10.7 135.5a.54 .54 0 0 0-.7 .5 .54 .54 0 0 0 .7 .5M130.2 133.4h2.4l-1.2 1.2zM131.4 123.9v1.2M131.4 129.8v1.2M131.4 132.2v1.2M142.2 133.4h2.4l-1.2 1.2zM143.4 123.9v1.2"/>
<path d="M143.4 129.8v1.2M143.4 132.2v1.2M154.1 133.4h2.4l-1.2 1.2zM155.3 123.9v1.2M155.3 129.8v1.2M155.3 132.2v1.2M269.4 135.5a.54 .54 0 0 0-.7 .5 .54 .54 0 0 0 .7 .5M9.4 159.7h1.9M268.1 159.7h1.9M166.5 179.9h101.6M268.1 165.3h-101.6v30.1M10 182.4a.62 .62 0 0 1 .7 .6 .62 .62 0 0 1-.7 .7z"/>
<path d="M33.2 196l.3-.4v1.2M33.2 196.8h.7M56.4 195.4v1.9M80.2 195.7l.5-.1 .2 .4-.8 .8h.8M103.5 195.4v1.9M127.2 195.6h.7l-.4 .5 .4 .1v.5l-.2 .1-.5-.1M150.5 195.4v1.9M166.5 192.2h101.6M166.5 189.3h101.6M166.5 185.6h101.6M167.8 183.7h.5M167.8 192.6v1.4"/>
<path d="M168 193.2l.6 .8M168.5 183h-.7v1.4M168.5 190l-.5-.1-.2 .2v.4l.6 .2 .1 .4-.2 .3-.6-.1M168.5 180.5l-.5-.1-.2 .2v.4l.6 .2 .1 .4-.2 .3-.6-.1M168.6 192.6l-.8 .8M169 183v.1M169 183.5v.9M169.1 180.4v1.5M169.1 189.9v.2M169.1 190.4v1M169.1 181l.2-.1 .4 .1v.9M169.2 192.6v.1"/>
<path d="M169.2 193v1M169.7 190.4h.7l-.7 1h.7M169.7 183v1.2l.2 .2M170.3 183.9l.7-.1-.1-.3h-.4l-.2 .2 .1 .6h.5M170.3 181.4l.7-.2-.1-.2-.4-.1-.2 .2 .1 .7h.5M170.7 192.7a.67 .67 0 0 0-1 .5 .67 .67 0 0 0 .7 .8l.3-.1M170.9 190.9l.7-.2-.1-.2-.4-.1-.2 .2v.7h.6M171.3 193.1h.5l.1 .9M171.6 181.4l.6-.2v-.2l-.4-.1-.2 .2v.7h.6M171.6 184.3v.1M171.6 183.5v.2M171.9 193.4h-.5l-.2 .3 .2 .3 .5-.1"/>
<path d="M172.2 190.5v.1M172.2 191.2v.2M172.6 180.9h.6M172.8 180.4v1.2l.4 .3M173.1 183.6l.4-.1 .2 .2M173.1 183.5v.9M173.2 193.1l-.4-.1-.3 .3 .1 .6h.6M173.2 192.6v1.4M173.5 191.4l.4-1.5 .5 1.5M173.6 190.9h.7M173.6 181.7v.2M173.6 181v.1"/>
<path d="M173.7 183.7l.2-.2h.4v.9M173.7 183.7v.7M174.6 195.6l-.3 .8h.7M174.7 193.2h.5M174.9 196v.8M175 183v.1M175 183.5v.9M175.2 189.9l-.4 1h.9M175.4 192.6h-.7v1.4h.7M175.5 190.4v1M175.7 183v1.4M175.8 183.9l.4 .5"/>
<path d="M176 193.9v.1M176.2 183.5l-.5 .5M176.6 192.6a.71 .71 0 0 1 .8 .7 .71 .71 0 0 1-.8 .7zM176.8 183.5v.9M177.2 183.5l-.4 .2M177.7 183.6l.2-.1 .4 .1 .1 .5-.2 .2-.3 .1-.2-.1zM178 193.9v.1M178.5 194l.5-1.4 .5 1.4M178.6 193.6h.7M179 183.5h.4l.3 .2-.2 .6h-.5M179 183v1.4M179.9 193.9v.1"/>
<path d="M180.3 183.5v.8l.4 .1 .2-.1M180.9 183.5v.9M182 183.5h-.3l-.2 .2v.2l.5 .1v.3h-.5M182.3 192.6v1.4M182.4 193.4l.4 .6M182.7 184.3v.1M182.8 193l-.5 .6M183.4 183v1.4M183.4 192.6v.1M183.4 193v1M183.5 183.9l.4 .5M183.9 183.5l-.5 .5"/>
<path d="M184.5 183v.1M184.5 183.5v.9M184.7 193.1l-.4-.1-.3 .3 .2 .6h.5M185.3 193.1h.6v.9M185.3 189.3v2.9M185.8 183.5h-.4l-.3 .2 .1 .6h.6M185.9 193.4h-.5l-.2 .3 .2 .3 .5-.1M186.4 183.5h.5l.1 .9M187 183.8l-.5 .1-.2 .2 .2 .3 .5-.1M187.2 193.1l-.4-.1-.3 .3 .2 .6h.5M187.2 192.6v1.4M188.3 183.5h-.4l-.3 .2 .1 .6h.6"/>
<path d="M188.3 183v1.4M188.5 189.9a.71 .71 0 0 1 .8 .7 .71 .71 0 0 1-.8 .8zM188.6 184.5h1.1M189.1 192.4a1.62 1.62 0 0 0 0 2.1M189.5 192.6h1l-.6 1.4M189.9 190.5h.5l.1 .9M190.5 183.5h-.4l-.2 .2 .1 .2 .5 .1v.3h-.6M190.5 190.7l-.5 .1-.2 .2 .2 .4 .5-.1M191 190.4h.5M191 193.9v.1M191.2 189.9v1.3l.3 .2M191.7 192.7l.2-.1a.75 .75 0 0 1 .5 .7 .75 .75 0 0 1-.5 .7l-.3-.6z"/>
<path d="M191.8 183.5h-.5l-.2 .2 .1 .6h.6M191.9 190.9l.7-.2-.1-.2-.4-.1-.2 .2 .1 .7h.5M192.4 183.6l.2-.1h.3l.1 .9M192.4 183v1.4M193 193.9v.1M193.2 191.2v.2M193.2 190.5v.1M193.8 192.7l.2-.1a.75 .75 0 0 1 .4 .7 .75 .75 0 0 1-.4 .7l-.4-.6zM195 193.4h1.1M196.8 192.7l.2-.1a.75 .75 0 0 1 .5 .7 .75 .75 0 0 1-.5 .7l-.3-.6zM197.6 195.4v1.9M198 192.4a1.62 1.62 0 0 1 0 2.1"/>
<path d="M221.9 195.6h-.5l-.1 .6 .6-.1v.6l-.1 .1-.5-.1M244.6 195.4v1.9M245.5 189.3v6.1M247.8 192.6v1.4M249 193.1l-.4-.1-.2 .3 .1 .6h.5M249 192.6v1.4M249.7 193.9v.1M249.7 193.1v.1M251.9 192.6h-.7v.6l.2-.1 .4 .1 .2 .2-.1 .5-.2 .1-.5-.1M253.6 192.5l-1.2 1.8M254.6 192.6h-.4a.95 .95 0 0 0 0 1.4l.5-.1 .1-.5-.3-.3-.4 .1-.1 .2M268.7 182.4a.62 .62 0 0 1 .7 .6 .62 .62 0 0 1-.7 .7z"/>
<path d="M268.9 195.6l-.3 .1-.2 .2-.1 .7 .3 .2 .4-.1-.1-.6h-.3l-.3 .2"/>
</g>
<path d="M247.8 190.7l.6-.1 .2-.2-.1-.3-.7-.2v1.5M248.1 190.7l.5 .7M249.1 190.9l.7-.2-.1-.2-.4-.1-.2 .2 .1 .7h.5M250.2 190.4l.4 1 .3-1M251.4 191.2v.2M251.4 190.5v.1" fill="none" stroke="#840000" stroke-width=".28"/>
<path d="M167.9 186.1h1.1M168.4 186.1l-.2 1.9M169.5 186.7l-.2 1.3M169.6 186.1v.1M170.1 186.7h.7M170.5 186.1l-.2 1.6v.2l.4 .1M171.6 186.1l-.2 1.6 .2 .3M172.3 187.3l.9-.2v-.3h-.8l-.2 .9 .3 .3 .5-.1M173.9 187.8v.2M174.1 186.8l-.1 .2" fill="none" stroke="#840000" stroke-width=".38"/>
<path d="M173.2 80.9h14.4v19.1h-14.4z" fill-rule="evenodd" fill="#ffffc2" stroke="#ffffc2" stroke-width=".35"/>
<path d="M58.5 73.7h26.3v35.8l-2.4 2.4h-23.9zM173.2 80.9h14.4v19.1h-14.4zM205.7 80.9h1.9v4.7h-1.9zM130.5 125.1h1.9v4.7h-1.9zM142.4 125.1h1.9v4.7h-1.9zM154.4 125.1h1.9v4.7h-1.9z" fill="none" stroke="#840000" stroke-width=".24"/>
<path d="M89 104.2l1.2 1.1M90.2 104.2l-1.2 1.1" fill="none" stroke="#000084" stroke-width=".2"/>
<g fill="none" stroke="#008400" stroke-width=".2">
<path d="M41.8 76.1h12M89.6 76.1h10.8M180.4 76.1v2.4M206.7 77.3v2.4M41.8 90.4h12M41.8 95.2h12M41.8 100h12M41.8 85.6h12M41.8 80.9h12M89.6 90.4h10.8M89.6 95.2h15.5M89.6 100h15.5"/>
<path d="M89.6 85.6h10.8M89.6 80.9h10.8M162.5 83.2h8.3M162.5 85.6h8.3M170.8 97.6h-33.4v23.9h-6M170.8 95.2h-21.5v26.3h-5.9M170.8 92.8h-9.5v28.7h-6M190 90.4h21.5M206.7 86.8v3.6M51.4 104.8h2.4M53.8 109.5h-2.4v2.4M89.6 109.5h2.4v2.4"/>
<path d="M131.4 110.7v1.2M131.4 119.1v4.8M143.4 110.7v1.2M143.4 119.1v4.8M155.3 110.7v1.2M155.3 119.1v4.8M180.4 102.4v4.7M182.8 102.4v2.4h-2.4M131.4 131v1.2M143.4 131v1.2M155.3 131v1.2"/>
</g>
<g fill="none" stroke="#0000c2" stroke-width=".2">
<path d="M136.1 139a.53 .53 0 0 0-.7 .4 .53 .53 0 0 0 .7 .5M136.7 139.5l.5-.1 .1-.4-.6-.1v1.1M138.5 139.4l-.3 .2-.3-.1v-.5l.3-.1 .3 .2-.1 .7-.2 .2h-.3M139.2 139.4l-.3 .2 .1 .3 .2 .1h.2l.2-.2v-.3l-.2-.1M139.2 139.4l-.3-.3 .3-.2h.2l.2 .2-.2 .3M139.2 139.4h.2M140.2 139l.2-.1a.64 .64 0 0 1 .4 .5 .64 .64 0 0 1-.4 .6l-.3-.4zM141.4 139.4l-.2 .2 .1 .3 .1 .1h.3l.2-.2-.1-.3-.1-.1M141.4 139.4l-.2-.3 .2-.2h.3l.2 .2-.2 .3M141.4 139.4h.3M143.1 138.9v1.1M143.6 139l.5-.1 .2 .3-.7 .8h.7"/>
<path d="M145.5 139a.53 .53 0 0 0-.7 .4 .53 .53 0 0 0 .7 .5M146.7 139.7h.5M148.3 139.3l-.4-.1-.2 .3 .1 .5h.5M148.3 138.9v1.1M149.4 139.3l-.4-.1-.2 .3 .1 .5h.5M149.4 138.9v1.1M149.9 139.2v.8M150.3 139.2l-.4 .3M150.6 139.6l.6-.1-.1-.2-.3-.1-.2 .2 .1 .6h.4M152.1 139.3l-.3-.1-.2 .2 .1 .2 .4 .1v.3h-.5M153.1 139.3l-.3-.1-.2 .2 .1 .2 .4 .1v.3h-.5M134.1 140v-1.1l.4 .8 .4-.8v1.1"/>
<path d="M134.1 142.7a.6 .6 0 0 1 .7 .6 .6 .6 0 0 1-.7 .6zM135.2 143.5l.6-.1-.1-.2-.3-.1-.2 .2 .1 .6h.4M136.1 143.1h.5M136.6 142.7l-.3 .2v1M137 143.2h.5v.7M137.5 143.4l-.6 .2 .2 .3h.4M138.1 143.1v.8l.5-.1M138.6 143.1v.8M139.2 142.7v1l.1 .2M139.6 143.1h.5M139.8 142.7v1l.3 .2M139.9 140.9l.2-.1a.64 .64 0 0 1 .4 .6 .64 .64 0 0 1-.4 .6l-.3-.5z"/>
<path d="M141 140.9l.2-.1a.64 .64 0 0 1 .4 .6 .64 .64 0 0 1-.4 .6l-.3-.5zM141.2 142.8l.2-.1a.64 .64 0 0 1 .4 .6 .64 .64 0 0 1-.4 .6l-.3-.4zM142 142h.7M142 141.1l.4-.3v1.2M142.4 142.8l.2-.1a.64 .64 0 0 1 .4 .6 .64 .64 0 0 1-.4 .6l-.3-.4zM143.2 142h.7M143.2 141.1l.3-.3v1.2M143.4 143.9h.7M143.4 143.1l.3-.4v1.2M144.5 143.9h.7M144.5 143.1l.4-.4v1.2M144.9 142l.4-1.2 .4 1.2"/>
<path d="M145 141.6h.6M146.1 140.9l.4-.1 .2 .3-.7 .9h.7M146.6 140l.4-1.1 .4 1.1M147.2 142.8l.2-.1a.64 .64 0 0 1 .4 .6 .64 .64 0 0 1-.4 .6l-.3-.4zM147.8 142l.4-1.2 .4 1.2M147.9 141.6h.6M148.9 142h.7M148.9 141.1l.4-.3v1.2M149.8 142.8l.2-.1a.64 .64 0 0 1 .4 .6 .64 .64 0 0 1-.4 .6l-.3-.4zM150.7 142l.4-1.2 .4 1.2M150.8 141.6h.6M151.9 140.9l.2-.1a.64 .64 0 0 1 .4 .6 .64 .64 0 0 1-.4 .6l-.3-.5z"/>
<path d="M152.4 142.8l.1-.1a.64 .64 0 0 1 .5 .6 .64 .64 0 0 1-.5 .6l-.2-.4zM169.8 170.7l.2 .6M169.9 177.4l.4-.1-.1-.5h-.3v.9M169.9 172.3h.3l.1 .6M169.9 171.9v1M169.9 173.4v1M169.9 173.8h.3l.1 .6M170 171.3l-.2 .3M170.2 170.7l-.2 .6M170.4 169a.42 .42 0 0 0-.6 .3 .42 .42 0 0 0 .6 .4M170.4 175a.42 .42 0 0 0-.6 .4 .42 .42 0 0 0 .6 .4M170.6 170.8h.4v.5l-.4-.1z"/>
<path d="M170.6 172.2h.4M170.7 177.1l.4-.1v-.2h-.3l-.1 .1v.5h.4M170.7 171.9v.8l.3 .2M170.7 173.8h.4v.6M170.8 169.3h.4v.5l-.4-.1zM170.8 175.1l.2-.1 .4 .1v.5l-.1 .3-.5-.1zM171.1 172.2h.4M171.1 174l-.4 .2 .1 .2 .3-.1M171.3 171.9v.8l.2 .2M171.4 170.7l.1 .6 .3-.1M171.5 176.8v.6M171.6 173.7v.7"/>
<path d="M171.7 169.2h.2l.2 .2-.1 .4h-.3M171.7 169.2v.9M171.8 172.3l.3-.1 .2 .2-.1 .4h-.4M171.8 172.2v1M171.8 176.8l-.3 .2M171.8 170.7v.6M171.8 173.7l-.2 .2M172.1 176.8v.6M172.1 176.9l.3-.1 .1 .1M172.3 175v.9l-.5-.9v.9M172.4 169.2l.3 .6M172.5 176.9l.4-.1v.6"/>
<path d="M172.5 176.9v.5M172.6 173.8l-.3-.1-.2 .2 .1 .4h.4M172.6 173.4v1M172.7 172.9h.1M172.7 172.3v.1M172.7 169.8l-.3 .3M172.7 172.8v.1M172.8 175a.48 .48 0 0 1 .5 .4 .48 .48 0 0 1-.5 .5zM172.9 170.8l.2-.1 .2 .1M172.9 170.7v.6M172.9 169.2l-.2 .6M172.9 173.7l.2 .7 .2-.5 .2 .5 .1-.7"/>
<path d="M173.2 169.2v.6M173.3 170.8l.3-.1 .1 .6M173.3 170.8v.5M173.4 176.5v.1M173.4 176.8v.6M173.5 169.2l-.3 .2M173.7 175v.9M173.8 171.9l-.8 1.2M173.8 168.9v.1M173.8 169.2v.6M174 173.8h.4v.6M174 175h.6"/>
<path d="M174.1 170.7h.4v.6M174.1 176.8h-.2l-.1 .2 .4 .2M174.2 177.3l-.2 .1h-.2M174.2 177.2v.1M174.3 175v.9M174.4 174l-.4 .2 .1 .2 .3-.1M174.5 170.9l-.4 .2 .1 .2h.3M174.7 169.2h-.3l-.2 .2 .1 .4h.4M174.7 169.2v.7l-.2 .2h-.2M174.8 171.9l-.8 1.2M174.9 173.7v.7M174.9 170.7l.2 .6"/>
<path d="M174.9 176.8h-.2l-.2 .2 .4 .2M174.9 175v.9M174.9 177.3l-.1 .1h-.3M174.9 177.2v.1M175 172.4l.4 .3-.1 .2-.3-.1M175 172.4h.1M175.1 171.3l-.2 .3M175.1 169.3l.4-.1v.6M175.1 168.9v.9M175.1 173.7l-.2 .2M175.3 170.7l-.2 .6M175.3 176.5v.1"/>
<path d="M175.3 176.8v.6M175.3 175.1l.2-.1 .4 .1v.5l-.1 .3-.5-.1zM175.4 174.1l.4-.1v-.2l-.3-.1-.1 .2v.4h.4M175.4 172.3l-.4 .1M175.8 176.9h.4l-.1 .5-.3-.1zM175.8 172.3h.4v.5h-.4zM175.8 169.2h.4M176 168.9v.8l.2 .1M176.2 170.8l.4-.1 .1 .6M176.2 170.7v.6M176.6 176.9l.4-.1v.6M176.6 176.8v.6"/>
<path d="M176.7 171.9v.8l.1 .2M176.8 173.8h.4v.6M176.9 175v.9l-.6-.9v.9M177.1 169.2h.3l.1 .6M177.1 170.8h.4v.5l-.4-.1zM177.2 174l-.4 .2 .1 .2 .3-.1M177.5 169.4l-.5 .2 .2 .2h.3M177.6 171.9v.9h-.4v-.5h.4M177.7 173.8h.3l.1 .6M177.7 173.7v.7M177.8 175h-.5a.39 .39 0 0 0 .5 .5l-.1 .4h-.4M177.8 176.8h-.2l-.2 .2 .5 .2"/>
<path d="M177.8 170.7h.4M177.9 177.3l-.2 .1h-.3M177.9 177.2v.1M177.9 169.3l.4-.1v.6M177.9 169.2v.6M178 170.4v.8l.2 .1M178 172.5l.4-.1v-.1l-.3-.1-.1 .2v.4h.4M178.8 175.1l.2-.1 .3 .1 .1 .5-.2 .3-.4-.1zM178.8 176.8h.4v.6M178.8 172.2v.7M178.9 173.8l-.3-.1-.1 .2 .1 .4h.3M178.9 173.4v1"/>
<path d="M179.1 170.7v.6l.4-.1M179.1 172.2l-.3 .2M179.2 169.2h-.3l-.2 .2 .1 .4h.4M179.2 168.9v.9M179.2 177l-.4 .2 .1 .2h.3M179.4 172.3l.3-.1 .2 .2-.1 .4h-.4M179.4 172.2v1M179.5 170.7v.6M179.7 176.9l.3-.1 .1 .6M179.7 176.8v.6M179.8 175.4h.3M179.9 173.8l.3-.1 .1 .2"/>
<path d="M179.9 173.7v.7M180.2 169.2v.6M180.2 175h-.4v.9M180.2 170.7l-.3 .1 .3 .3v.2h-.3M180.3 172.3l.2-.1 .2 .2v.4l-.3 .1-.1-.4 .4-.1M180.3 173.9l.4-.1v.6M180.3 173.9v.5M180.5 169.2l-.3 .2M180.6 171l.5-.1-.1-.2h-.2l-.2 .1 .1 .5h.3M180.7 169.5l.5-.1-.1-.2h-.2l-.2 .1 .1 .5h.3M180.9 176.8h-.2l-.2 .2 .1 .4h.3M180.9 176.5v.9"/>
<path d="M181 175.9l.3-.9 .3 .9M181.1 175.6h.4M181.2 173.8h.3l.1 .6M181.5 171.9v.9h-.3l-.1-.5h.4M181.6 168.9v.8l.1 .1M181.6 174l-.5 .2 .2 .2 .3-.1M181.9 173.7h.4M181.9 170.7h.4M181.9 176.5v.8l.2 .1M182 172.8v.1M182 173.4v.8l.3 .2M182 170.4v.8l.3 .1"/>
<path d="M182.1 169.2h.3l.1 .6M182.4 172.3h.4v.5h-.4zM182.4 176.5v.1M182.4 176.8v.6M182.5 175v.9l-.6-.9v.9M182.5 169.4l-.5 .2 .2 .2h.3M182.5 174.1l.5-.1-.1-.2-.2-.1-.2 .2 .1 .4h.3M182.6 170.8l.3-.1 .1 .6M182.6 170.4v.9M182.8 175l.3 .5M182.8 169.2h.3M182.9 176.9l.2-.1 .2 .1"/>
<path d="M182.9 176.8v.6M182.9 168.9v.8l.2 .1M183.1 175.5v.4M183.3 172.2v.7M183.3 176.9v.5M183.3 176.9l.3-.1 .1 .6M183.4 173.7v.7M183.4 175l-.3 .5M183.4 169.5l.5-.1-.1-.2h-.3l-.1 .1 .1 .5h.3M183.4 170.4v.1M183.4 170.7v.6M183.5 172.2l-.2 .2"/>
<path d="M183.6 173.7l-.2 .2M184 173.4v.1M184 173.7v.7M184.1 176.5v.1M184.1 176.8v.6M184.2 170.7l-.4 .1 .4 .3v.2h-.4M184.3 172.2v.8l-.2 .2-.2-.1M184.3 172.3l-.3-.1-.2 .2 .1 .4h.4M184.3 175v.9M184.4 173.8h.4v.6M184.4 175.4l.4 .5M184.4 176.8h.4"/>
<path d="M184.6 176.5v.8l.2 .1M184.7 169.2h-.3l-.2 .2 .1 .4h.4M184.7 168.9v.9M184.8 174l-.4 .2 .1 .2 .3-.1M184.8 175l-.5 .5M185.1 170.7h.3M185.1 176.8h.4v.6M185.2 175v.9M185.3 173.4v.8l.1 .2M185.4 171.9l-.8 1.2M185.4 170.4l-.2 .1v.8M185.5 177l-.4 .2 .1 .2h.3"/>
<path d="M185.7 169.2v.6M185.7 171.9v.8l.1 .2M185.7 170.4v.1M185.7 170.7v.6M185.8 176.8h.4M186 169.2l-.3 .2M186 176.5v.8l.2 .1M186.1 173.8l-.4 .1 .4 .2v.2h-.4M186.2 170.4v.8l.1 .1M186.2 171.9v.1M186.2 172.2v.7M186.2 175v.9l-.5-.9v.9"/>
<path d="M186.3 168.9v.1M186.3 169.2v.6M186.5 176.5v.1M186.5 176.8v.6M186.6 171l.5-.1-.1-.2h-.2l-.2 .1 .1 .5h.3M186.7 175a.48 .48 0 0 1 .5 .4 .48 .48 0 0 1-.5 .5zM187 176.9h.4l-.1 .5-.3-.1zM187 172.3l-.2-.1-.2 .2 .1 .4h.3M187.1 169.2h-.3l-.1 .2 .1 .4h.3M187.1 169.2v.7l-.2 .2h-.2M187.4 172.5l.4-.1v-.1l-.3-.1-.1 .2v.4h.4M187.5 173.8l-.3-.1-.2 .2 .1 .4h.4"/>
<path d="M187.5 173.4v1M187.6 169.3l.3-.1 .1 .6M187.6 168.9v.9M187.7 175.9l-.1 .1M187.8 176.9l.4-.1v.6M187.8 176.8v.6M187.9 173.4v.1M187.9 173.7v.7M188 171l.5-.1-.1-.2h-.3l-.1 .1v.5h.4M188.2 172.3h.4v.6M188.2 172.2v.7M188.3 169.2h.3"/>
<path d="M188.4 168.9v.8l.2 .1M188.6 175.6l.4-.1v-.2h-.3l-.1 .1v.5h.4M188.7 173.8l-.4 .1 .4 .2v.2h-.4M188.8 170.7l.5 .6M189 176.8h-.3l-.1 .2 .4 .2M189 173.7h.4M189 177.3l-.1 .1h-.3M189 177.2v.1M189.1 172.4l.4 .3-.2 .2-.2-.1M189.1 172.4h.1M189.1 173.4v.8l.3 .2M189.3 170.7l-.5 .6"/>
<path d="M189.3 169.2l-.4 .1 .4 .2v.3h-.4M189.4 172.3l-.3 .1M189.4 175h.1M189.4 175.3v.6M189.7 173.7v.7M189.7 175.3h.4M189.8 172.5l.5-.1-.1-.1-.3-.1-.1 .2 .1 .4h.3M189.9 175v.8l.2 .1M189.9 173.7l-.2 .2M190 176.8v.6l.4-.1M190 170.7h-.3l-.1 .2 .1 .4h.3M190.3 173.4v.1"/>
<path d="M190.3 173.7v.7M190.3 169.2h.3l.1 .6M190.4 171l.4-.1v-.2h-.3l-.1 .1v.5h.4M190.4 176.8v.6M190.4 175.4l.4-.1v.6M190.4 175v.9M190.6 172.4l.4 .3-.1 .2-.3-.1M190.6 172.4h.1M190.7 169.4l-.5 .2 .2 .2h.3M190.7 173.8l.3-.1 .1 .2v.4h-.4M190.7 173.4v1M190.8 176.8v.6"/>
<path d="M190.8 176.9l.4-.1v.6M191 172.3l-.4 .1M191.1 169.2v.6M191.2 175.6l.5-.1-.1-.2h-.2l-.2 .1 .1 .5h.3M191.2 170.7h.3l.2 .2-.1 .4h-.4M191.2 170.7v.9M191.4 169.2l-.3 .2M191.6 173.7v.6h.4M191.7 169.5l.4-.1v-.2h-.3l-.1 .1v.5h.4M191.9 170.7h.4M192 173.7v.7M192.1 175.3v.6"/>
<path d="M192.1 170.4v.8l.2 .1M192.1 176.8h-.3l-.2 .2 .1 .4h.4M192.1 176.5v.9M192.1 171.9l-.8 1.2M192.3 173.7h.3M192.3 175.3l-.2 .2M192.4 173.4v.8l.2 .2M192.5 177.1l.4-.1v-.2h-.3l-.1 .1v.5h.4M192.9 174.1l.4-.1v-.2l-.3-.1-.1 .2v.4h.4M192.9 172h-.5a.39 .39 0 0 0 .5 .5l-.1 .3h-.4M193.1 168.9v.8l.1 .1M193.2 175.6l.4-.1v-.2h-.3l-.1 .1v.5h.4"/>
<path d="M193.2 170.4v.1M193.2 170.7v.6M193.3 171.9v1M193.3 172.4h.5M193.3 176.8v.6M193.6 168.9v.1M193.6 169.2v.6M193.6 176.8l-.3 .2M193.6 170.8l.4-.1v.6M193.6 170.7v.6M193.8 171.9v1M193.9 175.3l.5 .6"/>
<path d="M194.1 173.8l-.2-.1-.2 .2 .1 .4h.3M194.1 173.4v1M194.3 171.9v1h.4M194.4 176.8h.3M194.4 175.3l-.5 .6M194.4 169.2h-.2l-.2 .2 .1 .4h.3M194.5 176.5v.8l.2 .1M194.8 175.3v.9M194.8 175.3h.3l.1 .2-.1 .4h-.3M194.8 169.5l.4-.1v-.2h-.3l-.1 .1v.5h.4M195 176.9l.4-.1v.6M195 176.5v.9"/>
<path d="M195.1 172.5h.7M195.2 173.7v.6h.4M195.4 170.7h-.2l-.2 .2 .1 .4h.3M195.6 173.7v.7M195.6 175.3v.6M195.6 169.3l.4-.1v.6M195.6 169.2v.6M195.8 177.1l.5-.1-.1-.2h-.2l-.2 .1 .1 .5h.3M195.9 170.8h.4l-.1 .5-.3-.1zM195.9 175.3l-.3 .2M196 173.7v.7M196 173.8h.4v.6"/>
<path d="M196.2 175.6l.4-.1v-.2h-.3l-.1 .1v.5h.4M196.2 172l.3-.1 .2 .3-.6 .7h.6M196.7 170.8l.3-.1 .1 .1M196.7 170.7v.6M196.8 169.2l-.4 .1 .4 .2v.3h-.4M197.1 170.8l.4-.1v.6M197.1 170.8v.5M197.1 172.8v.1M197.2 169.5l.5-.1-.1-.2h-.3l-.1 .1v.5h.4M197.2 176.5v.9h.5M197.3 173.8l-.3-.1-.2 .2 .1 .4h.4M197.3 173.4v1"/>
<path d="M197.3 175.3l-.3 .1 .3 .2v.3h-.3M197.5 172.9h.6M197.5 172.2l.3-.3v1M197.7 174.1l.4-.1v-.2l-.3-.1-.1 .2v.4h.4M198 170.7h.2l.2 .2-.1 .4h-.3M198 170.7v.9M198 176.5v.1M198 176.8v.6M198.1 175.3l-.4 .1 .4 .2v.3h-.4M198.5 169.2h-.3l-.2 .2 .1 .4h.4M198.5 168.9v.9M198.5 172.8v.1"/>
<path d="M198.5 173.7v.7M198.8 173.7l-.3 .2M198.8 170.4v.8l.1 .1M198.9 176.8h-.3l-.2 .2 .1 .4h.4M199.1 175.4h.4v.5l-.4-.1zM199.2 177.1l.5-.1-.1-.2h-.2l-.2 .1 .1 .5h.3M199.3 170.4v.1M199.3 170.7v.6M199.5 169.2v.6l.4-.1M199.5 171.9v.8l.1 .2 .4-.2v-.8M199.5 173.7h.4M199.7 173.4v.8l.2 .2"/>
<path d="M199.7 170.7h.4l.1 .6M199.9 169.2v.6M200 175.3v.6M200.1 176.9l.3-.1 .1 .6M200.1 176.8v.6M200.2 170.9l-.5 .2 .1 .2h.4M200.2 173.8h.4v.6M200.2 173.4v1M200.2 175.3l-.2 .2M200.3 169.3l.4-.1v.6M200.3 169.2v.6M200.5 172.3h.3l.1 .6"/>
<path d="M200.5 172.2v.7M200.6 170.8l.4-.1v.6M200.6 170.7v.6M201.1 173.4v.1M201.1 173.7v.7M201.1 175h.1M201.1 175.3v.6M201.2 176.8h-.2l-.1 .2 .4 .2M201.3 177.3l-.2 .1h-.2M201.3 177.2v.1M201.3 171.9v.8l.1 .2M201.6 175.3v.6"/>
<path d="M201.6 175.4l.2-.1 .2 .1M201.6 169.2h-.3l-.2 .2 .1 .4h.4M201.6 168.9v.9M201.6 177.1l.5-.1-.1-.2h-.2l-.2 .1 .1 .5h.3M201.8 172.5l.4-.1v-.1l-.3-.1-.1 .2v.4h.4M201.8 173.8l-.3 .1 .3 .2v.2h-.3M201.9 170.7h-.3l-.2 .2 .1 .4h.4M202 175.4v.5M202 175.4l.3-.1 .1 .6M202 169.5l.4-.1v-.2h-.3l-.1 .1v.5h.4M202.2 171l.5-.1-.1-.2h-.3l-.1 .1 .1 .5h.3M202.5 177.3v.1"/>
<path d="M202.6 172.4l.4 .3-.2 .2-.2-.1M202.6 172.4h.1M202.8 175.3h.3l.2 .2-.1 .4h-.4M202.8 175.3v.9M202.8 169.2v.6M202.8 173.4v1h.5M202.9 172.3l-.3 .1M203.1 169.2l-.3 .2M203.3 172.4l.4 .3-.1 .2-.3-.1M203.3 172.4h.1M203.5 170.7l.2 .6 .2-.4 .2 .4 .2-.6M203.6 173.4v.1"/>
<path d="M203.6 173.7v.7M203.7 175v.8l.1 .1M203.7 172.3l-.4 .1M203.8 169.2h.4M204 168.9v.8l.2 .1M204.2 175h.1M204.2 175.3v.6M204.4 173.8l-.2-.1-.2 .2 .1 .4h.3M204.5 169.3l.4-.1v.6M204.5 168.9v.9M204.6 175.6l.4-.1v-.2h-.3l-.1 .1v.5h.4M204.6 170.4v.1"/>
<path d="M204.6 170.7v.6M204.7 172.2v.7M204.8 174.1l.4-.1v-.2l-.3-.1-.1 .2v.4h.4M204.9 170.7h.4M205 172.2l-.3 .2M205.1 170.4v.8l.2 .1M205.2 172.5l.5-.1-.1-.1-.2-.1-.2 .2 .1 .4h.3M205.3 169.5l.5-.1-.1-.2h-.2l-.2 .1 .1 .5h.3M205.6 170.8l.4-.1v.6M205.6 170.4v.9M205.7 173.8h.3l.1 .6M205.7 173.7v.7"/>
<path d="M205.8 175.3h-.3l-.1 .2 .1 .4h.3M205.8 175v.9M206.3 175.8v.1M206.5 172.3l-.3-.1-.2 .2 .1 .4h.4M206.5 172.2v1M206.8 173.8l-.3 .1 .3 .2v.2h-.3M206.9 170.7h.3M206.9 172.2l.1 .6h.3M207 170.4v.8l.2 .1M207.2 174.1l.5-.1-.1-.2-.2-.1-.2 .2 .1 .4h.3M207.2 168.9l-.5 .1a.39 .39 0 0 0 .5 .4l-.1 .4h-.4M207.3 172.2v.7"/>
<path d="M207.6 170.8l.3-.1 .1 .6M207.6 170.4v.9M207.6 169.3h.4v.5l-.4-.1zM207.6 169.7l.1 .1M207.8 175h-.5a.39 .39 0 0 0 .4 .5v.4h-.5M207.8 171.9v.1M207.8 172.2v.7M208.1 175.6l.5-.1-.1-.2h-.2l-.2 .1 .1 .5h.3M208.2 172.2v.7M208.4 171l.4-.1v-.2h-.3l-.1 .1v.5h.4M208.5 168.9v.8l.1 .1M208.5 172.2l-.3 .2"/>
<path d="M208.6 173.4v.1M208.6 173.7v.7M208.8 172.5l.4-.1v-.1l-.3-.1-.1 .2v.4h.4M208.9 175.6l.5-.1-.1-.2h-.2l-.2 .1 .1 .5h.3M209 169.7v.1M209 169.8h.4M209.4 169.2l-.4 .1v.4M209.4 168.9v.9M209.4 173.8l-.4 .1 .4 .2v.2h-.4M209.8 170.4v.9h.4M209.8 169.5l.4-.1v-.2h-.3l-.1 .1v.5h.4M210 171.9v.9h-.3l-.1-.5h.4"/>
<path d="M210.2 175.3h.4M210.3 175v.8l.3 .1M210.5 170.4v.1M210.5 170.7v.6M210.6 169.2v.6M210.8 173.8l-.3-.1-.1 .2 .1 .4h.3M210.8 173.4v1M210.9 175.4l.3-.1 .1 .6M210.9 175v.9M210.9 169.2l-.3 .2M211 171.9v.9h.4v-.5h-.4M211.2 169.8h.4"/>
<path d="M211.2 169.2l.4 .1v.4M211.2 169.2v.9M211.3 173.4v.1M211.3 173.7v.7M211.4 170.7h-.3l-.2 .2 .1 .4h.4M211.6 169.7v.1M211.7 175.6l.4-.1v-.2h-.3l-.1 .1v.5h.4M211.7 171l.5-.1-.1-.2h-.2l-.2 .1 .1 .5h.3M211.8 172.2l.2 .7M212 172.9l-.2 .3M212 173.8l-.3 .1 .3 .2v.2h-.3M212.1 169.2h.3l.1 .6"/>
<path d="M212.2 172.2l-.2 .7M212.3 173.7h.4M212.5 173.4v.8l.2 .2M212.5 169.4l-.5 .2 .2 .2h.3M212.6 170.8l.4-.1v.6M212.6 170.7v.6M212.9 169.7l.1 .1M213 169.8h.3M213 173.7v.7M213.1 175v.9h.5M213.2 172.3l.2-.1 .2 .2v.5h-.3l-.1-.4 .4-.1M213.3 173.7l-.3 .2"/>
<path d="M213.3 169.2l-.4 .1v.4M213.3 168.9v.9M213.6 173.4v.1M213.6 173.7v.7M213.8 170.7l-.4 .1 .4 .3v.2h-.4M213.9 175h.1M213.9 175.3v.6M214 172.3l.3-.1 .2 .2-.1 .4h-.4M214 172.2v1M214 173.8l.3-.1 .2 .2-.1 .4h-.4M214 173.4v1M214.2 171l.4-.1v-.2h-.3l-.1 .1v.5h.4"/>
<path d="M214.3 168.9v.9M214.3 169.3h.6M214.7 175.3h-.2l-.2 .2 .1 .4h.3M214.9 172.3l.2-.1 .2 .2-.1 .4h-.3M214.9 172.2v1M214.9 168.9v.9M214.9 173.7v.6h.4M215 171.2v.1M215.1 175.6l.4-.1v-.2h-.3l-.1 .1v.5h.4M215.3 173.7v.7M215.3 169.2h.4v.6M215.6 173.7h.4"/>
<path d="M215.7 171.9v.8l.2 .2M215.7 169.4l-.4 .2 .1 .2h.3M215.7 173.4v.8l.3 .2M215.9 175.4l.4-.1v.6M215.9 175.3v.6M216.2 169.2v.6M216.2 172h.1M216.2 172.2v.7M216.2 174.1l.5-.1-.1-.2-.2-.1-.2 .2 .1 .4h.3M216.3 172h-.1M216.4 169.2l-.2 .2M216.5 170.4l.3 .5"/>
<path d="M216.8 170.9v.4M217.1 172.3l-.3-.1-.2 .2 .1 .4h.4M217.1 170.4l-.3 .5M217.1 175.3l-.4 .1 .4 .2v.3h-.4M217.2 169.2h-.3l-.2 .2 .1 .4h.4M217.2 168.9v.9M217.4 170.8h.4v.5l-.4-.1zM217.5 172.3l.2-.1 .2 .2v.4l-.3 .1-.1-.4 .4-.1M217.5 173.8l-.3-.1-.2 .2 .1 .4h.4M217.5 173.4v1M217.5 175.6l.4-.1v-.2h-.3l-.1 .1v.5h.4M217.5 169.2l.2 .6 .2-.4 .2 .4 .1-.6"/>
<path d="M218.2 170.7l.1 .6 .4-.1M218.3 171.9v.9h.4v-.5h-.4M218.5 173.8h.4v.5h-.4zM218.6 169.2h.3l.1 .6M218.7 170.7v.6M218.8 175.3h.3M219 169.4l-.5 .2 .2 .2h.3M219.1 175l-.2 .1v.8M219.2 171.9v.8l.1 .2M219.4 173.8h.3l.1 .6M219.4 173.7v.7M219.4 169.2v.6"/>
<path d="M219.4 175.4h.5l-.1 .5-.4-.1zM219.6 172.5l.5-.1-.1-.1-.2-.1-.2 .2 .1 .4h.3M219.7 170.8l.2-.1 .2 .1M219.7 170.7v.6M219.7 169.2l-.3 .2M220 169.5l.4-.1v-.2h-.3l-.1 .1v.5h.4M220.1 170.8l.3-.1 .1 .6M220.1 170.8v.5M220.3 175.3v.6M220.6 175.3l-.3 .2M220.8 173.8h.3l.1 .6M220.9 170.7h.4v.6"/>
<path d="M221 171.9v.8l.2 .2M221.2 174l-.5 .2 .2 .2 .3-.1M221.3 175.3h.4M221.3 170.9l-.4 .2 .1 .2h.3M221.4 168.9v.9h.4M221.4 175v.8l.3 .1M221.5 172.3l.3-.1 .1 .2v.4l-.3 .1-.1-.4 .4-.1M221.6 173.8h.4v.6M221.6 173.7v.7M221.7 170.7l.2 .6M221.9 171.3l-.2 .3M222 175.4l.3-.1 .1 .6"/>
<path d="M222 175v.9M222.1 170.7l-.2 .6M222.2 168.9v.1M222.2 169.2v.6M222.3 172.2l.2 .7 .1-.5 .2 .5 .2-.7M222.8 175.6l.4-.1v-.2h-.3l-.1 .1v.5h.4M223 173.4v.2M223 169.2h-.3l-.1 .2v.4h.4M223.1 170.8h.4l-.1 .5-.3-.1zM223.3 173.4v.2M223.4 169.5l.4-.1v-.2h-.3l-.1 .1v.5h.4M223.6 174.4l.3-1 .3 1"/>
<path d="M223.7 174.1h.5M223.9 170.7h.3l.2 .2-.1 .4h-.4M223.9 170.4v.9M223.9 172.3h.4v.5h-.4zM224.2 169.3l.4-.1v.6M224.2 169.2v.6M224.5 175.3l-.3 .1 .3 .2v.3h-.3M224.6 170.7h.4M224.8 170.4v.8l.2 .1M224.8 172.2v.7M225 175.3h.2l.2 .2-.1 .4h-.3M225 175.3v.9"/>
<path d="M225 172.2l-.2 .2M225 173.5h-.4a.39 .39 0 0 0 .4 .5v.3h-.5M225.3 170.7h.3l.1 .6M225.4 169.2l-.4 .1 .4 .2v.3h-.4M225.7 170.9l-.5 .2 .2 .2h.3M225.8 175.6l.4-.1v-.2h-.3l-.1 .1v.5h.4M225.8 169.5l.4-.1v-.2h-.3l-.1 .1v.5h.4M225.9 172.3l.3-.1 .1 .2v.4l-.3 .1-.1-.4 .4-.1M226 173.4v1M226.1 170.4v.1M226.1 170.7v.6M226.6 170.8l.3-.1 .1 .6"/>
<path d="M226.6 170.7v.6M226.7 169.8l-.1 .1M227 173.5h-.5a.39 .39 0 0 0 .4 .5v.3h-.5M227 175.3h-.2l-.2 .2 .1 .4h.3M227.2 172.2v.8l-.2 .2-.2-.1M227.2 172.3l-.3-.1-.2 .2 .1 .4h.4M227.3 173.4v.2M227.4 175h.1M227.4 175.3v.6M227.5 168.9l.3 .9 .3-.9M227.6 172.2v.7M227.7 173.4v.2"/>
<path d="M227.7 175.3h.4M227.9 172.2l-.3 .2M228 170.7h.4v.6M228.1 175l-.2 .1v.8M228.2 172.5l.4-.1v-.1l-.3-.1-.1 .2v.4h.4M228.4 169.5l.5-.1-.1-.2h-.3l-.1 .1 .1 .5h.3M228.4 170.9l-.4 .2 .1 .2h.3M228.4 175h.1M228.4 175.3v.6M228.6 173.4h.4l.1 .2-.1 .3 .2 .3-.2 .2h-.4zM228.6 173.9h.4M229 172.5l.4-.1v-.1l-.3-.1-.1 .2v.4h.4"/>
<path d="M229.3 169.2v.6M229.3 175.3h-.3l-.2 .2 .1 .4h.4M229.4 174.4l.4-1 .3 1M229.5 169.2l-.2 .2M229.5 174.1h.5M229.8 170.7h-.2l-.2 .2 .1 .4h.3M230.2 169.2l-.4 .1 .4 .2v.3h-.4M230.2 170.8h.4v.5l-.4-.1zM230.2 171.9v1l-.3-.1-.1-.5h.4M230.2 175v.8l.2 .1M230.6 168.9v.1M230.6 169.2v.6"/>
<path d="M230.7 175.3h.4v.6M230.9 173.5h-.5a.39 .39 0 0 0 .4 .5v.3h-.5M231.1 169.3h.4l-.1 .5-.3-.1zM231.1 170.7h.2l.2 .2-.1 .4h-.3M231.1 170.7v.9M231.1 172.2h.4M231.1 175.5l-.4 .2 .1 .2h.3M231.2 171.9v.8l.3 .2M231.3 173.4v1M231.6 175.4l.3-.1 .1 .6M231.6 175.3v.6M231.8 172.3h.4l-.1 .5h-.3z"/>
<path d="M231.8 170.7l.3 .6M231.9 169.3l.4-.1v.6M231.9 169.2v.6M232.1 171.3l-.3 .3M232.2 173.5h-.5a.39 .39 0 0 0 .5 .5l-.1 .3h-.4M232.3 170.7l-.2 .6M232.7 174.3l-.1 .2M232.8 175.3h-.2l-.2 .2 .1 .4h.3M232.8 175.3v.7l-.1 .2h-.3M233.2 171.9v.1M233.2 172.2v.7M233.2 170.8h.4v.5l-.4-.1z"/>
<path d="M233.3 169l.3-.1 .2 .2-.6 .7h.6M233.3 175.3v.6l.4-.1M233.6 173.4l.2 1 .2-.7 .1 .7 .3-1M233.6 172.2v.7M233.6 172.3h.4v.6M233.7 175.3v.6M233.9 170.7h.4M234.1 175.3h.4v.6M234.2 169.7v.1M234.3 170.4l-.2 .1v.8M234.5 175.5l-.4 .2 .1 .2h.3M234.6 169.8h.6"/>
<path d="M234.6 169.1l.3-.2v.9M234.7 173.4v1M235 172.2l.1 .7 .2-.5 .2 .5 .2-.7M235 170.7h.4M235 173.4h.6M235.2 170.4v.8l.2 .1M235.3 173.4v1M235.4 175.3v.7l-.2 .2h-.2M235.4 175.3h-.3l-.2 .2 .1 .4h.4M235.7 170.8l.4-.1v.6M235.7 170.4v.9M235.8 175.6l.4-.1v-.2h-.3l-.1 .1v.5h.4"/>
<path d="M235.9 173.9h.5M235.9 173.4v1M236 172.2v.7M236.3 172.2l-.3 .2M236.4 168.7a1.08 1.08 0 0 0 0 1.5M236.4 173.4v1M236.5 171l.5-.1-.1-.2h-.3l-.1 .1 .1 .5h.3M236.6 169.2h.4M236.6 171.9v.1M236.6 172.2v.7M236.8 168.9v.8l.2 .1M236.9 173.6l.1-.2 .4 .2v.5l-.1 .2-.4-.1z"/>
<path d="M236.9 172.2h.4M237.1 171.9v.8l.2 .2M237.3 169.3l.3-.1 .1 .6M237.3 168.9v.9M237.6 172h.1M237.6 175.3h-.3l-.1 .2 .1 .4h.3M237.6 175.3v.7l-.2 .2h-.2M237.6 172.2v.7M237.9 173.4v.8l.1 .2 .4-.2v-.8M237.9 170.4v.9h.5M238.1 175.4h.4l-.1 .5-.3-.1zM238.1 172.3h.3l.1 .6"/>
<path d="M238.1 172.2v.7M238.1 169.5l.4-.1v-.2h-.3l-.1 .1v.5h.4M238.7 170.4v.1M238.7 170.7v.6M238.7 173.4h.5M238.8 175.3l.2 .6 .3-.6M239 173.4v1M239.3 172.2v.8l-.2 .2-.2-.1M239.3 172.3l-.3-.1-.1 .2 .1 .4h.3M239.5 168.9v.1M239.5 170.7h-.2l-.2 .2 .1 .4h.3M239.6 175.6l.4-.1v-.2h-.3l-.1 .1v.5h.4"/>
<path d="M239.8 172.8v.1M239.8 172.9l-.1 .1M239.8 168.9v.1M239.9 171l.4-.1v-.2h-.3l-.1 .1v.5h.4M240 173.4l.3 1 .1-.7 .2 .7 .2-1M240.2 168.9v.9h.5M240.4 175.3v.6M240.7 175.3l-.3 .2M240.7 172.4l.4 .3-.1 .2-.3-.1M240.7 172.4h.1M240.7 170.8l.4-.1v.6M240.7 170.7v.6"/>
<path d="M241 168.9v.1M241 169.2v.6M241 175.4l.4-.1v.6M241 175.3v.6M241.1 174.4l.3-1 .3 1M241.1 172.3l-.4 .1M241.1 174.1h.5M241.5 172.3h.4v.5h-.4zM241.8 169.2h-.2l-.2 .2 .1 .4h.3M241.9 175h.1M241.9 175.3v.6M241.9 170.7l-.3 .1 .3 .3v.2h-.3"/>
<path d="M242 173.9h.4l.1-.4-.5-.1v1M242.2 169.5l.4-.1v-.2h-.3l-.1 .1v.5h.4M242.2 173.9l.3 .5M242.3 172.2h.3M242.3 175.3v.6M242.3 175.4l.4-.1v.6M242.3 171l.5-.1-.1-.2h-.3l-.1 .1 .1 .5h.3M242.6 171.9l-.2 .1v.9M242.8 172.2h.3M242.9 171.9v.8l.2 .2M242.9 173.9h.5v-.4l-.5-.1v1M243 169.3l.4-.1 .1 .6"/>
<path d="M243 169.2v.6M243.2 173.9l.3 .5M243.4 172.2l.2 .7 .1-.5 .2 .5 .2-.7M243.6 175.3h-.3l-.2 .2 .1 .4h.4M243.6 175.3v.7l-.2 .2h-.2M243.7 170.7h.4v.6M243.7 174.4l.4-1 .3 1M243.8 174.1h.5M244.1 170.9l-.4 .2 .1 .2h.3M244.2 169.2l-.3 .1 .3 .2v.3h-.3M244.4 170.7h.4M244.4 172.3l.3-.1 .1 .2v.4l-.3 .1-.1-.4 .4-.1"/>
<path d="M244.6 170.4v.8l.2 .1M244.6 169.5l.5-.1-.1-.2h-.2l-.2 .1 .1 .5h.3M245.2 173.4v1l-.5-1v1M245.3 172.2v.7M245.4 168.9v.1M245.5 173.4h.6M245.6 172.2l-.3 .2M245.8 168.9v.1M245.8 173.4v1M245.8 172.5l.5-.1-.1-.1-.2-.1-.2 .2 .1 .4h.3M246.1 168.7a1.08 1.08 0 0 1 0 1.5M246.4 173.4v1"/>
<path d="M246.7 172.8v.1M246.7 172.9l-.1 .1M246.8 169.2v.1M246.8 173.9h.4M246.9 169.8l-.1 .1M247.3 173.4h-.5v1h.5M248.2 173.5h-.5a.39 .39 0 0 0 .4 .5v.3h-.5M249.2 173.6l.1-.2 .4 .2v.5l-.1 .2-.4-.1zM250.1 173.9h.5v-.4l-.5-.1v1M250.4 173.9l.3 .5"/>
</g>
<path d="M98.7 98.6h-.3l-.2 .2 .1 .1 .4 .1v.3h-.5M98.7 93.9l-.3-.1-.2 .2 .1 .1 .4 .2v.2h-.5M99.7 98.6h-.3l-.2 .2 .1 .5h.4M99.7 98.2v1.2M99.7 93.9l-.3-.1-.2 .2 .1 .5h.4M100.2 93.4v1l.2 .2M100.3 98.6h.5v.8M100.8 98.9l-.6 .2 .2 .3 .4-.1" fill="none" stroke="#000" stroke-width=".2"/>
<g fill="none" stroke="#848400" stroke-width=".2">
<path d="M34 75.8l-.4-.1-.2 .2 .1 .6h.5M34.5 75.3v1l.1 .2M35.1 75.3v.1M35.1 75.7v.8M36.2 75.8l-.4-.1-.2 .2 .1 .6h.5M36.7 75.3v1.2M36.8 76.1l.3 .4M37.1 75.7l-.4 .5M37.4 76.6h.9M38.6 75.8h.4l.1 .7M39.1 76l-.6 .2 .2 .3h.4M39.6 75.8h.5l.1 .7"/>
<path d="M39.6 75.7v.8M40.6 75.5h.6l.6 .6-.6 .6h-.6zM100.4 76.1l.6-.6h.6v1.2h-.6zM102.5 75.8l-.3-.1-.2 .2 .1 .6h.4M103 75.3v1l.2 .2M103.7 75.3v.1M103.7 75.7v.8M104.7 75.8l-.3-.1-.2 .2 .1 .6h.4M105.3 75.3v1.2M105.4 76.1l.3 .4M105.7 75.7l-.4 .5M105.9 76.6h1"/>
<path d="M107.1 75.8l.4-.1 .2 .2-.1 .6h-.5M107.1 75.7v1.2M108.1 75.7l.2 .8 .3-.6 .2 .6 .2-.8M109.5 75.8l.3-.1 .2 .2M109.5 75.7v.8M110 75.9l.2-.2 .2 .1 .1 .7M110 75.9v.6M31.9 99.7l-.3-.1-.3 .2 .2 .6h.4M31.9 94.9l-.3-.1-.3 .3 .2 .5h.4M32.4 99.2v1l.2 .2M32.4 94.4v1.1l.2 .1M33 94.4v.2"/>
<path d="M33 94.8v.8M33 99.2v.1M33 99.6v.8M33.2 90.1h-.4l-.2 .2 .1 .5h.5M33.7 89.7v1l.1 .2M33.7 80.6l-.3-.1-.2 .2 .1 .5h.4M34.1 85.3h-.3l-.2 .2 .1 .5h.4M34.1 99.7l-.3-.1-.2 .2 .1 .6h.4M34.1 94.9l-.3-.1-.2 .3 .1 .5h.4M34.2 80.1v1l.2 .2M34.3 89.7v.1M34.3 90.1v.8"/>
<path d="M34.6 84.9v1l.2 .2M34.6 94.4v1.2M34.6 99.2v1.2M34.8 100l.3 .4M34.8 95.2l.3 .4M34.9 80.1v.1M34.9 80.5v.8M35.1 99.6l-.5 .5M35.1 94.8l-.5 .5M35.3 84.9v.1M35.3 85.3v.8M35.3 95.7h.9"/>
<path d="M35.4 90.1h-.4l-.2 .2 .1 .5h.5M35.9 89.7v1.2M35.9 80.6l-.3-.1-.2 .2 .1 .5h.4M36 90.4l.3 .5M36.3 85.3h-.3l-.2 .2 .1 .5h.4M36.3 90.1l-.4 .4M36.5 80.1v1.2M36.5 99.7l.4-.1 .1 .2M36.5 94.9l.4-.1 .1 .2M36.5 94.8v.8M36.5 99.6v.8M36.6 91h.9"/>
<path d="M36.6 80.8l.3 .5M36.9 84.9v1.2M36.9 80.5l-.4 .5M37 85.6l.3 .5M37 99.8l.2-.2 .3 .1v.7M37 95l.2-.2 .3 .1v.7M37 95v.6M37 99.8v.6M37.1 81.4h1M37.3 85.3l-.4 .4M37.5 86.2h1M38.1 99.7l.2-.1 .3 .1v.7l-.5-.1z"/>
<path d="M38.1 94.4v.2M38.1 94.8v.8M38.2 90.1h-.3l-.2 .1 .1 .2 .4 .1v.3h-.5M38.3 80.5v.8M38.7 80.5l-.4 .2M39.1 94.9l-.3-.1-.2 .2 .1 .2 .4 .1v.3h-.5M39.2 90.1h-.3l-.2 .2 .1 .5h.4M39.2 85.3h-.3l-.2 .2 .1 .5h.4M39.5 80.6l-.3-.1-.2 .2 .1 .1 .4 .2v.2h-.5M39.6 99.7l-.3-.1-.2 .2 .1 .2 .4 .1v.3h-.5M39.7 94.9l.3-.1 .2 .3v.3l-.2 .2-.4-.2zM39.8 89.7v1.2"/>
<path d="M39.9 80.5h.4M39.9 90.4l.3 .5M40 80.1v1l.3 .2M40.2 99.2v.1M40.2 99.6v.8M40.2 85.3h-.3l-.2 .1 .1 .2 .4 .1v.3h-.5M40.2 90.1l-.4 .4M40.6 99.4h.6l.6 .6-.6 .6h-.6zM40.6 89.8h.6l.6 .6-.6 .6h-.6zM40.6 85h.6l.6 .6-.6 .6h-.6zM40.6 94.6h.6l.6 .6-.6 .6h-.6zM40.6 80.3h.6l.6 .6-.6 .6h-.6z"/>
<path d="M100.4 80.9l.6-.6h.6v1.2h-.6zM100.4 85.6l.6-.6h.6v1.2h-.6zM101 89.8h.6v1.2h-.6l-.6-.6zM102.5 90.1h-.3l-.2 .2 .1 .5h.4M102.5 80.6l-.3-.1-.2 .2 .1 .5h.4M102.5 85.3h-.3l-.2 .2 .1 .5h.4M103 89.7v1l.2 .2M103 80.1v1l.2 .2M103 84.9v1l.2 .2M103.7 80.1v.1M103.7 80.5v.8M103.7 84.9v.1"/>
<path d="M103.7 85.3v.8M103.7 89.7v.1M103.7 90.1v.8M104.7 90.1h-.3l-.2 .2 .1 .5h.4M104.7 80.6l-.3-.1-.2 .2 .1 .5h.4M104.7 85.3h-.3l-.2 .2 .1 .5h.4M105.1 95.2l.6-.6h.6v1.2h-.6zM105.3 80.1v1.2M105.3 84.9v1.2M105.3 89.7v1.2M105.4 90.4l.3 .5M105.4 85.6l.3 .5"/>
<path d="M105.4 80.8l.3 .5M105.7 90.1l-.4 .4M105.7 85.3l-.4 .4M105.7 80.5l-.4 .5M105.7 99.4h.6v1.2h-.6l-.6-.6zM105.9 91h1M105.9 86.2h1M105.9 81.4h1M107 90.1h.4M107.1 89.7v1l.3 .2M107.1 80.1v.1M107.1 80.5v.8"/>
<path d="M107.1 85.3v.8M107.2 99.7l-.3-.1-.2 .2 .1 .2 .4 .1v.3h-.5M107.2 94.9l-.3-.1-.2 .2 .1 .2 .4 .1v.3h-.5M107.5 85.3l-.4 .2M107.7 80.5v.8M107.7 90.1l.6 .8M107.7 80.6h.5v.7M107.8 85.3l.6 .8M108.3 99.7l-.4-.1-.2 .2 .1 .6h.5M108.3 99.2v1.2M108.3 94.9l-.4-.1-.2 .3 .1 .5h.5M108.3 90.1l-.6 .8"/>
<path d="M108.4 85.3l-.6 .8M108.6 80.5h.5M108.8 80.1v1l.3 .2M108.8 94.4v1.1l.2 .1M108.8 99.7h.5l.1 .7M109.4 99.9l-.6 .2 .2 .3h.4M211.5 90.4l.6-.6h.6v1.2h-.6zM213 90.1h.4M213.1 89.7v1l.3 .2M213.8 90.5l.5-.2v-.2h-.4l-.1 .1v.6h.5M214.8 90.2l.4-.1 .1 .1M214.8 90.1v.8"/>
<path d="M215.3 90.2l.2-.1h.3l.1 .8M215.3 90.2v.7M216.4 90.1h.4l.2 .2-.1 .5h-.5M216.4 90.1v1.2M217.5 90.5l.5-.2v-.2h-.4l-.1 .1v.6h.5M218.5 90.1v.8M218.9 90.1l-.4 .2M219.3 90.1h.4l.1 .8M219.8 90.3l-.6 .3 .2 .3 .4-.1M220.2 90.1h.4M220.4 89.7v1l.2 .2M221 90.1l.1 .7 .4-.1"/>
<path d="M221.5 90.1v.8M222.1 90.1v.8M222.5 90.1l-.4 .2M222.8 90.5l.6-.2-.1-.2h-.3l-.2 .1 .1 .6h.4M223.6 91h.9M224.8 90.1h.4l.1 .8M225.3 90.3l-.6 .3 .2 .3 .4-.1M225.9 89.7v1l.1 .2M226.4 90.5l.6-.2v-.2h-.4l-.2 .1 .1 .6h.5M227.5 90.1v.8M227.9 90.1l-.4 .2M228.1 90.1h.4"/>
<path d="M228.3 89.7v1l.2 .2M35.3 100.5h.9"/>
</g>
<g fill="none" stroke="#008484" stroke-width=".2">
<path d="M59.6 76.4l.3-.9 .3 .9M59.7 76.2h.4M61.1 75.5v.9l-.6-.9v.9M61.7 73v-1.2l.4 .9 .4-.9v1.2M63.1 71.8v1.2M63.7 71.8v1.2M63.8 72.3l.5 .7M64.3 71.8l-.6 .7M64.9 72.5l.5-.1 .1-.4-.6-.2v1.2M65.1 72.5l.4 .5M66.1 72l.2-.2a.4 .4 0 0 1 .5 .4v.4a.4 .4 0 0 1-.4 .4 .4 .4 0 0 1-.4-.4zM67.3 71.8h.4l.2 .3-.2 .3 .2 .1 .1 .3-.2 .2h-.5z"/>
<path d="M67.3 72.4h.4M68.5 71.8v1l.2 .2h.3l.2-.2v-1M70.2 69.6a.53 .53 0 0 0-.7 .4 .53 .53 0 0 0 .7 .5M70.4 71.9l-.6 .1v.3l.5 .2 .1 .3-.3 .2h-.4M70.6 73.1h.9M70.7 69.6l.3-.1a.4 .4 0 0 1 .5 .3v.4a.4 .4 0 0 1-.4 .5 .4 .4 0 0 1-.4-.5zM71.8 72.4h.7M71.8 71.8v1.2M72.5 71.8v1.2M72.7 69.5v1.1l-.7-1.1v1.1M73.1 72l.2-.2a.4 .4 0 0 1 .5 .4v.4a.4 .4 0 0 1-.4 .4 .4 .4 0 0 1-.4-.4zM73.2 70.6h.7"/>
<path d="M73.2 69.8l.3-.3v1.1M74.9 71.9l-.6 .1v.3l.5 .2 .1 .3-.2 .2h-.5M75.3 71.8h.7M75.6 71.8v1.2M76.1 73.1h.9M77.9 72a.53 .53 0 0 0-.7 .4 .53 .53 0 0 0 .7 .5M78.5 72l.2-.2a.4 .4 0 0 1 .5 .4v.4a.4 .4 0 0 1-.4 .4 .4 .4 0 0 1-.4-.4zM80.4 71.8v1.2l-.7-1.2v1.2M81 76l.4-.1 .1-.3-.5-.1v.9M81.6 71.8v1.2l-.6-1.2v1.2M81.8 75.5l.3 .9 .1-.7 .2 .7 .2-.9M83 76.4v-.9l.3 .7 .3-.7v.9"/>
<path d="M178 72.7h.9M178.5 72.2v1M179.4 72h.7l-.4 .4 .4 .1v.5l-.2 .2-.5-.2M180.6 73v.2M181.1 72h.7l-.4 .4 .4 .1v.5l-.2 .2-.5-.2M182.2 72l.4 1.2 .4-1.2M193.5 69.1h1M194 68.7v.9M194.9 68.4h.8l-.4 .4 .3 .1v.6l-.2 .1-.5-.1M196.2 69.5v.1M196.6 68.4h.8l-.4 .4 .3 .1v.6l-.2 .1-.5-.1M197.7 68.4l.4 1.2 .4-1.2"/>
<path d="M199 78.1h.7M199 77.3l.3-.4v1.2M199.7 74.6a.53 .53 0 0 0-.7 .5 .53 .53 0 0 0 .7 .5M200.1 74.5h.8l-.4 .5 .3 .1v.5l-.2 .1-.5-.1M200.2 77l.2-.1a.64 .64 0 0 1 .4 .6 .64 .64 0 0 1-.4 .6l-.3-.4zM201.4 77l.1-.1a.64 .64 0 0 1 .5 .6 .64 .64 0 0 1-.5 .6l-.2-.4zM201.9 74.5h-.5l-.1 .6 .6-.1v.6l-.1 .1-.5-.1M202.5 77.3v.8M202.5 77.4h.4l.1 .7M204.3 73.9h.9M204.8 73.4v.9M205.7 73.2h.7l-.4 .4 .3 .1v.5l-.1 .1-.5-.1"/>
<path d="M206.9 74.2v.1M207.4 73.2h.7l-.4 .4 .4 .1v.5l-.2 .1-.5-.1M208.5 73.2l.4 1.1 .4-1.1M59.7 80.8l.5-.1v-.4h-.5v.9M59.7 95.5v-.9l.3 .7 .4-.7v.9M60 80.8l.3 .4M60.2 89.9h-.5a.4 .4 0 0 0 .5 .5l-.1 .3h-.4M60.3 85.1a.42 .42 0 0 0-.6 .4 .42 .42 0 0 0 .6 .4M60.8 99.5l.2-.1 .4 .1v.5l-.1 .3-.5-.1zM60.8 94.6v.9M61.2 89.9a.42 .42 0 0 0-.6 .4 .42 .42 0 0 0 .6 .4M61.2 85.1h-.5a.4 .4 0 0 0 .4 .5v.3h-.5"/>
<path d="M61.2 80.3h-.5a.4 .4 0 0 0 .4 .5v.4h-.5M61.5 80.3h.5M61.6 89.8v1M61.7 80.3v.9M61.7 90.2l.4 .6M61.8 94.6l-.5 .1a.4 .4 0 0 0 .4 .5v.3h-.5M62.1 89.8l-.5 .6M62.2 94.7l.2-.1 .3 .1 .1 .5-.2 .3-.4-.1zM62.3 99.4l-.5 .1a.4 .4 0 0 0 .5 .5l-.1 .3h-.4M62.7 99.4v.9M81.9 99.4l-.5 .1a.4 .4 0 0 0 .5 .5l-.1 .3h-.4M81.9 80.3v.9"/>
<path d="M82 94.6l-.5 .1a.4 .4 0 0 0 .4 .5v.3h-.5M82.2 85.5h.5v-.4l-.5-.1v1M82.3 99.4a.48 .48 0 0 1 .6 .4 .48 .48 0 0 1-.6 .5zM82.3 89.8h.6M82.5 85.5l.3 .5M82.6 89.8v1M82.9 94.7a.42 .42 0 0 0-.6 .4 .42 .42 0 0 0 .6 .4M82.9 80.3v.9l-.5-.9v.9M83.1 89.8l.6 1M83.1 85l.6 1M83.2 80.3h.6M83.3 94.6v.9h.5"/>
<path d="M83.5 80.3v.9M83.7 89.8l-.6 1M83.7 85l-.6 1M173.8 98l.4-1.2 .4 1.2M173.8 95.6l.4-1.2 .4 1.2M173.8 93.2l.4-1.2 .4 1.2M173.9 97.7h.6M173.9 95.3h.6M173.9 92.9h.6M174.6 84.9l-.6 .1v.3l.5 .3 .1 .2-.2 .3-.5-.1M174.6 82.5l-.6 .1v.3l.5 .3 .1 .3-.2 .2-.5-.1M175 96.9l.4-.1 .3 .4-.8 .8h.8"/>
<path d="M175 95.6h.7M175 94.8l.3-.4v1.2M175.1 92.2l.2-.2a.64 .64 0 0 1 .4 .6 .64 .64 0 0 1-.4 .6l-.3-.4zM175.1 82.5a.6 .6 0 0 1 .7 .6 .6 .6 0 0 1-.7 .6zM175.8 85a.53 .53 0 0 0-.7 .5 .53 .53 0 0 0 .7 .5M176.2 83.7l.4-1.2 .4 1.2M176.3 83.3h.5M176.3 84.9v1.2h.6M179.7 97.3h1.1l-1.1 .7h1.1M179.7 83.8l1.1 .4-1.1 .4M179.7 98.6a.54 .54 0 0 0 .6 .7 .54 .54 0 0 0 .4-.8h-.4v.3M179.8 82.9a.62 .62 0 0 1 .7-.1 .62 .62 0 0 1 .3 .6h-1.1z"/>
<path d="M179.8 81.7a.62 .62 0 0 1 .7-.1 .62 .62 0 0 1 .3 .6h-1.1zM179.8 96.2a.62 .62 0 0 1 .7-.1 .62 .62 0 0 1 .3 .7h-1.1zM182 96.1l1.5 1M182 98.6v.6h1.2v-.6M182 93.8h1.2l-1.2 .7h1.2M182.1 95.1a.54 .54 0 0 0 .5 .6 .54 .54 0 0 0 .5-.7h-.4v.2M182.2 92.7a.62 .62 0 0 1 .7-.1 .62 .62 0 0 1 .3 .6h-1.2zM182.6 98.8v.4M182.7 98.1l-.1-.5-.4-.1-.2 .6h1.2M183.1 90.9l.4-1.2 .4 1.2M183.2 90.5h.6M184.3 89.7v1l.2 .2"/>
<path d="M184.9 90.5l.5-.2v-.2h-.4l-.1 .1v.6h.5M186 90.1v.8M186.3 90.1l-.3 .2M186.5 90.1h.5M186.7 89.7v1l.3 .2M193.2 86.4v1l.3 .2h.2l.2-.2v-1M194.4 87.6h.7M194.4 86.7l.4-.3v1.2M195 83.1a.54 .54 0 0 0-.7 .6 .54 .54 0 0 0 .8 .5v-.4h-.2M195.6 87.6h.6M195.6 86.7l.3-.3v1.2M196.3 83.1v1.2l-.7-1.2v1.2"/>
<path d="M196.8 83.1a.6 .6 0 0 1 .7 .6 .6 .6 0 0 1-.7 .6zM208.7 82.3h.6v-.5l-.6-.1v1.2M208.9 84l-.2 .9h.7M209 82.3l.4 .6M209.2 84.5v.8M209.7 84.1h.8l-.5 1.2M209.9 82.9h.6M209.9 82l.3-.3v1.2M211 84.1v1.2M211.1 84.8l.3 .5M211.3 81.6l-.3 .9h.7M211.4 84.5l-.4 .4"/>
<path d="M211.6 82.1v.8M23.9 105h.9M24.4 104.5v.9M25.3 104.2h.7l-.4 .5 .3 .1v.5l-.1 .1-.5-.1M25.4 119a.54 .54 0 0 0-.7 .5 .54 .54 0 0 0 .7 .5v-.4h-.2M26.5 105.3v.1M26.6 118.9v1.2l-.7-1.2v1.2M27 104.2h.7l-.4 .5 .4 .1v.5l-.2 .1-.5-.1M27.2 118.9a.6 .6 0 0 1 .7 .6 .6 .6 0 0 1-.7 .6zM28 104.2l.4 1.2 .4-1.2M29.3 114h.7M29.3 113.1l.4-.3v1.2"/>
<path d="M30.1 110.5a.53 .53 0 0 0-.8 .5 .53 .53 0 0 0 .8 .5M30.5 110.4h.7l-.4 .4 .3 .1v.6l-.1 .1-.5-.1M30.6 112.9l.2-.1a.64 .64 0 0 1 .4 .6 .64 .64 0 0 1-.4 .6l-.3-.5zM31.7 110.5l.4-.1 .2 .3-.7 .9h.7M31.7 112.9l.2-.1a.64 .64 0 0 1 .4 .6 .64 .64 0 0 1-.4 .6l-.3-.5zM32.8 113.2v.8M32.8 113.3l.5-.1v.8M34.6 105h1M35.1 104.5v.9M36 104.2h.8l-.4 .5 .3 .1v.5l-.2 .1-.5-.1M36.1 119a.54 .54 0 0 0-.7 .5 .54 .54 0 0 0 .8 .5v-.4h-.2M37.3 105.3v.1"/>
<path d="M37.4 118.9v1.2l-.7-1.2v1.2M37.7 104.2h.8l-.4 .5 .3 .1v.5l-.2 .1-.5-.1M37.9 118.9a.6 .6 0 0 1 .7 .6 .6 .6 0 0 1-.7 .6zM38.8 104.2l.4 1.2 .4-1.2M40.1 114h.7M40.1 113.1l.3-.3v1.2M40.8 110.5a.53 .53 0 0 0-.7 .5 .53 .53 0 0 0 .7 .5M41.2 110.4h.8l-.4 .4 .3 .1v.6l-.2 .1-.5-.1M41.3 112.9l.2-.1a.64 .64 0 0 1 .4 .6 .64 .64 0 0 1-.4 .6l-.3-.5zM42.4 110.4h.7l-.4 .4 .3 .1v.6l-.1 .1-.5-.1M42.4 113.2l.1 .7 .4-.1M42.9 113.2v.8"/>
<path d="M43.5 113.3h.4M44.1 112.8h-.6v1.2M49 101.4h.9M49.4 100.9v.9M50.4 100.6h.7l-.4 .5 .3 .1v.5l-.1 .1-.5-.1M50.5 115.4a.54 .54 0 0 0-.7 .6 .54 .54 0 0 0 .7 .4v-.4h-.2M51.6 101.7v.1M51.7 115.3v1.2l-.7-1.2v1.2M52.1 100.6h.7l-.4 .5 .3 .1v.5l-.1 .1-.5-.1M52.3 115.3a.6 .6 0 0 1 .7 .6 .6 .6 0 0 1-.7 .6zM53.1 100.6l.4 1.2 .4-1.2M59.6 104.1h.6l-.3 .4 .3 .1v.4h-.6"/>
<path d="M59.7 100.3v-.9l.3 .6 .4-.6v.9M60.2 109a.43 .43 0 0 0-.5 .4 .43 .43 0 0 0 .6 .4v-.3h-.2M60.5 104.1l.3 1 .3-1M61.2 108.9v1l-.5-1v1M61.4 104.1h.6l-.4 .4 .3 .1v.4h-.5M61.7 108.9a.48 .48 0 0 1 .5 .5 .48 .48 0 0 1-.5 .5zM62.6 109.9h.5M62.6 109.2l.3-.3v1M80.8 109a.43 .43 0 0 0-.6 .4 .43 .43 0 0 0 .6 .4v-.3h-.2M81.8 108.9v1l-.6-1v1M82.2 108.9a.48 .48 0 0 1 .6 .5 .48 .48 0 0 1-.6 .5zM82.8 104.1h-.4l-.1 .5h.5v.4h-.5"/>
<path d="M83.1 104.1l.4 1 .3-1M83.1 100.3l.4-.9 .3 .9M83.1 109l.4-.1 .2 .3-.6 .7h.6M83.2 100h.5M91.1 115.4a.54 .54 0 0 0-.7 .6 .54 .54 0 0 0 .7 .4v-.4h-.2M92.3 115.3v1.2l-.6-1.2v1.2M92.9 115.3a.6 .6 0 0 1 .7 .6 .6 .6 0 0 1-.7 .6zM129 107.3h.9M129.5 106.9v.9M130.4 106.6h.7l-.4 .5 .4 .1v.5l-.2 .1-.5-.1M131.6 107.7v.1M132.1 106.6h.7l-.4 .5 .4 .1v.5l-.2 .1-.5-.1"/>
<path d="M133.2 106.6l.4 1.2 .4-1.2M133.7 114l-.1 1-.4 .2M134.2 114.6l.6-.1 .1-.4-.7-.1v1.2M135.3 114h.8l-.4 .4 .3 .1v.5l-.2 .2-.5-.2M141 107.3h.9M141.4 106.9v.9M142.3 106.6h.8l-.4 .5 .3 .1v.5l-.1 .1-.6-.1M143.6 107.7v.1M144.1 106.6h.7l-.4 .5 .3 .1v.5l-.1 .1-.5-.1M145.1 106.6l.4 1.2 .4-1.2M145.6 114v1l-.4 .2M146.2 114.6l.6-.1v-.4l-.6-.1v1.2"/>
<path d="M147.6 113.9l-.3 .9h.8M147.9 114.4v.8M152.9 107.3h.9M153.4 106.9v.9M154.3 106.6h.7l-.4 .5 .4 .1v.5l-.2 .1-.5-.1M155.5 107.7v.1M156 106.6h.7l-.4 .5 .4 .1v.5l-.2 .1-.5-.1M157.1 106.6l.4 1.2 .4-1.2M157.6 114l-.1 1-.4 .2M158.1 114.6l.6-.1 .1-.4-.7-.1v1.2M159.9 114h-.6v.5h.5l.1 .5-.2 .2-.4-.2M179.5 110.6a.54 .54 0 0 0-.7 .6 .54 .54 0 0 0 .8 .4v-.4h-.3"/>
<path d="M180.7 110.6v1.2l-.6-1.2v1.2M181.3 110.6a.6 .6 0 0 1 .7 .6 .6 .6 0 0 1-.7 .6zM184.9 102.8v-1.2l.4 .9 .4-.9v1.2M186.9 101.7a.53 .53 0 0 0-.7 .5 .53 .53 0 0 0 .7 .5M187.5 102.2h.5l.1-.5-.6-.1v1.2M189.3 102.1l-.2 .2h-.4v-.6l.4-.1 .2 .2-.1 .7-.1 .2-.4 .1M190 102.1l-.3-.2 .3-.3h.2l.2 .2-.2 .3M190 102.1l-.3 .2 .1 .4 .2 .1h.2l.2-.2v-.3l-.2-.2M190 102.1h.2M191 101.7l.2-.1a.64 .64 0 0 1 .4 .6 .64 .64 0 0 1-.4 .6l-.3-.5zM192.2 102.1l-.2 .2 .1 .4 .1 .1h.3l.2-.2-.1-.4-.1-.1M192.2 102.1l-.2-.2 .2-.3h.3l.2 .2-.2 .3"/>
<path d="M192.2 102.1h.3M130.5 135.7a.54 .54 0 0 0-.7 .6 .54 .54 0 0 0 .8 .4v-.4h-.3M131.8 135.7v1.1l-.7-1.1v1.1M132.3 135.7a.6 .6 0 0 1 .7 .6 .6 .6 0 0 1-.7 .5zM133.4 126.5h.6l.1-.5-.7-.1v1.2M133.7 128.2l-.3 .9h.7M133.7 126.5l.4 .6M134 128.7v.8M134.5 128.3h.8l-.5 1.2M134.6 126.3l.3-.4v1.2M134.6 127.1h.7M135.7 128.3v1.2"/>
<path d="M135.7 126.3l.4-.4v1.2M135.7 127.1h.7M135.8 129l.4 .5M136.2 128.7l-.5 .4M142.5 135.7a.54 .54 0 0 0-.7 .6 .54 .54 0 0 0 .7 .4v-.4h-.2M143.7 135.7v1.1l-.7-1.1v1.1M144.3 135.7a.6 .6 0 0 1 .7 .6 .6 .6 0 0 1-.7 .5zM145.4 126.5h.6v-.5l-.6-.1v1.2M145.6 128.2l-.3 .9h.8M145.7 126.5l.4 .6M145.9 128.7v.8M146.4 128.3h.8l-.5 1.2"/>
<path d="M146.5 127.1h.7M146.5 126.3l.4-.4v1.2M147.7 128.3v1.2M147.7 126l.4-.1 .3 .4-.8 .8h.8M147.8 129l.3 .5M148.1 128.7l-.4 .4M154.4 135.7a.54 .54 0 0 0-.7 .6 .54 .54 0 0 0 .8 .4v-.4h-.3M155.7 135.7v1.1l-.7-1.1v1.1M156.2 135.7a.6 .6 0 0 1 .7 .6 .6 .6 0 0 1-.7 .5zM157.3 126.5h.6l.1-.5-.7-.1v1.2M157.6 128.2l-.3 .9h.7M157.6 126.5l.4 .6"/>
<path d="M157.9 128.7v.8M158.4 128.3h.8l-.6 1.2M158.5 126.3l.3-.4v1.2M158.5 127.1h.7M159.6 125.9h.7l-.4 .5 .3 .1v.5l-.1 .1-.5-.1M159.6 128.3v1.2M159.7 129l.4 .5M160.1 128.7l-.5 .4"/>
</g>
<g fill="#840000" stroke="#840000" stroke-width=".35">
<path d="M130.5 115.7h1.9a.96 .96 0 0 1-1 1 .96 .96 0 0 1-.9-1z" fill-rule="evenodd"/>
<path d="M130.7 114.6a.96 .96 0 0 1 1.1-.2 .96 .96 0 0 1 .6 .9h-1.9z" fill-rule="evenodd"/>
<path d="M154.4 115.7h1.9a.96 .96 0 0 1-1 1 .96 .96 0 0 1-.9-1z" fill-rule="evenodd"/>
<path d="M154.6 114.6a.96 .96 0 0 1 1.1-.2 .96 .96 0 0 1 .6 .9h-1.9z" fill-rule="evenodd"/>
<path d="M142.4 115.7h1.9a.96 .96 0 0 1-.9 1 .96 .96 0 0 1-1-1z" fill-rule="evenodd"/>
<path d="M142.7 114.6a.96 .96 0 0 1 1-.2 .96 .96 0 0 1 .6 .9h-1.9z" fill-rule="evenodd"/>
</g>
<path d="M194 76.8h3.8M194 75.4h3.8M24.4 112.6h3.8M24.4 111.2h3.8M35.1 112.6h3.9M35.1 111.2h3.9" fill="none" stroke="#840000" stroke-width=".48"/>
<g fill="#008400" stroke="#008400" stroke-width=".35">
<circle cx="131.4" cy="121.5" r=".43"/>
<circle cx="143.4" cy="121.5" r=".43"/>
<circle cx="180.4" cy="104.8" r=".43"/>
<circle cx="155.3" cy="121.5" r=".43"/>
<circle cx="206.7" cy="90.4" r=".43"/>
</g>
</svg>
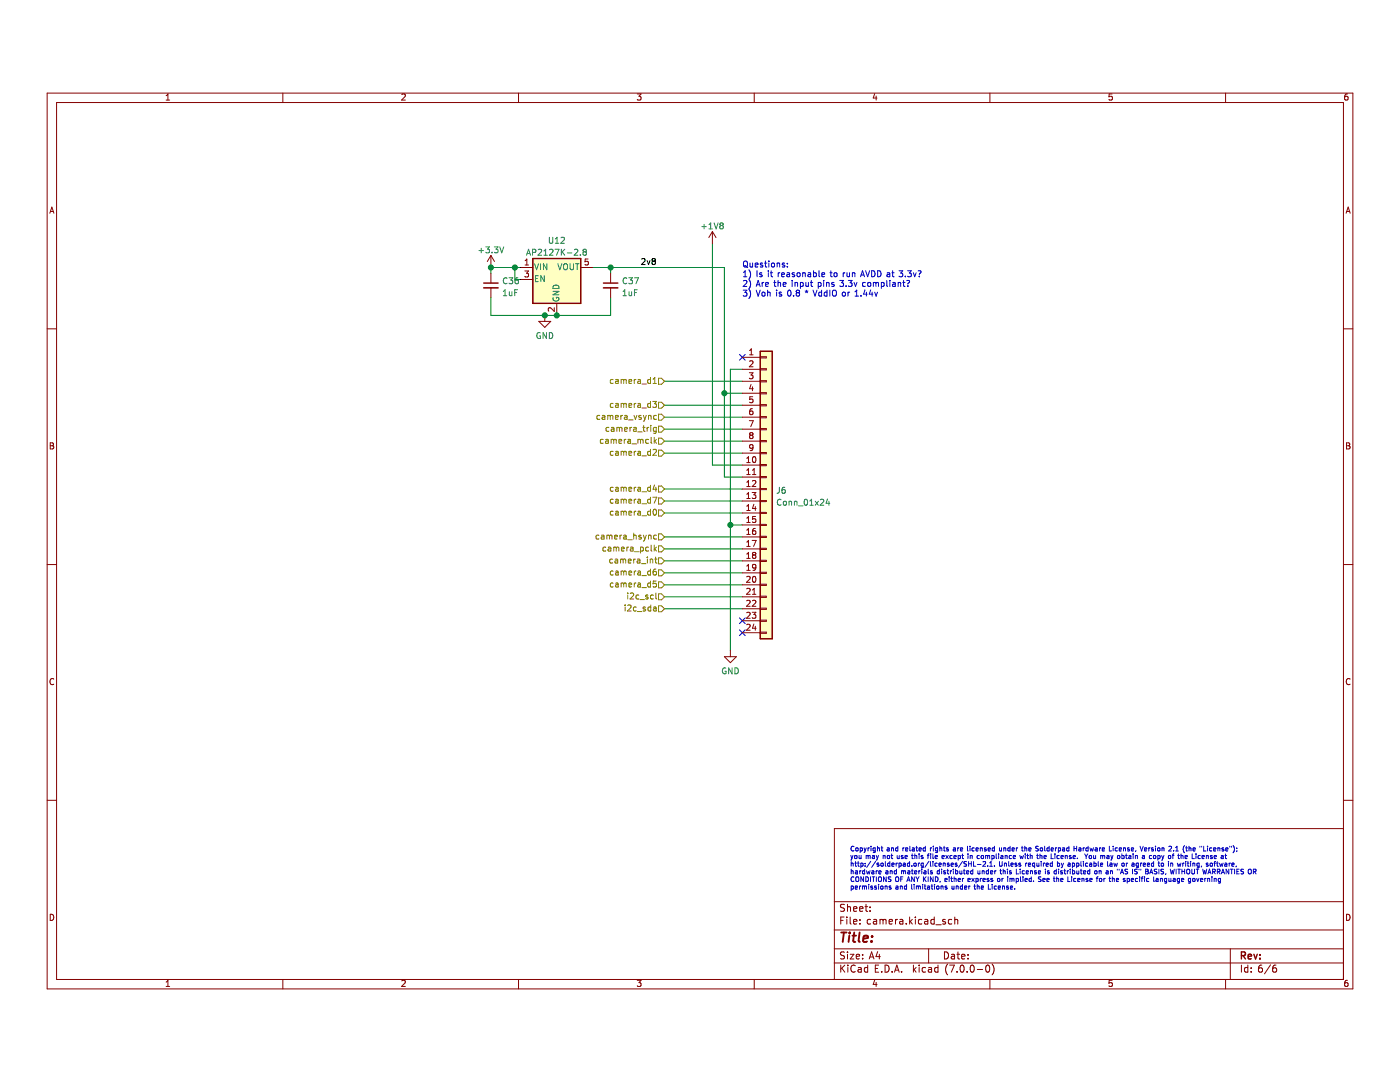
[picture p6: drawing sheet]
<svg xmlns="http://www.w3.org/2000/svg" width="279mm" height="216mm" viewBox="0 0 279 216" stroke-linecap="round" stroke-linejoin="round" font-family="sans-serif">
<path d="M0 9.2h279.4v206.7h-279.4z" fill-rule="evenodd" fill="#fff" stroke="#fff" stroke-width=".35"/>
<g fill="none" stroke="#840000" stroke-width=".2">
<path d="M9.4 18.6h260.6v178.7h-260.6zM33.2 20h.7M33.2 19.1l.3-.4v1.3M56.4 18.6v1.9M80.2 18.9l.5-.2 .2 .4-.8 .9h.8M103.5 18.6v1.9M127.2 18.7h.7l-.4 .5 .4 .1v.6l-.2 .1-.5-.1M150.5 18.6v1.9M174.6 18.7l-.3 .9h.7M174.9 19.2v.8M197.6 18.6v1.9M221.9 18.7h-.5l-.1 .6h.6v.6l-.1 .1-.5-.1"/>
<path d="M244.6 18.6v1.9M268.9 18.7l-.3 .1-.2 .2-.1 .7 .3 .3 .4-.1-.1-.6-.3-.1-.3 .2M11.3 20.5h256.8v174.9h-256.8zM9.9 42.5l.5-1.2 .4 1.2M10.1 42.2h.5M98 51l-.7 1.2M98 51v2.4M98 54.6v1.9M98 57.4v2M98 51l.7 1.2M103.9 53.4h2.4M103.9 55.8h2.4"/>
<path d="M104.7 54.1h.8l-.4 .4 .3 .1v.6l-.1 .1-.6-.1M104.8 52.9h.7M104.8 52l.3-.3v1.2M115.9 53.4h2.4M117.4 51.7h-.6l-.1 .6 .6-.1 .1 .6-.2 .1-.5-.1M121.9 54.6v1.9M121.9 57.4v2M142.2 46.2l-.7 1.2M142.2 46.2v2.4M142.2 46.2l.7 1.2M268.6 42.5l.5-1.2 .4 1.2M268.8 42.2h.5"/>
<path d="M9.4 65.6h1.9M107.5 64.1h2.4l-1.2 1.2zM108.7 62.9v1.2M110.6 61.4v.7l-.8-.7-.4 .2 .1 .5M111.1 60.5v2.4M148.1 71.3h3.6M148.1 73.7h3.6M148.1 76.1h3.6M148.1 78.5h3.6M149.5 74.4h.8l-.4 .4 .3 .2v.5l-.1 .1-.6-.1M149.6 70.8h.7M149.6 69.9l.3-.3v1.2"/>
<path d="M149.6 72.1l.5-.1 .2 .3-.8 .9h.8M149.9 76.7l-.3 .9h.7M150.2 77.2v.8M150.2 79.2h-.5l-.1 .5h.6v.5l-.1 .2-.5-.2M151.7 71.2h1.2v.2h-1.2zM151.7 73.6h1.2v.2h-1.2zM151.7 76h1.2v.2h-1.2zM151.7 78.3h1.2v.3h-1.2zM268.1 65.6h1.9M10 88.4h.4l.3 .2-.3 .3 .3 .2v.3l-.2 .2h-.5zM10 88.9h.4M148.1 92.8h3.6"/>
<path d="M148.1 95.2h3.6M148.1 97.6h3.6M148.1 100h3.6M148.1 80.9h3.6M148.1 83.2h3.6M148.1 85.6h3.6M148.1 88h3.6M148.1 90.4h3.6M149 92.3h.7M149 91.5l.4-.4v1.2M149 93.8l.4-.3v1.2M149 96.2l.4-.3v1.2"/>
<path d="M149 98.6l.4-.3v1.2M149 94.7h.7M149 97.1h.7M149 99.5h.7M149.5 83.9h.8l-.5 1.2M149.8 86.8l-.2-.2 .2-.3h.3l.2 .3-.2 .2M149.8 86.8l-.2 .3 .1 .3 .1 .1h.3l.2-.2-.1-.3-.1-.2M149.8 86.8h.3M150.1 98.3h.8l-.4 .4 .3 .1v.6l-.2 .1-.5-.1M150.2 93.8l.3-.3v1.2M150.2 96l.4-.1 .3 .3-.8 .9h.8M150.2 94.7h.7"/>
<path d="M150.2 81.6h-.4l-.1 .2-.1 .7 .2 .2 .4-.1v-.5l-.4-.1-.2 .2M150.3 91.2l.2-.1a.64 .64 0 0 1 .4 .6 .64 .64 0 0 1-.4 .6l-.3-.5zM150.3 89.2l-.2 .3-.4-.1v-.6l.4-.1 .2 .2-.1 .7-.1 .3h-.4M151.7 80.7h1.2v.3h-1.2zM151.7 83.1h1.2v.3h-1.2zM151.7 85.5h1.2v.3h-1.2zM151.7 87.9h1.2v.2h-1.2zM151.7 90.3h1.2v.2h-1.2zM151.7 92.7h1.2v.2h-1.2zM151.7 95.1h1.2v.2h-1.2zM151.7 97.5h1.2v.2h-1.2zM151.7 99.9h1.2v.2h-1.2z"/>
<path d="M268.7 88.4h.4l.3 .2-.3 .3 .3 .2v.3l-.2 .2h-.5zM268.7 88.9h.4M9.4 112.7h1.9M148.1 102.4h3.6M148.1 104.8h3.6M148.1 107.1h3.6M148.1 109.5h3.6M148.1 111.9h3.6M148.1 114.3h3.6M148.1 116.7h3.6M148.1 119.1h3.6M149 101l.4-.3v1.2"/>
<path d="M149 103.4l.4-.3v1.2M149 105.8l.4-.4v1.2M149 108.2l.4-.4v1.2M149 110.6l.4-.4v1.2M149 113l.4-.4v1.2M149 101.9h.7M149 104.3h.7M149 106.6h.7M149 109h.7M149 111.4h.7M149 113.8h.7M149 115.1l.5-.1 .2 .3-.7 .9h.7"/>
<path d="M149 117.5l.5-.1 .2 .3-.7 .9h.7M149 119.9l.5-.1 .2 .3-.7 .9h.7M150.1 107.8h.8l-.5 1.2M150.2 117.7l.3-.3v1.2M150.2 119.9l.4-.1 .3 .3-.8 .9h.8M150.2 118.6h.7M150.3 115.1l.2-.1a.64 .64 0 0 1 .4 .6 .64 .64 0 0 1-.4 .6l-.3-.5zM150.4 110.7l-.2-.2 .2-.3h.2l.3 .3-.3 .2M150.4 110.7l-.2 .3v.3l.2 .1h.2l.3-.2v-.2l-.3-.3M150.4 110.7h.2M150.5 100.6l-.3 .9h.7M150.7 105.4l-.3 .1-.2 .2v.7l.2 .2 .4-.1-.1-.5-.3-.1-.2 .2"/>
<path d="M150.7 101.1v.8M150.8 103.1h-.6v.5h.5l.1 .5-.2 .2-.4-.2M150.9 113.1l-.3 .3-.3-.1-.1-.6 .4-.1 .3 .2-.1 .7-.2 .3h-.3M151.7 102.2h1.2v.3h-1.2zM151.7 104.6h1.2v.3h-1.2zM151.7 107h1.2v.3h-1.2zM151.7 109.4h1.2v.2h-1.2zM151.7 111.8h1.2v.2h-1.2zM151.7 114.2h1.2v.2h-1.2zM151.7 116.6h1.2v.2h-1.2zM151.7 119h1.2v.2h-1.2zM268.1 112.7h1.9"/>
<path d="M10.7 135.5a.54 .54 0 0 0-.7 .5 .54 .54 0 0 0 .7 .5M144.6 131h2.4l-1.2 1.2zM145.8 129.8v1.2M148.1 121.5h3.6M148.1 123.9h3.6M148.1 126.3h3.6M149 122.3l.5-.1 .2 .3-.7 .9h.7M149 124.7l.5-.1 .2 .3-.7 .9h.7M150.1 122.2h.8l-.4 .4 .3 .1v.6l-.2 .1-.5-.1M150.5 124.5l-.3 .9h.7M150.7 125v.8M151.7 121.4h1.2v.2h-1.2z"/>
<path d="M151.7 123.7h1.2v.3h-1.2zM151.7 126.1h1.2v.3h-1.2zM269.4 135.5a.54 .54 0 0 0-.7 .5 .54 .54 0 0 0 .7 .5M9.4 159.7h1.9M268.1 159.7h1.9M166.5 179.9h101.6M268.1 165.3h-101.6v30.1M10 182.4a.62 .62 0 0 1 .7 .6 .62 .62 0 0 1-.7 .7zM33.2 196l.3-.4v1.2M33.2 196.8h.7M56.4 195.4v1.9M80.2 195.7l.5-.1 .2 .4-.8 .8h.8"/>
<path d="M103.5 195.4v1.9M127.2 195.6h.7l-.4 .5 .4 .1v.5l-.2 .1-.5-.1M150.5 195.4v1.9M166.5 192.2h101.6M166.5 189.3h101.6M166.5 185.6h101.6M167.8 183.7h.5M167.8 192.6v1.4M168 193.2l.6 .8M168.5 183h-.7v1.4M168.5 190l-.5-.1-.2 .2v.4l.6 .2 .1 .4-.2 .3-.6-.1M168.5 180.5l-.5-.1-.2 .2v.4l.6 .2 .1 .4-.2 .3-.6-.1"/>
<path d="M168.6 192.6l-.8 .8M169 183v.1M169 183.5v.9M169.1 180.4v1.5M169.1 189.9v.2M169.1 190.4v1M169.1 181l.2-.1 .4 .1v.9M169.2 192.6v.1M169.2 193v1M169.7 190.4h.7l-.7 1h.7M169.7 183v1.2l.2 .2M170.3 183.9l.7-.1-.1-.3h-.4l-.2 .2 .1 .6h.5"/>
<path d="M170.3 181.4l.7-.2-.1-.2-.4-.1-.2 .2 .1 .7h.5M170.7 192.7a.67 .67 0 0 0-1 .5 .67 .67 0 0 0 .7 .8l.3-.1M170.9 190.9l.7-.2-.1-.2-.4-.1-.2 .2v.7h.6M171.3 193.1h.5l.1 .9M171.6 181.4l.6-.2v-.2l-.4-.1-.2 .2v.7h.6M171.6 184.3v.1M171.6 183.5v.2M171.9 193.4h-.5l-.2 .3 .2 .3 .5-.1M172.2 190.5v.1M172.2 191.2v.2M172.6 180.9h.6M172.8 180.4v1.2l.4 .3"/>
<path d="M173.2 193.1l-.4-.1-.3 .3 .1 .6h.6M173.2 192.6v1.4M173.5 191.4l.4-1.5 .5 1.5M173.6 190.9h.7M173.6 181.7v.2M173.6 181v.1M173.7 183.5h-.4l-.2 .2 .1 .6h.5M174.3 183.5h.6l.1 .9M174.6 195.6l-.3 .8h.7M174.7 193.2h.5M174.9 196v.8M175 183.8l-.5 .1-.2 .2 .2 .3 .5-.1"/>
<path d="M175.2 189.9l-.4 1h.9M175.4 192.6h-.7v1.4h.7M175.5 190.4v1M175.6 183.6l.4-.1 .2 .2M175.6 183.5v.9M176 193.9v.1M176.2 183.7l.2-.2h.4v.9M176.2 183.7v.7M176.6 192.6a.71 .71 0 0 1 .8 .7 .71 .71 0 0 1-.8 .7zM177.4 183.9l.7-.1-.1-.3h-.4l-.2 .2 .1 .6h.5M178 193.9v.1M178.5 194l.5-1.4 .5 1.4"/>
<path d="M178.6 193.6h.7M178.7 183.5v.9M179.1 183.5l-.4 .2M179.6 183.5h.5l.1 .9M179.9 193.9v.1M180.2 183.8l-.5 .1-.2 .2 .2 .3 .5-.1M180.9 184.3v.1M181.5 183v1.4M181.7 183.9l.4 .5M182.1 183.5l-.6 .5M182.3 192.6v1.4M182.4 193.4l.4 .6"/>
<path d="M182.7 183v.1M182.7 183.5v.9M182.8 193l-.5 .6M183.4 192.6v.1M183.4 193v1M184 183.5h-.4l-.3 .2 .1 .6h.6M184.6 183.5h.5l.1 .9M184.7 193.1l-.4-.1-.3 .3 .2 .6h.5M185.2 183.8l-.5 .1-.2 .2 .2 .3 .5-.1M185.3 193.1h.6v.9M185.3 189.3v2.9M185.9 193.4h-.5l-.2 .3 .2 .3 .5-.1"/>
<path d="M186.4 183.5h-.4l-.2 .2 .1 .6h.5M186.4 183v1.4M186.8 184.5h1.1M187.2 193.1l-.4-.1-.3 .3 .2 .6h.5M187.2 192.6v1.4M188.5 189.9a.71 .71 0 0 1 .8 .7 .71 .71 0 0 1-.8 .8zM188.7 183.5h-.4l-.2 .2 .1 .2 .5 .1v.3h-.6M189.1 192.4a1.62 1.62 0 0 0 0 2.1M189.5 192.6h1l-.6 1.4M189.9 190.5h.5l.1 .9M189.9 183.5h-.4l-.2 .2 .1 .6h.5M190.5 190.7l-.5 .1-.2 .2 .2 .4 .5-.1"/>
<path d="M190.5 183.6l.2-.1h.4v.9M190.5 183v1.4M191 190.4h.5M191 193.9v.1M191.2 189.9v1.3l.3 .2M191.7 192.7l.2-.1a.75 .75 0 0 1 .5 .7 .75 .75 0 0 1-.5 .7l-.3-.6zM191.9 190.9l.7-.2-.1-.2-.4-.1-.2 .2 .1 .7h.5M193 193.9v.1M193.2 191.2v.2M193.2 190.5v.1M193.8 192.7l.2-.1a.75 .75 0 0 1 .4 .7 .75 .75 0 0 1-.4 .7l-.4-.6zM195 193.4h1.1"/>
<path d="M196.8 192.7l.2-.1a.75 .75 0 0 1 .5 .7 .75 .75 0 0 1-.5 .7l-.3-.6zM197.6 195.4v1.9M198 192.4a1.62 1.62 0 0 1 0 2.1M221.9 195.6h-.5l-.1 .6 .6-.1v.6l-.1 .1-.5-.1M244.6 195.4v1.9M245.5 189.3v6.1M247.8 192.6v1.4M249 193.1l-.4-.1-.2 .3 .1 .6h.5M249 192.6v1.4M249.7 193.9v.1M249.7 193.1v.1M251.8 192.6h-.4a.95 .95 0 0 0 0 1.4l.5-.1 .1-.5-.3-.3-.4 .1-.1 .2"/>
<path d="M253.6 192.5l-1.2 1.8M254.6 192.6h-.4a.95 .95 0 0 0 0 1.4l.5-.1 .1-.5-.3-.3-.4 .1-.1 .2M268.7 182.4a.62 .62 0 0 1 .7 .6 .62 .62 0 0 1-.7 .7zM268.9 195.6l-.3 .1-.2 .2-.1 .7 .3 .2 .4-.1-.1-.6h-.3l-.3 .2"/>
</g>
<path d="M247.8 190.7l.6-.1 .2-.2-.1-.3-.7-.2v1.5M248.1 190.7l.5 .7M249.1 190.9l.7-.2-.1-.2-.4-.1-.2 .2 .1 .7h.5M250.2 190.4l.4 1 .3-1M251.4 191.2v.2M251.4 190.5v.1" fill="none" stroke="#840000" stroke-width=".28"/>
<path d="M167.9 186.1h1.1M168.4 186.1l-.2 1.9M169.5 186.7l-.2 1.3M169.6 186.1v.1M170.1 186.7h.7M170.5 186.1l-.2 1.6v.2l.4 .1M171.6 186.1l-.2 1.6 .2 .3M172.3 187.3l.9-.2v-.3h-.8l-.2 .9 .3 .3 .5-.1M173.9 187.8v.2M174.1 186.8l-.1 .2" fill="none" stroke="#840000" stroke-width=".38"/>
<g fill="#ffffc2" stroke="#ffffc2" stroke-width=".35">
<path d="M106.3 51.6h9.6v8.9h-9.6z" fill-rule="evenodd"/>
<path d="M151.7 70.1h2.4v57.4h-2.4z" fill-rule="evenodd"/>
</g>
<path d="M106.3 51.6h9.6v8.9h-9.6zM151.7 70.1h2.4v57.4h-2.4z" fill="none" stroke="#840000" stroke-width=".24"/>
<path d="M147.6 70.7l1.1 1.2M148.7 70.7l-1.1 1.2M147.6 125.7l1.1 1.1M147.6 123.3l1.1 1.1M148.7 125.7l-1.1 1.1M148.7 123.3l-1.1 1.1" fill="none" stroke="#000084" stroke-width=".2"/>
<g fill="none" stroke="#008400" stroke-width=".2">
<path d="M98 59.4v3.5h23.9v-3.5M102.7 53.4v2.4h1.2M103.9 53.4h-5.9v1.2M118.3 53.4h26.3v41.8h3.5M121.9 53.4v1.2M142.2 48.6v44.2h5.9M132.6 76.1h15.5M144.6 78.5h3.5M148.1 73.7h-2.3v56.1M132.6 97.6h15.5M132.6 88h15.5M132.6 90.4h15.5"/>
<path d="M132.6 100h15.5M132.6 85.6h15.5M132.6 83.2h15.5M132.6 80.9h15.5M132.6 116.7h15.5M132.6 119.1h15.5M132.6 114.3h15.5M132.6 107.1h15.5M132.6 111.9h15.5M132.6 102.4h15.5M132.6 109.5h15.5M145.8 104.8h2.3"/>
<path d="M132.6 121.5h15.5"/>
</g>
<g fill="none" stroke="#0000c2" stroke-width=".2">
<path d="M148.3 57.9h.8l-.4 .5 .3 .1v.5l-.2 .1-.5-.1M148.4 56.1l.4-.1 .3 .3-.8 .9h.8M148.4 55.2h.7M148.4 54.4l.3-.4v1.2M148.4 52.3l.3-.2a.4 .4 0 0 1 .5 .4v.4a.4 .4 0 0 1-.4 .4 .4 .4 0 0 1-.4-.4zM148.6 53l.6 .4M149.5 53.9a1.37 1.37 0 0 1 0 1.8M149.5 55.8a1.37 1.37 0 0 1 0 1.8M149.5 57.7a1.37 1.37 0 0 1 0 1.8M149.7 52.5v.7h.5M150.2 52.5v.8M150.7 52.9l.6-.1-.1-.3h-.3l-.2 .2 .1 .5h.4"/>
<path d="M150.9 57.2l.4-1.2 .4 1.2M150.9 57.9l.4 1.2 .4-1.2M151 56.8h.6M151.1 54v1.2M152.1 54.5l-.3-.1-.2 .2 .1 .2 .4 .1v.3h-.5M152.1 58.4l.2-.1 .3 .1v.6h-.5zM152.1 56.4v.8M152.2 52.5h-.3l-.2 .2 .1 .1 .4 .1v.3h-.5M152.4 56.4l-.3 .2M152.6 52.5h.4M152.8 52.1v1l.2 .2M152.8 56.8l.6-.2-.1-.2h-.3l-.2 .1v.6h.5"/>
<path d="M153.2 58.4h.4l.1 .7M153.2 57.9v1.2M153.3 54v.1M153.3 54.4v.8M153.4 52.1v.1M153.4 52.5v.8M153.7 54.4h.5M153.9 54v1l.3 .2M154 52.6l.2-.1 .3 .1v.6h-.5zM154.4 56.4h.5M154.6 56v1l.3 .2M155 57.9v.1"/>
<path d="M155 58.3v.8M155.1 52.6l.4-.1 .1 .8M155.1 52.5v.8M155.3 56.5l.4-.1 .1 .8M155.3 56v1.2M155.3 54.4v.8M155.6 54.4l-.3 .3M156 58.4l-.3-.1-.2 .2 .1 .1 .4 .1v.3h-.5M156 54.8l.6-.1-.1-.2-.3-.1-.2 .2v.6h.5M156.3 56.8l.6-.2-.1-.2h-.3l-.2 .1 .1 .6h.4M156.6 52.5h-.3l-.2 .2 .1 .1 .4 .1v.3h-.5M157.1 54.5h.4l.1 .7"/>
<path d="M157.1 53.2v.1M157.1 52.5v.2M157.3 58l.2-.1a.64 .64 0 0 1 .4 .6 .64 .64 0 0 1-.4 .6l-.3-.5zM157.6 54.7l-.6 .2 .2 .3h.4M158.1 56v.1M158.1 56.4v.8M158.4 59v.1M158.5 54.5l-.2-.1-.2 .2 .1 .2 .3 .1v.3h-.4M158.7 56.5l.4-.1 .1 .8M158.7 56.4v.8M159.1 58.4l-.2 .2v.4l.2 .1h.2l.3-.2v-.3l-.3-.2M159.1 54.5l.2-.1 .3 .1v.7l-.5-.1z"/>
<path d="M159.1 58.4l-.2-.2 .2-.3h.2l.3 .2-.3 .3M159.1 58.4h.2M159.7 56.4h.4l.2 .2-.1 .5h-.5M159.7 56.4v1.2M160.2 54.5h.5v.7M160.2 54.4v.8M160.7 58.1l.3 .1M160.8 56.4l.1 .7 .4-.1M161 57.9v.3M161 58.2l-.2 .2M161 58.2l.1 .2M161.3 58.1l-.3 .1"/>
<path d="M161.3 54.5h.4l.1 .7M161.3 56.4v.8M161.7 56.4h.5M161.8 54.7l-.6 .2 .2 .3h.4M161.9 56v1l.3 .2M162.3 57.9l.4 1.2 .4-1.2M162.4 54.5l.3-.1 .2 .3-.1 .5h-.4M162.4 54v1.2M163.3 56.4h.3l.3 .2-.1 .5h-.5M163.3 56.4v1.2M163.4 54v1l.2 .2M164 58.4l-.4-.1-.2 .2 .1 .5h.5"/>
<path d="M164 57.9v1.2M164 54.8l.6-.1-.1-.2-.3-.1-.2 .2 .1 .6h.4M164.4 56v.1M164.4 56.4v.8M165 56.5l.4-.1 .1 .8M165 56.4v.8M165 58.4l-.3-.1-.2 .2 .1 .5h.4M165 57.9v1.2M165.6 57.9v1.2M165.6 54.4h.5M165.8 54v1l.3 .2M166.2 58.1l.2-.2a.4 .4 0 0 1 .5 .4v.4a.4 .4 0 0 1-.4 .4 .4 .4 0 0 1-.4-.4z"/>
<path d="M166.4 56.4h-.3l-.1 .1v.2l.4 .1v.3h-.4M166.5 54.5l.2-.1 .3 .1-.1 .7-.4-.1zM167.6 56h.7l-.4 .4 .4 .1v.5l-.2 .2-.5-.2M168.2 58.4l.1-.1 .4 .1-.1 .6h-.4zM168.3 54.4v.8M168.6 54.4l-.3 .3M168.9 57v.2M169 54.4l.1 .8 .4-.1M169.2 58.3v.8M169.3 56h.8l-.4 .4 .3 .1v.5l-.2 .2-.5-.2M169.5 54.4v.8M169.6 58.3l-.4 .2"/>
<path d="M170.1 54.5h.5v.7M170.1 54.4v.8M170.5 56.4l.2 .8 .3-.8M170.6 59.1h.7M170.6 58.2l.4-.3v1.2M171.7 55.2l.4-1.2 .4 1.2M171.8 59v.1M171.8 54.9h.6M172.6 57.8l-.3 .9h.8M172.7 56.4h-.3l-.3 .2 .1 .5h.5M172.8 54l.4 1.2 .4-1.2M172.9 58.3v.8"/>
<path d="M173.2 56.5l.2-.1 .3 .1v.6l-.5-.1zM173.8 57.8l-.3 .9h.7M174 54a.6 .6 0 0 1 .6 .6 .6 .6 0 0 1-.6 .6zM174 58.3v.8M174.3 56.5l.3-.1 .2 .1M174.3 56.4v.8M174.6 58.3l.2 .8 .3-.8M174.8 56.5l.2-.1h.3v.8M174.8 56.5v.7M175.1 54a.6 .6 0 0 1 .7 .6 .6 .6 0 0 1-.7 .6zM175.9 56.4h.3l.3 .2-.2 .5h-.4M175.9 56.4v1.2"/>
<path d="M177 56v1l.1 .2M177.1 54.5h.4l.1 .7M177.6 54.7l-.6 .2 .2 .3h.4M177.6 56v.1M177.6 56.4v.8M178 54.4h.4M178.1 54v1l.3 .2M178.2 56.4h.4l.1 .8M178.7 56.6l-.6 .3 .2 .3 .4-.1M179.2 56.5l.5-.1 .1 .8M179.2 56.4v.8M179.4 54h.8l-.4 .5 .3 .1v.5l-.2 .1-.5-.1"/>
<path d="M180.2 56.4h.4M180.3 56v1l.3 .2M180.7 55.1v.1M181 56h.4a.4 .4 0 0 1-.2 .6v.1M181.1 54h.8l-.4 .5 .3 .1v.5l-.2 .1-.5-.1M181.2 57v.2M182.3 54.4l.3 .8 .2-.8M183.2 54.1l.4-.1a.4 .4 0 0 1-.1 .7v.1M183.5 55.1v.1M169.8 170.7l.2 .6M169.9 172.3h.3l.1 .6M169.9 171.9v1"/>
<path d="M169.9 173.4v1M169.9 177.4l.4-.1-.1-.5h-.3v.9M169.9 173.8h.3l.1 .6M170 171.3l-.2 .3M170.2 170.7l-.2 .6M170.4 169a.42 .42 0 0 0-.6 .3 .42 .42 0 0 0 .6 .4M170.4 175a.42 .42 0 0 0-.6 .4 .42 .42 0 0 0 .6 .4M170.6 170.8h.4v.5l-.4-.1zM170.6 172.2h.4M170.7 177.1l.4-.1v-.2h-.3l-.1 .1v.5h.4M170.7 171.9v.8l.3 .2M170.7 173.8h.4v.6"/>
<path d="M170.8 169.3h.4v.5l-.4-.1zM170.8 175.1l.2-.1 .4 .1v.5l-.1 .3-.5-.1zM171.1 172.2h.4M171.1 174l-.4 .2 .1 .2 .3-.1M171.3 171.9v.8l.2 .2M171.4 170.7l.1 .6 .3-.1M171.5 176.8v.6M171.6 173.7v.7M171.7 169.2h.2l.2 .2-.1 .4h-.3M171.7 169.2v.9M171.8 172.3l.3-.1 .2 .2-.1 .4h-.4M171.8 172.2v1"/>
<path d="M171.8 176.8l-.3 .2M171.8 170.7v.6M171.8 173.7l-.2 .2M172.1 176.8v.6M172.1 176.9l.3-.1 .1 .1M172.3 175v.9l-.5-.9v.9M172.4 169.2l.3 .6M172.5 176.9l.4-.1v.6M172.5 176.9v.5M172.6 173.8l-.3-.1-.2 .2 .1 .4h.4M172.6 173.4v1M172.7 172.9h.1"/>
<path d="M172.7 172.3v.1M172.7 169.8l-.3 .3M172.7 172.8v.1M172.8 175a.48 .48 0 0 1 .5 .4 .48 .48 0 0 1-.5 .5zM172.9 170.8l.2-.1 .2 .1M172.9 170.7v.6M172.9 169.2l-.2 .6M172.9 173.7l.2 .7 .2-.5 .2 .5 .1-.7M173.2 169.2v.6M173.3 170.8l.3-.1 .1 .6M173.3 170.8v.5M173.4 176.5v.1"/>
<path d="M173.4 176.8v.6M173.5 169.2l-.3 .2M173.7 175v.9M173.8 171.9l-.8 1.2M173.8 168.9v.1M173.8 169.2v.6M174 173.8h.4v.6M174 175h.6M174.1 170.7h.4v.6M174.1 176.8h-.2l-.1 .2 .4 .2M174.2 177.3l-.2 .1h-.2M174.2 177.2v.1"/>
<path d="M174.3 175v.9M174.4 174l-.4 .2 .1 .2 .3-.1M174.5 170.9l-.4 .2 .1 .2h.3M174.7 169.2h-.3l-.2 .2 .1 .4h.4M174.7 169.2v.7l-.2 .2h-.2M174.8 171.9l-.8 1.2M174.9 173.7v.7M174.9 170.7l.2 .6M174.9 176.8h-.2l-.2 .2 .4 .2M174.9 175v.9M174.9 177.3l-.1 .1h-.3M174.9 177.2v.1"/>
<path d="M175 172.4l.4 .3-.1 .2-.3-.1M175 172.4h.1M175.1 171.3l-.2 .3M175.1 169.3l.4-.1v.6M175.1 168.9v.9M175.1 173.7l-.2 .2M175.3 170.7l-.2 .6M175.3 176.5v.1M175.3 176.8v.6M175.3 175.1l.2-.1 .4 .1v.5l-.1 .3-.5-.1zM175.4 174.1l.4-.1v-.2l-.3-.1-.1 .2v.4h.4M175.4 172.3l-.4 .1"/>
<path d="M175.8 176.9h.4l-.1 .5-.3-.1zM175.8 172.3h.4v.5h-.4zM175.8 169.2h.4M176 168.9v.8l.2 .1M176.2 170.8l.4-.1 .1 .6M176.2 170.7v.6M176.6 176.9l.4-.1v.6M176.6 176.8v.6M176.7 171.9v.8l.1 .2M176.8 173.8h.4v.6M176.9 175v.9l-.6-.9v.9M177.1 169.2h.3l.1 .6"/>
<path d="M177.1 170.8h.4v.5l-.4-.1zM177.2 174l-.4 .2 .1 .2 .3-.1M177.5 169.4l-.5 .2 .2 .2h.3M177.6 171.9v.9h-.4v-.5h.4M177.7 173.8h.3l.1 .6M177.7 173.7v.7M177.8 175h-.5a.39 .39 0 0 0 .5 .5l-.1 .4h-.4M177.8 176.8h-.2l-.2 .2 .5 .2M177.8 170.7h.4M177.9 177.3l-.2 .1h-.3M177.9 177.2v.1M177.9 169.3l.4-.1v.6"/>
<path d="M177.9 169.2v.6M178 170.4v.8l.2 .1M178 172.5l.4-.1v-.1l-.3-.1-.1 .2v.4h.4M178.8 175.1l.2-.1 .3 .1 .1 .5-.2 .3-.4-.1zM178.8 176.8h.4v.6M178.8 172.2v.7M178.9 173.8l-.3-.1-.1 .2 .1 .4h.3M178.9 173.4v1M179.1 170.7v.6l.4-.1M179.1 172.2l-.3 .2M179.2 169.2h-.3l-.2 .2 .1 .4h.4M179.2 168.9v.9"/>
<path d="M179.2 177l-.4 .2 .1 .2h.3M179.4 172.3l.3-.1 .2 .2-.1 .4h-.4M179.4 172.2v1M179.5 170.7v.6M179.7 176.9l.3-.1 .1 .6M179.7 176.8v.6M179.8 175.4h.3M179.9 173.8l.3-.1 .1 .2M179.9 173.7v.7M180.2 169.2v.6M180.2 175h-.4v.9M180.2 170.7l-.3 .1 .3 .3v.2h-.3"/>
<path d="M180.3 172.3l.2-.1 .2 .2v.4l-.3 .1-.1-.4 .4-.1M180.3 173.9l.4-.1v.6M180.3 173.9v.5M180.5 169.2l-.3 .2M180.6 171l.5-.1-.1-.2h-.2l-.2 .1 .1 .5h.3M180.7 169.5l.5-.1-.1-.2h-.2l-.2 .1 .1 .5h.3M180.9 176.8h-.2l-.2 .2 .1 .4h.3M180.9 176.5v.9M181 175.9l.3-.9 .3 .9M181.1 175.6h.4M181.2 173.8h.3l.1 .6M181.5 171.9v.9h-.3l-.1-.5h.4"/>
<path d="M181.6 168.9v.8l.1 .1M181.6 174l-.5 .2 .2 .2 .3-.1M181.9 173.7h.4M181.9 170.7h.4M181.9 176.5v.8l.2 .1M182 172.8v.1M182 173.4v.8l.3 .2M182 170.4v.8l.3 .1M182.1 169.2h.3l.1 .6M182.4 172.3h.4v.5h-.4zM182.4 176.5v.1M182.4 176.8v.6"/>
<path d="M182.5 175v.9l-.6-.9v.9M182.5 169.4l-.5 .2 .2 .2h.3M182.5 174.1l.5-.1-.1-.2-.2-.1-.2 .2 .1 .4h.3M182.6 170.8l.3-.1 .1 .6M182.6 170.4v.9M182.8 175l.3 .5M182.8 169.2h.3M182.9 176.9l.2-.1 .2 .1M182.9 176.8v.6M182.9 168.9v.8l.2 .1M183.1 175.5v.4M183.3 172.2v.7"/>
<path d="M183.3 176.9v.5M183.3 176.9l.3-.1 .1 .6M183.4 173.7v.7M183.4 175l-.3 .5M183.4 169.5l.5-.1-.1-.2h-.3l-.1 .1 .1 .5h.3M183.4 170.4v.1M183.4 170.7v.6M183.5 172.2l-.2 .2M183.6 173.7l-.2 .2M184 173.4v.1M184 173.7v.7M184.1 176.5v.1"/>
<path d="M184.1 176.8v.6M184.2 170.7l-.4 .1 .4 .3v.2h-.4M184.3 172.2v.8l-.2 .2-.2-.1M184.3 172.3l-.3-.1-.2 .2 .1 .4h.4M184.3 175v.9M184.4 173.8h.4v.6M184.4 175.4l.4 .5M184.4 176.8h.4M184.6 176.5v.8l.2 .1M184.7 169.2h-.3l-.2 .2 .1 .4h.4M184.7 168.9v.9M184.8 174l-.4 .2 .1 .2 .3-.1"/>
<path d="M184.8 175l-.5 .5M185.1 170.7h.3M185.1 176.8h.4v.6M185.2 175v.9M185.3 173.4v.8l.1 .2M185.4 171.9l-.8 1.2M185.4 170.4l-.2 .1v.8M185.5 177l-.4 .2 .1 .2h.3M185.7 169.2v.6M185.7 171.9v.8l.1 .2M185.7 170.4v.1M185.7 170.7v.6"/>
<path d="M185.8 176.8h.4M186 169.2l-.3 .2M186 176.5v.8l.2 .1M186.1 173.8l-.4 .1 .4 .2v.2h-.4M186.2 170.4v.8l.1 .1M186.2 171.9v.1M186.2 172.2v.7M186.2 175v.9l-.5-.9v.9M186.3 168.9v.1M186.3 169.2v.6M186.5 176.5v.1M186.5 176.8v.6"/>
<path d="M186.6 171l.5-.1-.1-.2h-.2l-.2 .1 .1 .5h.3M186.7 175a.48 .48 0 0 1 .5 .4 .48 .48 0 0 1-.5 .5zM187 176.9h.4l-.1 .5-.3-.1zM187 172.3l-.2-.1-.2 .2 .1 .4h.3M187.1 169.2h-.3l-.1 .2 .1 .4h.3M187.1 169.2v.7l-.2 .2h-.2M187.4 172.5l.4-.1v-.1l-.3-.1-.1 .2v.4h.4M187.5 173.8l-.3-.1-.2 .2 .1 .4h.4M187.5 173.4v1M187.6 169.3l.3-.1 .1 .6M187.6 168.9v.9M187.7 175.9l-.1 .1"/>
<path d="M187.8 176.9l.4-.1v.6M187.8 176.8v.6M187.9 173.4v.1M187.9 173.7v.7M188 171l.5-.1-.1-.2h-.3l-.1 .1v.5h.4M188.2 172.3h.4v.6M188.2 172.2v.7M188.3 169.2h.3M188.4 168.9v.8l.2 .1M188.6 175.6l.4-.1v-.2h-.3l-.1 .1v.5h.4M188.7 173.8l-.4 .1 .4 .2v.2h-.4M188.8 170.7l.5 .6"/>
<path d="M189 176.8h-.3l-.1 .2 .4 .2M189 173.7h.4M189 177.3l-.1 .1h-.3M189 177.2v.1M189.1 172.4l.4 .3-.2 .2-.2-.1M189.1 172.4h.1M189.1 173.4v.8l.3 .2M189.3 170.7l-.5 .6M189.3 169.2l-.4 .1 .4 .2v.3h-.4M189.4 172.3l-.3 .1M189.4 175h.1M189.4 175.3v.6"/>
<path d="M189.7 173.7v.7M189.7 175.3h.4M189.8 172.5l.5-.1-.1-.1-.3-.1-.1 .2 .1 .4h.3M189.9 175v.8l.2 .1M189.9 173.7l-.2 .2M190 176.8v.6l.4-.1M190 170.7h-.3l-.1 .2 .1 .4h.3M190.3 173.4v.1M190.3 173.7v.7M190.3 169.2h.3l.1 .6M190.4 171l.4-.1v-.2h-.3l-.1 .1v.5h.4M190.4 176.8v.6"/>
<path d="M190.4 175.4l.4-.1v.6M190.4 175v.9M190.6 172.4l.4 .3-.1 .2-.3-.1M190.6 172.4h.1M190.7 169.4l-.5 .2 .2 .2h.3M190.7 173.8l.3-.1 .1 .2v.4h-.4M190.7 173.4v1M190.8 176.8v.6M190.8 176.9l.4-.1v.6M191 172.3l-.4 .1M191.1 169.2v.6M191.2 175.6l.5-.1-.1-.2h-.2l-.2 .1 .1 .5h.3"/>
<path d="M191.2 170.7h.3l.2 .2-.1 .4h-.4M191.2 170.7v.9M191.4 169.2l-.3 .2M191.6 173.7v.6h.4M191.7 169.5l.4-.1v-.2h-.3l-.1 .1v.5h.4M191.9 170.7h.4M192 173.7v.7M192.1 175.3v.6M192.1 170.4v.8l.2 .1M192.1 176.8h-.3l-.2 .2 .1 .4h.4M192.1 176.5v.9M192.1 171.9l-.8 1.2"/>
<path d="M192.3 173.7h.3M192.3 175.3l-.2 .2M192.4 173.4v.8l.2 .2M192.5 177.1l.4-.1v-.2h-.3l-.1 .1v.5h.4M192.9 174.1l.4-.1v-.2l-.3-.1-.1 .2v.4h.4M192.9 172h-.5a.39 .39 0 0 0 .5 .5l-.1 .3h-.4M193.1 168.9v.8l.1 .1M193.2 175.6l.4-.1v-.2h-.3l-.1 .1v.5h.4M193.2 170.4v.1M193.2 170.7v.6M193.3 171.9v1M193.3 172.4h.5"/>
<path d="M193.3 176.8v.6M193.6 168.9v.1M193.6 169.2v.6M193.6 176.8l-.3 .2M193.6 170.8l.4-.1v.6M193.6 170.7v.6M193.8 171.9v1M193.9 175.3l.5 .6M194.1 173.8l-.2-.1-.2 .2 .1 .4h.3M194.1 173.4v1M194.3 171.9v1h.4M194.4 176.8h.3"/>
<path d="M194.4 175.3l-.5 .6M194.4 169.2h-.2l-.2 .2 .1 .4h.3M194.5 176.5v.8l.2 .1M194.8 175.3v.9M194.8 175.3h.3l.1 .2-.1 .4h-.3M194.8 169.5l.4-.1v-.2h-.3l-.1 .1v.5h.4M195 176.9l.4-.1v.6M195 176.5v.9M195.1 172.5h.7M195.2 173.7v.6h.4M195.4 170.7h-.2l-.2 .2 .1 .4h.3M195.6 173.7v.7"/>
<path d="M195.6 175.3v.6M195.6 169.3l.4-.1v.6M195.6 169.2v.6M195.8 177.1l.5-.1-.1-.2h-.2l-.2 .1 .1 .5h.3M195.9 170.8h.4l-.1 .5-.3-.1zM195.9 175.3l-.3 .2M196 173.7v.7M196 173.8h.4v.6M196.2 175.6l.4-.1v-.2h-.3l-.1 .1v.5h.4M196.2 172l.3-.1 .2 .3-.6 .7h.6M196.7 170.8l.3-.1 .1 .1M196.7 170.7v.6"/>
<path d="M196.8 169.2l-.4 .1 .4 .2v.3h-.4M197.1 170.8l.4-.1v.6M197.1 170.8v.5M197.1 172.8v.1M197.2 169.5l.5-.1-.1-.2h-.3l-.1 .1v.5h.4M197.2 176.5v.9h.5M197.3 173.8l-.3-.1-.2 .2 .1 .4h.4M197.3 173.4v1M197.3 175.3l-.3 .1 .3 .2v.3h-.3M197.5 172.9h.6M197.5 172.2l.3-.3v1M197.7 174.1l.4-.1v-.2l-.3-.1-.1 .2v.4h.4"/>
<path d="M198 170.7h.2l.2 .2-.1 .4h-.3M198 170.7v.9M198 176.5v.1M198 176.8v.6M198.1 175.3l-.4 .1 .4 .2v.3h-.4M198.5 169.2h-.3l-.2 .2 .1 .4h.4M198.5 168.9v.9M198.5 172.8v.1M198.5 173.7v.7M198.8 173.7l-.3 .2M198.8 170.4v.8l.1 .1M198.9 176.8h-.3l-.2 .2 .1 .4h.4"/>
<path d="M199.1 175.4h.4v.5l-.4-.1zM199.2 177.1l.5-.1-.1-.2h-.2l-.2 .1 .1 .5h.3M199.3 170.4v.1M199.3 170.7v.6M199.5 169.2v.6l.4-.1M199.5 171.9v.8l.1 .2 .4-.2v-.8M199.5 173.7h.4M199.7 173.4v.8l.2 .2M199.7 170.7h.4l.1 .6M199.9 169.2v.6M200 175.3v.6M200.1 176.9l.3-.1 .1 .6"/>
<path d="M200.1 176.8v.6M200.2 170.9l-.5 .2 .1 .2h.4M200.2 173.8h.4v.6M200.2 173.4v1M200.2 175.3l-.2 .2M200.3 169.3l.4-.1v.6M200.3 169.2v.6M200.5 172.3h.3l.1 .6M200.5 172.2v.7M200.6 170.8l.4-.1v.6M200.6 170.7v.6M201.1 173.4v.1"/>
<path d="M201.1 173.7v.7M201.1 175h.1M201.1 175.3v.6M201.2 176.8h-.2l-.1 .2 .4 .2M201.3 177.3l-.2 .1h-.2M201.3 177.2v.1M201.3 171.9v.8l.1 .2M201.6 175.3v.6M201.6 175.4l.2-.1 .2 .1M201.6 169.2h-.3l-.2 .2 .1 .4h.4M201.6 168.9v.9M201.6 177.1l.5-.1-.1-.2h-.2l-.2 .1 .1 .5h.3"/>
<path d="M201.8 172.5l.4-.1v-.1l-.3-.1-.1 .2v.4h.4M201.8 173.8l-.3 .1 .3 .2v.2h-.3M201.9 170.7h-.3l-.2 .2 .1 .4h.4M202 175.4v.5M202 175.4l.3-.1 .1 .6M202 169.5l.4-.1v-.2h-.3l-.1 .1v.5h.4M202.2 171l.5-.1-.1-.2h-.3l-.1 .1 .1 .5h.3M202.5 177.3v.1M202.6 172.4l.4 .3-.2 .2-.2-.1M202.6 172.4h.1M202.8 175.3v.9M202.8 175.3h.3l.2 .2-.1 .4h-.4"/>
<path d="M202.8 169.2v.6M202.8 173.4v1h.5M202.9 172.3l-.3 .1M203.1 169.2l-.3 .2M203.3 172.4l.4 .3-.1 .2-.3-.1M203.3 172.4h.1M203.5 170.7l.2 .6 .2-.4 .2 .4 .2-.6M203.6 173.4v.1M203.6 173.7v.7M203.7 175v.8l.1 .1M203.7 172.3l-.4 .1M203.8 169.2h.4"/>
<path d="M204 168.9v.8l.2 .1M204.2 175h.1M204.2 175.3v.6M204.4 173.8l-.2-.1-.2 .2 .1 .4h.3M204.5 169.3l.4-.1v.6M204.5 168.9v.9M204.6 175.6l.4-.1v-.2h-.3l-.1 .1v.5h.4M204.6 170.4v.1M204.6 170.7v.6M204.7 172.2v.7M204.8 174.1l.4-.1v-.2l-.3-.1-.1 .2v.4h.4M204.9 170.7h.4"/>
<path d="M205 172.2l-.3 .2M205.1 170.4v.8l.2 .1M205.2 172.5l.5-.1-.1-.1-.2-.1-.2 .2 .1 .4h.3M205.3 169.5l.5-.1-.1-.2h-.2l-.2 .1 .1 .5h.3M205.6 170.8l.4-.1v.6M205.6 170.4v.9M205.7 173.8h.3l.1 .6M205.7 173.7v.7M205.8 175.3h-.3l-.1 .2 .1 .4h.3M205.8 175v.9M206.3 175.8v.1M206.5 172.3l-.3-.1-.2 .2 .1 .4h.4"/>
<path d="M206.5 172.2v1M206.8 173.8l-.3 .1 .3 .2v.2h-.3M206.9 170.7h.3M206.9 172.2l.1 .6h.3M207 170.4v.8l.2 .1M207.2 174.1l.5-.1-.1-.2-.2-.1-.2 .2 .1 .4h.3M207.2 168.9l-.5 .1a.39 .39 0 0 0 .5 .4l-.1 .4h-.4M207.3 172.2v.7M207.6 170.8l.3-.1 .1 .6M207.6 170.4v.9M207.6 169.3h.4v.5h-.3zM207.6 169.7l.1 .1"/>
<path d="M207.8 175h-.5a.39 .39 0 0 0 .4 .5v.4h-.5M207.8 171.9v.1M207.8 172.2v.7M208.1 175.6l.5-.1-.1-.2h-.2l-.2 .1 .1 .5h.3M208.2 172.2v.7M208.4 171l.4-.1v-.2h-.3l-.1 .1v.5h.4M208.5 168.9v.8l.1 .1M208.5 172.2l-.3 .2M208.6 173.4v.1M208.6 173.7v.7M208.8 172.5l.4-.1v-.1l-.3-.1-.1 .2v.4h.4M208.9 175.6l.5-.1-.1-.2h-.2l-.2 .1 .1 .5h.3"/>
<path d="M209 169.7v.1M209 169.8h.4M209.4 169.2l-.4 .1v.4M209.4 168.9v.9M209.4 173.8l-.4 .1 .4 .2v.2h-.4M209.8 170.4v.9h.4M209.8 169.5l.4-.1v-.2h-.3l-.1 .1v.5h.4M210 171.9v.9h-.3l-.1-.5h.4M210.2 175.3h.4M210.3 175v.8l.3 .1M210.5 170.4v.1M210.5 170.7v.6"/>
<path d="M210.6 169.2v.6M210.8 173.8l-.3-.1-.1 .2 .1 .4h.3M210.8 173.4v1M210.9 175.4l.3-.1 .1 .6M210.9 175v.9M210.9 169.2l-.3 .2M211 171.9v.9h.4v-.5h-.4M211.2 169.8h.4M211.2 169.2l.4 .1v.4M211.2 169.2v.9M211.3 173.4v.1M211.3 173.7v.7"/>
<path d="M211.4 170.7h-.3l-.2 .2 .1 .4h.4M211.6 169.7v.1M211.7 175.6l.4-.1v-.2h-.3l-.1 .1v.5h.4M211.7 171l.5-.1-.1-.2h-.2l-.2 .1 .1 .5h.3M211.8 172.2l.2 .7M212 172.9l-.2 .3M212 173.8l-.3 .1 .3 .2v.2h-.3M212.1 169.2h.3l.1 .6M212.2 172.2l-.2 .7M212.3 173.7h.4M212.5 173.4v.8l.2 .2M212.5 169.4l-.5 .2 .2 .2h.3"/>
<path d="M212.6 170.8l.4-.1v.6M212.6 170.7v.6M212.9 169.7l.1 .1M213 169.8h.3M213 173.7v.7M213.1 175v.9h.5M213.2 172.3l.2-.1 .2 .2v.5h-.3l-.1-.4 .4-.1M213.3 173.7l-.3 .2M213.3 169.2l-.4 .1v.4M213.3 168.9v.9M213.6 173.4v.1M213.6 173.7v.7"/>
<path d="M213.8 170.7l-.4 .1 .4 .3v.2h-.4M213.9 175h.1M213.9 175.3v.6M214 172.3l.3-.1 .2 .2-.1 .4h-.4M214 172.2v1M214 173.8l.3-.1 .2 .2-.1 .4h-.4M214 173.4v1M214.2 171l.4-.1v-.2h-.3l-.1 .1v.5h.4M214.3 168.9v.9M214.3 169.3h.6M214.7 175.3h-.2l-.2 .2 .1 .4h.3M214.9 172.2v1"/>
<path d="M214.9 172.3l.2-.1 .2 .2-.1 .4h-.3M214.9 168.9v.9M214.9 173.7v.6h.4M215 171.2v.1M215.1 175.6l.4-.1v-.2h-.3l-.1 .1v.5h.4M215.3 173.7v.7M215.3 169.2h.4v.6M215.6 173.7h.4M215.7 171.9v.8l.2 .2M215.7 169.4l-.4 .2 .1 .2h.3M215.7 173.4v.8l.3 .2M215.9 175.4l.4-.1v.6"/>
<path d="M215.9 175.3v.6M216.2 169.2v.6M216.2 172h.1M216.2 172.2v.7M216.2 174.1l.5-.1-.1-.2-.2-.1-.2 .2 .1 .4h.3M216.3 172h-.1M216.4 169.2l-.2 .2M216.5 170.4l.3 .5M216.8 170.9v.4M217.1 172.3l-.3-.1-.2 .2 .1 .4h.4M217.1 170.4l-.3 .5M217.1 175.3l-.4 .1 .4 .2v.3h-.4"/>
<path d="M217.2 169.2h-.3l-.2 .2 .1 .4h.4M217.2 168.9v.9M217.4 170.8h.4v.5l-.4-.1zM217.5 172.3l.2-.1 .2 .2v.4l-.3 .1-.1-.4 .4-.1M217.5 173.8l-.3-.1-.2 .2 .1 .4h.4M217.5 173.4v1M217.5 175.6l.4-.1v-.2h-.3l-.1 .1v.5h.4M217.5 169.2l.2 .6 .2-.4 .2 .4 .1-.6M218.2 170.7l.1 .6 .4-.1M218.3 171.9v.9h.4v-.5h-.4M218.5 173.8h.4v.5h-.4zM218.6 169.2h.3l.1 .6"/>
<path d="M218.7 170.7v.6M218.8 175.3h.3M219 169.4l-.5 .2 .2 .2h.3M219.1 175l-.2 .1v.8M219.2 171.9v.8l.1 .2M219.4 173.8h.3l.1 .6M219.4 173.7v.7M219.4 169.2v.6M219.4 175.4h.5l-.1 .5-.4-.1zM219.6 172.5l.5-.1-.1-.1-.2-.1-.2 .2 .1 .4h.3M219.7 170.8l.2-.1 .2 .1M219.7 170.7v.6"/>
<path d="M219.7 169.2l-.3 .2M220 169.5l.4-.1v-.2h-.3l-.1 .1v.5h.4M220.1 170.8l.3-.1 .1 .6M220.1 170.8v.5M220.3 175.3v.6M220.6 175.3l-.3 .2M220.8 173.8h.3l.1 .6M220.9 170.7h.4v.6M221 171.9v.8l.2 .2M221.2 174l-.5 .2 .2 .2 .3-.1M221.3 175.3h.4M221.3 170.9l-.4 .2 .1 .2h.3"/>
<path d="M221.4 168.9v.9h.4M221.4 175v.8l.3 .1M221.5 172.3l.3-.1 .1 .2v.4l-.3 .1-.1-.4 .4-.1M221.6 173.8h.4v.6M221.6 173.7v.7M221.7 170.7l.2 .6M221.9 171.3l-.2 .3M222 175.4l.3-.1 .1 .6M222 175v.9M222.1 170.7l-.2 .6M222.2 168.9v.1M222.2 169.2v.6"/>
<path d="M222.3 172.2l.2 .7 .1-.5 .2 .5 .2-.7M222.8 175.6l.4-.1v-.2h-.3l-.1 .1v.5h.4M223 173.4v.2M223 169.2h-.3l-.1 .2v.4h.4M223.1 170.8h.4l-.1 .5-.3-.1zM223.3 173.4v.2M223.4 169.5l.4-.1v-.2h-.3l-.1 .1v.5h.4M223.6 174.4l.3-1 .3 1M223.7 174.1h.5M223.9 170.7h.3l.2 .2-.1 .4h-.4M223.9 170.4v.9M223.9 172.3h.4v.5h-.4z"/>
<path d="M224.2 169.3l.4-.1v.6M224.2 169.2v.6M224.5 175.3l-.3 .1 .3 .2v.3h-.3M224.6 170.7h.4M224.8 170.4v.8l.2 .1M224.8 172.2v.7M225 175.3h.2l.2 .2-.1 .4h-.3M225 175.3v.9M225 172.2l-.2 .2M225 173.5h-.4a.39 .39 0 0 0 .4 .5v.3h-.5M225.3 170.7h.3l.1 .6M225.4 169.2l-.4 .1 .4 .2v.3h-.4"/>
<path d="M225.7 170.9l-.5 .2 .2 .2h.3M225.8 175.6l.4-.1v-.2h-.3l-.1 .1v.5h.4M225.8 169.5l.4-.1v-.2h-.3l-.1 .1v.5h.4M225.9 172.3l.3-.1 .1 .2v.4l-.3 .1-.1-.4 .4-.1M226 173.4v1M226.1 170.4v.1M226.1 170.7v.6M226.6 170.8l.3-.1 .1 .6M226.6 170.7v.6M226.7 169.8l-.1 .1M227 173.5h-.5a.39 .39 0 0 0 .4 .5v.3h-.5M227 175.3h-.2l-.2 .2 .1 .4h.3"/>
<path d="M227.2 172.2v.8l-.2 .2-.2-.1M227.2 172.3l-.3-.1-.2 .2 .1 .4h.4M227.3 173.4v.2M227.4 175h.1M227.4 175.3v.6M227.5 168.9l.3 .9 .3-.9M227.6 172.2v.7M227.7 173.4v.2M227.7 175.3h.4M227.9 172.2l-.3 .2M228 170.7h.4v.6M228.1 175l-.2 .1v.8"/>
<path d="M228.2 172.5l.4-.1v-.1l-.3-.1-.1 .2v.4h.4M228.4 169.5l.5-.1-.1-.2h-.3l-.1 .1 .1 .5h.3M228.4 170.9l-.4 .2 .1 .2h.3M228.4 175h.1M228.4 175.3v.6M228.6 173.4h.4l.1 .2-.1 .3 .2 .3-.2 .2h-.4zM228.6 173.9h.4M229 172.5l.4-.1v-.1l-.3-.1-.1 .2v.4h.4M229.3 169.2v.6M229.3 175.3h-.3l-.2 .2 .1 .4h.4M229.4 174.4l.4-1 .3 1M229.5 169.2l-.2 .2"/>
<path d="M229.5 174.1h.5M229.8 170.7h-.2l-.2 .2 .1 .4h.3M230.2 169.2l-.4 .1 .4 .2v.3h-.4M230.2 170.8h.4v.5l-.4-.1zM230.2 171.9v1l-.3-.1-.1-.5h.4M230.2 175v.8l.2 .1M230.6 168.9v.1M230.6 169.2v.6M230.7 175.3h.4v.6M230.9 173.5h-.5a.39 .39 0 0 0 .4 .5v.3h-.5M231.1 169.3h.4l-.1 .5-.3-.1zM231.1 170.7h.2l.2 .2-.1 .4h-.3"/>
<path d="M231.1 170.7v.9M231.1 172.2h.4M231.1 175.5l-.4 .2 .1 .2h.3M231.2 171.9v.8l.3 .2M231.3 173.4v1M231.6 175.4l.3-.1 .1 .6M231.6 175.3v.6M231.8 172.3h.4l-.1 .5h-.3zM231.8 170.7l.3 .6M231.9 169.3l.4-.1v.6M231.9 169.2v.6M232.1 171.3l-.3 .3"/>
<path d="M232.2 173.5h-.5a.39 .39 0 0 0 .5 .5l-.1 .3h-.4M232.3 170.7l-.2 .6M232.7 174.3l-.1 .2M232.8 175.3h-.2l-.2 .2 .1 .4h.3M232.8 175.3v.7l-.1 .2h-.3M233.2 171.9v.1M233.2 172.2v.7M233.2 170.8h.4v.5l-.4-.1zM233.3 169l.3-.1 .2 .2-.6 .7h.6M233.3 175.3v.6l.4-.1M233.6 173.4l.2 1 .2-.7 .1 .7 .3-1M233.6 172.2v.7"/>
<path d="M233.6 172.3h.4v.6M233.7 175.3v.6M233.9 170.7h.4M234.1 175.3h.4v.6M234.2 169.7v.1M234.3 170.4l-.2 .1v.8M234.5 175.5l-.4 .2 .1 .2h.3M234.6 169.8h.6M234.6 169.1l.3-.2v.9M234.7 173.4v1M235 172.2l.1 .7 .2-.5 .2 .5 .2-.7M235 170.7h.4"/>
<path d="M235 173.4h.6M235.2 170.4v.8l.2 .1M235.3 173.4v1M235.4 175.3v.7l-.2 .2h-.2M235.4 175.3h-.3l-.2 .2 .1 .4h.4M235.7 170.8l.4-.1v.6M235.7 170.4v.9M235.8 175.6l.4-.1v-.2h-.3l-.1 .1v.5h.4M235.9 173.9h.5M235.9 173.4v1M236 172.2v.7M236.3 172.2l-.3 .2"/>
<path d="M236.4 168.7a1.08 1.08 0 0 0 0 1.5M236.4 173.4v1M236.5 171l.5-.1-.1-.2h-.3l-.1 .1 .1 .5h.3M236.6 169.2h.4M236.6 171.9v.1M236.6 172.2v.7M236.8 168.9v.8l.2 .1M236.9 173.6l.1-.2 .4 .2v.5l-.1 .2-.4-.1zM236.9 172.2h.4M237.1 171.9v.8l.2 .2M237.3 169.3l.3-.1 .1 .6M237.3 168.9v.9"/>
<path d="M237.6 172h.1M237.6 175.3h-.3l-.1 .2 .1 .4h.3M237.6 175.3v.7l-.2 .2h-.2M237.6 172.2v.7M237.9 173.4v.8l.1 .2 .4-.2v-.8M237.9 170.4v.9h.5M238.1 175.4h.4l-.1 .5-.3-.1zM238.1 172.3h.3l.1 .6M238.1 172.2v.7M238.1 169.5l.4-.1v-.2h-.3l-.1 .1v.5h.4M238.7 170.4v.1M238.7 170.7v.6"/>
<path d="M238.7 173.4h.5M238.8 175.3l.2 .6 .3-.6M239 173.4v1M239.3 172.2v.8l-.2 .2-.2-.1M239.3 172.3l-.3-.1-.1 .2 .1 .4h.3M239.5 168.9v.1M239.5 170.7h-.2l-.2 .2 .1 .4h.3M239.6 175.6l.4-.1v-.2h-.3l-.1 .1v.5h.4M239.8 172.8v.1M239.8 172.9l-.1 .1M239.8 168.9v.1M239.9 171l.4-.1v-.2h-.3l-.1 .1v.5h.4"/>
<path d="M240 173.4l.3 1 .1-.7 .2 .7 .2-1M240.2 168.9v.9h.5M240.4 175.3v.6M240.7 175.3l-.3 .2M240.7 172.4l.4 .3-.1 .2-.3-.1M240.7 172.4h.1M240.7 170.8l.4-.1v.6M240.7 170.7v.6M241 168.9v.1M241 169.2v.6M241 175.4l.4-.1v.6M241 175.3v.6"/>
<path d="M241.1 174.4l.3-1 .3 1M241.1 172.3l-.4 .1M241.1 174.1h.5M241.5 172.3h.4v.5h-.4zM241.8 169.2h-.2l-.2 .2 .1 .4h.3M241.9 175h.1M241.9 175.3v.6M241.9 170.7l-.3 .1 .3 .3v.2h-.3M242 173.9h.4l.1-.4-.5-.1v1M242.2 169.5l.4-.1v-.2h-.3l-.1 .1v.5h.4M242.2 173.9l.3 .5M242.3 172.2h.3"/>
<path d="M242.3 175.3v.6M242.3 175.4l.4-.1v.6M242.3 171l.5-.1-.1-.2h-.3l-.1 .1 .1 .5h.3M242.6 171.9l-.2 .1v.9M242.8 172.2h.3M242.9 171.9v.8l.2 .2M242.9 173.9h.5v-.4l-.5-.1v1M243 169.3l.4-.1 .1 .6M243 169.2v.6M243.2 173.9l.3 .5M243.4 172.2l.2 .7 .1-.5 .2 .5 .2-.7M243.6 175.3h-.3l-.2 .2 .1 .4h.4"/>
<path d="M243.6 175.3v.7l-.2 .2h-.2M243.7 170.7h.4v.6M243.7 174.4l.4-1 .3 1M243.8 174.1h.5M244.1 170.9l-.4 .2 .1 .2h.3M244.2 169.2l-.3 .1 .3 .2v.3h-.3M244.4 170.7h.4M244.4 172.3l.3-.1 .1 .2v.4l-.3 .1-.1-.4 .4-.1M244.6 170.4v.8l.2 .1M244.6 169.5l.5-.1-.1-.2h-.2l-.2 .1 .1 .5h.3M245.2 173.4v1l-.5-1v1M245.3 172.2v.7"/>
<path d="M245.4 168.9v.1M245.5 173.4h.6M245.6 172.2l-.3 .2M245.8 168.9v.1M245.8 173.4v1M245.8 172.5l.5-.1-.1-.1-.2-.1-.2 .2 .1 .4h.3M246.1 168.7a1.08 1.08 0 0 1 0 1.5M246.4 173.4v1M246.7 172.8v.1M246.7 172.9l-.1 .1M246.8 169.2v.1M246.8 173.9h.4"/>
<path d="M246.9 169.8l-.1 .1M247.3 173.4h-.5v1h.5M248.2 173.5h-.5a.39 .39 0 0 0 .4 .5v.3h-.5M249.2 173.6l.1-.2 .4 .2v.5l-.1 .2-.4-.1zM250.1 173.9h.5v-.4l-.5-.1v1M250.4 173.9l.3 .5"/>
</g>
<path d="M128.1 51.7l.4-.1 .2 .3-.7 .9h.7M129.1 52l.3 .8 .3-.8M130.3 52.1l-.2-.2 .2-.3h.3l.2 .2-.2 .3M130.3 52.1l-.2 .2 .1 .4 .1 .1h.3l.2-.2-.1-.4-.1-.1M130.3 52.1h.3" fill="none" stroke="#000" stroke-width=".2"/>
<g fill="none" stroke="#848400" stroke-width=".2">
<path d="M122.4 75.8l-.4-.1-.2 .2 .1 .6h.5M122.9 75.8h.4l.1 .7M123.4 76l-.6 .2 .2 .3h.4M124 75.7v.8M124 75.8l.3-.1 .2 .2M124.5 75.9l.1-.2 .3 .1 .1 .7M124.5 75.9v.6M125.5 76.1l.6-.1-.1-.2-.3-.1-.2 .2 .1 .6h.4M126.6 75.7v.8M126.9 75.7l-.3 .2M127.3 75.8h.5v.7M127.8 76l-.5 .2 .1 .3h.4"/>
<path d="M128.1 76.6h.9M129.8 75.3v1.2M129.8 75.8l-.3-.1-.2 .2 .1 .6h.4M130.3 76.5h.7M130.3 75.7l.4-.4v1.2M131.4 75.5h.6l.6 .6-.6 .6h-.6zM119.7 82.9h-.3l-.3 .2 .1 .5h.5M120.2 82.9h.5v.8M120.4 87.7h-.4l-.2 .2 .1 .5h.5M120.7 83.2l-.6 .2 .2 .3 .4-.1M120.9 87.7h.4l.1 .8M121.3 83l.3-.1 .2 .2"/>
<path d="M121.3 82.9v.8M121.4 88l-.6 .2 .2 .3 .4-.1M121.5 85.3h-.3l-.3 .2 .2 .5h.4M121.8 83.1v.6M121.8 83.1l.2-.2h.3v.8M122 87.7v.8M122 87.8l.3-.1 .2 .1M122 85.3h.5v.8M122.4 99.7l-.4-.1-.2 .2 .1 .6h.5M122.4 90.1h-.4l-.2 .2 .1 .5h.5M122.4 80.6l-.4-.1-.2 .2 .1 .5h.5M122.4 97.3l-.4-.1-.2 .3 .1 .5h.5"/>
<path d="M122.5 87.8v.7M122.5 87.8l.2-.1h.2l.1 .8M122.5 85.6l-.5 .2 .1 .3 .4-.1M122.8 83.3l.6-.1-.1-.3h-.3l-.2 .2 .1 .5h.4M122.9 99.7h.4l.1 .7M122.9 80.6h.4l.1 .7M122.9 90.1h.4l.1 .8M122.9 97.3h.4l.1 .7M123.1 85.4l.3-.1 .2 .1M123.1 85.3v.8M123.4 99.9l-.6 .2 .2 .3h.4M123.4 80.8l-.6 .2 .2 .3 .4-.1"/>
<path d="M123.4 90.3l-.6 .3 .2 .3 .4-.1M123.4 97.5l-.6 .2 .2 .3h.4M123.5 88.1l.6-.1-.1-.3h-.3l-.2 .1 .1 .6h.4M123.6 85.4l.2-.1h.3v.8M123.6 85.4v.7M123.9 82.9v.8M124 99.7l.3-.1 .2 .2M124 80.5v.8M124 90.1v.8M124 97.2v.8M124 99.6v.8M124 90.2l.3-.1 .2 .1"/>
<path d="M124 97.3l.3-.1 .2 .2M124 80.6l.3-.1 .2 .2M124.2 82.9l-.3 .2M124.5 80.7l.1-.2 .3 .1 .1 .7M124.5 90.2l.1-.1h.3l.1 .8M124.5 97.4l.1-.2 .3 .1 .1 .7M124.5 99.8l.1-.2 .3 .1 .1 .7M124.5 80.7v.6M124.5 90.2v.7M124.5 97.4v.6M124.5 99.8v.6M124.6 87.7v.8"/>
<path d="M124.6 82.9h.5l.1 .8M124.6 85.7l.6-.1v-.3h-.4l-.2 .1 .1 .6h.5M124.9 87.7l-.3 .2M125.2 83.2l-.6 .2 .2 .3 .4-.1M125.3 87.7h.5v.8M125.4 83.8h1M125.5 80.9l.6-.1-.1-.2-.3-.1-.2 .2 .1 .5h.4M125.5 90.5l.6-.2-.1-.2h-.3l-.2 .1 .1 .6h.4M125.5 97.6l.6-.1-.1-.2-.3-.1-.2 .2 .1 .6h.4M125.7 85.3v.8M125.8 88l-.5 .2 .1 .3 .4-.1M126.1 85.3l-.4 .2"/>
<path d="M126.1 88.6h.9M126.5 85.3h.4l.1 .8M126.5 82.9l.3 .8 .3-.8M126.6 80.5v.8M126.6 90.1v.8M126.6 97.2v.8M126.6 99.6v.8M126.9 90.1l-.3 .2M126.9 97.2l-.3 .3M126.9 99.6l-.3 .2M126.9 80.5l-.3 .2M127 85.6l-.6 .2 .2 .3 .4-.1"/>
<path d="M127.3 86.2h.9M127.3 87.8l.4-.1 .1 .1M127.3 87.7v.8M127.3 80.6h.5v.7M127.3 90.1h.5v.8M127.3 97.3h.5v.7M127.3 99.7h.5v.7M127.8 87.8v.7M127.8 87.8l.2-.1h.3v.8M127.8 97.5l-.5 .2 .1 .3h.4M127.8 99.9l-.5 .2 .1 .3h.4M127.8 80.8l-.5 .2 .1 .3 .4-.1"/>
<path d="M127.8 90.3l-.5 .3 .1 .3 .4-.1M127.9 82.9h-.2l-.2 .2v.1l.4 .1v.3h-.4M128.1 91h.9M128.1 98.1h.9M128.1 81.4h.9M128.3 85.3h.4M128.4 82.9l.3 .8M128.5 84.9v1l.2 .2M128.7 83.7l-.3 .4M129 82.9l-.3 .8M129.1 85.3v.8M129.4 87.7h-.3l-.2 .2 .1 .5h.4"/>
<path d="M129.4 83l.5-.1v.8M129.4 82.9v.8M129.5 85.3l-.4 .2M129.8 99.7l-.3-.1-.2 .2 .1 .6h.4M129.8 90.1h-.3l-.2 .2 .1 .5h.4M129.8 97.3l-.3-.1-.2 .3 .1 .5h.4M129.8 80.1v1.2M129.8 89.7v1.2M129.8 96.8v1.2M129.8 99.2v1.2M129.8 80.6l-.3-.1-.2 .2 .1 .5h.4M129.9 84.9v.1"/>
<path d="M129.9 85.3v.8M129.9 87.3v1l.2 .2M130.3 99.2h.8l-.5 1.2M130.3 80.1h.7l-.4 .5 .4 .1v.5l-.2 .1-.5-.1M130.3 89.8l.5-.1 .2 .3-.7 .9h.7M130.6 87.3v1.2M130.6 96.8l-.3 .8h.8M130.7 88l.3 .5M130.9 97.2v.8M131 85.3h-.4l-.2 .2 .1 .5h.5M131 85.3v.9l-.3 .3-.3-.1M131 82.9h-.3l-.3 .2 .2 .5h.4"/>
<path d="M131 87.7l-.4 .4M131.4 80.3h.6l.6 .6-.6 .6h-.6zM131.4 82.6h.6l.6 .6-.6 .6h-.6zM131.4 85h.6l.6 .6-.6 .6h-.6zM131.4 87.4h.6l.6 .6-.6 .6h-.6zM131.4 89.8h.6l.6 .6-.6 .6h-.6zM131.4 97h.6l.6 .6-.6 .6h-.6zM131.4 99.4h.6l.6 .6-.6 .6h-.6zM119.5 106.8h-.3l-.2 .2 .1 .5h.4M120 106.8h.5v.8M120.5 107.1l-.5 .2 .1 .3 .4-.1M120.9 109.2h-.4l-.2 .2 .1 .5h.5"/>
<path d="M121.1 106.9l.4-.1 .1 .2M121.1 106.8v.8M121.4 109.2h.5v.8M121.6 107l.2-.2h.3v.8M121.6 107v.6M121.9 109.5l-.6 .2 .2 .3 .4-.1M122.3 111.6h-.4l-.2 .2 .1 .5h.5M122.4 102.1l-.4-.1-.2 .2 .1 .5h.5M122.4 114h-.4l-.2 .2 .1 .5h.5M122.4 116.4l-.4-.1-.2 .3 .1 .5h.5M122.5 109.3l.3-.1 .2 .1M122.5 109.2v.8"/>
<path d="M122.7 107.2l.5-.1v-.3h-.4l-.1 .2v.5h.5M122.8 111.6h.4l.1 .8M122.9 102.1h.4l.1 .7M122.9 114h.4l.1 .7M122.9 116.4h.4l.1 .7M123 109.3l.2-.1h.2l.1 .8M123 109.3v.7M123.3 111.8l-.6 .3 .2 .3 .4-.1M123.4 102.3l-.6 .2 .2 .3 .4-.1M123.4 114.2l-.6 .3 .2 .2h.4M123.4 116.6l-.6 .3 .2 .2h.4M123.7 106.8v.8"/>
<path d="M123.8 111.7l.4-.1 .2 .1M123.8 111.6v.8M124 102v.8M124 114v.7M124 116.3v.8M124 102.1l.3-.1 .2 .2M124 114.1l.3-.1 .2 .1M124 116.5l.3-.2 .2 .2M124 109.6l.6-.1-.1-.3h-.3l-.2 .1 .1 .6h.4M124.1 106.8l-.4 .2M124.4 111.7l.1-.1h.3l.1 .8M124.4 111.7v.7"/>
<path d="M124.5 106.8h.4l.1 .8M124.5 102.2l.1-.2 .3 .1 .1 .7M124.5 114.1l.1-.1h.3l.1 .7M124.5 116.5l.1-.2 .3 .1 .1 .7M124.5 102.2v.6M124.5 114.1v.6M124.5 116.5v.6M125 107.1l-.6 .2 .2 .3 .4-.1M125.1 109.2v.8M125.3 118.3v.1M125.3 118.7v.8M125.3 107.7h.9"/>
<path d="M125.4 112l.6-.2-.1-.2h-.3l-.2 .1v.6h.5M125.4 109.2l-.3 .2M125.5 100l.6-.1-.1-.2-.3-.1-.2 .2 .1 .6h.4M125.5 102.4l.6-.1-.1-.2-.3-.1-.2 .2 .1 .5h.4M125.5 114.3l.6-.1-.1-.2h-.3l-.2 .1 .1 .6h.4M125.5 116.7l.6-.1-.1-.2-.3-.1-.2 .2 .1 .6h.4M125.8 118.4l.4-.1 .3 .4-.8 .8h.8M125.8 109.2h.5l.1 .8M126.4 109.5l-.6 .2 .2 .3 .4-.1M126.5 106.9l.4-.1 .1 .8M126.5 106.4v1.2M126.5 111.6v.8"/>
<path d="M126.6 102v.8M126.6 114v.7M126.6 116.3v.8M126.6 110.1h.9M126.8 111.6l-.3 .2M126.9 102l-.3 .2M126.9 114l-.3 .2M126.9 116.3l-.3 .3M127.2 111.6h.5v.8M127.3 102.1h.5v.7M127.3 114h.5v.7M127.3 116.4h.5v.7"/>
<path d="M127.5 118.8l-.4-.1-.2 .3 .1 .5h.5M127.7 111.8l-.6 .3 .2 .3 .4-.1M127.7 119.6h.9M127.8 109.2h.4l.2 .2-.1 .5h-.5M127.8 109.2v1.2M127.8 102.3l-.5 .2 .1 .3 .4-.1M127.8 114.2l-.5 .3 .1 .2h.4M127.8 116.6l-.5 .3 .1 .2h.4M127.9 106.8h-.2l-.2 .2v.1l.4 .1v.3h-.4M128 112.5h.9M128.1 100.5h.9M128.1 102.9h.9"/>
<path d="M128.1 117.3h.9M128.1 114.9h.9M128.4 106.8l.3 .8M128.7 107.6l-.3 .4M129 106.8l-.3 .8M129.2 111.2v.1M129.2 111.6v.8M129.3 118.8l-.3-.1-.1 .2v.2l.4 .1v.3h-.4M129.4 109.2h-.3l-.2 .2 .1 .5h.4M129.4 106.9l.5-.1v.8M129.4 106.8v.8M129.8 111.7l.4-.1 .1 .8"/>
<path d="M129.8 111.6v.8M129.8 102.1l-.3-.1-.2 .2 .1 .5h.4M129.8 101.6v1.2M129.8 113.6v1.1M129.8 115.9v1.2M129.8 114h-.3l-.2 .2 .1 .5h.4M129.8 116.4l-.3-.1-.2 .3 .1 .5h.4M129.9 108.8v1l.2 .2M130.4 118.8l-.4-.1-.2 .3 .1 .5h.5M130.4 101.7l.2-.1a.64 .64 0 0 1 .4 .6 .64 .64 0 0 1-.4 .6l-.3-.5zM130.6 108.8v1.2M130.7 109.5l.3 .5"/>
<path d="M130.7 111.6h.4M130.8 111.2v1l.3 .2M130.9 113.6h-.3l-.2 .2-.1 .7 .3 .2 .4-.1-.1-.5-.3-.1-.3 .2M130.9 118.3v1.1l.2 .1M131 115.9h-.6l-.1 .6h.6l.1 .5-.2 .1-.5-.1M131 106.8h-.3l-.3 .2 .2 .5h.4M131 109.2l-.4 .4M131.4 108.9h.6l.6 .6-.6 .6h-.6zM131.4 101.8h.6l.6 .6-.6 .6h-.6zM131.4 106.5h.6l.6 .6-.6 .6h-.6zM131.4 111.3h.6l.6 .6-.6 .6h-.6zM131.4 113.7h.6l.6 .6-.6 .6h-.6z"/>
<path d="M131.4 116.1h.6l.6 .6-.6 .6h-.6zM131.4 118.5h.6l.6 .6-.6 .6h-.6zM124.8 120.7v.1M124.8 121.1v.8M125.3 120.8l.4-.1 .3 .4-.8 .8h.8M127 121.2l-.4-.1-.2 .2 .1 .6h.5M127.2 122h.9M128.8 121.2l-.3-.1-.2 .2 .1 .2 .4 .1v.3h-.5M129.9 120.7v1.2M129.9 121.2l-.4-.1-.2 .2 .1 .6h.5M130.4 121.2h.5l.1 .7M131 121.4l-.6 .2 .2 .3h.4"/>
<path d="M131.4 120.9h.6l.6 .6-.6 .6h-.6z"/>
</g>
<g fill="none" stroke="#008484" stroke-width=".2">
<path d="M95.6 50h.9M96 49.5v1M96.9 49.3h.8l-.4 .4 .3 .1v.5l-.1 .2-.6-.2M98.2 50.3v.2M98.7 49.3h.7l-.4 .4 .3 .1v.5l-.1 .2-.5-.2M99.7 49.3l.4 1.2 .4-1.2M100.5 58.2l.3-.4v1.2M100.5 59h.6M101.2 55.5a.53 .53 0 0 0-.8 .5 .53 .53 0 0 0 .8 .5M101.6 55.4h.7l-.4 .5 .4 .1v.5l-.2 .1-.5-.1M101.6 58.2l.1 .8 .5-.1M102.2 58.2v.8"/>
<path d="M102.7 58.4h.4M103.3 57.8h-.6v1.2M103.4 55.4l-.4 .1-.2 .2v.7l.2 .2 .4-.1v-.6h-.4l-.2 .2M105.1 50.9l.4-1.2 .4 1.2M105.2 50.6h.6M106.3 50.4l.5-.1 .1-.5-.6-.1v1.2M106.7 52.6l.4 1.2 .4-1.2M106.9 55.6h.4M107.4 49.8l.5-.1 .2 .4-.7 .8h.7M107.4 55h-.5v1.2h.5M107.9 52.6v1.2M108.6 50.1l.3-.4v1.2"/>
<path d="M108.6 50.9h.6M108.6 55v1.2l-.7-1.2v1.2M109.1 52.6v1.2l-.7-1.2v1.2M109.6 47.3v1l.3 .2h.3l.1-.2v-1M109.7 49.8l.4-.1 .3 .4-.8 .8h.8M110.4 58.1h1.2l-1.2 .7h1.2M110.4 59.4a.54 .54 0 0 0 .6 .7 .54 .54 0 0 0 .4-.8h-.4v.3M110.5 57a.62 .62 0 0 1 .7-.1 .62 .62 0 0 1 .4 .7h-1.2zM110.8 49.7h.8l-.5 1.2M110.8 48.5h.7M110.8 47.7l.4-.4v1.2M111.3 52.6l.4 1.2 .4-1.2"/>
<path d="M112 47.5l.4-.2 .2 .4-.7 .8h.7M112 49.7v1.2M112.2 50.2l.5 .7M112.5 52.8l.3-.2a.4 .4 0 0 1 .5 .4v.4a.4 .4 0 0 1-.4 .4 .4 .4 0 0 1-.4-.4zM112.7 49.7l-.7 .7M113.2 50.5h.9M113.8 52.6v1l.2 .2h.3l.2-.2v-1M114.6 49.8l.5-.1 .2 .4-.7 .8h.7M114.9 52.6h.6M115.2 52.6v1.2M115.8 50.8v.1M116.6 50.2l-.3-.2 .3-.3h.2l.2 .3-.2 .2"/>
<path d="M116.6 50.2l-.3 .3 .1 .3 .2 .1h.2l.2-.2v-.3l-.2-.2M116.6 50.2h.2M124.3 59h.7M124.3 58.2l.4-.4v1.2M125.1 55.5a.53 .53 0 0 0-.8 .5 .53 .53 0 0 0 .8 .5M125.5 55.4h.7l-.4 .5 .4 .1v.5l-.2 .1-.5-.1M125.5 58.2l.1 .8 .5-.1M126.1 58.2v.8M126.6 58.4h.4M126.6 55.4h.8l-.5 1.2M127.2 57.8h-.6v1.2M140.1 45.2h.9"/>
<path d="M140.5 44.8v.9M141.5 45.7h.7M141.5 44.8l.3-.3v1.2M142.5 44.5l.4 1.2 .4-1.2M143.9 45l-.2 .2v.4l.2 .1h.2l.2-.3v-.2l-.2-.2M143.9 45l-.2-.2 .2-.3h.2l.2 .2-.2 .3M143.9 45h.2M107.8 66.4a.54 .54 0 0 0-.7 .6 .54 .54 0 0 0 .8 .4v-.4h-.3M109.1 66.4v1.2l-.7-1.2v1.2M109.6 66.4a.6 .6 0 0 1 .7 .6 .6 .6 0 0 1-.7 .6zM155.5 97.2v1.1l-.4 .1M155.9 99.7a.53 .53 0 0 0-.8 .5 .53 .53 0 0 0 .8 .5"/>
<path d="M156.6 97.2l-.3 .1-.2 .2-.1 .7 .3 .2 .4-.1-.1-.6h-.3l-.3 .2M160.6 99.7l.2-.1a.64 .64 0 0 1 .4 .6 .64 .64 0 0 1-.4 .6l-.3-.4zM161.6 100l.4-.4v1.2M163.7 99.7l.5-.1 .2 .4-.7 .8h.7M165.1 99.6l-.2 .8h.7M156.4 100.1l.2-.1 .3 .1-.1 .7-.4-.1zM157.5 100.1h.4l.1 .7M157.5 100v.8M158.5 100.1h.5l.1 .7M158.5 100v.8M159.3 100.9h1M161.6 100.8h.7"/>
<path d="M162.7 100l.6 .8M163.3 100l-.6 .8M165.4 100v.8M144.8 133.3a.54 .54 0 0 0-.6 .6 .54 .54 0 0 0 .7 .4v-.4h-.2M146.1 133.3v1.2l-.7-1.2v1.2M146.7 133.3a.6 .6 0 0 1 .7 .6 .6 .6 0 0 1-.7 .6z"/>
</g>
<path d="M96.5 57.4h2.9M120.4 57.4h2.9" fill="none" stroke="#840000" stroke-width=".31"/>
<path d="M96.5 56.5h2.9M120.4 56.5h2.9" fill="none" stroke="#840000" stroke-width=".29"/>
<g fill="#008400" stroke="#008400" stroke-width=".35">
<circle cx="145.8" cy="104.8" r=".43"/>
<circle cx="121.9" cy="53.4" r=".43"/>
<circle cx="111.1" cy="62.9" r=".43"/>
<circle cx="102.7" cy="53.4" r=".43"/>
<circle cx="98" cy="53.4" r=".43"/>
<circle cx="108.7" cy="62.9" r=".43"/>
<circle cx="144.6" cy="78.5" r=".43"/>
</g>
</svg>
